VERSION 5.8 ;
BUSBITCHARS "[]" ;
DIVIDERCHAR "/" ;
UNITS
    DATABASE MICRONS 1000 ;
END UNITS

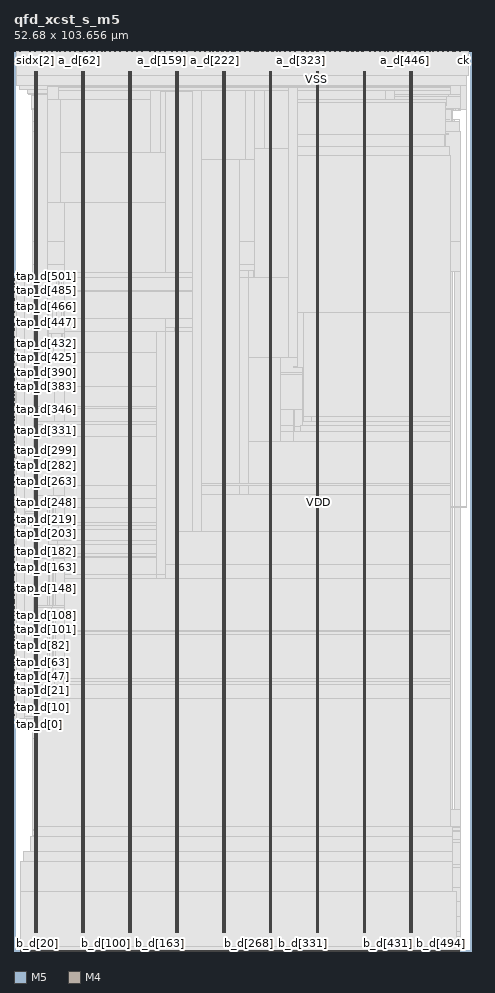
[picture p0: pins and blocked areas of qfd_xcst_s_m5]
MACRO qfd_xcst_s_m5
  FOREIGN qfd_xcst_s_m5 0 0 ;
  CLASS BLOCK ;
  SIZE 52.68 BY 103.656 ;
  PIN a_d[0]
    DIRECTION INPUT ;
    USE SIGNAL ;
    PORT
      LAYER M5 ;
        RECT  1.44 103.572 1.464 103.656 ;
    END
  END a_d[0]
  PIN a_d[100]
    DIRECTION INPUT ;
    USE SIGNAL ;
    PORT
      LAYER M5 ;
        RECT  11.232 103.572 11.256 103.656 ;
    END
  END a_d[100]
  PIN a_d[101]
    DIRECTION INPUT ;
    USE SIGNAL ;
    PORT
      LAYER M5 ;
        RECT  11.328 103.572 11.352 103.656 ;
    END
  END a_d[101]
  PIN a_d[102]
    DIRECTION INPUT ;
    USE SIGNAL ;
    PORT
      LAYER M5 ;
        RECT  11.424 103.572 11.448 103.656 ;
    END
  END a_d[102]
  PIN a_d[103]
    DIRECTION INPUT ;
    USE SIGNAL ;
    PORT
      LAYER M5 ;
        RECT  11.52 103.572 11.544 103.656 ;
    END
  END a_d[103]
  PIN a_d[104]
    DIRECTION INPUT ;
    USE SIGNAL ;
    PORT
      LAYER M5 ;
        RECT  11.616 103.572 11.64 103.656 ;
    END
  END a_d[104]
  PIN a_d[105]
    DIRECTION INPUT ;
    USE SIGNAL ;
    PORT
      LAYER M5 ;
        RECT  11.712 103.572 11.736 103.656 ;
    END
  END a_d[105]
  PIN a_d[106]
    DIRECTION INPUT ;
    USE SIGNAL ;
    PORT
      LAYER M5 ;
        RECT  11.808 103.572 11.832 103.656 ;
    END
  END a_d[106]
  PIN a_d[107]
    DIRECTION INPUT ;
    USE SIGNAL ;
    PORT
      LAYER M5 ;
        RECT  11.904 103.572 11.928 103.656 ;
    END
  END a_d[107]
  PIN a_d[108]
    DIRECTION INPUT ;
    USE SIGNAL ;
    PORT
      LAYER M5 ;
        RECT  12 103.572 12.024 103.656 ;
    END
  END a_d[108]
  PIN a_d[109]
    DIRECTION INPUT ;
    USE SIGNAL ;
    PORT
      LAYER M5 ;
        RECT  12.096 103.572 12.12 103.656 ;
    END
  END a_d[109]
  PIN a_d[10]
    DIRECTION INPUT ;
    USE SIGNAL ;
    PORT
      LAYER M5 ;
        RECT  2.4 103.572 2.424 103.656 ;
    END
  END a_d[10]
  PIN a_d[110]
    DIRECTION INPUT ;
    USE SIGNAL ;
    PORT
      LAYER M5 ;
        RECT  12.192 103.572 12.216 103.656 ;
    END
  END a_d[110]
  PIN a_d[111]
    DIRECTION INPUT ;
    USE SIGNAL ;
    PORT
      LAYER M5 ;
        RECT  12.288 103.572 12.312 103.656 ;
    END
  END a_d[111]
  PIN a_d[112]
    DIRECTION INPUT ;
    USE SIGNAL ;
    PORT
      LAYER M5 ;
        RECT  12.384 103.572 12.408 103.656 ;
    END
  END a_d[112]
  PIN a_d[113]
    DIRECTION INPUT ;
    USE SIGNAL ;
    PORT
      LAYER M5 ;
        RECT  12.48 103.572 12.504 103.656 ;
    END
  END a_d[113]
  PIN a_d[114]
    DIRECTION INPUT ;
    USE SIGNAL ;
    PORT
      LAYER M5 ;
        RECT  12.576 103.572 12.6 103.656 ;
    END
  END a_d[114]
  PIN a_d[115]
    DIRECTION INPUT ;
    USE SIGNAL ;
    PORT
      LAYER M5 ;
        RECT  12.672 103.572 12.696 103.656 ;
    END
  END a_d[115]
  PIN a_d[116]
    DIRECTION INPUT ;
    USE SIGNAL ;
    PORT
      LAYER M5 ;
        RECT  12.816 103.572 12.84 103.656 ;
    END
  END a_d[116]
  PIN a_d[117]
    DIRECTION INPUT ;
    USE SIGNAL ;
    PORT
      LAYER M5 ;
        RECT  12.912 103.572 12.936 103.656 ;
    END
  END a_d[117]
  PIN a_d[118]
    DIRECTION INPUT ;
    USE SIGNAL ;
    PORT
      LAYER M5 ;
        RECT  13.008 103.572 13.032 103.656 ;
    END
  END a_d[118]
  PIN a_d[119]
    DIRECTION INPUT ;
    USE SIGNAL ;
    PORT
      LAYER M5 ;
        RECT  13.104 103.572 13.128 103.656 ;
    END
  END a_d[119]
  PIN a_d[11]
    DIRECTION INPUT ;
    USE SIGNAL ;
    PORT
      LAYER M5 ;
        RECT  2.496 103.572 2.52 103.656 ;
    END
  END a_d[11]
  PIN a_d[120]
    DIRECTION INPUT ;
    USE SIGNAL ;
    PORT
      LAYER M5 ;
        RECT  13.2 103.572 13.224 103.656 ;
    END
  END a_d[120]
  PIN a_d[121]
    DIRECTION INPUT ;
    USE SIGNAL ;
    PORT
      LAYER M5 ;
        RECT  13.296 103.572 13.32 103.656 ;
    END
  END a_d[121]
  PIN a_d[122]
    DIRECTION INPUT ;
    USE SIGNAL ;
    PORT
      LAYER M5 ;
        RECT  13.392 103.572 13.416 103.656 ;
    END
  END a_d[122]
  PIN a_d[123]
    DIRECTION INPUT ;
    USE SIGNAL ;
    PORT
      LAYER M5 ;
        RECT  13.488 103.572 13.512 103.656 ;
    END
  END a_d[123]
  PIN a_d[124]
    DIRECTION INPUT ;
    USE SIGNAL ;
    PORT
      LAYER M5 ;
        RECT  13.584 103.572 13.608 103.656 ;
    END
  END a_d[124]
  PIN a_d[125]
    DIRECTION INPUT ;
    USE SIGNAL ;
    PORT
      LAYER M5 ;
        RECT  13.68 103.572 13.704 103.656 ;
    END
  END a_d[125]
  PIN a_d[126]
    DIRECTION INPUT ;
    USE SIGNAL ;
    PORT
      LAYER M5 ;
        RECT  13.776 103.572 13.8 103.656 ;
    END
  END a_d[126]
  PIN a_d[127]
    DIRECTION INPUT ;
    USE SIGNAL ;
    PORT
      LAYER M5 ;
        RECT  13.872 103.572 13.896 103.656 ;
    END
  END a_d[127]
  PIN a_d[128]
    DIRECTION INPUT ;
    USE SIGNAL ;
    PORT
      LAYER M5 ;
        RECT  13.968 103.572 13.992 103.656 ;
    END
  END a_d[128]
  PIN a_d[129]
    DIRECTION INPUT ;
    USE SIGNAL ;
    PORT
      LAYER M5 ;
        RECT  14.064 103.572 14.088 103.656 ;
    END
  END a_d[129]
  PIN a_d[12]
    DIRECTION INPUT ;
    USE SIGNAL ;
    PORT
      LAYER M5 ;
        RECT  2.592 103.572 2.616 103.656 ;
    END
  END a_d[12]
  PIN a_d[130]
    DIRECTION INPUT ;
    USE SIGNAL ;
    PORT
      LAYER M5 ;
        RECT  14.16 103.572 14.184 103.656 ;
    END
  END a_d[130]
  PIN a_d[131]
    DIRECTION INPUT ;
    USE SIGNAL ;
    PORT
      LAYER M5 ;
        RECT  14.256 103.572 14.28 103.656 ;
    END
  END a_d[131]
  PIN a_d[132]
    DIRECTION INPUT ;
    USE SIGNAL ;
    PORT
      LAYER M5 ;
        RECT  14.352 103.572 14.376 103.656 ;
    END
  END a_d[132]
  PIN a_d[133]
    DIRECTION INPUT ;
    USE SIGNAL ;
    PORT
      LAYER M5 ;
        RECT  14.448 103.572 14.472 103.656 ;
    END
  END a_d[133]
  PIN a_d[134]
    DIRECTION INPUT ;
    USE SIGNAL ;
    PORT
      LAYER M5 ;
        RECT  14.544 103.572 14.568 103.656 ;
    END
  END a_d[134]
  PIN a_d[135]
    DIRECTION INPUT ;
    USE SIGNAL ;
    PORT
      LAYER M5 ;
        RECT  14.64 103.572 14.664 103.656 ;
    END
  END a_d[135]
  PIN a_d[136]
    DIRECTION INPUT ;
    USE SIGNAL ;
    PORT
      LAYER M5 ;
        RECT  14.736 103.572 14.76 103.656 ;
    END
  END a_d[136]
  PIN a_d[137]
    DIRECTION INPUT ;
    USE SIGNAL ;
    PORT
      LAYER M5 ;
        RECT  14.832 103.572 14.856 103.656 ;
    END
  END a_d[137]
  PIN a_d[138]
    DIRECTION INPUT ;
    USE SIGNAL ;
    PORT
      LAYER M5 ;
        RECT  14.928 103.572 14.952 103.656 ;
    END
  END a_d[138]
  PIN a_d[139]
    DIRECTION INPUT ;
    USE SIGNAL ;
    PORT
      LAYER M5 ;
        RECT  15.024 103.572 15.048 103.656 ;
    END
  END a_d[139]
  PIN a_d[13]
    DIRECTION INPUT ;
    USE SIGNAL ;
    PORT
      LAYER M5 ;
        RECT  2.736 103.572 2.76 103.656 ;
    END
  END a_d[13]
  PIN a_d[140]
    DIRECTION INPUT ;
    USE SIGNAL ;
    PORT
      LAYER M5 ;
        RECT  15.12 103.572 15.144 103.656 ;
    END
  END a_d[140]
  PIN a_d[141]
    DIRECTION INPUT ;
    USE SIGNAL ;
    PORT
      LAYER M5 ;
        RECT  15.216 103.572 15.24 103.656 ;
    END
  END a_d[141]
  PIN a_d[142]
    DIRECTION INPUT ;
    USE SIGNAL ;
    PORT
      LAYER M5 ;
        RECT  15.36 103.572 15.384 103.656 ;
    END
  END a_d[142]
  PIN a_d[143]
    DIRECTION INPUT ;
    USE SIGNAL ;
    PORT
      LAYER M5 ;
        RECT  15.456 103.572 15.48 103.656 ;
    END
  END a_d[143]
  PIN a_d[144]
    DIRECTION INPUT ;
    USE SIGNAL ;
    PORT
      LAYER M5 ;
        RECT  15.552 103.572 15.576 103.656 ;
    END
  END a_d[144]
  PIN a_d[145]
    DIRECTION INPUT ;
    USE SIGNAL ;
    PORT
      LAYER M5 ;
        RECT  15.648 103.572 15.672 103.656 ;
    END
  END a_d[145]
  PIN a_d[146]
    DIRECTION INPUT ;
    USE SIGNAL ;
    PORT
      LAYER M5 ;
        RECT  15.744 103.572 15.768 103.656 ;
    END
  END a_d[146]
  PIN a_d[147]
    DIRECTION INPUT ;
    USE SIGNAL ;
    PORT
      LAYER M5 ;
        RECT  15.84 103.572 15.864 103.656 ;
    END
  END a_d[147]
  PIN a_d[148]
    DIRECTION INPUT ;
    USE SIGNAL ;
    PORT
      LAYER M5 ;
        RECT  15.936 103.572 15.96 103.656 ;
    END
  END a_d[148]
  PIN a_d[149]
    DIRECTION INPUT ;
    USE SIGNAL ;
    PORT
      LAYER M5 ;
        RECT  16.032 103.572 16.056 103.656 ;
    END
  END a_d[149]
  PIN a_d[14]
    DIRECTION INPUT ;
    USE SIGNAL ;
    PORT
      LAYER M5 ;
        RECT  2.832 103.572 2.856 103.656 ;
    END
  END a_d[14]
  PIN a_d[150]
    DIRECTION INPUT ;
    USE SIGNAL ;
    PORT
      LAYER M5 ;
        RECT  16.128 103.572 16.152 103.656 ;
    END
  END a_d[150]
  PIN a_d[151]
    DIRECTION INPUT ;
    USE SIGNAL ;
    PORT
      LAYER M5 ;
        RECT  16.224 103.572 16.248 103.656 ;
    END
  END a_d[151]
  PIN a_d[152]
    DIRECTION INPUT ;
    USE SIGNAL ;
    PORT
      LAYER M5 ;
        RECT  16.32 103.572 16.344 103.656 ;
    END
  END a_d[152]
  PIN a_d[153]
    DIRECTION INPUT ;
    USE SIGNAL ;
    PORT
      LAYER M5 ;
        RECT  16.416 103.572 16.44 103.656 ;
    END
  END a_d[153]
  PIN a_d[154]
    DIRECTION INPUT ;
    USE SIGNAL ;
    PORT
      LAYER M5 ;
        RECT  16.512 103.572 16.536 103.656 ;
    END
  END a_d[154]
  PIN a_d[155]
    DIRECTION INPUT ;
    USE SIGNAL ;
    PORT
      LAYER M5 ;
        RECT  16.608 103.572 16.632 103.656 ;
    END
  END a_d[155]
  PIN a_d[156]
    DIRECTION INPUT ;
    USE SIGNAL ;
    PORT
      LAYER M5 ;
        RECT  16.704 103.572 16.728 103.656 ;
    END
  END a_d[156]
  PIN a_d[157]
    DIRECTION INPUT ;
    USE SIGNAL ;
    PORT
      LAYER M5 ;
        RECT  16.8 103.572 16.824 103.656 ;
    END
  END a_d[157]
  PIN a_d[158]
    DIRECTION INPUT ;
    USE SIGNAL ;
    PORT
      LAYER M5 ;
        RECT  16.896 103.572 16.92 103.656 ;
    END
  END a_d[158]
  PIN a_d[159]
    DIRECTION INPUT ;
    USE SIGNAL ;
    PORT
      LAYER M5 ;
        RECT  16.992 103.572 17.016 103.656 ;
    END
  END a_d[159]
  PIN a_d[15]
    DIRECTION INPUT ;
    USE SIGNAL ;
    PORT
      LAYER M5 ;
        RECT  2.928 103.572 2.952 103.656 ;
    END
  END a_d[15]
  PIN a_d[160]
    DIRECTION INPUT ;
    USE SIGNAL ;
    PORT
      LAYER M5 ;
        RECT  17.088 103.572 17.112 103.656 ;
    END
  END a_d[160]
  PIN a_d[161]
    DIRECTION INPUT ;
    USE SIGNAL ;
    PORT
      LAYER M5 ;
        RECT  17.184 103.572 17.208 103.656 ;
    END
  END a_d[161]
  PIN a_d[162]
    DIRECTION INPUT ;
    USE SIGNAL ;
    PORT
      LAYER M5 ;
        RECT  17.28 103.572 17.304 103.656 ;
    END
  END a_d[162]
  PIN a_d[163]
    DIRECTION INPUT ;
    USE SIGNAL ;
    PORT
      LAYER M5 ;
        RECT  17.376 103.572 17.4 103.656 ;
    END
  END a_d[163]
  PIN a_d[164]
    DIRECTION INPUT ;
    USE SIGNAL ;
    PORT
      LAYER M5 ;
        RECT  17.472 103.572 17.496 103.656 ;
    END
  END a_d[164]
  PIN a_d[165]
    DIRECTION INPUT ;
    USE SIGNAL ;
    PORT
      LAYER M5 ;
        RECT  17.568 103.572 17.592 103.656 ;
    END
  END a_d[165]
  PIN a_d[166]
    DIRECTION INPUT ;
    USE SIGNAL ;
    PORT
      LAYER M5 ;
        RECT  17.664 103.572 17.688 103.656 ;
    END
  END a_d[166]
  PIN a_d[167]
    DIRECTION INPUT ;
    USE SIGNAL ;
    PORT
      LAYER M5 ;
        RECT  17.808 103.572 17.832 103.656 ;
    END
  END a_d[167]
  PIN a_d[168]
    DIRECTION INPUT ;
    USE SIGNAL ;
    PORT
      LAYER M5 ;
        RECT  17.904 103.572 17.928 103.656 ;
    END
  END a_d[168]
  PIN a_d[169]
    DIRECTION INPUT ;
    USE SIGNAL ;
    PORT
      LAYER M5 ;
        RECT  18 103.572 18.024 103.656 ;
    END
  END a_d[169]
  PIN a_d[16]
    DIRECTION INPUT ;
    USE SIGNAL ;
    PORT
      LAYER M5 ;
        RECT  3.024 103.572 3.048 103.656 ;
    END
  END a_d[16]
  PIN a_d[170]
    DIRECTION INPUT ;
    USE SIGNAL ;
    PORT
      LAYER M5 ;
        RECT  18.096 103.572 18.12 103.656 ;
    END
  END a_d[170]
  PIN a_d[171]
    DIRECTION INPUT ;
    USE SIGNAL ;
    PORT
      LAYER M5 ;
        RECT  18.192 103.572 18.216 103.656 ;
    END
  END a_d[171]
  PIN a_d[172]
    DIRECTION INPUT ;
    USE SIGNAL ;
    PORT
      LAYER M5 ;
        RECT  18.288 103.572 18.312 103.656 ;
    END
  END a_d[172]
  PIN a_d[173]
    DIRECTION INPUT ;
    USE SIGNAL ;
    PORT
      LAYER M5 ;
        RECT  18.384 103.572 18.408 103.656 ;
    END
  END a_d[173]
  PIN a_d[174]
    DIRECTION INPUT ;
    USE SIGNAL ;
    PORT
      LAYER M5 ;
        RECT  18.48 103.572 18.504 103.656 ;
    END
  END a_d[174]
  PIN a_d[175]
    DIRECTION INPUT ;
    USE SIGNAL ;
    PORT
      LAYER M5 ;
        RECT  18.576 103.572 18.6 103.656 ;
    END
  END a_d[175]
  PIN a_d[176]
    DIRECTION INPUT ;
    USE SIGNAL ;
    PORT
      LAYER M5 ;
        RECT  18.672 103.572 18.696 103.656 ;
    END
  END a_d[176]
  PIN a_d[177]
    DIRECTION INPUT ;
    USE SIGNAL ;
    PORT
      LAYER M5 ;
        RECT  18.768 103.572 18.792 103.656 ;
    END
  END a_d[177]
  PIN a_d[178]
    DIRECTION INPUT ;
    USE SIGNAL ;
    PORT
      LAYER M5 ;
        RECT  18.864 103.572 18.888 103.656 ;
    END
  END a_d[178]
  PIN a_d[179]
    DIRECTION INPUT ;
    USE SIGNAL ;
    PORT
      LAYER M5 ;
        RECT  18.96 103.572 18.984 103.656 ;
    END
  END a_d[179]
  PIN a_d[17]
    DIRECTION INPUT ;
    USE SIGNAL ;
    PORT
      LAYER M5 ;
        RECT  3.12 103.572 3.144 103.656 ;
    END
  END a_d[17]
  PIN a_d[180]
    DIRECTION INPUT ;
    USE SIGNAL ;
    PORT
      LAYER M5 ;
        RECT  19.056 103.572 19.08 103.656 ;
    END
  END a_d[180]
  PIN a_d[181]
    DIRECTION INPUT ;
    USE SIGNAL ;
    PORT
      LAYER M5 ;
        RECT  19.152 103.572 19.176 103.656 ;
    END
  END a_d[181]
  PIN a_d[182]
    DIRECTION INPUT ;
    USE SIGNAL ;
    PORT
      LAYER M5 ;
        RECT  19.248 103.572 19.272 103.656 ;
    END
  END a_d[182]
  PIN a_d[183]
    DIRECTION INPUT ;
    USE SIGNAL ;
    PORT
      LAYER M5 ;
        RECT  19.344 103.572 19.368 103.656 ;
    END
  END a_d[183]
  PIN a_d[184]
    DIRECTION INPUT ;
    USE SIGNAL ;
    PORT
      LAYER M5 ;
        RECT  19.44 103.572 19.464 103.656 ;
    END
  END a_d[184]
  PIN a_d[185]
    DIRECTION INPUT ;
    USE SIGNAL ;
    PORT
      LAYER M5 ;
        RECT  19.536 103.572 19.56 103.656 ;
    END
  END a_d[185]
  PIN a_d[186]
    DIRECTION INPUT ;
    USE SIGNAL ;
    PORT
      LAYER M5 ;
        RECT  19.632 103.572 19.656 103.656 ;
    END
  END a_d[186]
  PIN a_d[187]
    DIRECTION INPUT ;
    USE SIGNAL ;
    PORT
      LAYER M5 ;
        RECT  19.728 103.572 19.752 103.656 ;
    END
  END a_d[187]
  PIN a_d[188]
    DIRECTION INPUT ;
    USE SIGNAL ;
    PORT
      LAYER M5 ;
        RECT  19.824 103.572 19.848 103.656 ;
    END
  END a_d[188]
  PIN a_d[189]
    DIRECTION INPUT ;
    USE SIGNAL ;
    PORT
      LAYER M5 ;
        RECT  19.92 103.572 19.944 103.656 ;
    END
  END a_d[189]
  PIN a_d[18]
    DIRECTION INPUT ;
    USE SIGNAL ;
    PORT
      LAYER M5 ;
        RECT  3.216 103.572 3.24 103.656 ;
    END
  END a_d[18]
  PIN a_d[190]
    DIRECTION INPUT ;
    USE SIGNAL ;
    PORT
      LAYER M5 ;
        RECT  20.016 103.572 20.04 103.656 ;
    END
  END a_d[190]
  PIN a_d[191]
    DIRECTION INPUT ;
    USE SIGNAL ;
    PORT
      LAYER M5 ;
        RECT  20.112 103.572 20.136 103.656 ;
    END
  END a_d[191]
  PIN a_d[192]
    DIRECTION INPUT ;
    USE SIGNAL ;
    PORT
      LAYER M5 ;
        RECT  20.208 103.572 20.232 103.656 ;
    END
  END a_d[192]
  PIN a_d[193]
    DIRECTION INPUT ;
    USE SIGNAL ;
    PORT
      LAYER M5 ;
        RECT  20.352 103.572 20.376 103.656 ;
    END
  END a_d[193]
  PIN a_d[194]
    DIRECTION INPUT ;
    USE SIGNAL ;
    PORT
      LAYER M5 ;
        RECT  20.448 103.572 20.472 103.656 ;
    END
  END a_d[194]
  PIN a_d[195]
    DIRECTION INPUT ;
    USE SIGNAL ;
    PORT
      LAYER M5 ;
        RECT  20.544 103.572 20.568 103.656 ;
    END
  END a_d[195]
  PIN a_d[196]
    DIRECTION INPUT ;
    USE SIGNAL ;
    PORT
      LAYER M5 ;
        RECT  20.64 103.572 20.664 103.656 ;
    END
  END a_d[196]
  PIN a_d[197]
    DIRECTION INPUT ;
    USE SIGNAL ;
    PORT
      LAYER M5 ;
        RECT  20.736 103.572 20.76 103.656 ;
    END
  END a_d[197]
  PIN a_d[198]
    DIRECTION INPUT ;
    USE SIGNAL ;
    PORT
      LAYER M5 ;
        RECT  20.832 103.572 20.856 103.656 ;
    END
  END a_d[198]
  PIN a_d[199]
    DIRECTION INPUT ;
    USE SIGNAL ;
    PORT
      LAYER M5 ;
        RECT  20.928 103.572 20.952 103.656 ;
    END
  END a_d[199]
  PIN a_d[19]
    DIRECTION INPUT ;
    USE SIGNAL ;
    PORT
      LAYER M5 ;
        RECT  3.312 103.572 3.336 103.656 ;
    END
  END a_d[19]
  PIN a_d[1]
    DIRECTION INPUT ;
    USE SIGNAL ;
    PORT
      LAYER M5 ;
        RECT  1.536 103.572 1.56 103.656 ;
    END
  END a_d[1]
  PIN a_d[200]
    DIRECTION INPUT ;
    USE SIGNAL ;
    PORT
      LAYER M5 ;
        RECT  21.024 103.572 21.048 103.656 ;
    END
  END a_d[200]
  PIN a_d[201]
    DIRECTION INPUT ;
    USE SIGNAL ;
    PORT
      LAYER M5 ;
        RECT  21.12 103.572 21.144 103.656 ;
    END
  END a_d[201]
  PIN a_d[202]
    DIRECTION INPUT ;
    USE SIGNAL ;
    PORT
      LAYER M5 ;
        RECT  21.216 103.572 21.24 103.656 ;
    END
  END a_d[202]
  PIN a_d[203]
    DIRECTION INPUT ;
    USE SIGNAL ;
    PORT
      LAYER M5 ;
        RECT  21.312 103.572 21.336 103.656 ;
    END
  END a_d[203]
  PIN a_d[204]
    DIRECTION INPUT ;
    USE SIGNAL ;
    PORT
      LAYER M5 ;
        RECT  21.408 103.572 21.432 103.656 ;
    END
  END a_d[204]
  PIN a_d[205]
    DIRECTION INPUT ;
    USE SIGNAL ;
    PORT
      LAYER M5 ;
        RECT  21.504 103.572 21.528 103.656 ;
    END
  END a_d[205]
  PIN a_d[206]
    DIRECTION INPUT ;
    USE SIGNAL ;
    PORT
      LAYER M5 ;
        RECT  21.6 103.572 21.624 103.656 ;
    END
  END a_d[206]
  PIN a_d[207]
    DIRECTION INPUT ;
    USE SIGNAL ;
    PORT
      LAYER M5 ;
        RECT  21.696 103.572 21.72 103.656 ;
    END
  END a_d[207]
  PIN a_d[208]
    DIRECTION INPUT ;
    USE SIGNAL ;
    PORT
      LAYER M5 ;
        RECT  21.792 103.572 21.816 103.656 ;
    END
  END a_d[208]
  PIN a_d[209]
    DIRECTION INPUT ;
    USE SIGNAL ;
    PORT
      LAYER M5 ;
        RECT  21.888 103.572 21.912 103.656 ;
    END
  END a_d[209]
  PIN a_d[20]
    DIRECTION INPUT ;
    USE SIGNAL ;
    PORT
      LAYER M5 ;
        RECT  3.408 103.572 3.432 103.656 ;
    END
  END a_d[20]
  PIN a_d[210]
    DIRECTION INPUT ;
    USE SIGNAL ;
    PORT
      LAYER M5 ;
        RECT  21.984 103.572 22.008 103.656 ;
    END
  END a_d[210]
  PIN a_d[211]
    DIRECTION INPUT ;
    USE SIGNAL ;
    PORT
      LAYER M5 ;
        RECT  22.08 103.572 22.104 103.656 ;
    END
  END a_d[211]
  PIN a_d[212]
    DIRECTION INPUT ;
    USE SIGNAL ;
    PORT
      LAYER M5 ;
        RECT  22.176 103.572 22.2 103.656 ;
    END
  END a_d[212]
  PIN a_d[213]
    DIRECTION INPUT ;
    USE SIGNAL ;
    PORT
      LAYER M5 ;
        RECT  22.272 103.572 22.296 103.656 ;
    END
  END a_d[213]
  PIN a_d[214]
    DIRECTION INPUT ;
    USE SIGNAL ;
    PORT
      LAYER M5 ;
        RECT  22.368 103.572 22.392 103.656 ;
    END
  END a_d[214]
  PIN a_d[215]
    DIRECTION INPUT ;
    USE SIGNAL ;
    PORT
      LAYER M5 ;
        RECT  22.464 103.572 22.488 103.656 ;
    END
  END a_d[215]
  PIN a_d[216]
    DIRECTION INPUT ;
    USE SIGNAL ;
    PORT
      LAYER M5 ;
        RECT  22.56 103.572 22.584 103.656 ;
    END
  END a_d[216]
  PIN a_d[217]
    DIRECTION INPUT ;
    USE SIGNAL ;
    PORT
      LAYER M5 ;
        RECT  22.656 103.572 22.68 103.656 ;
    END
  END a_d[217]
  PIN a_d[218]
    DIRECTION INPUT ;
    USE SIGNAL ;
    PORT
      LAYER M5 ;
        RECT  22.752 103.572 22.776 103.656 ;
    END
  END a_d[218]
  PIN a_d[219]
    DIRECTION INPUT ;
    USE SIGNAL ;
    PORT
      LAYER M5 ;
        RECT  22.896 103.572 22.92 103.656 ;
    END
  END a_d[219]
  PIN a_d[21]
    DIRECTION INPUT ;
    USE SIGNAL ;
    PORT
      LAYER M5 ;
        RECT  3.504 103.572 3.528 103.656 ;
    END
  END a_d[21]
  PIN a_d[220]
    DIRECTION INPUT ;
    USE SIGNAL ;
    PORT
      LAYER M5 ;
        RECT  22.992 103.572 23.016 103.656 ;
    END
  END a_d[220]
  PIN a_d[221]
    DIRECTION INPUT ;
    USE SIGNAL ;
    PORT
      LAYER M5 ;
        RECT  23.088 103.572 23.112 103.656 ;
    END
  END a_d[221]
  PIN a_d[222]
    DIRECTION INPUT ;
    USE SIGNAL ;
    PORT
      LAYER M5 ;
        RECT  23.184 103.572 23.208 103.656 ;
    END
  END a_d[222]
  PIN a_d[223]
    DIRECTION INPUT ;
    USE SIGNAL ;
    PORT
      LAYER M5 ;
        RECT  23.28 103.572 23.304 103.656 ;
    END
  END a_d[223]
  PIN a_d[224]
    DIRECTION INPUT ;
    USE SIGNAL ;
    PORT
      LAYER M5 ;
        RECT  23.376 103.572 23.4 103.656 ;
    END
  END a_d[224]
  PIN a_d[225]
    DIRECTION INPUT ;
    USE SIGNAL ;
    PORT
      LAYER M5 ;
        RECT  23.472 103.572 23.496 103.656 ;
    END
  END a_d[225]
  PIN a_d[226]
    DIRECTION INPUT ;
    USE SIGNAL ;
    PORT
      LAYER M5 ;
        RECT  23.568 103.572 23.592 103.656 ;
    END
  END a_d[226]
  PIN a_d[227]
    DIRECTION INPUT ;
    USE SIGNAL ;
    PORT
      LAYER M5 ;
        RECT  23.664 103.572 23.688 103.656 ;
    END
  END a_d[227]
  PIN a_d[228]
    DIRECTION INPUT ;
    USE SIGNAL ;
    PORT
      LAYER M5 ;
        RECT  23.76 103.572 23.784 103.656 ;
    END
  END a_d[228]
  PIN a_d[229]
    DIRECTION INPUT ;
    USE SIGNAL ;
    PORT
      LAYER M5 ;
        RECT  23.856 103.572 23.88 103.656 ;
    END
  END a_d[229]
  PIN a_d[22]
    DIRECTION INPUT ;
    USE SIGNAL ;
    PORT
      LAYER M5 ;
        RECT  3.6 103.572 3.624 103.656 ;
    END
  END a_d[22]
  PIN a_d[230]
    DIRECTION INPUT ;
    USE SIGNAL ;
    PORT
      LAYER M5 ;
        RECT  23.952 103.572 23.976 103.656 ;
    END
  END a_d[230]
  PIN a_d[231]
    DIRECTION INPUT ;
    USE SIGNAL ;
    PORT
      LAYER M5 ;
        RECT  24.048 103.572 24.072 103.656 ;
    END
  END a_d[231]
  PIN a_d[232]
    DIRECTION INPUT ;
    USE SIGNAL ;
    PORT
      LAYER M5 ;
        RECT  24.144 103.572 24.168 103.656 ;
    END
  END a_d[232]
  PIN a_d[233]
    DIRECTION INPUT ;
    USE SIGNAL ;
    PORT
      LAYER M5 ;
        RECT  24.24 103.572 24.264 103.656 ;
    END
  END a_d[233]
  PIN a_d[234]
    DIRECTION INPUT ;
    USE SIGNAL ;
    PORT
      LAYER M5 ;
        RECT  24.336 103.572 24.36 103.656 ;
    END
  END a_d[234]
  PIN a_d[235]
    DIRECTION INPUT ;
    USE SIGNAL ;
    PORT
      LAYER M5 ;
        RECT  24.432 103.572 24.456 103.656 ;
    END
  END a_d[235]
  PIN a_d[236]
    DIRECTION INPUT ;
    USE SIGNAL ;
    PORT
      LAYER M5 ;
        RECT  24.528 103.572 24.552 103.656 ;
    END
  END a_d[236]
  PIN a_d[237]
    DIRECTION INPUT ;
    USE SIGNAL ;
    PORT
      LAYER M5 ;
        RECT  24.624 103.572 24.648 103.656 ;
    END
  END a_d[237]
  PIN a_d[238]
    DIRECTION INPUT ;
    USE SIGNAL ;
    PORT
      LAYER M5 ;
        RECT  24.72 103.572 24.744 103.656 ;
    END
  END a_d[238]
  PIN a_d[239]
    DIRECTION INPUT ;
    USE SIGNAL ;
    PORT
      LAYER M5 ;
        RECT  24.816 103.572 24.84 103.656 ;
    END
  END a_d[239]
  PIN a_d[23]
    DIRECTION INPUT ;
    USE SIGNAL ;
    PORT
      LAYER M5 ;
        RECT  3.696 103.572 3.72 103.656 ;
    END
  END a_d[23]
  PIN a_d[240]
    DIRECTION INPUT ;
    USE SIGNAL ;
    PORT
      LAYER M5 ;
        RECT  24.912 103.572 24.936 103.656 ;
    END
  END a_d[240]
  PIN a_d[241]
    DIRECTION INPUT ;
    USE SIGNAL ;
    PORT
      LAYER M5 ;
        RECT  25.008 103.572 25.032 103.656 ;
    END
  END a_d[241]
  PIN a_d[242]
    DIRECTION INPUT ;
    USE SIGNAL ;
    PORT
      LAYER M5 ;
        RECT  25.104 103.572 25.128 103.656 ;
    END
  END a_d[242]
  PIN a_d[243]
    DIRECTION INPUT ;
    USE SIGNAL ;
    PORT
      LAYER M5 ;
        RECT  25.2 103.572 25.224 103.656 ;
    END
  END a_d[243]
  PIN a_d[244]
    DIRECTION INPUT ;
    USE SIGNAL ;
    PORT
      LAYER M5 ;
        RECT  25.296 103.572 25.32 103.656 ;
    END
  END a_d[244]
  PIN a_d[245]
    DIRECTION INPUT ;
    USE SIGNAL ;
    PORT
      LAYER M5 ;
        RECT  25.44 103.572 25.464 103.656 ;
    END
  END a_d[245]
  PIN a_d[246]
    DIRECTION INPUT ;
    USE SIGNAL ;
    PORT
      LAYER M5 ;
        RECT  25.536 103.572 25.56 103.656 ;
    END
  END a_d[246]
  PIN a_d[247]
    DIRECTION INPUT ;
    USE SIGNAL ;
    PORT
      LAYER M5 ;
        RECT  25.632 103.572 25.656 103.656 ;
    END
  END a_d[247]
  PIN a_d[248]
    DIRECTION INPUT ;
    USE SIGNAL ;
    PORT
      LAYER M5 ;
        RECT  25.728 103.572 25.752 103.656 ;
    END
  END a_d[248]
  PIN a_d[249]
    DIRECTION INPUT ;
    USE SIGNAL ;
    PORT
      LAYER M5 ;
        RECT  25.824 103.572 25.848 103.656 ;
    END
  END a_d[249]
  PIN a_d[24]
    DIRECTION INPUT ;
    USE SIGNAL ;
    PORT
      LAYER M5 ;
        RECT  3.792 103.572 3.816 103.656 ;
    END
  END a_d[24]
  PIN a_d[250]
    DIRECTION INPUT ;
    USE SIGNAL ;
    PORT
      LAYER M5 ;
        RECT  25.92 103.572 25.944 103.656 ;
    END
  END a_d[250]
  PIN a_d[251]
    DIRECTION INPUT ;
    USE SIGNAL ;
    PORT
      LAYER M5 ;
        RECT  26.016 103.572 26.04 103.656 ;
    END
  END a_d[251]
  PIN a_d[252]
    DIRECTION INPUT ;
    USE SIGNAL ;
    PORT
      LAYER M5 ;
        RECT  26.112 103.572 26.136 103.656 ;
    END
  END a_d[252]
  PIN a_d[253]
    DIRECTION INPUT ;
    USE SIGNAL ;
    PORT
      LAYER M5 ;
        RECT  26.208 103.572 26.232 103.656 ;
    END
  END a_d[253]
  PIN a_d[254]
    DIRECTION INPUT ;
    USE SIGNAL ;
    PORT
      LAYER M5 ;
        RECT  26.304 103.572 26.328 103.656 ;
    END
  END a_d[254]
  PIN a_d[255]
    DIRECTION INPUT ;
    USE SIGNAL ;
    PORT
      LAYER M5 ;
        RECT  26.4 103.572 26.424 103.656 ;
    END
  END a_d[255]
  PIN a_d[256]
    DIRECTION INPUT ;
    USE SIGNAL ;
    PORT
      LAYER M5 ;
        RECT  26.496 103.572 26.52 103.656 ;
    END
  END a_d[256]
  PIN a_d[257]
    DIRECTION INPUT ;
    USE SIGNAL ;
    PORT
      LAYER M5 ;
        RECT  26.592 103.572 26.616 103.656 ;
    END
  END a_d[257]
  PIN a_d[258]
    DIRECTION INPUT ;
    USE SIGNAL ;
    PORT
      LAYER M5 ;
        RECT  26.688 103.572 26.712 103.656 ;
    END
  END a_d[258]
  PIN a_d[259]
    DIRECTION INPUT ;
    USE SIGNAL ;
    PORT
      LAYER M5 ;
        RECT  26.784 103.572 26.808 103.656 ;
    END
  END a_d[259]
  PIN a_d[25]
    DIRECTION INPUT ;
    USE SIGNAL ;
    PORT
      LAYER M5 ;
        RECT  3.888 103.572 3.912 103.656 ;
    END
  END a_d[25]
  PIN a_d[260]
    DIRECTION INPUT ;
    USE SIGNAL ;
    PORT
      LAYER M5 ;
        RECT  26.88 103.572 26.904 103.656 ;
    END
  END a_d[260]
  PIN a_d[261]
    DIRECTION INPUT ;
    USE SIGNAL ;
    PORT
      LAYER M5 ;
        RECT  26.976 103.572 27 103.656 ;
    END
  END a_d[261]
  PIN a_d[262]
    DIRECTION INPUT ;
    USE SIGNAL ;
    PORT
      LAYER M5 ;
        RECT  27.072 103.572 27.096 103.656 ;
    END
  END a_d[262]
  PIN a_d[263]
    DIRECTION INPUT ;
    USE SIGNAL ;
    PORT
      LAYER M5 ;
        RECT  27.168 103.572 27.192 103.656 ;
    END
  END a_d[263]
  PIN a_d[264]
    DIRECTION INPUT ;
    USE SIGNAL ;
    PORT
      LAYER M5 ;
        RECT  27.264 103.572 27.288 103.656 ;
    END
  END a_d[264]
  PIN a_d[265]
    DIRECTION INPUT ;
    USE SIGNAL ;
    PORT
      LAYER M5 ;
        RECT  27.36 103.572 27.384 103.656 ;
    END
  END a_d[265]
  PIN a_d[266]
    DIRECTION INPUT ;
    USE SIGNAL ;
    PORT
      LAYER M5 ;
        RECT  27.456 103.572 27.48 103.656 ;
    END
  END a_d[266]
  PIN a_d[267]
    DIRECTION INPUT ;
    USE SIGNAL ;
    PORT
      LAYER M5 ;
        RECT  27.552 103.572 27.576 103.656 ;
    END
  END a_d[267]
  PIN a_d[268]
    DIRECTION INPUT ;
    USE SIGNAL ;
    PORT
      LAYER M5 ;
        RECT  27.648 103.572 27.672 103.656 ;
    END
  END a_d[268]
  PIN a_d[269]
    DIRECTION INPUT ;
    USE SIGNAL ;
    PORT
      LAYER M5 ;
        RECT  27.744 103.572 27.768 103.656 ;
    END
  END a_d[269]
  PIN a_d[26]
    DIRECTION INPUT ;
    USE SIGNAL ;
    PORT
      LAYER M5 ;
        RECT  3.984 103.572 4.008 103.656 ;
    END
  END a_d[26]
  PIN a_d[270]
    DIRECTION INPUT ;
    USE SIGNAL ;
    PORT
      LAYER M5 ;
        RECT  27.84 103.572 27.864 103.656 ;
    END
  END a_d[270]
  PIN a_d[271]
    DIRECTION INPUT ;
    USE SIGNAL ;
    PORT
      LAYER M5 ;
        RECT  27.984 103.572 28.008 103.656 ;
    END
  END a_d[271]
  PIN a_d[272]
    DIRECTION INPUT ;
    USE SIGNAL ;
    PORT
      LAYER M5 ;
        RECT  28.08 103.572 28.104 103.656 ;
    END
  END a_d[272]
  PIN a_d[273]
    DIRECTION INPUT ;
    USE SIGNAL ;
    PORT
      LAYER M5 ;
        RECT  28.176 103.572 28.2 103.656 ;
    END
  END a_d[273]
  PIN a_d[274]
    DIRECTION INPUT ;
    USE SIGNAL ;
    PORT
      LAYER M5 ;
        RECT  28.272 103.572 28.296 103.656 ;
    END
  END a_d[274]
  PIN a_d[275]
    DIRECTION INPUT ;
    USE SIGNAL ;
    PORT
      LAYER M5 ;
        RECT  28.368 103.572 28.392 103.656 ;
    END
  END a_d[275]
  PIN a_d[276]
    DIRECTION INPUT ;
    USE SIGNAL ;
    PORT
      LAYER M5 ;
        RECT  28.464 103.572 28.488 103.656 ;
    END
  END a_d[276]
  PIN a_d[277]
    DIRECTION INPUT ;
    USE SIGNAL ;
    PORT
      LAYER M5 ;
        RECT  28.56 103.572 28.584 103.656 ;
    END
  END a_d[277]
  PIN a_d[278]
    DIRECTION INPUT ;
    USE SIGNAL ;
    PORT
      LAYER M5 ;
        RECT  28.656 103.572 28.68 103.656 ;
    END
  END a_d[278]
  PIN a_d[279]
    DIRECTION INPUT ;
    USE SIGNAL ;
    PORT
      LAYER M5 ;
        RECT  28.752 103.572 28.776 103.656 ;
    END
  END a_d[279]
  PIN a_d[27]
    DIRECTION INPUT ;
    USE SIGNAL ;
    PORT
      LAYER M5 ;
        RECT  4.08 103.572 4.104 103.656 ;
    END
  END a_d[27]
  PIN a_d[280]
    DIRECTION INPUT ;
    USE SIGNAL ;
    PORT
      LAYER M5 ;
        RECT  28.848 103.572 28.872 103.656 ;
    END
  END a_d[280]
  PIN a_d[281]
    DIRECTION INPUT ;
    USE SIGNAL ;
    PORT
      LAYER M5 ;
        RECT  28.944 103.572 28.968 103.656 ;
    END
  END a_d[281]
  PIN a_d[282]
    DIRECTION INPUT ;
    USE SIGNAL ;
    PORT
      LAYER M5 ;
        RECT  29.04 103.572 29.064 103.656 ;
    END
  END a_d[282]
  PIN a_d[283]
    DIRECTION INPUT ;
    USE SIGNAL ;
    PORT
      LAYER M5 ;
        RECT  29.136 103.572 29.16 103.656 ;
    END
  END a_d[283]
  PIN a_d[284]
    DIRECTION INPUT ;
    USE SIGNAL ;
    PORT
      LAYER M5 ;
        RECT  29.232 103.572 29.256 103.656 ;
    END
  END a_d[284]
  PIN a_d[285]
    DIRECTION INPUT ;
    USE SIGNAL ;
    PORT
      LAYER M5 ;
        RECT  29.328 103.572 29.352 103.656 ;
    END
  END a_d[285]
  PIN a_d[286]
    DIRECTION INPUT ;
    USE SIGNAL ;
    PORT
      LAYER M5 ;
        RECT  29.424 103.572 29.448 103.656 ;
    END
  END a_d[286]
  PIN a_d[287]
    DIRECTION INPUT ;
    USE SIGNAL ;
    PORT
      LAYER M5 ;
        RECT  29.52 103.572 29.544 103.656 ;
    END
  END a_d[287]
  PIN a_d[288]
    DIRECTION INPUT ;
    USE SIGNAL ;
    PORT
      LAYER M5 ;
        RECT  29.616 103.572 29.64 103.656 ;
    END
  END a_d[288]
  PIN a_d[289]
    DIRECTION INPUT ;
    USE SIGNAL ;
    PORT
      LAYER M5 ;
        RECT  29.712 103.572 29.736 103.656 ;
    END
  END a_d[289]
  PIN a_d[28]
    DIRECTION INPUT ;
    USE SIGNAL ;
    PORT
      LAYER M5 ;
        RECT  4.176 103.572 4.2 103.656 ;
    END
  END a_d[28]
  PIN a_d[290]
    DIRECTION INPUT ;
    USE SIGNAL ;
    PORT
      LAYER M5 ;
        RECT  29.808 103.572 29.832 103.656 ;
    END
  END a_d[290]
  PIN a_d[291]
    DIRECTION INPUT ;
    USE SIGNAL ;
    PORT
      LAYER M5 ;
        RECT  29.904 103.572 29.928 103.656 ;
    END
  END a_d[291]
  PIN a_d[292]
    DIRECTION INPUT ;
    USE SIGNAL ;
    PORT
      LAYER M5 ;
        RECT  30 103.572 30.024 103.656 ;
    END
  END a_d[292]
  PIN a_d[293]
    DIRECTION INPUT ;
    USE SIGNAL ;
    PORT
      LAYER M5 ;
        RECT  30.096 103.572 30.12 103.656 ;
    END
  END a_d[293]
  PIN a_d[294]
    DIRECTION INPUT ;
    USE SIGNAL ;
    PORT
      LAYER M5 ;
        RECT  30.192 103.572 30.216 103.656 ;
    END
  END a_d[294]
  PIN a_d[295]
    DIRECTION INPUT ;
    USE SIGNAL ;
    PORT
      LAYER M5 ;
        RECT  30.288 103.572 30.312 103.656 ;
    END
  END a_d[295]
  PIN a_d[296]
    DIRECTION INPUT ;
    USE SIGNAL ;
    PORT
      LAYER M5 ;
        RECT  30.432 103.572 30.456 103.656 ;
    END
  END a_d[296]
  PIN a_d[297]
    DIRECTION INPUT ;
    USE SIGNAL ;
    PORT
      LAYER M5 ;
        RECT  30.528 103.572 30.552 103.656 ;
    END
  END a_d[297]
  PIN a_d[298]
    DIRECTION INPUT ;
    USE SIGNAL ;
    PORT
      LAYER M5 ;
        RECT  30.624 103.572 30.648 103.656 ;
    END
  END a_d[298]
  PIN a_d[299]
    DIRECTION INPUT ;
    USE SIGNAL ;
    PORT
      LAYER M5 ;
        RECT  30.72 103.572 30.744 103.656 ;
    END
  END a_d[299]
  PIN a_d[29]
    DIRECTION INPUT ;
    USE SIGNAL ;
    PORT
      LAYER M5 ;
        RECT  4.272 103.572 4.296 103.656 ;
    END
  END a_d[29]
  PIN a_d[2]
    DIRECTION INPUT ;
    USE SIGNAL ;
    PORT
      LAYER M5 ;
        RECT  1.632 103.572 1.656 103.656 ;
    END
  END a_d[2]
  PIN a_d[300]
    DIRECTION INPUT ;
    USE SIGNAL ;
    PORT
      LAYER M5 ;
        RECT  30.816 103.572 30.84 103.656 ;
    END
  END a_d[300]
  PIN a_d[301]
    DIRECTION INPUT ;
    USE SIGNAL ;
    PORT
      LAYER M5 ;
        RECT  30.912 103.572 30.936 103.656 ;
    END
  END a_d[301]
  PIN a_d[302]
    DIRECTION INPUT ;
    USE SIGNAL ;
    PORT
      LAYER M5 ;
        RECT  31.008 103.572 31.032 103.656 ;
    END
  END a_d[302]
  PIN a_d[303]
    DIRECTION INPUT ;
    USE SIGNAL ;
    PORT
      LAYER M5 ;
        RECT  31.104 103.572 31.128 103.656 ;
    END
  END a_d[303]
  PIN a_d[304]
    DIRECTION INPUT ;
    USE SIGNAL ;
    PORT
      LAYER M5 ;
        RECT  31.2 103.572 31.224 103.656 ;
    END
  END a_d[304]
  PIN a_d[305]
    DIRECTION INPUT ;
    USE SIGNAL ;
    PORT
      LAYER M5 ;
        RECT  31.296 103.572 31.32 103.656 ;
    END
  END a_d[305]
  PIN a_d[306]
    DIRECTION INPUT ;
    USE SIGNAL ;
    PORT
      LAYER M5 ;
        RECT  31.392 103.572 31.416 103.656 ;
    END
  END a_d[306]
  PIN a_d[307]
    DIRECTION INPUT ;
    USE SIGNAL ;
    PORT
      LAYER M5 ;
        RECT  31.488 103.572 31.512 103.656 ;
    END
  END a_d[307]
  PIN a_d[308]
    DIRECTION INPUT ;
    USE SIGNAL ;
    PORT
      LAYER M5 ;
        RECT  31.584 103.572 31.608 103.656 ;
    END
  END a_d[308]
  PIN a_d[309]
    DIRECTION INPUT ;
    USE SIGNAL ;
    PORT
      LAYER M5 ;
        RECT  31.68 103.572 31.704 103.656 ;
    END
  END a_d[309]
  PIN a_d[30]
    DIRECTION INPUT ;
    USE SIGNAL ;
    PORT
      LAYER M5 ;
        RECT  4.368 103.572 4.392 103.656 ;
    END
  END a_d[30]
  PIN a_d[310]
    DIRECTION INPUT ;
    USE SIGNAL ;
    PORT
      LAYER M5 ;
        RECT  31.776 103.572 31.8 103.656 ;
    END
  END a_d[310]
  PIN a_d[311]
    DIRECTION INPUT ;
    USE SIGNAL ;
    PORT
      LAYER M5 ;
        RECT  31.872 103.572 31.896 103.656 ;
    END
  END a_d[311]
  PIN a_d[312]
    DIRECTION INPUT ;
    USE SIGNAL ;
    PORT
      LAYER M5 ;
        RECT  31.968 103.572 31.992 103.656 ;
    END
  END a_d[312]
  PIN a_d[313]
    DIRECTION INPUT ;
    USE SIGNAL ;
    PORT
      LAYER M5 ;
        RECT  32.064 103.572 32.088 103.656 ;
    END
  END a_d[313]
  PIN a_d[314]
    DIRECTION INPUT ;
    USE SIGNAL ;
    PORT
      LAYER M5 ;
        RECT  32.16 103.572 32.184 103.656 ;
    END
  END a_d[314]
  PIN a_d[315]
    DIRECTION INPUT ;
    USE SIGNAL ;
    PORT
      LAYER M5 ;
        RECT  32.256 103.572 32.28 103.656 ;
    END
  END a_d[315]
  PIN a_d[316]
    DIRECTION INPUT ;
    USE SIGNAL ;
    PORT
      LAYER M5 ;
        RECT  32.352 103.572 32.376 103.656 ;
    END
  END a_d[316]
  PIN a_d[317]
    DIRECTION INPUT ;
    USE SIGNAL ;
    PORT
      LAYER M5 ;
        RECT  32.448 103.572 32.472 103.656 ;
    END
  END a_d[317]
  PIN a_d[318]
    DIRECTION INPUT ;
    USE SIGNAL ;
    PORT
      LAYER M5 ;
        RECT  32.544 103.572 32.568 103.656 ;
    END
  END a_d[318]
  PIN a_d[319]
    DIRECTION INPUT ;
    USE SIGNAL ;
    PORT
      LAYER M5 ;
        RECT  32.64 103.572 32.664 103.656 ;
    END
  END a_d[319]
  PIN a_d[31]
    DIRECTION INPUT ;
    USE SIGNAL ;
    PORT
      LAYER M5 ;
        RECT  4.464 103.572 4.488 103.656 ;
    END
  END a_d[31]
  PIN a_d[320]
    DIRECTION INPUT ;
    USE SIGNAL ;
    PORT
      LAYER M5 ;
        RECT  32.736 103.572 32.76 103.656 ;
    END
  END a_d[320]
  PIN a_d[321]
    DIRECTION INPUT ;
    USE SIGNAL ;
    PORT
      LAYER M5 ;
        RECT  32.832 103.572 32.856 103.656 ;
    END
  END a_d[321]
  PIN a_d[322]
    DIRECTION INPUT ;
    USE SIGNAL ;
    PORT
      LAYER M5 ;
        RECT  32.976 103.572 33 103.656 ;
    END
  END a_d[322]
  PIN a_d[323]
    DIRECTION INPUT ;
    USE SIGNAL ;
    PORT
      LAYER M5 ;
        RECT  33.072 103.572 33.096 103.656 ;
    END
  END a_d[323]
  PIN a_d[324]
    DIRECTION INPUT ;
    USE SIGNAL ;
    PORT
      LAYER M5 ;
        RECT  33.168 103.572 33.192 103.656 ;
    END
  END a_d[324]
  PIN a_d[325]
    DIRECTION INPUT ;
    USE SIGNAL ;
    PORT
      LAYER M5 ;
        RECT  33.264 103.572 33.288 103.656 ;
    END
  END a_d[325]
  PIN a_d[326]
    DIRECTION INPUT ;
    USE SIGNAL ;
    PORT
      LAYER M5 ;
        RECT  33.36 103.572 33.384 103.656 ;
    END
  END a_d[326]
  PIN a_d[327]
    DIRECTION INPUT ;
    USE SIGNAL ;
    PORT
      LAYER M5 ;
        RECT  33.456 103.572 33.48 103.656 ;
    END
  END a_d[327]
  PIN a_d[328]
    DIRECTION INPUT ;
    USE SIGNAL ;
    PORT
      LAYER M5 ;
        RECT  33.552 103.572 33.576 103.656 ;
    END
  END a_d[328]
  PIN a_d[329]
    DIRECTION INPUT ;
    USE SIGNAL ;
    PORT
      LAYER M5 ;
        RECT  33.648 103.572 33.672 103.656 ;
    END
  END a_d[329]
  PIN a_d[32]
    DIRECTION INPUT ;
    USE SIGNAL ;
    PORT
      LAYER M5 ;
        RECT  4.56 103.572 4.584 103.656 ;
    END
  END a_d[32]
  PIN a_d[330]
    DIRECTION INPUT ;
    USE SIGNAL ;
    PORT
      LAYER M5 ;
        RECT  33.744 103.572 33.768 103.656 ;
    END
  END a_d[330]
  PIN a_d[331]
    DIRECTION INPUT ;
    USE SIGNAL ;
    PORT
      LAYER M5 ;
        RECT  33.84 103.572 33.864 103.656 ;
    END
  END a_d[331]
  PIN a_d[332]
    DIRECTION INPUT ;
    USE SIGNAL ;
    PORT
      LAYER M5 ;
        RECT  33.936 103.572 33.96 103.656 ;
    END
  END a_d[332]
  PIN a_d[333]
    DIRECTION INPUT ;
    USE SIGNAL ;
    PORT
      LAYER M5 ;
        RECT  34.032 103.572 34.056 103.656 ;
    END
  END a_d[333]
  PIN a_d[334]
    DIRECTION INPUT ;
    USE SIGNAL ;
    PORT
      LAYER M5 ;
        RECT  34.128 103.572 34.152 103.656 ;
    END
  END a_d[334]
  PIN a_d[335]
    DIRECTION INPUT ;
    USE SIGNAL ;
    PORT
      LAYER M5 ;
        RECT  34.224 103.572 34.248 103.656 ;
    END
  END a_d[335]
  PIN a_d[336]
    DIRECTION INPUT ;
    USE SIGNAL ;
    PORT
      LAYER M5 ;
        RECT  34.32 103.572 34.344 103.656 ;
    END
  END a_d[336]
  PIN a_d[337]
    DIRECTION INPUT ;
    USE SIGNAL ;
    PORT
      LAYER M5 ;
        RECT  34.416 103.572 34.44 103.656 ;
    END
  END a_d[337]
  PIN a_d[338]
    DIRECTION INPUT ;
    USE SIGNAL ;
    PORT
      LAYER M5 ;
        RECT  34.512 103.572 34.536 103.656 ;
    END
  END a_d[338]
  PIN a_d[339]
    DIRECTION INPUT ;
    USE SIGNAL ;
    PORT
      LAYER M5 ;
        RECT  34.608 103.572 34.632 103.656 ;
    END
  END a_d[339]
  PIN a_d[33]
    DIRECTION INPUT ;
    USE SIGNAL ;
    PORT
      LAYER M5 ;
        RECT  4.656 103.572 4.68 103.656 ;
    END
  END a_d[33]
  PIN a_d[340]
    DIRECTION INPUT ;
    USE SIGNAL ;
    PORT
      LAYER M5 ;
        RECT  34.704 103.572 34.728 103.656 ;
    END
  END a_d[340]
  PIN a_d[341]
    DIRECTION INPUT ;
    USE SIGNAL ;
    PORT
      LAYER M5 ;
        RECT  34.8 103.572 34.824 103.656 ;
    END
  END a_d[341]
  PIN a_d[342]
    DIRECTION INPUT ;
    USE SIGNAL ;
    PORT
      LAYER M5 ;
        RECT  34.896 103.572 34.92 103.656 ;
    END
  END a_d[342]
  PIN a_d[343]
    DIRECTION INPUT ;
    USE SIGNAL ;
    PORT
      LAYER M5 ;
        RECT  34.992 103.572 35.016 103.656 ;
    END
  END a_d[343]
  PIN a_d[344]
    DIRECTION INPUT ;
    USE SIGNAL ;
    PORT
      LAYER M5 ;
        RECT  35.088 103.572 35.112 103.656 ;
    END
  END a_d[344]
  PIN a_d[345]
    DIRECTION INPUT ;
    USE SIGNAL ;
    PORT
      LAYER M5 ;
        RECT  35.184 103.572 35.208 103.656 ;
    END
  END a_d[345]
  PIN a_d[346]
    DIRECTION INPUT ;
    USE SIGNAL ;
    PORT
      LAYER M5 ;
        RECT  35.28 103.572 35.304 103.656 ;
    END
  END a_d[346]
  PIN a_d[347]
    DIRECTION INPUT ;
    USE SIGNAL ;
    PORT
      LAYER M5 ;
        RECT  35.376 103.572 35.4 103.656 ;
    END
  END a_d[347]
  PIN a_d[348]
    DIRECTION INPUT ;
    USE SIGNAL ;
    PORT
      LAYER M5 ;
        RECT  35.52 103.572 35.544 103.656 ;
    END
  END a_d[348]
  PIN a_d[349]
    DIRECTION INPUT ;
    USE SIGNAL ;
    PORT
      LAYER M5 ;
        RECT  35.616 103.572 35.64 103.656 ;
    END
  END a_d[349]
  PIN a_d[34]
    DIRECTION INPUT ;
    USE SIGNAL ;
    PORT
      LAYER M5 ;
        RECT  4.752 103.572 4.776 103.656 ;
    END
  END a_d[34]
  PIN a_d[350]
    DIRECTION INPUT ;
    USE SIGNAL ;
    PORT
      LAYER M5 ;
        RECT  35.712 103.572 35.736 103.656 ;
    END
  END a_d[350]
  PIN a_d[351]
    DIRECTION INPUT ;
    USE SIGNAL ;
    PORT
      LAYER M5 ;
        RECT  35.808 103.572 35.832 103.656 ;
    END
  END a_d[351]
  PIN a_d[352]
    DIRECTION INPUT ;
    USE SIGNAL ;
    PORT
      LAYER M5 ;
        RECT  35.904 103.572 35.928 103.656 ;
    END
  END a_d[352]
  PIN a_d[353]
    DIRECTION INPUT ;
    USE SIGNAL ;
    PORT
      LAYER M5 ;
        RECT  36 103.572 36.024 103.656 ;
    END
  END a_d[353]
  PIN a_d[354]
    DIRECTION INPUT ;
    USE SIGNAL ;
    PORT
      LAYER M5 ;
        RECT  36.096 103.572 36.12 103.656 ;
    END
  END a_d[354]
  PIN a_d[355]
    DIRECTION INPUT ;
    USE SIGNAL ;
    PORT
      LAYER M5 ;
        RECT  36.192 103.572 36.216 103.656 ;
    END
  END a_d[355]
  PIN a_d[356]
    DIRECTION INPUT ;
    USE SIGNAL ;
    PORT
      LAYER M5 ;
        RECT  36.288 103.572 36.312 103.656 ;
    END
  END a_d[356]
  PIN a_d[357]
    DIRECTION INPUT ;
    USE SIGNAL ;
    PORT
      LAYER M5 ;
        RECT  36.384 103.572 36.408 103.656 ;
    END
  END a_d[357]
  PIN a_d[358]
    DIRECTION INPUT ;
    USE SIGNAL ;
    PORT
      LAYER M5 ;
        RECT  36.48 103.572 36.504 103.656 ;
    END
  END a_d[358]
  PIN a_d[359]
    DIRECTION INPUT ;
    USE SIGNAL ;
    PORT
      LAYER M5 ;
        RECT  36.576 103.572 36.6 103.656 ;
    END
  END a_d[359]
  PIN a_d[35]
    DIRECTION INPUT ;
    USE SIGNAL ;
    PORT
      LAYER M5 ;
        RECT  4.848 103.572 4.872 103.656 ;
    END
  END a_d[35]
  PIN a_d[360]
    DIRECTION INPUT ;
    USE SIGNAL ;
    PORT
      LAYER M5 ;
        RECT  36.672 103.572 36.696 103.656 ;
    END
  END a_d[360]
  PIN a_d[361]
    DIRECTION INPUT ;
    USE SIGNAL ;
    PORT
      LAYER M5 ;
        RECT  36.768 103.572 36.792 103.656 ;
    END
  END a_d[361]
  PIN a_d[362]
    DIRECTION INPUT ;
    USE SIGNAL ;
    PORT
      LAYER M5 ;
        RECT  36.864 103.572 36.888 103.656 ;
    END
  END a_d[362]
  PIN a_d[363]
    DIRECTION INPUT ;
    USE SIGNAL ;
    PORT
      LAYER M5 ;
        RECT  36.96 103.572 36.984 103.656 ;
    END
  END a_d[363]
  PIN a_d[364]
    DIRECTION INPUT ;
    USE SIGNAL ;
    PORT
      LAYER M5 ;
        RECT  37.056 103.572 37.08 103.656 ;
    END
  END a_d[364]
  PIN a_d[365]
    DIRECTION INPUT ;
    USE SIGNAL ;
    PORT
      LAYER M5 ;
        RECT  37.152 103.572 37.176 103.656 ;
    END
  END a_d[365]
  PIN a_d[366]
    DIRECTION INPUT ;
    USE SIGNAL ;
    PORT
      LAYER M5 ;
        RECT  37.248 103.572 37.272 103.656 ;
    END
  END a_d[366]
  PIN a_d[367]
    DIRECTION INPUT ;
    USE SIGNAL ;
    PORT
      LAYER M5 ;
        RECT  37.344 103.572 37.368 103.656 ;
    END
  END a_d[367]
  PIN a_d[368]
    DIRECTION INPUT ;
    USE SIGNAL ;
    PORT
      LAYER M5 ;
        RECT  37.44 103.572 37.464 103.656 ;
    END
  END a_d[368]
  PIN a_d[369]
    DIRECTION INPUT ;
    USE SIGNAL ;
    PORT
      LAYER M5 ;
        RECT  37.536 103.572 37.56 103.656 ;
    END
  END a_d[369]
  PIN a_d[36]
    DIRECTION INPUT ;
    USE SIGNAL ;
    PORT
      LAYER M5 ;
        RECT  4.944 103.572 4.968 103.656 ;
    END
  END a_d[36]
  PIN a_d[370]
    DIRECTION INPUT ;
    USE SIGNAL ;
    PORT
      LAYER M5 ;
        RECT  37.632 103.572 37.656 103.656 ;
    END
  END a_d[370]
  PIN a_d[371]
    DIRECTION INPUT ;
    USE SIGNAL ;
    PORT
      LAYER M5 ;
        RECT  37.728 103.572 37.752 103.656 ;
    END
  END a_d[371]
  PIN a_d[372]
    DIRECTION INPUT ;
    USE SIGNAL ;
    PORT
      LAYER M5 ;
        RECT  37.824 103.572 37.848 103.656 ;
    END
  END a_d[372]
  PIN a_d[373]
    DIRECTION INPUT ;
    USE SIGNAL ;
    PORT
      LAYER M5 ;
        RECT  37.92 103.572 37.944 103.656 ;
    END
  END a_d[373]
  PIN a_d[374]
    DIRECTION INPUT ;
    USE SIGNAL ;
    PORT
      LAYER M5 ;
        RECT  38.064 103.572 38.088 103.656 ;
    END
  END a_d[374]
  PIN a_d[375]
    DIRECTION INPUT ;
    USE SIGNAL ;
    PORT
      LAYER M5 ;
        RECT  38.16 103.572 38.184 103.656 ;
    END
  END a_d[375]
  PIN a_d[376]
    DIRECTION INPUT ;
    USE SIGNAL ;
    PORT
      LAYER M5 ;
        RECT  38.256 103.572 38.28 103.656 ;
    END
  END a_d[376]
  PIN a_d[377]
    DIRECTION INPUT ;
    USE SIGNAL ;
    PORT
      LAYER M5 ;
        RECT  38.352 103.572 38.376 103.656 ;
    END
  END a_d[377]
  PIN a_d[378]
    DIRECTION INPUT ;
    USE SIGNAL ;
    PORT
      LAYER M5 ;
        RECT  38.448 103.572 38.472 103.656 ;
    END
  END a_d[378]
  PIN a_d[379]
    DIRECTION INPUT ;
    USE SIGNAL ;
    PORT
      LAYER M5 ;
        RECT  38.544 103.572 38.568 103.656 ;
    END
  END a_d[379]
  PIN a_d[37]
    DIRECTION INPUT ;
    USE SIGNAL ;
    PORT
      LAYER M5 ;
        RECT  5.04 103.572 5.064 103.656 ;
    END
  END a_d[37]
  PIN a_d[380]
    DIRECTION INPUT ;
    USE SIGNAL ;
    PORT
      LAYER M5 ;
        RECT  38.64 103.572 38.664 103.656 ;
    END
  END a_d[380]
  PIN a_d[381]
    DIRECTION INPUT ;
    USE SIGNAL ;
    PORT
      LAYER M5 ;
        RECT  38.736 103.572 38.76 103.656 ;
    END
  END a_d[381]
  PIN a_d[382]
    DIRECTION INPUT ;
    USE SIGNAL ;
    PORT
      LAYER M5 ;
        RECT  38.832 103.572 38.856 103.656 ;
    END
  END a_d[382]
  PIN a_d[383]
    DIRECTION INPUT ;
    USE SIGNAL ;
    PORT
      LAYER M5 ;
        RECT  38.928 103.572 38.952 103.656 ;
    END
  END a_d[383]
  PIN a_d[384]
    DIRECTION INPUT ;
    USE SIGNAL ;
    PORT
      LAYER M5 ;
        RECT  39.024 103.572 39.048 103.656 ;
    END
  END a_d[384]
  PIN a_d[385]
    DIRECTION INPUT ;
    USE SIGNAL ;
    PORT
      LAYER M5 ;
        RECT  39.12 103.572 39.144 103.656 ;
    END
  END a_d[385]
  PIN a_d[386]
    DIRECTION INPUT ;
    USE SIGNAL ;
    PORT
      LAYER M5 ;
        RECT  39.216 103.572 39.24 103.656 ;
    END
  END a_d[386]
  PIN a_d[387]
    DIRECTION INPUT ;
    USE SIGNAL ;
    PORT
      LAYER M5 ;
        RECT  39.312 103.572 39.336 103.656 ;
    END
  END a_d[387]
  PIN a_d[388]
    DIRECTION INPUT ;
    USE SIGNAL ;
    PORT
      LAYER M5 ;
        RECT  39.408 103.572 39.432 103.656 ;
    END
  END a_d[388]
  PIN a_d[389]
    DIRECTION INPUT ;
    USE SIGNAL ;
    PORT
      LAYER M5 ;
        RECT  39.504 103.572 39.528 103.656 ;
    END
  END a_d[389]
  PIN a_d[38]
    DIRECTION INPUT ;
    USE SIGNAL ;
    PORT
      LAYER M5 ;
        RECT  5.184 103.572 5.208 103.656 ;
    END
  END a_d[38]
  PIN a_d[390]
    DIRECTION INPUT ;
    USE SIGNAL ;
    PORT
      LAYER M5 ;
        RECT  39.6 103.572 39.624 103.656 ;
    END
  END a_d[390]
  PIN a_d[391]
    DIRECTION INPUT ;
    USE SIGNAL ;
    PORT
      LAYER M5 ;
        RECT  39.696 103.572 39.72 103.656 ;
    END
  END a_d[391]
  PIN a_d[392]
    DIRECTION INPUT ;
    USE SIGNAL ;
    PORT
      LAYER M5 ;
        RECT  39.792 103.572 39.816 103.656 ;
    END
  END a_d[392]
  PIN a_d[393]
    DIRECTION INPUT ;
    USE SIGNAL ;
    PORT
      LAYER M5 ;
        RECT  39.888 103.572 39.912 103.656 ;
    END
  END a_d[393]
  PIN a_d[394]
    DIRECTION INPUT ;
    USE SIGNAL ;
    PORT
      LAYER M5 ;
        RECT  39.984 103.572 40.008 103.656 ;
    END
  END a_d[394]
  PIN a_d[395]
    DIRECTION INPUT ;
    USE SIGNAL ;
    PORT
      LAYER M5 ;
        RECT  40.08 103.572 40.104 103.656 ;
    END
  END a_d[395]
  PIN a_d[396]
    DIRECTION INPUT ;
    USE SIGNAL ;
    PORT
      LAYER M5 ;
        RECT  40.176 103.572 40.2 103.656 ;
    END
  END a_d[396]
  PIN a_d[397]
    DIRECTION INPUT ;
    USE SIGNAL ;
    PORT
      LAYER M5 ;
        RECT  40.272 103.572 40.296 103.656 ;
    END
  END a_d[397]
  PIN a_d[398]
    DIRECTION INPUT ;
    USE SIGNAL ;
    PORT
      LAYER M5 ;
        RECT  40.368 103.572 40.392 103.656 ;
    END
  END a_d[398]
  PIN a_d[399]
    DIRECTION INPUT ;
    USE SIGNAL ;
    PORT
      LAYER M5 ;
        RECT  40.464 103.572 40.488 103.656 ;
    END
  END a_d[399]
  PIN a_d[39]
    DIRECTION INPUT ;
    USE SIGNAL ;
    PORT
      LAYER M5 ;
        RECT  5.28 103.572 5.304 103.656 ;
    END
  END a_d[39]
  PIN a_d[3]
    DIRECTION INPUT ;
    USE SIGNAL ;
    PORT
      LAYER M5 ;
        RECT  1.728 103.572 1.752 103.656 ;
    END
  END a_d[3]
  PIN a_d[400]
    DIRECTION INPUT ;
    USE SIGNAL ;
    PORT
      LAYER M5 ;
        RECT  40.608 103.572 40.632 103.656 ;
    END
  END a_d[400]
  PIN a_d[401]
    DIRECTION INPUT ;
    USE SIGNAL ;
    PORT
      LAYER M5 ;
        RECT  40.704 103.572 40.728 103.656 ;
    END
  END a_d[401]
  PIN a_d[402]
    DIRECTION INPUT ;
    USE SIGNAL ;
    PORT
      LAYER M5 ;
        RECT  40.8 103.572 40.824 103.656 ;
    END
  END a_d[402]
  PIN a_d[403]
    DIRECTION INPUT ;
    USE SIGNAL ;
    PORT
      LAYER M5 ;
        RECT  40.896 103.572 40.92 103.656 ;
    END
  END a_d[403]
  PIN a_d[404]
    DIRECTION INPUT ;
    USE SIGNAL ;
    PORT
      LAYER M5 ;
        RECT  40.992 103.572 41.016 103.656 ;
    END
  END a_d[404]
  PIN a_d[405]
    DIRECTION INPUT ;
    USE SIGNAL ;
    PORT
      LAYER M5 ;
        RECT  41.088 103.572 41.112 103.656 ;
    END
  END a_d[405]
  PIN a_d[406]
    DIRECTION INPUT ;
    USE SIGNAL ;
    PORT
      LAYER M5 ;
        RECT  41.184 103.572 41.208 103.656 ;
    END
  END a_d[406]
  PIN a_d[407]
    DIRECTION INPUT ;
    USE SIGNAL ;
    PORT
      LAYER M5 ;
        RECT  41.28 103.572 41.304 103.656 ;
    END
  END a_d[407]
  PIN a_d[408]
    DIRECTION INPUT ;
    USE SIGNAL ;
    PORT
      LAYER M5 ;
        RECT  41.376 103.572 41.4 103.656 ;
    END
  END a_d[408]
  PIN a_d[409]
    DIRECTION INPUT ;
    USE SIGNAL ;
    PORT
      LAYER M5 ;
        RECT  41.472 103.572 41.496 103.656 ;
    END
  END a_d[409]
  PIN a_d[40]
    DIRECTION INPUT ;
    USE SIGNAL ;
    PORT
      LAYER M5 ;
        RECT  5.376 103.572 5.4 103.656 ;
    END
  END a_d[40]
  PIN a_d[410]
    DIRECTION INPUT ;
    USE SIGNAL ;
    PORT
      LAYER M5 ;
        RECT  41.568 103.572 41.592 103.656 ;
    END
  END a_d[410]
  PIN a_d[411]
    DIRECTION INPUT ;
    USE SIGNAL ;
    PORT
      LAYER M5 ;
        RECT  41.664 103.572 41.688 103.656 ;
    END
  END a_d[411]
  PIN a_d[412]
    DIRECTION INPUT ;
    USE SIGNAL ;
    PORT
      LAYER M5 ;
        RECT  41.76 103.572 41.784 103.656 ;
    END
  END a_d[412]
  PIN a_d[413]
    DIRECTION INPUT ;
    USE SIGNAL ;
    PORT
      LAYER M5 ;
        RECT  41.856 103.572 41.88 103.656 ;
    END
  END a_d[413]
  PIN a_d[414]
    DIRECTION INPUT ;
    USE SIGNAL ;
    PORT
      LAYER M5 ;
        RECT  41.952 103.572 41.976 103.656 ;
    END
  END a_d[414]
  PIN a_d[415]
    DIRECTION INPUT ;
    USE SIGNAL ;
    PORT
      LAYER M5 ;
        RECT  42.048 103.572 42.072 103.656 ;
    END
  END a_d[415]
  PIN a_d[416]
    DIRECTION INPUT ;
    USE SIGNAL ;
    PORT
      LAYER M5 ;
        RECT  42.144 103.572 42.168 103.656 ;
    END
  END a_d[416]
  PIN a_d[417]
    DIRECTION INPUT ;
    USE SIGNAL ;
    PORT
      LAYER M5 ;
        RECT  42.24 103.572 42.264 103.656 ;
    END
  END a_d[417]
  PIN a_d[418]
    DIRECTION INPUT ;
    USE SIGNAL ;
    PORT
      LAYER M5 ;
        RECT  42.336 103.572 42.36 103.656 ;
    END
  END a_d[418]
  PIN a_d[419]
    DIRECTION INPUT ;
    USE SIGNAL ;
    PORT
      LAYER M5 ;
        RECT  42.432 103.572 42.456 103.656 ;
    END
  END a_d[419]
  PIN a_d[41]
    DIRECTION INPUT ;
    USE SIGNAL ;
    PORT
      LAYER M5 ;
        RECT  5.472 103.572 5.496 103.656 ;
    END
  END a_d[41]
  PIN a_d[420]
    DIRECTION INPUT ;
    USE SIGNAL ;
    PORT
      LAYER M5 ;
        RECT  42.528 103.572 42.552 103.656 ;
    END
  END a_d[420]
  PIN a_d[421]
    DIRECTION INPUT ;
    USE SIGNAL ;
    PORT
      LAYER M5 ;
        RECT  42.624 103.572 42.648 103.656 ;
    END
  END a_d[421]
  PIN a_d[422]
    DIRECTION INPUT ;
    USE SIGNAL ;
    PORT
      LAYER M5 ;
        RECT  42.72 103.572 42.744 103.656 ;
    END
  END a_d[422]
  PIN a_d[423]
    DIRECTION INPUT ;
    USE SIGNAL ;
    PORT
      LAYER M5 ;
        RECT  42.816 103.572 42.84 103.656 ;
    END
  END a_d[423]
  PIN a_d[424]
    DIRECTION INPUT ;
    USE SIGNAL ;
    PORT
      LAYER M5 ;
        RECT  42.912 103.572 42.936 103.656 ;
    END
  END a_d[424]
  PIN a_d[425]
    DIRECTION INPUT ;
    USE SIGNAL ;
    PORT
      LAYER M5 ;
        RECT  43.056 103.572 43.08 103.656 ;
    END
  END a_d[425]
  PIN a_d[426]
    DIRECTION INPUT ;
    USE SIGNAL ;
    PORT
      LAYER M5 ;
        RECT  43.152 103.572 43.176 103.656 ;
    END
  END a_d[426]
  PIN a_d[427]
    DIRECTION INPUT ;
    USE SIGNAL ;
    PORT
      LAYER M5 ;
        RECT  43.248 103.572 43.272 103.656 ;
    END
  END a_d[427]
  PIN a_d[428]
    DIRECTION INPUT ;
    USE SIGNAL ;
    PORT
      LAYER M5 ;
        RECT  43.344 103.572 43.368 103.656 ;
    END
  END a_d[428]
  PIN a_d[429]
    DIRECTION INPUT ;
    USE SIGNAL ;
    PORT
      LAYER M5 ;
        RECT  43.44 103.572 43.464 103.656 ;
    END
  END a_d[429]
  PIN a_d[42]
    DIRECTION INPUT ;
    USE SIGNAL ;
    PORT
      LAYER M5 ;
        RECT  5.568 103.572 5.592 103.656 ;
    END
  END a_d[42]
  PIN a_d[430]
    DIRECTION INPUT ;
    USE SIGNAL ;
    PORT
      LAYER M5 ;
        RECT  43.536 103.572 43.56 103.656 ;
    END
  END a_d[430]
  PIN a_d[431]
    DIRECTION INPUT ;
    USE SIGNAL ;
    PORT
      LAYER M5 ;
        RECT  43.632 103.572 43.656 103.656 ;
    END
  END a_d[431]
  PIN a_d[432]
    DIRECTION INPUT ;
    USE SIGNAL ;
    PORT
      LAYER M5 ;
        RECT  43.728 103.572 43.752 103.656 ;
    END
  END a_d[432]
  PIN a_d[433]
    DIRECTION INPUT ;
    USE SIGNAL ;
    PORT
      LAYER M5 ;
        RECT  43.824 103.572 43.848 103.656 ;
    END
  END a_d[433]
  PIN a_d[434]
    DIRECTION INPUT ;
    USE SIGNAL ;
    PORT
      LAYER M5 ;
        RECT  43.92 103.572 43.944 103.656 ;
    END
  END a_d[434]
  PIN a_d[435]
    DIRECTION INPUT ;
    USE SIGNAL ;
    PORT
      LAYER M5 ;
        RECT  44.016 103.572 44.04 103.656 ;
    END
  END a_d[435]
  PIN a_d[436]
    DIRECTION INPUT ;
    USE SIGNAL ;
    PORT
      LAYER M5 ;
        RECT  44.112 103.572 44.136 103.656 ;
    END
  END a_d[436]
  PIN a_d[437]
    DIRECTION INPUT ;
    USE SIGNAL ;
    PORT
      LAYER M5 ;
        RECT  44.208 103.572 44.232 103.656 ;
    END
  END a_d[437]
  PIN a_d[438]
    DIRECTION INPUT ;
    USE SIGNAL ;
    PORT
      LAYER M5 ;
        RECT  44.304 103.572 44.328 103.656 ;
    END
  END a_d[438]
  PIN a_d[439]
    DIRECTION INPUT ;
    USE SIGNAL ;
    PORT
      LAYER M5 ;
        RECT  44.4 103.572 44.424 103.656 ;
    END
  END a_d[439]
  PIN a_d[43]
    DIRECTION INPUT ;
    USE SIGNAL ;
    PORT
      LAYER M5 ;
        RECT  5.664 103.572 5.688 103.656 ;
    END
  END a_d[43]
  PIN a_d[440]
    DIRECTION INPUT ;
    USE SIGNAL ;
    PORT
      LAYER M5 ;
        RECT  44.496 103.572 44.52 103.656 ;
    END
  END a_d[440]
  PIN a_d[441]
    DIRECTION INPUT ;
    USE SIGNAL ;
    PORT
      LAYER M5 ;
        RECT  44.592 103.572 44.616 103.656 ;
    END
  END a_d[441]
  PIN a_d[442]
    DIRECTION INPUT ;
    USE SIGNAL ;
    PORT
      LAYER M5 ;
        RECT  44.688 103.572 44.712 103.656 ;
    END
  END a_d[442]
  PIN a_d[443]
    DIRECTION INPUT ;
    USE SIGNAL ;
    PORT
      LAYER M5 ;
        RECT  44.784 103.572 44.808 103.656 ;
    END
  END a_d[443]
  PIN a_d[444]
    DIRECTION INPUT ;
    USE SIGNAL ;
    PORT
      LAYER M5 ;
        RECT  44.88 103.572 44.904 103.656 ;
    END
  END a_d[444]
  PIN a_d[445]
    DIRECTION INPUT ;
    USE SIGNAL ;
    PORT
      LAYER M5 ;
        RECT  44.976 103.572 45 103.656 ;
    END
  END a_d[445]
  PIN a_d[446]
    DIRECTION INPUT ;
    USE SIGNAL ;
    PORT
      LAYER M5 ;
        RECT  45.072 103.572 45.096 103.656 ;
    END
  END a_d[446]
  PIN a_d[447]
    DIRECTION INPUT ;
    USE SIGNAL ;
    PORT
      LAYER M5 ;
        RECT  45.168 103.572 45.192 103.656 ;
    END
  END a_d[447]
  PIN a_d[448]
    DIRECTION INPUT ;
    USE SIGNAL ;
    PORT
      LAYER M5 ;
        RECT  45.264 103.572 45.288 103.656 ;
    END
  END a_d[448]
  PIN a_d[449]
    DIRECTION INPUT ;
    USE SIGNAL ;
    PORT
      LAYER M5 ;
        RECT  45.36 103.572 45.384 103.656 ;
    END
  END a_d[449]
  PIN a_d[44]
    DIRECTION INPUT ;
    USE SIGNAL ;
    PORT
      LAYER M5 ;
        RECT  5.76 103.572 5.784 103.656 ;
    END
  END a_d[44]
  PIN a_d[450]
    DIRECTION INPUT ;
    USE SIGNAL ;
    PORT
      LAYER M5 ;
        RECT  45.456 103.572 45.48 103.656 ;
    END
  END a_d[450]
  PIN a_d[451]
    DIRECTION INPUT ;
    USE SIGNAL ;
    PORT
      LAYER M5 ;
        RECT  45.6 103.572 45.624 103.656 ;
    END
  END a_d[451]
  PIN a_d[452]
    DIRECTION INPUT ;
    USE SIGNAL ;
    PORT
      LAYER M5 ;
        RECT  45.696 103.572 45.72 103.656 ;
    END
  END a_d[452]
  PIN a_d[453]
    DIRECTION INPUT ;
    USE SIGNAL ;
    PORT
      LAYER M5 ;
        RECT  45.792 103.572 45.816 103.656 ;
    END
  END a_d[453]
  PIN a_d[454]
    DIRECTION INPUT ;
    USE SIGNAL ;
    PORT
      LAYER M5 ;
        RECT  45.888 103.572 45.912 103.656 ;
    END
  END a_d[454]
  PIN a_d[455]
    DIRECTION INPUT ;
    USE SIGNAL ;
    PORT
      LAYER M5 ;
        RECT  45.984 103.572 46.008 103.656 ;
    END
  END a_d[455]
  PIN a_d[456]
    DIRECTION INPUT ;
    USE SIGNAL ;
    PORT
      LAYER M5 ;
        RECT  46.08 103.572 46.104 103.656 ;
    END
  END a_d[456]
  PIN a_d[457]
    DIRECTION INPUT ;
    USE SIGNAL ;
    PORT
      LAYER M5 ;
        RECT  46.176 103.572 46.2 103.656 ;
    END
  END a_d[457]
  PIN a_d[458]
    DIRECTION INPUT ;
    USE SIGNAL ;
    PORT
      LAYER M5 ;
        RECT  46.272 103.572 46.296 103.656 ;
    END
  END a_d[458]
  PIN a_d[459]
    DIRECTION INPUT ;
    USE SIGNAL ;
    PORT
      LAYER M5 ;
        RECT  46.368 103.572 46.392 103.656 ;
    END
  END a_d[459]
  PIN a_d[45]
    DIRECTION INPUT ;
    USE SIGNAL ;
    PORT
      LAYER M5 ;
        RECT  5.856 103.572 5.88 103.656 ;
    END
  END a_d[45]
  PIN a_d[460]
    DIRECTION INPUT ;
    USE SIGNAL ;
    PORT
      LAYER M5 ;
        RECT  46.464 103.572 46.488 103.656 ;
    END
  END a_d[460]
  PIN a_d[461]
    DIRECTION INPUT ;
    USE SIGNAL ;
    PORT
      LAYER M5 ;
        RECT  46.56 103.572 46.584 103.656 ;
    END
  END a_d[461]
  PIN a_d[462]
    DIRECTION INPUT ;
    USE SIGNAL ;
    PORT
      LAYER M5 ;
        RECT  46.656 103.572 46.68 103.656 ;
    END
  END a_d[462]
  PIN a_d[463]
    DIRECTION INPUT ;
    USE SIGNAL ;
    PORT
      LAYER M5 ;
        RECT  46.752 103.572 46.776 103.656 ;
    END
  END a_d[463]
  PIN a_d[464]
    DIRECTION INPUT ;
    USE SIGNAL ;
    PORT
      LAYER M5 ;
        RECT  46.848 103.572 46.872 103.656 ;
    END
  END a_d[464]
  PIN a_d[465]
    DIRECTION INPUT ;
    USE SIGNAL ;
    PORT
      LAYER M5 ;
        RECT  46.944 103.572 46.968 103.656 ;
    END
  END a_d[465]
  PIN a_d[466]
    DIRECTION INPUT ;
    USE SIGNAL ;
    PORT
      LAYER M5 ;
        RECT  47.04 103.572 47.064 103.656 ;
    END
  END a_d[466]
  PIN a_d[467]
    DIRECTION INPUT ;
    USE SIGNAL ;
    PORT
      LAYER M5 ;
        RECT  47.136 103.572 47.16 103.656 ;
    END
  END a_d[467]
  PIN a_d[468]
    DIRECTION INPUT ;
    USE SIGNAL ;
    PORT
      LAYER M5 ;
        RECT  47.232 103.572 47.256 103.656 ;
    END
  END a_d[468]
  PIN a_d[469]
    DIRECTION INPUT ;
    USE SIGNAL ;
    PORT
      LAYER M5 ;
        RECT  47.328 103.572 47.352 103.656 ;
    END
  END a_d[469]
  PIN a_d[46]
    DIRECTION INPUT ;
    USE SIGNAL ;
    PORT
      LAYER M5 ;
        RECT  5.952 103.572 5.976 103.656 ;
    END
  END a_d[46]
  PIN a_d[470]
    DIRECTION INPUT ;
    USE SIGNAL ;
    PORT
      LAYER M5 ;
        RECT  47.424 103.572 47.448 103.656 ;
    END
  END a_d[470]
  PIN a_d[471]
    DIRECTION INPUT ;
    USE SIGNAL ;
    PORT
      LAYER M5 ;
        RECT  47.52 103.572 47.544 103.656 ;
    END
  END a_d[471]
  PIN a_d[472]
    DIRECTION INPUT ;
    USE SIGNAL ;
    PORT
      LAYER M5 ;
        RECT  47.616 103.572 47.64 103.656 ;
    END
  END a_d[472]
  PIN a_d[473]
    DIRECTION INPUT ;
    USE SIGNAL ;
    PORT
      LAYER M5 ;
        RECT  47.712 103.572 47.736 103.656 ;
    END
  END a_d[473]
  PIN a_d[474]
    DIRECTION INPUT ;
    USE SIGNAL ;
    PORT
      LAYER M5 ;
        RECT  47.808 103.572 47.832 103.656 ;
    END
  END a_d[474]
  PIN a_d[475]
    DIRECTION INPUT ;
    USE SIGNAL ;
    PORT
      LAYER M5 ;
        RECT  47.904 103.572 47.928 103.656 ;
    END
  END a_d[475]
  PIN a_d[476]
    DIRECTION INPUT ;
    USE SIGNAL ;
    PORT
      LAYER M5 ;
        RECT  48 103.572 48.024 103.656 ;
    END
  END a_d[476]
  PIN a_d[477]
    DIRECTION INPUT ;
    USE SIGNAL ;
    PORT
      LAYER M5 ;
        RECT  48.144 103.572 48.168 103.656 ;
    END
  END a_d[477]
  PIN a_d[478]
    DIRECTION INPUT ;
    USE SIGNAL ;
    PORT
      LAYER M5 ;
        RECT  48.24 103.572 48.264 103.656 ;
    END
  END a_d[478]
  PIN a_d[479]
    DIRECTION INPUT ;
    USE SIGNAL ;
    PORT
      LAYER M5 ;
        RECT  48.336 103.572 48.36 103.656 ;
    END
  END a_d[479]
  PIN a_d[47]
    DIRECTION INPUT ;
    USE SIGNAL ;
    PORT
      LAYER M5 ;
        RECT  6.048 103.572 6.072 103.656 ;
    END
  END a_d[47]
  PIN a_d[480]
    DIRECTION INPUT ;
    USE SIGNAL ;
    PORT
      LAYER M5 ;
        RECT  48.432 103.572 48.456 103.656 ;
    END
  END a_d[480]
  PIN a_d[481]
    DIRECTION INPUT ;
    USE SIGNAL ;
    PORT
      LAYER M5 ;
        RECT  48.528 103.572 48.552 103.656 ;
    END
  END a_d[481]
  PIN a_d[482]
    DIRECTION INPUT ;
    USE SIGNAL ;
    PORT
      LAYER M5 ;
        RECT  48.624 103.572 48.648 103.656 ;
    END
  END a_d[482]
  PIN a_d[483]
    DIRECTION INPUT ;
    USE SIGNAL ;
    PORT
      LAYER M5 ;
        RECT  48.72 103.572 48.744 103.656 ;
    END
  END a_d[483]
  PIN a_d[484]
    DIRECTION INPUT ;
    USE SIGNAL ;
    PORT
      LAYER M5 ;
        RECT  48.816 103.572 48.84 103.656 ;
    END
  END a_d[484]
  PIN a_d[485]
    DIRECTION INPUT ;
    USE SIGNAL ;
    PORT
      LAYER M5 ;
        RECT  48.912 103.572 48.936 103.656 ;
    END
  END a_d[485]
  PIN a_d[486]
    DIRECTION INPUT ;
    USE SIGNAL ;
    PORT
      LAYER M5 ;
        RECT  49.008 103.572 49.032 103.656 ;
    END
  END a_d[486]
  PIN a_d[487]
    DIRECTION INPUT ;
    USE SIGNAL ;
    PORT
      LAYER M5 ;
        RECT  49.104 103.572 49.128 103.656 ;
    END
  END a_d[487]
  PIN a_d[488]
    DIRECTION INPUT ;
    USE SIGNAL ;
    PORT
      LAYER M5 ;
        RECT  49.2 103.572 49.224 103.656 ;
    END
  END a_d[488]
  PIN a_d[489]
    DIRECTION INPUT ;
    USE SIGNAL ;
    PORT
      LAYER M5 ;
        RECT  49.296 103.572 49.32 103.656 ;
    END
  END a_d[489]
  PIN a_d[48]
    DIRECTION INPUT ;
    USE SIGNAL ;
    PORT
      LAYER M5 ;
        RECT  6.144 103.572 6.168 103.656 ;
    END
  END a_d[48]
  PIN a_d[490]
    DIRECTION INPUT ;
    USE SIGNAL ;
    PORT
      LAYER M5 ;
        RECT  49.392 103.572 49.416 103.656 ;
    END
  END a_d[490]
  PIN a_d[491]
    DIRECTION INPUT ;
    USE SIGNAL ;
    PORT
      LAYER M5 ;
        RECT  49.488 103.572 49.512 103.656 ;
    END
  END a_d[491]
  PIN a_d[492]
    DIRECTION INPUT ;
    USE SIGNAL ;
    PORT
      LAYER M5 ;
        RECT  49.584 103.572 49.608 103.656 ;
    END
  END a_d[492]
  PIN a_d[493]
    DIRECTION INPUT ;
    USE SIGNAL ;
    PORT
      LAYER M5 ;
        RECT  49.68 103.572 49.704 103.656 ;
    END
  END a_d[493]
  PIN a_d[494]
    DIRECTION INPUT ;
    USE SIGNAL ;
    PORT
      LAYER M5 ;
        RECT  49.776 103.572 49.8 103.656 ;
    END
  END a_d[494]
  PIN a_d[495]
    DIRECTION INPUT ;
    USE SIGNAL ;
    PORT
      LAYER M5 ;
        RECT  49.872 103.572 49.896 103.656 ;
    END
  END a_d[495]
  PIN a_d[496]
    DIRECTION INPUT ;
    USE SIGNAL ;
    PORT
      LAYER M5 ;
        RECT  49.968 103.572 49.992 103.656 ;
    END
  END a_d[496]
  PIN a_d[497]
    DIRECTION INPUT ;
    USE SIGNAL ;
    PORT
      LAYER M5 ;
        RECT  50.064 103.572 50.088 103.656 ;
    END
  END a_d[497]
  PIN a_d[498]
    DIRECTION INPUT ;
    USE SIGNAL ;
    PORT
      LAYER M5 ;
        RECT  50.16 103.572 50.184 103.656 ;
    END
  END a_d[498]
  PIN a_d[499]
    DIRECTION INPUT ;
    USE SIGNAL ;
    PORT
      LAYER M5 ;
        RECT  50.256 103.572 50.28 103.656 ;
    END
  END a_d[499]
  PIN a_d[49]
    DIRECTION INPUT ;
    USE SIGNAL ;
    PORT
      LAYER M5 ;
        RECT  6.24 103.572 6.264 103.656 ;
    END
  END a_d[49]
  PIN a_d[4]
    DIRECTION INPUT ;
    USE SIGNAL ;
    PORT
      LAYER M5 ;
        RECT  1.824 103.572 1.848 103.656 ;
    END
  END a_d[4]
  PIN a_d[500]
    DIRECTION INPUT ;
    USE SIGNAL ;
    PORT
      LAYER M5 ;
        RECT  50.352 103.572 50.376 103.656 ;
    END
  END a_d[500]
  PIN a_d[501]
    DIRECTION INPUT ;
    USE SIGNAL ;
    PORT
      LAYER M5 ;
        RECT  50.448 103.572 50.472 103.656 ;
    END
  END a_d[501]
  PIN a_d[502]
    DIRECTION INPUT ;
    USE SIGNAL ;
    PORT
      LAYER M5 ;
        RECT  50.544 103.572 50.568 103.656 ;
    END
  END a_d[502]
  PIN a_d[503]
    DIRECTION INPUT ;
    USE SIGNAL ;
    PORT
      LAYER M5 ;
        RECT  50.688 103.572 50.712 103.656 ;
    END
  END a_d[503]
  PIN a_d[504]
    DIRECTION INPUT ;
    USE SIGNAL ;
    PORT
      LAYER M5 ;
        RECT  50.784 103.572 50.808 103.656 ;
    END
  END a_d[504]
  PIN a_d[505]
    DIRECTION INPUT ;
    USE SIGNAL ;
    PORT
      LAYER M5 ;
        RECT  50.88 103.572 50.904 103.656 ;
    END
  END a_d[505]
  PIN a_d[506]
    DIRECTION INPUT ;
    USE SIGNAL ;
    PORT
      LAYER M5 ;
        RECT  50.976 103.572 51 103.656 ;
    END
  END a_d[506]
  PIN a_d[507]
    DIRECTION INPUT ;
    USE SIGNAL ;
    PORT
      LAYER M5 ;
        RECT  51.072 103.572 51.096 103.656 ;
    END
  END a_d[507]
  PIN a_d[508]
    DIRECTION INPUT ;
    USE SIGNAL ;
    PORT
      LAYER M5 ;
        RECT  51.168 103.572 51.192 103.656 ;
    END
  END a_d[508]
  PIN a_d[509]
    DIRECTION INPUT ;
    USE SIGNAL ;
    PORT
      LAYER M5 ;
        RECT  51.264 103.572 51.288 103.656 ;
    END
  END a_d[509]
  PIN a_d[50]
    DIRECTION INPUT ;
    USE SIGNAL ;
    PORT
      LAYER M5 ;
        RECT  6.336 103.572 6.36 103.656 ;
    END
  END a_d[50]
  PIN a_d[510]
    DIRECTION INPUT ;
    USE SIGNAL ;
    PORT
      LAYER M5 ;
        RECT  51.36 103.572 51.384 103.656 ;
    END
  END a_d[510]
  PIN a_d[511]
    DIRECTION INPUT ;
    USE SIGNAL ;
    PORT
      LAYER M5 ;
        RECT  51.456 103.572 51.48 103.656 ;
    END
  END a_d[511]
  PIN a_d[512]
    DIRECTION INPUT ;
    USE SIGNAL ;
    PORT
      LAYER M5 ;
        RECT  51.552 103.572 51.576 103.656 ;
    END
  END a_d[512]
  PIN a_d[513]
    DIRECTION INPUT ;
    USE SIGNAL ;
    PORT
      LAYER M5 ;
        RECT  51.648 103.572 51.672 103.656 ;
    END
  END a_d[513]
  PIN a_d[514]
    DIRECTION INPUT ;
    USE SIGNAL ;
    PORT
      LAYER M5 ;
        RECT  51.744 103.572 51.768 103.656 ;
    END
  END a_d[514]
  PIN a_d[515]
    DIRECTION INPUT ;
    USE SIGNAL ;
    PORT
      LAYER M5 ;
        RECT  51.84 103.572 51.864 103.656 ;
    END
  END a_d[515]
  PIN a_d[51]
    DIRECTION INPUT ;
    USE SIGNAL ;
    PORT
      LAYER M5 ;
        RECT  6.432 103.572 6.456 103.656 ;
    END
  END a_d[51]
  PIN a_d[52]
    DIRECTION INPUT ;
    USE SIGNAL ;
    PORT
      LAYER M5 ;
        RECT  6.528 103.572 6.552 103.656 ;
    END
  END a_d[52]
  PIN a_d[53]
    DIRECTION INPUT ;
    USE SIGNAL ;
    PORT
      LAYER M5 ;
        RECT  6.624 103.572 6.648 103.656 ;
    END
  END a_d[53]
  PIN a_d[54]
    DIRECTION INPUT ;
    USE SIGNAL ;
    PORT
      LAYER M5 ;
        RECT  6.72 103.572 6.744 103.656 ;
    END
  END a_d[54]
  PIN a_d[55]
    DIRECTION INPUT ;
    USE SIGNAL ;
    PORT
      LAYER M5 ;
        RECT  6.816 103.572 6.84 103.656 ;
    END
  END a_d[55]
  PIN a_d[56]
    DIRECTION INPUT ;
    USE SIGNAL ;
    PORT
      LAYER M5 ;
        RECT  6.912 103.572 6.936 103.656 ;
    END
  END a_d[56]
  PIN a_d[57]
    DIRECTION INPUT ;
    USE SIGNAL ;
    PORT
      LAYER M5 ;
        RECT  7.008 103.572 7.032 103.656 ;
    END
  END a_d[57]
  PIN a_d[58]
    DIRECTION INPUT ;
    USE SIGNAL ;
    PORT
      LAYER M5 ;
        RECT  7.104 103.572 7.128 103.656 ;
    END
  END a_d[58]
  PIN a_d[59]
    DIRECTION INPUT ;
    USE SIGNAL ;
    PORT
      LAYER M5 ;
        RECT  7.2 103.572 7.224 103.656 ;
    END
  END a_d[59]
  PIN a_d[5]
    DIRECTION INPUT ;
    USE SIGNAL ;
    PORT
      LAYER M5 ;
        RECT  1.92 103.572 1.944 103.656 ;
    END
  END a_d[5]
  PIN a_d[60]
    DIRECTION INPUT ;
    USE SIGNAL ;
    PORT
      LAYER M5 ;
        RECT  7.296 103.572 7.32 103.656 ;
    END
  END a_d[60]
  PIN a_d[61]
    DIRECTION INPUT ;
    USE SIGNAL ;
    PORT
      LAYER M5 ;
        RECT  7.392 103.572 7.416 103.656 ;
    END
  END a_d[61]
  PIN a_d[62]
    DIRECTION INPUT ;
    USE SIGNAL ;
    PORT
      LAYER M5 ;
        RECT  7.488 103.572 7.512 103.656 ;
    END
  END a_d[62]
  PIN a_d[63]
    DIRECTION INPUT ;
    USE SIGNAL ;
    PORT
      LAYER M5 ;
        RECT  7.584 103.572 7.608 103.656 ;
    END
  END a_d[63]
  PIN a_d[64]
    DIRECTION INPUT ;
    USE SIGNAL ;
    PORT
      LAYER M5 ;
        RECT  7.728 103.572 7.752 103.656 ;
    END
  END a_d[64]
  PIN a_d[65]
    DIRECTION INPUT ;
    USE SIGNAL ;
    PORT
      LAYER M5 ;
        RECT  7.824 103.572 7.848 103.656 ;
    END
  END a_d[65]
  PIN a_d[66]
    DIRECTION INPUT ;
    USE SIGNAL ;
    PORT
      LAYER M5 ;
        RECT  7.92 103.572 7.944 103.656 ;
    END
  END a_d[66]
  PIN a_d[67]
    DIRECTION INPUT ;
    USE SIGNAL ;
    PORT
      LAYER M5 ;
        RECT  8.016 103.572 8.04 103.656 ;
    END
  END a_d[67]
  PIN a_d[68]
    DIRECTION INPUT ;
    USE SIGNAL ;
    PORT
      LAYER M5 ;
        RECT  8.112 103.572 8.136 103.656 ;
    END
  END a_d[68]
  PIN a_d[69]
    DIRECTION INPUT ;
    USE SIGNAL ;
    PORT
      LAYER M5 ;
        RECT  8.208 103.572 8.232 103.656 ;
    END
  END a_d[69]
  PIN a_d[6]
    DIRECTION INPUT ;
    USE SIGNAL ;
    PORT
      LAYER M5 ;
        RECT  2.016 103.572 2.04 103.656 ;
    END
  END a_d[6]
  PIN a_d[70]
    DIRECTION INPUT ;
    USE SIGNAL ;
    PORT
      LAYER M5 ;
        RECT  8.304 103.572 8.328 103.656 ;
    END
  END a_d[70]
  PIN a_d[71]
    DIRECTION INPUT ;
    USE SIGNAL ;
    PORT
      LAYER M5 ;
        RECT  8.4 103.572 8.424 103.656 ;
    END
  END a_d[71]
  PIN a_d[72]
    DIRECTION INPUT ;
    USE SIGNAL ;
    PORT
      LAYER M5 ;
        RECT  8.496 103.572 8.52 103.656 ;
    END
  END a_d[72]
  PIN a_d[73]
    DIRECTION INPUT ;
    USE SIGNAL ;
    PORT
      LAYER M5 ;
        RECT  8.592 103.572 8.616 103.656 ;
    END
  END a_d[73]
  PIN a_d[74]
    DIRECTION INPUT ;
    USE SIGNAL ;
    PORT
      LAYER M5 ;
        RECT  8.688 103.572 8.712 103.656 ;
    END
  END a_d[74]
  PIN a_d[75]
    DIRECTION INPUT ;
    USE SIGNAL ;
    PORT
      LAYER M5 ;
        RECT  8.784 103.572 8.808 103.656 ;
    END
  END a_d[75]
  PIN a_d[76]
    DIRECTION INPUT ;
    USE SIGNAL ;
    PORT
      LAYER M5 ;
        RECT  8.88 103.572 8.904 103.656 ;
    END
  END a_d[76]
  PIN a_d[77]
    DIRECTION INPUT ;
    USE SIGNAL ;
    PORT
      LAYER M5 ;
        RECT  8.976 103.572 9 103.656 ;
    END
  END a_d[77]
  PIN a_d[78]
    DIRECTION INPUT ;
    USE SIGNAL ;
    PORT
      LAYER M5 ;
        RECT  9.072 103.572 9.096 103.656 ;
    END
  END a_d[78]
  PIN a_d[79]
    DIRECTION INPUT ;
    USE SIGNAL ;
    PORT
      LAYER M5 ;
        RECT  9.168 103.572 9.192 103.656 ;
    END
  END a_d[79]
  PIN a_d[7]
    DIRECTION INPUT ;
    USE SIGNAL ;
    PORT
      LAYER M5 ;
        RECT  2.112 103.572 2.136 103.656 ;
    END
  END a_d[7]
  PIN a_d[80]
    DIRECTION INPUT ;
    USE SIGNAL ;
    PORT
      LAYER M5 ;
        RECT  9.264 103.572 9.288 103.656 ;
    END
  END a_d[80]
  PIN a_d[81]
    DIRECTION INPUT ;
    USE SIGNAL ;
    PORT
      LAYER M5 ;
        RECT  9.36 103.572 9.384 103.656 ;
    END
  END a_d[81]
  PIN a_d[82]
    DIRECTION INPUT ;
    USE SIGNAL ;
    PORT
      LAYER M5 ;
        RECT  9.456 103.572 9.48 103.656 ;
    END
  END a_d[82]
  PIN a_d[83]
    DIRECTION INPUT ;
    USE SIGNAL ;
    PORT
      LAYER M5 ;
        RECT  9.552 103.572 9.576 103.656 ;
    END
  END a_d[83]
  PIN a_d[84]
    DIRECTION INPUT ;
    USE SIGNAL ;
    PORT
      LAYER M5 ;
        RECT  9.648 103.572 9.672 103.656 ;
    END
  END a_d[84]
  PIN a_d[85]
    DIRECTION INPUT ;
    USE SIGNAL ;
    PORT
      LAYER M5 ;
        RECT  9.744 103.572 9.768 103.656 ;
    END
  END a_d[85]
  PIN a_d[86]
    DIRECTION INPUT ;
    USE SIGNAL ;
    PORT
      LAYER M5 ;
        RECT  9.84 103.572 9.864 103.656 ;
    END
  END a_d[86]
  PIN a_d[87]
    DIRECTION INPUT ;
    USE SIGNAL ;
    PORT
      LAYER M5 ;
        RECT  9.936 103.572 9.96 103.656 ;
    END
  END a_d[87]
  PIN a_d[88]
    DIRECTION INPUT ;
    USE SIGNAL ;
    PORT
      LAYER M5 ;
        RECT  10.032 103.572 10.056 103.656 ;
    END
  END a_d[88]
  PIN a_d[89]
    DIRECTION INPUT ;
    USE SIGNAL ;
    PORT
      LAYER M5 ;
        RECT  10.128 103.572 10.152 103.656 ;
    END
  END a_d[89]
  PIN a_d[8]
    DIRECTION INPUT ;
    USE SIGNAL ;
    PORT
      LAYER M5 ;
        RECT  2.208 103.572 2.232 103.656 ;
    END
  END a_d[8]
  PIN a_d[90]
    DIRECTION INPUT ;
    USE SIGNAL ;
    PORT
      LAYER M5 ;
        RECT  10.272 103.572 10.296 103.656 ;
    END
  END a_d[90]
  PIN a_d[91]
    DIRECTION INPUT ;
    USE SIGNAL ;
    PORT
      LAYER M5 ;
        RECT  10.368 103.572 10.392 103.656 ;
    END
  END a_d[91]
  PIN a_d[92]
    DIRECTION INPUT ;
    USE SIGNAL ;
    PORT
      LAYER M5 ;
        RECT  10.464 103.572 10.488 103.656 ;
    END
  END a_d[92]
  PIN a_d[93]
    DIRECTION INPUT ;
    USE SIGNAL ;
    PORT
      LAYER M5 ;
        RECT  10.56 103.572 10.584 103.656 ;
    END
  END a_d[93]
  PIN a_d[94]
    DIRECTION INPUT ;
    USE SIGNAL ;
    PORT
      LAYER M5 ;
        RECT  10.656 103.572 10.68 103.656 ;
    END
  END a_d[94]
  PIN a_d[95]
    DIRECTION INPUT ;
    USE SIGNAL ;
    PORT
      LAYER M5 ;
        RECT  10.752 103.572 10.776 103.656 ;
    END
  END a_d[95]
  PIN a_d[96]
    DIRECTION INPUT ;
    USE SIGNAL ;
    PORT
      LAYER M5 ;
        RECT  10.848 103.572 10.872 103.656 ;
    END
  END a_d[96]
  PIN a_d[97]
    DIRECTION INPUT ;
    USE SIGNAL ;
    PORT
      LAYER M5 ;
        RECT  10.944 103.572 10.968 103.656 ;
    END
  END a_d[97]
  PIN a_d[98]
    DIRECTION INPUT ;
    USE SIGNAL ;
    PORT
      LAYER M5 ;
        RECT  11.04 103.572 11.064 103.656 ;
    END
  END a_d[98]
  PIN a_d[99]
    DIRECTION INPUT ;
    USE SIGNAL ;
    PORT
      LAYER M5 ;
        RECT  11.136 103.572 11.16 103.656 ;
    END
  END a_d[99]
  PIN a_d[9]
    DIRECTION INPUT ;
    USE SIGNAL ;
    PORT
      LAYER M5 ;
        RECT  2.304 103.572 2.328 103.656 ;
    END
  END a_d[9]
  PIN b_d[0]
    DIRECTION OUTPUT ;
    USE SIGNAL ;
    PORT
      LAYER M5 ;
        RECT  0.768 0 0.792 0.084 ;
    END
  END b_d[0]
  PIN b_d[100]
    DIRECTION OUTPUT ;
    USE SIGNAL ;
    PORT
      LAYER M5 ;
        RECT  10.56 0 10.584 0.084 ;
    END
  END b_d[100]
  PIN b_d[101]
    DIRECTION OUTPUT ;
    USE SIGNAL ;
    PORT
      LAYER M5 ;
        RECT  10.656 0 10.68 0.084 ;
    END
  END b_d[101]
  PIN b_d[102]
    DIRECTION OUTPUT ;
    USE SIGNAL ;
    PORT
      LAYER M5 ;
        RECT  10.752 0 10.776 0.084 ;
    END
  END b_d[102]
  PIN b_d[103]
    DIRECTION OUTPUT ;
    USE SIGNAL ;
    PORT
      LAYER M5 ;
        RECT  10.848 0 10.872 0.084 ;
    END
  END b_d[103]
  PIN b_d[104]
    DIRECTION OUTPUT ;
    USE SIGNAL ;
    PORT
      LAYER M5 ;
        RECT  10.944 0 10.968 0.084 ;
    END
  END b_d[104]
  PIN b_d[105]
    DIRECTION OUTPUT ;
    USE SIGNAL ;
    PORT
      LAYER M5 ;
        RECT  11.088 0 11.112 0.084 ;
    END
  END b_d[105]
  PIN b_d[106]
    DIRECTION OUTPUT ;
    USE SIGNAL ;
    PORT
      LAYER M5 ;
        RECT  11.184 0 11.208 0.084 ;
    END
  END b_d[106]
  PIN b_d[107]
    DIRECTION OUTPUT ;
    USE SIGNAL ;
    PORT
      LAYER M5 ;
        RECT  11.28 0 11.304 0.084 ;
    END
  END b_d[107]
  PIN b_d[108]
    DIRECTION OUTPUT ;
    USE SIGNAL ;
    PORT
      LAYER M5 ;
        RECT  11.376 0 11.4 0.084 ;
    END
  END b_d[108]
  PIN b_d[109]
    DIRECTION OUTPUT ;
    USE SIGNAL ;
    PORT
      LAYER M5 ;
        RECT  11.472 0 11.496 0.084 ;
    END
  END b_d[109]
  PIN b_d[10]
    DIRECTION OUTPUT ;
    USE SIGNAL ;
    PORT
      LAYER M5 ;
        RECT  1.728 0 1.752 0.084 ;
    END
  END b_d[10]
  PIN b_d[110]
    DIRECTION OUTPUT ;
    USE SIGNAL ;
    PORT
      LAYER M5 ;
        RECT  11.568 0 11.592 0.084 ;
    END
  END b_d[110]
  PIN b_d[111]
    DIRECTION OUTPUT ;
    USE SIGNAL ;
    PORT
      LAYER M5 ;
        RECT  11.664 0 11.688 0.084 ;
    END
  END b_d[111]
  PIN b_d[112]
    DIRECTION OUTPUT ;
    USE SIGNAL ;
    PORT
      LAYER M5 ;
        RECT  11.76 0 11.784 0.084 ;
    END
  END b_d[112]
  PIN b_d[113]
    DIRECTION OUTPUT ;
    USE SIGNAL ;
    PORT
      LAYER M5 ;
        RECT  11.856 0 11.88 0.084 ;
    END
  END b_d[113]
  PIN b_d[114]
    DIRECTION OUTPUT ;
    USE SIGNAL ;
    PORT
      LAYER M5 ;
        RECT  11.952 0 11.976 0.084 ;
    END
  END b_d[114]
  PIN b_d[115]
    DIRECTION OUTPUT ;
    USE SIGNAL ;
    PORT
      LAYER M5 ;
        RECT  12.048 0 12.072 0.084 ;
    END
  END b_d[115]
  PIN b_d[116]
    DIRECTION OUTPUT ;
    USE SIGNAL ;
    PORT
      LAYER M5 ;
        RECT  12.144 0 12.168 0.084 ;
    END
  END b_d[116]
  PIN b_d[117]
    DIRECTION OUTPUT ;
    USE SIGNAL ;
    PORT
      LAYER M5 ;
        RECT  12.24 0 12.264 0.084 ;
    END
  END b_d[117]
  PIN b_d[118]
    DIRECTION OUTPUT ;
    USE SIGNAL ;
    PORT
      LAYER M5 ;
        RECT  12.336 0 12.36 0.084 ;
    END
  END b_d[118]
  PIN b_d[119]
    DIRECTION OUTPUT ;
    USE SIGNAL ;
    PORT
      LAYER M5 ;
        RECT  12.432 0 12.456 0.084 ;
    END
  END b_d[119]
  PIN b_d[11]
    DIRECTION OUTPUT ;
    USE SIGNAL ;
    PORT
      LAYER M5 ;
        RECT  1.872 0 1.896 0.084 ;
    END
  END b_d[11]
  PIN b_d[120]
    DIRECTION OUTPUT ;
    USE SIGNAL ;
    PORT
      LAYER M5 ;
        RECT  12.528 0 12.552 0.084 ;
    END
  END b_d[120]
  PIN b_d[121]
    DIRECTION OUTPUT ;
    USE SIGNAL ;
    PORT
      LAYER M5 ;
        RECT  12.624 0 12.648 0.084 ;
    END
  END b_d[121]
  PIN b_d[122]
    DIRECTION OUTPUT ;
    USE SIGNAL ;
    PORT
      LAYER M5 ;
        RECT  12.72 0 12.744 0.084 ;
    END
  END b_d[122]
  PIN b_d[123]
    DIRECTION OUTPUT ;
    USE SIGNAL ;
    PORT
      LAYER M5 ;
        RECT  12.816 0 12.84 0.084 ;
    END
  END b_d[123]
  PIN b_d[124]
    DIRECTION OUTPUT ;
    USE SIGNAL ;
    PORT
      LAYER M5 ;
        RECT  12.912 0 12.936 0.084 ;
    END
  END b_d[124]
  PIN b_d[125]
    DIRECTION OUTPUT ;
    USE SIGNAL ;
    PORT
      LAYER M5 ;
        RECT  13.008 0 13.032 0.084 ;
    END
  END b_d[125]
  PIN b_d[126]
    DIRECTION OUTPUT ;
    USE SIGNAL ;
    PORT
      LAYER M5 ;
        RECT  13.104 0 13.128 0.084 ;
    END
  END b_d[126]
  PIN b_d[127]
    DIRECTION OUTPUT ;
    USE SIGNAL ;
    PORT
      LAYER M5 ;
        RECT  13.2 0 13.224 0.084 ;
    END
  END b_d[127]
  PIN b_d[128]
    DIRECTION OUTPUT ;
    USE SIGNAL ;
    PORT
      LAYER M5 ;
        RECT  13.296 0 13.32 0.084 ;
    END
  END b_d[128]
  PIN b_d[129]
    DIRECTION OUTPUT ;
    USE SIGNAL ;
    PORT
      LAYER M5 ;
        RECT  13.44 0 13.464 0.084 ;
    END
  END b_d[129]
  PIN b_d[12]
    DIRECTION OUTPUT ;
    USE SIGNAL ;
    PORT
      LAYER M5 ;
        RECT  1.968 0 1.992 0.084 ;
    END
  END b_d[12]
  PIN b_d[130]
    DIRECTION OUTPUT ;
    USE SIGNAL ;
    PORT
      LAYER M5 ;
        RECT  13.536 0 13.56 0.084 ;
    END
  END b_d[130]
  PIN b_d[131]
    DIRECTION OUTPUT ;
    USE SIGNAL ;
    PORT
      LAYER M5 ;
        RECT  13.632 0 13.656 0.084 ;
    END
  END b_d[131]
  PIN b_d[132]
    DIRECTION OUTPUT ;
    USE SIGNAL ;
    PORT
      LAYER M5 ;
        RECT  13.728 0 13.752 0.084 ;
    END
  END b_d[132]
  PIN b_d[133]
    DIRECTION OUTPUT ;
    USE SIGNAL ;
    PORT
      LAYER M5 ;
        RECT  13.824 0 13.848 0.084 ;
    END
  END b_d[133]
  PIN b_d[134]
    DIRECTION OUTPUT ;
    USE SIGNAL ;
    PORT
      LAYER M5 ;
        RECT  13.92 0 13.944 0.084 ;
    END
  END b_d[134]
  PIN b_d[135]
    DIRECTION OUTPUT ;
    USE SIGNAL ;
    PORT
      LAYER M5 ;
        RECT  14.016 0 14.04 0.084 ;
    END
  END b_d[135]
  PIN b_d[136]
    DIRECTION OUTPUT ;
    USE SIGNAL ;
    PORT
      LAYER M5 ;
        RECT  14.112 0 14.136 0.084 ;
    END
  END b_d[136]
  PIN b_d[137]
    DIRECTION OUTPUT ;
    USE SIGNAL ;
    PORT
      LAYER M5 ;
        RECT  14.208 0 14.232 0.084 ;
    END
  END b_d[137]
  PIN b_d[138]
    DIRECTION OUTPUT ;
    USE SIGNAL ;
    PORT
      LAYER M5 ;
        RECT  14.304 0 14.328 0.084 ;
    END
  END b_d[138]
  PIN b_d[139]
    DIRECTION OUTPUT ;
    USE SIGNAL ;
    PORT
      LAYER M5 ;
        RECT  14.4 0 14.424 0.084 ;
    END
  END b_d[139]
  PIN b_d[13]
    DIRECTION OUTPUT ;
    USE SIGNAL ;
    PORT
      LAYER M5 ;
        RECT  2.064 0 2.088 0.084 ;
    END
  END b_d[13]
  PIN b_d[140]
    DIRECTION OUTPUT ;
    USE SIGNAL ;
    PORT
      LAYER M5 ;
        RECT  14.496 0 14.52 0.084 ;
    END
  END b_d[140]
  PIN b_d[141]
    DIRECTION OUTPUT ;
    USE SIGNAL ;
    PORT
      LAYER M5 ;
        RECT  14.592 0 14.616 0.084 ;
    END
  END b_d[141]
  PIN b_d[142]
    DIRECTION OUTPUT ;
    USE SIGNAL ;
    PORT
      LAYER M5 ;
        RECT  14.688 0 14.712 0.084 ;
    END
  END b_d[142]
  PIN b_d[143]
    DIRECTION OUTPUT ;
    USE SIGNAL ;
    PORT
      LAYER M5 ;
        RECT  14.784 0 14.808 0.084 ;
    END
  END b_d[143]
  PIN b_d[144]
    DIRECTION OUTPUT ;
    USE SIGNAL ;
    PORT
      LAYER M5 ;
        RECT  14.88 0 14.904 0.084 ;
    END
  END b_d[144]
  PIN b_d[145]
    DIRECTION OUTPUT ;
    USE SIGNAL ;
    PORT
      LAYER M5 ;
        RECT  14.976 0 15 0.084 ;
    END
  END b_d[145]
  PIN b_d[146]
    DIRECTION OUTPUT ;
    USE SIGNAL ;
    PORT
      LAYER M5 ;
        RECT  15.072 0 15.096 0.084 ;
    END
  END b_d[146]
  PIN b_d[147]
    DIRECTION OUTPUT ;
    USE SIGNAL ;
    PORT
      LAYER M5 ;
        RECT  15.168 0 15.192 0.084 ;
    END
  END b_d[147]
  PIN b_d[148]
    DIRECTION OUTPUT ;
    USE SIGNAL ;
    PORT
      LAYER M5 ;
        RECT  15.264 0 15.288 0.084 ;
    END
  END b_d[148]
  PIN b_d[149]
    DIRECTION OUTPUT ;
    USE SIGNAL ;
    PORT
      LAYER M5 ;
        RECT  15.36 0 15.384 0.084 ;
    END
  END b_d[149]
  PIN b_d[14]
    DIRECTION OUTPUT ;
    USE SIGNAL ;
    PORT
      LAYER M5 ;
        RECT  2.16 0 2.184 0.084 ;
    END
  END b_d[14]
  PIN b_d[150]
    DIRECTION OUTPUT ;
    USE SIGNAL ;
    PORT
      LAYER M5 ;
        RECT  15.456 0 15.48 0.084 ;
    END
  END b_d[150]
  PIN b_d[151]
    DIRECTION OUTPUT ;
    USE SIGNAL ;
    PORT
      LAYER M5 ;
        RECT  15.552 0 15.576 0.084 ;
    END
  END b_d[151]
  PIN b_d[152]
    DIRECTION OUTPUT ;
    USE SIGNAL ;
    PORT
      LAYER M5 ;
        RECT  15.696 0 15.72 0.084 ;
    END
  END b_d[152]
  PIN b_d[153]
    DIRECTION OUTPUT ;
    USE SIGNAL ;
    PORT
      LAYER M5 ;
        RECT  15.792 0 15.816 0.084 ;
    END
  END b_d[153]
  PIN b_d[154]
    DIRECTION OUTPUT ;
    USE SIGNAL ;
    PORT
      LAYER M5 ;
        RECT  15.888 0 15.912 0.084 ;
    END
  END b_d[154]
  PIN b_d[155]
    DIRECTION OUTPUT ;
    USE SIGNAL ;
    PORT
      LAYER M5 ;
        RECT  15.984 0 16.008 0.084 ;
    END
  END b_d[155]
  PIN b_d[156]
    DIRECTION OUTPUT ;
    USE SIGNAL ;
    PORT
      LAYER M5 ;
        RECT  16.08 0 16.104 0.084 ;
    END
  END b_d[156]
  PIN b_d[157]
    DIRECTION OUTPUT ;
    USE SIGNAL ;
    PORT
      LAYER M5 ;
        RECT  16.176 0 16.2 0.084 ;
    END
  END b_d[157]
  PIN b_d[158]
    DIRECTION OUTPUT ;
    USE SIGNAL ;
    PORT
      LAYER M5 ;
        RECT  16.272 0 16.296 0.084 ;
    END
  END b_d[158]
  PIN b_d[159]
    DIRECTION OUTPUT ;
    USE SIGNAL ;
    PORT
      LAYER M5 ;
        RECT  16.368 0 16.392 0.084 ;
    END
  END b_d[159]
  PIN b_d[15]
    DIRECTION OUTPUT ;
    USE SIGNAL ;
    PORT
      LAYER M5 ;
        RECT  2.256 0 2.28 0.084 ;
    END
  END b_d[15]
  PIN b_d[160]
    DIRECTION OUTPUT ;
    USE SIGNAL ;
    PORT
      LAYER M5 ;
        RECT  16.464 0 16.488 0.084 ;
    END
  END b_d[160]
  PIN b_d[161]
    DIRECTION OUTPUT ;
    USE SIGNAL ;
    PORT
      LAYER M5 ;
        RECT  16.56 0 16.584 0.084 ;
    END
  END b_d[161]
  PIN b_d[162]
    DIRECTION OUTPUT ;
    USE SIGNAL ;
    PORT
      LAYER M5 ;
        RECT  16.656 0 16.68 0.084 ;
    END
  END b_d[162]
  PIN b_d[163]
    DIRECTION OUTPUT ;
    USE SIGNAL ;
    PORT
      LAYER M5 ;
        RECT  16.752 0 16.776 0.084 ;
    END
  END b_d[163]
  PIN b_d[164]
    DIRECTION OUTPUT ;
    USE SIGNAL ;
    PORT
      LAYER M5 ;
        RECT  16.848 0 16.872 0.084 ;
    END
  END b_d[164]
  PIN b_d[165]
    DIRECTION OUTPUT ;
    USE SIGNAL ;
    PORT
      LAYER M5 ;
        RECT  16.944 0 16.968 0.084 ;
    END
  END b_d[165]
  PIN b_d[166]
    DIRECTION OUTPUT ;
    USE SIGNAL ;
    PORT
      LAYER M5 ;
        RECT  17.04 0 17.064 0.084 ;
    END
  END b_d[166]
  PIN b_d[167]
    DIRECTION OUTPUT ;
    USE SIGNAL ;
    PORT
      LAYER M5 ;
        RECT  17.136 0 17.16 0.084 ;
    END
  END b_d[167]
  PIN b_d[168]
    DIRECTION OUTPUT ;
    USE SIGNAL ;
    PORT
      LAYER M5 ;
        RECT  17.232 0 17.256 0.084 ;
    END
  END b_d[168]
  PIN b_d[169]
    DIRECTION OUTPUT ;
    USE SIGNAL ;
    PORT
      LAYER M5 ;
        RECT  17.328 0 17.352 0.084 ;
    END
  END b_d[169]
  PIN b_d[16]
    DIRECTION OUTPUT ;
    USE SIGNAL ;
    PORT
      LAYER M5 ;
        RECT  2.352 0 2.376 0.084 ;
    END
  END b_d[16]
  PIN b_d[170]
    DIRECTION OUTPUT ;
    USE SIGNAL ;
    PORT
      LAYER M5 ;
        RECT  17.424 0 17.448 0.084 ;
    END
  END b_d[170]
  PIN b_d[171]
    DIRECTION OUTPUT ;
    USE SIGNAL ;
    PORT
      LAYER M5 ;
        RECT  17.52 0 17.544 0.084 ;
    END
  END b_d[171]
  PIN b_d[172]
    DIRECTION OUTPUT ;
    USE SIGNAL ;
    PORT
      LAYER M5 ;
        RECT  17.616 0 17.64 0.084 ;
    END
  END b_d[172]
  PIN b_d[173]
    DIRECTION OUTPUT ;
    USE SIGNAL ;
    PORT
      LAYER M5 ;
        RECT  17.712 0 17.736 0.084 ;
    END
  END b_d[173]
  PIN b_d[174]
    DIRECTION OUTPUT ;
    USE SIGNAL ;
    PORT
      LAYER M5 ;
        RECT  17.808 0 17.832 0.084 ;
    END
  END b_d[174]
  PIN b_d[175]
    DIRECTION OUTPUT ;
    USE SIGNAL ;
    PORT
      LAYER M5 ;
        RECT  17.904 0 17.928 0.084 ;
    END
  END b_d[175]
  PIN b_d[176]
    DIRECTION OUTPUT ;
    USE SIGNAL ;
    PORT
      LAYER M5 ;
        RECT  18.048 0 18.072 0.084 ;
    END
  END b_d[176]
  PIN b_d[177]
    DIRECTION OUTPUT ;
    USE SIGNAL ;
    PORT
      LAYER M5 ;
        RECT  18.144 0 18.168 0.084 ;
    END
  END b_d[177]
  PIN b_d[178]
    DIRECTION OUTPUT ;
    USE SIGNAL ;
    PORT
      LAYER M5 ;
        RECT  18.24 0 18.264 0.084 ;
    END
  END b_d[178]
  PIN b_d[179]
    DIRECTION OUTPUT ;
    USE SIGNAL ;
    PORT
      LAYER M5 ;
        RECT  18.336 0 18.36 0.084 ;
    END
  END b_d[179]
  PIN b_d[17]
    DIRECTION OUTPUT ;
    USE SIGNAL ;
    PORT
      LAYER M5 ;
        RECT  2.448 0 2.472 0.084 ;
    END
  END b_d[17]
  PIN b_d[180]
    DIRECTION OUTPUT ;
    USE SIGNAL ;
    PORT
      LAYER M5 ;
        RECT  18.432 0 18.456 0.084 ;
    END
  END b_d[180]
  PIN b_d[181]
    DIRECTION OUTPUT ;
    USE SIGNAL ;
    PORT
      LAYER M5 ;
        RECT  18.528 0 18.552 0.084 ;
    END
  END b_d[181]
  PIN b_d[182]
    DIRECTION OUTPUT ;
    USE SIGNAL ;
    PORT
      LAYER M5 ;
        RECT  18.624 0 18.648 0.084 ;
    END
  END b_d[182]
  PIN b_d[183]
    DIRECTION OUTPUT ;
    USE SIGNAL ;
    PORT
      LAYER M5 ;
        RECT  18.72 0 18.744 0.084 ;
    END
  END b_d[183]
  PIN b_d[184]
    DIRECTION OUTPUT ;
    USE SIGNAL ;
    PORT
      LAYER M5 ;
        RECT  18.816 0 18.84 0.084 ;
    END
  END b_d[184]
  PIN b_d[185]
    DIRECTION OUTPUT ;
    USE SIGNAL ;
    PORT
      LAYER M5 ;
        RECT  18.912 0 18.936 0.084 ;
    END
  END b_d[185]
  PIN b_d[186]
    DIRECTION OUTPUT ;
    USE SIGNAL ;
    PORT
      LAYER M5 ;
        RECT  19.008 0 19.032 0.084 ;
    END
  END b_d[186]
  PIN b_d[187]
    DIRECTION OUTPUT ;
    USE SIGNAL ;
    PORT
      LAYER M5 ;
        RECT  19.104 0 19.128 0.084 ;
    END
  END b_d[187]
  PIN b_d[188]
    DIRECTION OUTPUT ;
    USE SIGNAL ;
    PORT
      LAYER M5 ;
        RECT  19.2 0 19.224 0.084 ;
    END
  END b_d[188]
  PIN b_d[189]
    DIRECTION OUTPUT ;
    USE SIGNAL ;
    PORT
      LAYER M5 ;
        RECT  19.296 0 19.32 0.084 ;
    END
  END b_d[189]
  PIN b_d[18]
    DIRECTION OUTPUT ;
    USE SIGNAL ;
    PORT
      LAYER M5 ;
        RECT  2.544 0 2.568 0.084 ;
    END
  END b_d[18]
  PIN b_d[190]
    DIRECTION OUTPUT ;
    USE SIGNAL ;
    PORT
      LAYER M5 ;
        RECT  19.392 0 19.416 0.084 ;
    END
  END b_d[190]
  PIN b_d[191]
    DIRECTION OUTPUT ;
    USE SIGNAL ;
    PORT
      LAYER M5 ;
        RECT  19.488 0 19.512 0.084 ;
    END
  END b_d[191]
  PIN b_d[192]
    DIRECTION OUTPUT ;
    USE SIGNAL ;
    PORT
      LAYER M5 ;
        RECT  19.584 0 19.608 0.084 ;
    END
  END b_d[192]
  PIN b_d[193]
    DIRECTION OUTPUT ;
    USE SIGNAL ;
    PORT
      LAYER M5 ;
        RECT  19.68 0 19.704 0.084 ;
    END
  END b_d[193]
  PIN b_d[194]
    DIRECTION OUTPUT ;
    USE SIGNAL ;
    PORT
      LAYER M5 ;
        RECT  19.776 0 19.8 0.084 ;
    END
  END b_d[194]
  PIN b_d[195]
    DIRECTION OUTPUT ;
    USE SIGNAL ;
    PORT
      LAYER M5 ;
        RECT  19.872 0 19.896 0.084 ;
    END
  END b_d[195]
  PIN b_d[196]
    DIRECTION OUTPUT ;
    USE SIGNAL ;
    PORT
      LAYER M5 ;
        RECT  19.968 0 19.992 0.084 ;
    END
  END b_d[196]
  PIN b_d[197]
    DIRECTION OUTPUT ;
    USE SIGNAL ;
    PORT
      LAYER M5 ;
        RECT  20.064 0 20.088 0.084 ;
    END
  END b_d[197]
  PIN b_d[198]
    DIRECTION OUTPUT ;
    USE SIGNAL ;
    PORT
      LAYER M5 ;
        RECT  20.16 0 20.184 0.084 ;
    END
  END b_d[198]
  PIN b_d[199]
    DIRECTION OUTPUT ;
    USE SIGNAL ;
    PORT
      LAYER M5 ;
        RECT  20.304 0 20.328 0.084 ;
    END
  END b_d[199]
  PIN b_d[19]
    DIRECTION OUTPUT ;
    USE SIGNAL ;
    PORT
      LAYER M5 ;
        RECT  2.64 0 2.664 0.084 ;
    END
  END b_d[19]
  PIN b_d[1]
    DIRECTION OUTPUT ;
    USE SIGNAL ;
    PORT
      LAYER M5 ;
        RECT  0.864 0 0.888 0.084 ;
    END
  END b_d[1]
  PIN b_d[200]
    DIRECTION OUTPUT ;
    USE SIGNAL ;
    PORT
      LAYER M5 ;
        RECT  20.4 0 20.424 0.084 ;
    END
  END b_d[200]
  PIN b_d[201]
    DIRECTION OUTPUT ;
    USE SIGNAL ;
    PORT
      LAYER M5 ;
        RECT  20.496 0 20.52 0.084 ;
    END
  END b_d[201]
  PIN b_d[202]
    DIRECTION OUTPUT ;
    USE SIGNAL ;
    PORT
      LAYER M5 ;
        RECT  20.592 0 20.616 0.084 ;
    END
  END b_d[202]
  PIN b_d[203]
    DIRECTION OUTPUT ;
    USE SIGNAL ;
    PORT
      LAYER M5 ;
        RECT  20.688 0 20.712 0.084 ;
    END
  END b_d[203]
  PIN b_d[204]
    DIRECTION OUTPUT ;
    USE SIGNAL ;
    PORT
      LAYER M5 ;
        RECT  20.784 0 20.808 0.084 ;
    END
  END b_d[204]
  PIN b_d[205]
    DIRECTION OUTPUT ;
    USE SIGNAL ;
    PORT
      LAYER M5 ;
        RECT  20.88 0 20.904 0.084 ;
    END
  END b_d[205]
  PIN b_d[206]
    DIRECTION OUTPUT ;
    USE SIGNAL ;
    PORT
      LAYER M5 ;
        RECT  20.976 0 21 0.084 ;
    END
  END b_d[206]
  PIN b_d[207]
    DIRECTION OUTPUT ;
    USE SIGNAL ;
    PORT
      LAYER M5 ;
        RECT  21.072 0 21.096 0.084 ;
    END
  END b_d[207]
  PIN b_d[208]
    DIRECTION OUTPUT ;
    USE SIGNAL ;
    PORT
      LAYER M5 ;
        RECT  21.168 0 21.192 0.084 ;
    END
  END b_d[208]
  PIN b_d[209]
    DIRECTION OUTPUT ;
    USE SIGNAL ;
    PORT
      LAYER M5 ;
        RECT  21.264 0 21.288 0.084 ;
    END
  END b_d[209]
  PIN b_d[20]
    DIRECTION OUTPUT ;
    USE SIGNAL ;
    PORT
      LAYER M5 ;
        RECT  2.736 0 2.76 0.084 ;
    END
  END b_d[20]
  PIN b_d[210]
    DIRECTION OUTPUT ;
    USE SIGNAL ;
    PORT
      LAYER M5 ;
        RECT  21.36 0 21.384 0.084 ;
    END
  END b_d[210]
  PIN b_d[211]
    DIRECTION OUTPUT ;
    USE SIGNAL ;
    PORT
      LAYER M5 ;
        RECT  21.456 0 21.48 0.084 ;
    END
  END b_d[211]
  PIN b_d[212]
    DIRECTION OUTPUT ;
    USE SIGNAL ;
    PORT
      LAYER M5 ;
        RECT  21.552 0 21.576 0.084 ;
    END
  END b_d[212]
  PIN b_d[213]
    DIRECTION OUTPUT ;
    USE SIGNAL ;
    PORT
      LAYER M5 ;
        RECT  21.648 0 21.672 0.084 ;
    END
  END b_d[213]
  PIN b_d[214]
    DIRECTION OUTPUT ;
    USE SIGNAL ;
    PORT
      LAYER M5 ;
        RECT  21.744 0 21.768 0.084 ;
    END
  END b_d[214]
  PIN b_d[215]
    DIRECTION OUTPUT ;
    USE SIGNAL ;
    PORT
      LAYER M5 ;
        RECT  21.84 0 21.864 0.084 ;
    END
  END b_d[215]
  PIN b_d[216]
    DIRECTION OUTPUT ;
    USE SIGNAL ;
    PORT
      LAYER M5 ;
        RECT  21.936 0 21.96 0.084 ;
    END
  END b_d[216]
  PIN b_d[217]
    DIRECTION OUTPUT ;
    USE SIGNAL ;
    PORT
      LAYER M5 ;
        RECT  22.032 0 22.056 0.084 ;
    END
  END b_d[217]
  PIN b_d[218]
    DIRECTION OUTPUT ;
    USE SIGNAL ;
    PORT
      LAYER M5 ;
        RECT  22.128 0 22.152 0.084 ;
    END
  END b_d[218]
  PIN b_d[219]
    DIRECTION OUTPUT ;
    USE SIGNAL ;
    PORT
      LAYER M5 ;
        RECT  22.224 0 22.248 0.084 ;
    END
  END b_d[219]
  PIN b_d[21]
    DIRECTION OUTPUT ;
    USE SIGNAL ;
    PORT
      LAYER M5 ;
        RECT  2.832 0 2.856 0.084 ;
    END
  END b_d[21]
  PIN b_d[220]
    DIRECTION OUTPUT ;
    USE SIGNAL ;
    PORT
      LAYER M5 ;
        RECT  22.32 0 22.344 0.084 ;
    END
  END b_d[220]
  PIN b_d[221]
    DIRECTION OUTPUT ;
    USE SIGNAL ;
    PORT
      LAYER M5 ;
        RECT  22.416 0 22.44 0.084 ;
    END
  END b_d[221]
  PIN b_d[222]
    DIRECTION OUTPUT ;
    USE SIGNAL ;
    PORT
      LAYER M5 ;
        RECT  22.512 0 22.536 0.084 ;
    END
  END b_d[222]
  PIN b_d[223]
    DIRECTION OUTPUT ;
    USE SIGNAL ;
    PORT
      LAYER M5 ;
        RECT  22.656 0 22.68 0.084 ;
    END
  END b_d[223]
  PIN b_d[224]
    DIRECTION OUTPUT ;
    USE SIGNAL ;
    PORT
      LAYER M5 ;
        RECT  22.752 0 22.776 0.084 ;
    END
  END b_d[224]
  PIN b_d[225]
    DIRECTION OUTPUT ;
    USE SIGNAL ;
    PORT
      LAYER M5 ;
        RECT  22.848 0 22.872 0.084 ;
    END
  END b_d[225]
  PIN b_d[226]
    DIRECTION OUTPUT ;
    USE SIGNAL ;
    PORT
      LAYER M5 ;
        RECT  22.944 0 22.968 0.084 ;
    END
  END b_d[226]
  PIN b_d[227]
    DIRECTION OUTPUT ;
    USE SIGNAL ;
    PORT
      LAYER M5 ;
        RECT  23.04 0 23.064 0.084 ;
    END
  END b_d[227]
  PIN b_d[228]
    DIRECTION OUTPUT ;
    USE SIGNAL ;
    PORT
      LAYER M5 ;
        RECT  23.136 0 23.16 0.084 ;
    END
  END b_d[228]
  PIN b_d[229]
    DIRECTION OUTPUT ;
    USE SIGNAL ;
    PORT
      LAYER M5 ;
        RECT  23.232 0 23.256 0.084 ;
    END
  END b_d[229]
  PIN b_d[22]
    DIRECTION OUTPUT ;
    USE SIGNAL ;
    PORT
      LAYER M5 ;
        RECT  2.928 0 2.952 0.084 ;
    END
  END b_d[22]
  PIN b_d[230]
    DIRECTION OUTPUT ;
    USE SIGNAL ;
    PORT
      LAYER M5 ;
        RECT  23.328 0 23.352 0.084 ;
    END
  END b_d[230]
  PIN b_d[231]
    DIRECTION OUTPUT ;
    USE SIGNAL ;
    PORT
      LAYER M5 ;
        RECT  23.424 0 23.448 0.084 ;
    END
  END b_d[231]
  PIN b_d[232]
    DIRECTION OUTPUT ;
    USE SIGNAL ;
    PORT
      LAYER M5 ;
        RECT  23.52 0 23.544 0.084 ;
    END
  END b_d[232]
  PIN b_d[233]
    DIRECTION OUTPUT ;
    USE SIGNAL ;
    PORT
      LAYER M5 ;
        RECT  23.616 0 23.64 0.084 ;
    END
  END b_d[233]
  PIN b_d[234]
    DIRECTION OUTPUT ;
    USE SIGNAL ;
    PORT
      LAYER M5 ;
        RECT  23.712 0 23.736 0.084 ;
    END
  END b_d[234]
  PIN b_d[235]
    DIRECTION OUTPUT ;
    USE SIGNAL ;
    PORT
      LAYER M5 ;
        RECT  23.808 0 23.832 0.084 ;
    END
  END b_d[235]
  PIN b_d[236]
    DIRECTION OUTPUT ;
    USE SIGNAL ;
    PORT
      LAYER M5 ;
        RECT  23.904 0 23.928 0.084 ;
    END
  END b_d[236]
  PIN b_d[237]
    DIRECTION OUTPUT ;
    USE SIGNAL ;
    PORT
      LAYER M5 ;
        RECT  24 0 24.024 0.084 ;
    END
  END b_d[237]
  PIN b_d[238]
    DIRECTION OUTPUT ;
    USE SIGNAL ;
    PORT
      LAYER M5 ;
        RECT  24.096 0 24.12 0.084 ;
    END
  END b_d[238]
  PIN b_d[239]
    DIRECTION OUTPUT ;
    USE SIGNAL ;
    PORT
      LAYER M5 ;
        RECT  24.192 0 24.216 0.084 ;
    END
  END b_d[239]
  PIN b_d[23]
    DIRECTION OUTPUT ;
    USE SIGNAL ;
    PORT
      LAYER M5 ;
        RECT  3.024 0 3.048 0.084 ;
    END
  END b_d[23]
  PIN b_d[240]
    DIRECTION OUTPUT ;
    USE SIGNAL ;
    PORT
      LAYER M5 ;
        RECT  24.288 0 24.312 0.084 ;
    END
  END b_d[240]
  PIN b_d[241]
    DIRECTION OUTPUT ;
    USE SIGNAL ;
    PORT
      LAYER M5 ;
        RECT  24.384 0 24.408 0.084 ;
    END
  END b_d[241]
  PIN b_d[242]
    DIRECTION OUTPUT ;
    USE SIGNAL ;
    PORT
      LAYER M5 ;
        RECT  24.48 0 24.504 0.084 ;
    END
  END b_d[242]
  PIN b_d[243]
    DIRECTION OUTPUT ;
    USE SIGNAL ;
    PORT
      LAYER M5 ;
        RECT  24.576 0 24.6 0.084 ;
    END
  END b_d[243]
  PIN b_d[244]
    DIRECTION OUTPUT ;
    USE SIGNAL ;
    PORT
      LAYER M5 ;
        RECT  24.672 0 24.696 0.084 ;
    END
  END b_d[244]
  PIN b_d[245]
    DIRECTION OUTPUT ;
    USE SIGNAL ;
    PORT
      LAYER M5 ;
        RECT  24.768 0 24.792 0.084 ;
    END
  END b_d[245]
  PIN b_d[246]
    DIRECTION OUTPUT ;
    USE SIGNAL ;
    PORT
      LAYER M5 ;
        RECT  24.912 0 24.936 0.084 ;
    END
  END b_d[246]
  PIN b_d[247]
    DIRECTION OUTPUT ;
    USE SIGNAL ;
    PORT
      LAYER M5 ;
        RECT  25.008 0 25.032 0.084 ;
    END
  END b_d[247]
  PIN b_d[248]
    DIRECTION OUTPUT ;
    USE SIGNAL ;
    PORT
      LAYER M5 ;
        RECT  25.104 0 25.128 0.084 ;
    END
  END b_d[248]
  PIN b_d[249]
    DIRECTION OUTPUT ;
    USE SIGNAL ;
    PORT
      LAYER M5 ;
        RECT  25.2 0 25.224 0.084 ;
    END
  END b_d[249]
  PIN b_d[24]
    DIRECTION OUTPUT ;
    USE SIGNAL ;
    PORT
      LAYER M5 ;
        RECT  3.12 0 3.144 0.084 ;
    END
  END b_d[24]
  PIN b_d[250]
    DIRECTION OUTPUT ;
    USE SIGNAL ;
    PORT
      LAYER M5 ;
        RECT  25.296 0 25.32 0.084 ;
    END
  END b_d[250]
  PIN b_d[251]
    DIRECTION OUTPUT ;
    USE SIGNAL ;
    PORT
      LAYER M5 ;
        RECT  25.392 0 25.416 0.084 ;
    END
  END b_d[251]
  PIN b_d[252]
    DIRECTION OUTPUT ;
    USE SIGNAL ;
    PORT
      LAYER M5 ;
        RECT  25.488 0 25.512 0.084 ;
    END
  END b_d[252]
  PIN b_d[253]
    DIRECTION OUTPUT ;
    USE SIGNAL ;
    PORT
      LAYER M5 ;
        RECT  25.584 0 25.608 0.084 ;
    END
  END b_d[253]
  PIN b_d[254]
    DIRECTION OUTPUT ;
    USE SIGNAL ;
    PORT
      LAYER M5 ;
        RECT  25.68 0 25.704 0.084 ;
    END
  END b_d[254]
  PIN b_d[255]
    DIRECTION OUTPUT ;
    USE SIGNAL ;
    PORT
      LAYER M5 ;
        RECT  25.776 0 25.8 0.084 ;
    END
  END b_d[255]
  PIN b_d[256]
    DIRECTION OUTPUT ;
    USE SIGNAL ;
    PORT
      LAYER M5 ;
        RECT  25.872 0 25.896 0.084 ;
    END
  END b_d[256]
  PIN b_d[257]
    DIRECTION OUTPUT ;
    USE SIGNAL ;
    PORT
      LAYER M5 ;
        RECT  25.968 0 25.992 0.084 ;
    END
  END b_d[257]
  PIN b_d[258]
    DIRECTION OUTPUT ;
    USE SIGNAL ;
    PORT
      LAYER M5 ;
        RECT  26.064 0 26.088 0.084 ;
    END
  END b_d[258]
  PIN b_d[259]
    DIRECTION OUTPUT ;
    USE SIGNAL ;
    PORT
      LAYER M5 ;
        RECT  26.16 0 26.184 0.084 ;
    END
  END b_d[259]
  PIN b_d[25]
    DIRECTION OUTPUT ;
    USE SIGNAL ;
    PORT
      LAYER M5 ;
        RECT  3.216 0 3.24 0.084 ;
    END
  END b_d[25]
  PIN b_d[260]
    DIRECTION OUTPUT ;
    USE SIGNAL ;
    PORT
      LAYER M5 ;
        RECT  26.256 0 26.28 0.084 ;
    END
  END b_d[260]
  PIN b_d[261]
    DIRECTION OUTPUT ;
    USE SIGNAL ;
    PORT
      LAYER M5 ;
        RECT  26.352 0 26.376 0.084 ;
    END
  END b_d[261]
  PIN b_d[262]
    DIRECTION OUTPUT ;
    USE SIGNAL ;
    PORT
      LAYER M5 ;
        RECT  26.448 0 26.472 0.084 ;
    END
  END b_d[262]
  PIN b_d[263]
    DIRECTION OUTPUT ;
    USE SIGNAL ;
    PORT
      LAYER M5 ;
        RECT  26.544 0 26.568 0.084 ;
    END
  END b_d[263]
  PIN b_d[264]
    DIRECTION OUTPUT ;
    USE SIGNAL ;
    PORT
      LAYER M5 ;
        RECT  26.64 0 26.664 0.084 ;
    END
  END b_d[264]
  PIN b_d[265]
    DIRECTION OUTPUT ;
    USE SIGNAL ;
    PORT
      LAYER M5 ;
        RECT  26.736 0 26.76 0.084 ;
    END
  END b_d[265]
  PIN b_d[266]
    DIRECTION OUTPUT ;
    USE SIGNAL ;
    PORT
      LAYER M5 ;
        RECT  26.832 0 26.856 0.084 ;
    END
  END b_d[266]
  PIN b_d[267]
    DIRECTION OUTPUT ;
    USE SIGNAL ;
    PORT
      LAYER M5 ;
        RECT  26.928 0 26.952 0.084 ;
    END
  END b_d[267]
  PIN b_d[268]
    DIRECTION OUTPUT ;
    USE SIGNAL ;
    PORT
      LAYER M5 ;
        RECT  27.024 0 27.048 0.084 ;
    END
  END b_d[268]
  PIN b_d[269]
    DIRECTION OUTPUT ;
    USE SIGNAL ;
    PORT
      LAYER M5 ;
        RECT  27.168 0 27.192 0.084 ;
    END
  END b_d[269]
  PIN b_d[26]
    DIRECTION OUTPUT ;
    USE SIGNAL ;
    PORT
      LAYER M5 ;
        RECT  3.312 0 3.336 0.084 ;
    END
  END b_d[26]
  PIN b_d[270]
    DIRECTION OUTPUT ;
    USE SIGNAL ;
    PORT
      LAYER M5 ;
        RECT  27.264 0 27.288 0.084 ;
    END
  END b_d[270]
  PIN b_d[271]
    DIRECTION OUTPUT ;
    USE SIGNAL ;
    PORT
      LAYER M5 ;
        RECT  27.36 0 27.384 0.084 ;
    END
  END b_d[271]
  PIN b_d[272]
    DIRECTION OUTPUT ;
    USE SIGNAL ;
    PORT
      LAYER M5 ;
        RECT  27.456 0 27.48 0.084 ;
    END
  END b_d[272]
  PIN b_d[273]
    DIRECTION OUTPUT ;
    USE SIGNAL ;
    PORT
      LAYER M5 ;
        RECT  27.552 0 27.576 0.084 ;
    END
  END b_d[273]
  PIN b_d[274]
    DIRECTION OUTPUT ;
    USE SIGNAL ;
    PORT
      LAYER M5 ;
        RECT  27.648 0 27.672 0.084 ;
    END
  END b_d[274]
  PIN b_d[275]
    DIRECTION OUTPUT ;
    USE SIGNAL ;
    PORT
      LAYER M5 ;
        RECT  27.744 0 27.768 0.084 ;
    END
  END b_d[275]
  PIN b_d[276]
    DIRECTION OUTPUT ;
    USE SIGNAL ;
    PORT
      LAYER M5 ;
        RECT  27.84 0 27.864 0.084 ;
    END
  END b_d[276]
  PIN b_d[277]
    DIRECTION OUTPUT ;
    USE SIGNAL ;
    PORT
      LAYER M5 ;
        RECT  27.936 0 27.96 0.084 ;
    END
  END b_d[277]
  PIN b_d[278]
    DIRECTION OUTPUT ;
    USE SIGNAL ;
    PORT
      LAYER M5 ;
        RECT  28.032 0 28.056 0.084 ;
    END
  END b_d[278]
  PIN b_d[279]
    DIRECTION OUTPUT ;
    USE SIGNAL ;
    PORT
      LAYER M5 ;
        RECT  28.128 0 28.152 0.084 ;
    END
  END b_d[279]
  PIN b_d[27]
    DIRECTION OUTPUT ;
    USE SIGNAL ;
    PORT
      LAYER M5 ;
        RECT  3.408 0 3.432 0.084 ;
    END
  END b_d[27]
  PIN b_d[280]
    DIRECTION OUTPUT ;
    USE SIGNAL ;
    PORT
      LAYER M5 ;
        RECT  28.224 0 28.248 0.084 ;
    END
  END b_d[280]
  PIN b_d[281]
    DIRECTION OUTPUT ;
    USE SIGNAL ;
    PORT
      LAYER M5 ;
        RECT  28.32 0 28.344 0.084 ;
    END
  END b_d[281]
  PIN b_d[282]
    DIRECTION OUTPUT ;
    USE SIGNAL ;
    PORT
      LAYER M5 ;
        RECT  28.416 0 28.44 0.084 ;
    END
  END b_d[282]
  PIN b_d[283]
    DIRECTION OUTPUT ;
    USE SIGNAL ;
    PORT
      LAYER M5 ;
        RECT  28.512 0 28.536 0.084 ;
    END
  END b_d[283]
  PIN b_d[284]
    DIRECTION OUTPUT ;
    USE SIGNAL ;
    PORT
      LAYER M5 ;
        RECT  28.608 0 28.632 0.084 ;
    END
  END b_d[284]
  PIN b_d[285]
    DIRECTION OUTPUT ;
    USE SIGNAL ;
    PORT
      LAYER M5 ;
        RECT  28.704 0 28.728 0.084 ;
    END
  END b_d[285]
  PIN b_d[286]
    DIRECTION OUTPUT ;
    USE SIGNAL ;
    PORT
      LAYER M5 ;
        RECT  28.8 0 28.824 0.084 ;
    END
  END b_d[286]
  PIN b_d[287]
    DIRECTION OUTPUT ;
    USE SIGNAL ;
    PORT
      LAYER M5 ;
        RECT  28.896 0 28.92 0.084 ;
    END
  END b_d[287]
  PIN b_d[288]
    DIRECTION OUTPUT ;
    USE SIGNAL ;
    PORT
      LAYER M5 ;
        RECT  28.992 0 29.016 0.084 ;
    END
  END b_d[288]
  PIN b_d[289]
    DIRECTION OUTPUT ;
    USE SIGNAL ;
    PORT
      LAYER M5 ;
        RECT  29.088 0 29.112 0.084 ;
    END
  END b_d[289]
  PIN b_d[28]
    DIRECTION OUTPUT ;
    USE SIGNAL ;
    PORT
      LAYER M5 ;
        RECT  3.504 0 3.528 0.084 ;
    END
  END b_d[28]
  PIN b_d[290]
    DIRECTION OUTPUT ;
    USE SIGNAL ;
    PORT
      LAYER M5 ;
        RECT  29.184 0 29.208 0.084 ;
    END
  END b_d[290]
  PIN b_d[291]
    DIRECTION OUTPUT ;
    USE SIGNAL ;
    PORT
      LAYER M5 ;
        RECT  29.28 0 29.304 0.084 ;
    END
  END b_d[291]
  PIN b_d[292]
    DIRECTION OUTPUT ;
    USE SIGNAL ;
    PORT
      LAYER M5 ;
        RECT  29.376 0 29.4 0.084 ;
    END
  END b_d[292]
  PIN b_d[293]
    DIRECTION OUTPUT ;
    USE SIGNAL ;
    PORT
      LAYER M5 ;
        RECT  29.52 0 29.544 0.084 ;
    END
  END b_d[293]
  PIN b_d[294]
    DIRECTION OUTPUT ;
    USE SIGNAL ;
    PORT
      LAYER M5 ;
        RECT  29.616 0 29.64 0.084 ;
    END
  END b_d[294]
  PIN b_d[295]
    DIRECTION OUTPUT ;
    USE SIGNAL ;
    PORT
      LAYER M5 ;
        RECT  29.712 0 29.736 0.084 ;
    END
  END b_d[295]
  PIN b_d[296]
    DIRECTION OUTPUT ;
    USE SIGNAL ;
    PORT
      LAYER M5 ;
        RECT  29.808 0 29.832 0.084 ;
    END
  END b_d[296]
  PIN b_d[297]
    DIRECTION OUTPUT ;
    USE SIGNAL ;
    PORT
      LAYER M5 ;
        RECT  29.904 0 29.928 0.084 ;
    END
  END b_d[297]
  PIN b_d[298]
    DIRECTION OUTPUT ;
    USE SIGNAL ;
    PORT
      LAYER M5 ;
        RECT  30 0 30.024 0.084 ;
    END
  END b_d[298]
  PIN b_d[299]
    DIRECTION OUTPUT ;
    USE SIGNAL ;
    PORT
      LAYER M5 ;
        RECT  30.096 0 30.12 0.084 ;
    END
  END b_d[299]
  PIN b_d[29]
    DIRECTION OUTPUT ;
    USE SIGNAL ;
    PORT
      LAYER M5 ;
        RECT  3.6 0 3.624 0.084 ;
    END
  END b_d[29]
  PIN b_d[2]
    DIRECTION OUTPUT ;
    USE SIGNAL ;
    PORT
      LAYER M5 ;
        RECT  0.96 0 0.984 0.084 ;
    END
  END b_d[2]
  PIN b_d[300]
    DIRECTION OUTPUT ;
    USE SIGNAL ;
    PORT
      LAYER M5 ;
        RECT  30.192 0 30.216 0.084 ;
    END
  END b_d[300]
  PIN b_d[301]
    DIRECTION OUTPUT ;
    USE SIGNAL ;
    PORT
      LAYER M5 ;
        RECT  30.288 0 30.312 0.084 ;
    END
  END b_d[301]
  PIN b_d[302]
    DIRECTION OUTPUT ;
    USE SIGNAL ;
    PORT
      LAYER M5 ;
        RECT  30.384 0 30.408 0.084 ;
    END
  END b_d[302]
  PIN b_d[303]
    DIRECTION OUTPUT ;
    USE SIGNAL ;
    PORT
      LAYER M5 ;
        RECT  30.48 0 30.504 0.084 ;
    END
  END b_d[303]
  PIN b_d[304]
    DIRECTION OUTPUT ;
    USE SIGNAL ;
    PORT
      LAYER M5 ;
        RECT  30.576 0 30.6 0.084 ;
    END
  END b_d[304]
  PIN b_d[305]
    DIRECTION OUTPUT ;
    USE SIGNAL ;
    PORT
      LAYER M5 ;
        RECT  30.672 0 30.696 0.084 ;
    END
  END b_d[305]
  PIN b_d[306]
    DIRECTION OUTPUT ;
    USE SIGNAL ;
    PORT
      LAYER M5 ;
        RECT  30.768 0 30.792 0.084 ;
    END
  END b_d[306]
  PIN b_d[307]
    DIRECTION OUTPUT ;
    USE SIGNAL ;
    PORT
      LAYER M5 ;
        RECT  30.864 0 30.888 0.084 ;
    END
  END b_d[307]
  PIN b_d[308]
    DIRECTION OUTPUT ;
    USE SIGNAL ;
    PORT
      LAYER M5 ;
        RECT  30.96 0 30.984 0.084 ;
    END
  END b_d[308]
  PIN b_d[309]
    DIRECTION OUTPUT ;
    USE SIGNAL ;
    PORT
      LAYER M5 ;
        RECT  31.056 0 31.08 0.084 ;
    END
  END b_d[309]
  PIN b_d[30]
    DIRECTION OUTPUT ;
    USE SIGNAL ;
    PORT
      LAYER M5 ;
        RECT  3.696 0 3.72 0.084 ;
    END
  END b_d[30]
  PIN b_d[310]
    DIRECTION OUTPUT ;
    USE SIGNAL ;
    PORT
      LAYER M5 ;
        RECT  31.152 0 31.176 0.084 ;
    END
  END b_d[310]
  PIN b_d[311]
    DIRECTION OUTPUT ;
    USE SIGNAL ;
    PORT
      LAYER M5 ;
        RECT  31.248 0 31.272 0.084 ;
    END
  END b_d[311]
  PIN b_d[312]
    DIRECTION OUTPUT ;
    USE SIGNAL ;
    PORT
      LAYER M5 ;
        RECT  31.344 0 31.368 0.084 ;
    END
  END b_d[312]
  PIN b_d[313]
    DIRECTION OUTPUT ;
    USE SIGNAL ;
    PORT
      LAYER M5 ;
        RECT  31.44 0 31.464 0.084 ;
    END
  END b_d[313]
  PIN b_d[314]
    DIRECTION OUTPUT ;
    USE SIGNAL ;
    PORT
      LAYER M5 ;
        RECT  31.536 0 31.56 0.084 ;
    END
  END b_d[314]
  PIN b_d[315]
    DIRECTION OUTPUT ;
    USE SIGNAL ;
    PORT
      LAYER M5 ;
        RECT  31.632 0 31.656 0.084 ;
    END
  END b_d[315]
  PIN b_d[316]
    DIRECTION OUTPUT ;
    USE SIGNAL ;
    PORT
      LAYER M5 ;
        RECT  31.776 0 31.8 0.084 ;
    END
  END b_d[316]
  PIN b_d[317]
    DIRECTION OUTPUT ;
    USE SIGNAL ;
    PORT
      LAYER M5 ;
        RECT  31.872 0 31.896 0.084 ;
    END
  END b_d[317]
  PIN b_d[318]
    DIRECTION OUTPUT ;
    USE SIGNAL ;
    PORT
      LAYER M5 ;
        RECT  31.968 0 31.992 0.084 ;
    END
  END b_d[318]
  PIN b_d[319]
    DIRECTION OUTPUT ;
    USE SIGNAL ;
    PORT
      LAYER M5 ;
        RECT  32.064 0 32.088 0.084 ;
    END
  END b_d[319]
  PIN b_d[31]
    DIRECTION OUTPUT ;
    USE SIGNAL ;
    PORT
      LAYER M5 ;
        RECT  3.792 0 3.816 0.084 ;
    END
  END b_d[31]
  PIN b_d[320]
    DIRECTION OUTPUT ;
    USE SIGNAL ;
    PORT
      LAYER M5 ;
        RECT  32.16 0 32.184 0.084 ;
    END
  END b_d[320]
  PIN b_d[321]
    DIRECTION OUTPUT ;
    USE SIGNAL ;
    PORT
      LAYER M5 ;
        RECT  32.256 0 32.28 0.084 ;
    END
  END b_d[321]
  PIN b_d[322]
    DIRECTION OUTPUT ;
    USE SIGNAL ;
    PORT
      LAYER M5 ;
        RECT  32.352 0 32.376 0.084 ;
    END
  END b_d[322]
  PIN b_d[323]
    DIRECTION OUTPUT ;
    USE SIGNAL ;
    PORT
      LAYER M5 ;
        RECT  32.448 0 32.472 0.084 ;
    END
  END b_d[323]
  PIN b_d[324]
    DIRECTION OUTPUT ;
    USE SIGNAL ;
    PORT
      LAYER M5 ;
        RECT  32.544 0 32.568 0.084 ;
    END
  END b_d[324]
  PIN b_d[325]
    DIRECTION OUTPUT ;
    USE SIGNAL ;
    PORT
      LAYER M5 ;
        RECT  32.64 0 32.664 0.084 ;
    END
  END b_d[325]
  PIN b_d[326]
    DIRECTION OUTPUT ;
    USE SIGNAL ;
    PORT
      LAYER M5 ;
        RECT  32.736 0 32.76 0.084 ;
    END
  END b_d[326]
  PIN b_d[327]
    DIRECTION OUTPUT ;
    USE SIGNAL ;
    PORT
      LAYER M5 ;
        RECT  32.832 0 32.856 0.084 ;
    END
  END b_d[327]
  PIN b_d[328]
    DIRECTION OUTPUT ;
    USE SIGNAL ;
    PORT
      LAYER M5 ;
        RECT  32.928 0 32.952 0.084 ;
    END
  END b_d[328]
  PIN b_d[329]
    DIRECTION OUTPUT ;
    USE SIGNAL ;
    PORT
      LAYER M5 ;
        RECT  33.024 0 33.048 0.084 ;
    END
  END b_d[329]
  PIN b_d[32]
    DIRECTION OUTPUT ;
    USE SIGNAL ;
    PORT
      LAYER M5 ;
        RECT  3.888 0 3.912 0.084 ;
    END
  END b_d[32]
  PIN b_d[330]
    DIRECTION OUTPUT ;
    USE SIGNAL ;
    PORT
      LAYER M5 ;
        RECT  33.12 0 33.144 0.084 ;
    END
  END b_d[330]
  PIN b_d[331]
    DIRECTION OUTPUT ;
    USE SIGNAL ;
    PORT
      LAYER M5 ;
        RECT  33.216 0 33.24 0.084 ;
    END
  END b_d[331]
  PIN b_d[332]
    DIRECTION OUTPUT ;
    USE SIGNAL ;
    PORT
      LAYER M5 ;
        RECT  33.312 0 33.336 0.084 ;
    END
  END b_d[332]
  PIN b_d[333]
    DIRECTION OUTPUT ;
    USE SIGNAL ;
    PORT
      LAYER M5 ;
        RECT  33.408 0 33.432 0.084 ;
    END
  END b_d[333]
  PIN b_d[334]
    DIRECTION OUTPUT ;
    USE SIGNAL ;
    PORT
      LAYER M5 ;
        RECT  33.504 0 33.528 0.084 ;
    END
  END b_d[334]
  PIN b_d[335]
    DIRECTION OUTPUT ;
    USE SIGNAL ;
    PORT
      LAYER M5 ;
        RECT  33.6 0 33.624 0.084 ;
    END
  END b_d[335]
  PIN b_d[336]
    DIRECTION OUTPUT ;
    USE SIGNAL ;
    PORT
      LAYER M5 ;
        RECT  33.696 0 33.72 0.084 ;
    END
  END b_d[336]
  PIN b_d[337]
    DIRECTION OUTPUT ;
    USE SIGNAL ;
    PORT
      LAYER M5 ;
        RECT  33.792 0 33.816 0.084 ;
    END
  END b_d[337]
  PIN b_d[338]
    DIRECTION OUTPUT ;
    USE SIGNAL ;
    PORT
      LAYER M5 ;
        RECT  33.888 0 33.912 0.084 ;
    END
  END b_d[338]
  PIN b_d[339]
    DIRECTION OUTPUT ;
    USE SIGNAL ;
    PORT
      LAYER M5 ;
        RECT  33.984 0 34.008 0.084 ;
    END
  END b_d[339]
  PIN b_d[33]
    DIRECTION OUTPUT ;
    USE SIGNAL ;
    PORT
      LAYER M5 ;
        RECT  3.984 0 4.008 0.084 ;
    END
  END b_d[33]
  PIN b_d[340]
    DIRECTION OUTPUT ;
    USE SIGNAL ;
    PORT
      LAYER M5 ;
        RECT  34.128 0 34.152 0.084 ;
    END
  END b_d[340]
  PIN b_d[341]
    DIRECTION OUTPUT ;
    USE SIGNAL ;
    PORT
      LAYER M5 ;
        RECT  34.224 0 34.248 0.084 ;
    END
  END b_d[341]
  PIN b_d[342]
    DIRECTION OUTPUT ;
    USE SIGNAL ;
    PORT
      LAYER M5 ;
        RECT  34.32 0 34.344 0.084 ;
    END
  END b_d[342]
  PIN b_d[343]
    DIRECTION OUTPUT ;
    USE SIGNAL ;
    PORT
      LAYER M5 ;
        RECT  34.416 0 34.44 0.084 ;
    END
  END b_d[343]
  PIN b_d[344]
    DIRECTION OUTPUT ;
    USE SIGNAL ;
    PORT
      LAYER M5 ;
        RECT  34.512 0 34.536 0.084 ;
    END
  END b_d[344]
  PIN b_d[345]
    DIRECTION OUTPUT ;
    USE SIGNAL ;
    PORT
      LAYER M5 ;
        RECT  34.608 0 34.632 0.084 ;
    END
  END b_d[345]
  PIN b_d[346]
    DIRECTION OUTPUT ;
    USE SIGNAL ;
    PORT
      LAYER M5 ;
        RECT  34.704 0 34.728 0.084 ;
    END
  END b_d[346]
  PIN b_d[347]
    DIRECTION OUTPUT ;
    USE SIGNAL ;
    PORT
      LAYER M5 ;
        RECT  34.8 0 34.824 0.084 ;
    END
  END b_d[347]
  PIN b_d[348]
    DIRECTION OUTPUT ;
    USE SIGNAL ;
    PORT
      LAYER M5 ;
        RECT  34.896 0 34.92 0.084 ;
    END
  END b_d[348]
  PIN b_d[349]
    DIRECTION OUTPUT ;
    USE SIGNAL ;
    PORT
      LAYER M5 ;
        RECT  34.992 0 35.016 0.084 ;
    END
  END b_d[349]
  PIN b_d[34]
    DIRECTION OUTPUT ;
    USE SIGNAL ;
    PORT
      LAYER M5 ;
        RECT  4.08 0 4.104 0.084 ;
    END
  END b_d[34]
  PIN b_d[350]
    DIRECTION OUTPUT ;
    USE SIGNAL ;
    PORT
      LAYER M5 ;
        RECT  35.088 0 35.112 0.084 ;
    END
  END b_d[350]
  PIN b_d[351]
    DIRECTION OUTPUT ;
    USE SIGNAL ;
    PORT
      LAYER M5 ;
        RECT  35.184 0 35.208 0.084 ;
    END
  END b_d[351]
  PIN b_d[352]
    DIRECTION OUTPUT ;
    USE SIGNAL ;
    PORT
      LAYER M5 ;
        RECT  35.28 0 35.304 0.084 ;
    END
  END b_d[352]
  PIN b_d[353]
    DIRECTION OUTPUT ;
    USE SIGNAL ;
    PORT
      LAYER M5 ;
        RECT  35.376 0 35.4 0.084 ;
    END
  END b_d[353]
  PIN b_d[354]
    DIRECTION OUTPUT ;
    USE SIGNAL ;
    PORT
      LAYER M5 ;
        RECT  35.472 0 35.496 0.084 ;
    END
  END b_d[354]
  PIN b_d[355]
    DIRECTION OUTPUT ;
    USE SIGNAL ;
    PORT
      LAYER M5 ;
        RECT  35.568 0 35.592 0.084 ;
    END
  END b_d[355]
  PIN b_d[356]
    DIRECTION OUTPUT ;
    USE SIGNAL ;
    PORT
      LAYER M5 ;
        RECT  35.664 0 35.688 0.084 ;
    END
  END b_d[356]
  PIN b_d[357]
    DIRECTION OUTPUT ;
    USE SIGNAL ;
    PORT
      LAYER M5 ;
        RECT  35.76 0 35.784 0.084 ;
    END
  END b_d[357]
  PIN b_d[358]
    DIRECTION OUTPUT ;
    USE SIGNAL ;
    PORT
      LAYER M5 ;
        RECT  35.856 0 35.88 0.084 ;
    END
  END b_d[358]
  PIN b_d[359]
    DIRECTION OUTPUT ;
    USE SIGNAL ;
    PORT
      LAYER M5 ;
        RECT  35.952 0 35.976 0.084 ;
    END
  END b_d[359]
  PIN b_d[35]
    DIRECTION OUTPUT ;
    USE SIGNAL ;
    PORT
      LAYER M5 ;
        RECT  4.224 0 4.248 0.084 ;
    END
  END b_d[35]
  PIN b_d[360]
    DIRECTION OUTPUT ;
    USE SIGNAL ;
    PORT
      LAYER M5 ;
        RECT  36.048 0 36.072 0.084 ;
    END
  END b_d[360]
  PIN b_d[361]
    DIRECTION OUTPUT ;
    USE SIGNAL ;
    PORT
      LAYER M5 ;
        RECT  36.144 0 36.168 0.084 ;
    END
  END b_d[361]
  PIN b_d[362]
    DIRECTION OUTPUT ;
    USE SIGNAL ;
    PORT
      LAYER M5 ;
        RECT  36.24 0 36.264 0.084 ;
    END
  END b_d[362]
  PIN b_d[363]
    DIRECTION OUTPUT ;
    USE SIGNAL ;
    PORT
      LAYER M5 ;
        RECT  36.384 0 36.408 0.084 ;
    END
  END b_d[363]
  PIN b_d[364]
    DIRECTION OUTPUT ;
    USE SIGNAL ;
    PORT
      LAYER M5 ;
        RECT  36.48 0 36.504 0.084 ;
    END
  END b_d[364]
  PIN b_d[365]
    DIRECTION OUTPUT ;
    USE SIGNAL ;
    PORT
      LAYER M5 ;
        RECT  36.576 0 36.6 0.084 ;
    END
  END b_d[365]
  PIN b_d[366]
    DIRECTION OUTPUT ;
    USE SIGNAL ;
    PORT
      LAYER M5 ;
        RECT  36.672 0 36.696 0.084 ;
    END
  END b_d[366]
  PIN b_d[367]
    DIRECTION OUTPUT ;
    USE SIGNAL ;
    PORT
      LAYER M5 ;
        RECT  36.768 0 36.792 0.084 ;
    END
  END b_d[367]
  PIN b_d[368]
    DIRECTION OUTPUT ;
    USE SIGNAL ;
    PORT
      LAYER M5 ;
        RECT  36.864 0 36.888 0.084 ;
    END
  END b_d[368]
  PIN b_d[369]
    DIRECTION OUTPUT ;
    USE SIGNAL ;
    PORT
      LAYER M5 ;
        RECT  36.96 0 36.984 0.084 ;
    END
  END b_d[369]
  PIN b_d[36]
    DIRECTION OUTPUT ;
    USE SIGNAL ;
    PORT
      LAYER M5 ;
        RECT  4.32 0 4.344 0.084 ;
    END
  END b_d[36]
  PIN b_d[370]
    DIRECTION OUTPUT ;
    USE SIGNAL ;
    PORT
      LAYER M5 ;
        RECT  37.056 0 37.08 0.084 ;
    END
  END b_d[370]
  PIN b_d[371]
    DIRECTION OUTPUT ;
    USE SIGNAL ;
    PORT
      LAYER M5 ;
        RECT  37.152 0 37.176 0.084 ;
    END
  END b_d[371]
  PIN b_d[372]
    DIRECTION OUTPUT ;
    USE SIGNAL ;
    PORT
      LAYER M5 ;
        RECT  37.248 0 37.272 0.084 ;
    END
  END b_d[372]
  PIN b_d[373]
    DIRECTION OUTPUT ;
    USE SIGNAL ;
    PORT
      LAYER M5 ;
        RECT  37.344 0 37.368 0.084 ;
    END
  END b_d[373]
  PIN b_d[374]
    DIRECTION OUTPUT ;
    USE SIGNAL ;
    PORT
      LAYER M5 ;
        RECT  37.44 0 37.464 0.084 ;
    END
  END b_d[374]
  PIN b_d[375]
    DIRECTION OUTPUT ;
    USE SIGNAL ;
    PORT
      LAYER M5 ;
        RECT  37.536 0 37.56 0.084 ;
    END
  END b_d[375]
  PIN b_d[376]
    DIRECTION OUTPUT ;
    USE SIGNAL ;
    PORT
      LAYER M5 ;
        RECT  37.632 0 37.656 0.084 ;
    END
  END b_d[376]
  PIN b_d[377]
    DIRECTION OUTPUT ;
    USE SIGNAL ;
    PORT
      LAYER M5 ;
        RECT  37.728 0 37.752 0.084 ;
    END
  END b_d[377]
  PIN b_d[378]
    DIRECTION OUTPUT ;
    USE SIGNAL ;
    PORT
      LAYER M5 ;
        RECT  37.824 0 37.848 0.084 ;
    END
  END b_d[378]
  PIN b_d[379]
    DIRECTION OUTPUT ;
    USE SIGNAL ;
    PORT
      LAYER M5 ;
        RECT  37.92 0 37.944 0.084 ;
    END
  END b_d[379]
  PIN b_d[37]
    DIRECTION OUTPUT ;
    USE SIGNAL ;
    PORT
      LAYER M5 ;
        RECT  4.416 0 4.44 0.084 ;
    END
  END b_d[37]
  PIN b_d[380]
    DIRECTION OUTPUT ;
    USE SIGNAL ;
    PORT
      LAYER M5 ;
        RECT  38.016 0 38.04 0.084 ;
    END
  END b_d[380]
  PIN b_d[381]
    DIRECTION OUTPUT ;
    USE SIGNAL ;
    PORT
      LAYER M5 ;
        RECT  38.112 0 38.136 0.084 ;
    END
  END b_d[381]
  PIN b_d[382]
    DIRECTION OUTPUT ;
    USE SIGNAL ;
    PORT
      LAYER M5 ;
        RECT  38.208 0 38.232 0.084 ;
    END
  END b_d[382]
  PIN b_d[383]
    DIRECTION OUTPUT ;
    USE SIGNAL ;
    PORT
      LAYER M5 ;
        RECT  38.304 0 38.328 0.084 ;
    END
  END b_d[383]
  PIN b_d[384]
    DIRECTION OUTPUT ;
    USE SIGNAL ;
    PORT
      LAYER M5 ;
        RECT  38.4 0 38.424 0.084 ;
    END
  END b_d[384]
  PIN b_d[385]
    DIRECTION OUTPUT ;
    USE SIGNAL ;
    PORT
      LAYER M5 ;
        RECT  38.496 0 38.52 0.084 ;
    END
  END b_d[385]
  PIN b_d[386]
    DIRECTION OUTPUT ;
    USE SIGNAL ;
    PORT
      LAYER M5 ;
        RECT  38.592 0 38.616 0.084 ;
    END
  END b_d[386]
  PIN b_d[387]
    DIRECTION OUTPUT ;
    USE SIGNAL ;
    PORT
      LAYER M5 ;
        RECT  38.736 0 38.76 0.084 ;
    END
  END b_d[387]
  PIN b_d[388]
    DIRECTION OUTPUT ;
    USE SIGNAL ;
    PORT
      LAYER M5 ;
        RECT  38.832 0 38.856 0.084 ;
    END
  END b_d[388]
  PIN b_d[389]
    DIRECTION OUTPUT ;
    USE SIGNAL ;
    PORT
      LAYER M5 ;
        RECT  38.928 0 38.952 0.084 ;
    END
  END b_d[389]
  PIN b_d[38]
    DIRECTION OUTPUT ;
    USE SIGNAL ;
    PORT
      LAYER M5 ;
        RECT  4.512 0 4.536 0.084 ;
    END
  END b_d[38]
  PIN b_d[390]
    DIRECTION OUTPUT ;
    USE SIGNAL ;
    PORT
      LAYER M5 ;
        RECT  39.024 0 39.048 0.084 ;
    END
  END b_d[390]
  PIN b_d[391]
    DIRECTION OUTPUT ;
    USE SIGNAL ;
    PORT
      LAYER M5 ;
        RECT  39.12 0 39.144 0.084 ;
    END
  END b_d[391]
  PIN b_d[392]
    DIRECTION OUTPUT ;
    USE SIGNAL ;
    PORT
      LAYER M5 ;
        RECT  39.216 0 39.24 0.084 ;
    END
  END b_d[392]
  PIN b_d[393]
    DIRECTION OUTPUT ;
    USE SIGNAL ;
    PORT
      LAYER M5 ;
        RECT  39.312 0 39.336 0.084 ;
    END
  END b_d[393]
  PIN b_d[394]
    DIRECTION OUTPUT ;
    USE SIGNAL ;
    PORT
      LAYER M5 ;
        RECT  39.408 0 39.432 0.084 ;
    END
  END b_d[394]
  PIN b_d[395]
    DIRECTION OUTPUT ;
    USE SIGNAL ;
    PORT
      LAYER M5 ;
        RECT  39.504 0 39.528 0.084 ;
    END
  END b_d[395]
  PIN b_d[396]
    DIRECTION OUTPUT ;
    USE SIGNAL ;
    PORT
      LAYER M5 ;
        RECT  39.6 0 39.624 0.084 ;
    END
  END b_d[396]
  PIN b_d[397]
    DIRECTION OUTPUT ;
    USE SIGNAL ;
    PORT
      LAYER M5 ;
        RECT  39.696 0 39.72 0.084 ;
    END
  END b_d[397]
  PIN b_d[398]
    DIRECTION OUTPUT ;
    USE SIGNAL ;
    PORT
      LAYER M5 ;
        RECT  39.792 0 39.816 0.084 ;
    END
  END b_d[398]
  PIN b_d[399]
    DIRECTION OUTPUT ;
    USE SIGNAL ;
    PORT
      LAYER M5 ;
        RECT  39.888 0 39.912 0.084 ;
    END
  END b_d[399]
  PIN b_d[39]
    DIRECTION OUTPUT ;
    USE SIGNAL ;
    PORT
      LAYER M5 ;
        RECT  4.608 0 4.632 0.084 ;
    END
  END b_d[39]
  PIN b_d[3]
    DIRECTION OUTPUT ;
    USE SIGNAL ;
    PORT
      LAYER M5 ;
        RECT  1.056 0 1.08 0.084 ;
    END
  END b_d[3]
  PIN b_d[400]
    DIRECTION OUTPUT ;
    USE SIGNAL ;
    PORT
      LAYER M5 ;
        RECT  39.984 0 40.008 0.084 ;
    END
  END b_d[400]
  PIN b_d[401]
    DIRECTION OUTPUT ;
    USE SIGNAL ;
    PORT
      LAYER M5 ;
        RECT  40.08 0 40.104 0.084 ;
    END
  END b_d[401]
  PIN b_d[402]
    DIRECTION OUTPUT ;
    USE SIGNAL ;
    PORT
      LAYER M5 ;
        RECT  40.176 0 40.2 0.084 ;
    END
  END b_d[402]
  PIN b_d[403]
    DIRECTION OUTPUT ;
    USE SIGNAL ;
    PORT
      LAYER M5 ;
        RECT  40.272 0 40.296 0.084 ;
    END
  END b_d[403]
  PIN b_d[404]
    DIRECTION OUTPUT ;
    USE SIGNAL ;
    PORT
      LAYER M5 ;
        RECT  40.368 0 40.392 0.084 ;
    END
  END b_d[404]
  PIN b_d[405]
    DIRECTION OUTPUT ;
    USE SIGNAL ;
    PORT
      LAYER M5 ;
        RECT  40.464 0 40.488 0.084 ;
    END
  END b_d[405]
  PIN b_d[406]
    DIRECTION OUTPUT ;
    USE SIGNAL ;
    PORT
      LAYER M5 ;
        RECT  40.56 0 40.584 0.084 ;
    END
  END b_d[406]
  PIN b_d[407]
    DIRECTION OUTPUT ;
    USE SIGNAL ;
    PORT
      LAYER M5 ;
        RECT  40.656 0 40.68 0.084 ;
    END
  END b_d[407]
  PIN b_d[408]
    DIRECTION OUTPUT ;
    USE SIGNAL ;
    PORT
      LAYER M5 ;
        RECT  40.752 0 40.776 0.084 ;
    END
  END b_d[408]
  PIN b_d[409]
    DIRECTION OUTPUT ;
    USE SIGNAL ;
    PORT
      LAYER M5 ;
        RECT  40.848 0 40.872 0.084 ;
    END
  END b_d[409]
  PIN b_d[40]
    DIRECTION OUTPUT ;
    USE SIGNAL ;
    PORT
      LAYER M5 ;
        RECT  4.704 0 4.728 0.084 ;
    END
  END b_d[40]
  PIN b_d[410]
    DIRECTION OUTPUT ;
    USE SIGNAL ;
    PORT
      LAYER M5 ;
        RECT  40.992 0 41.016 0.084 ;
    END
  END b_d[410]
  PIN b_d[411]
    DIRECTION OUTPUT ;
    USE SIGNAL ;
    PORT
      LAYER M5 ;
        RECT  41.088 0 41.112 0.084 ;
    END
  END b_d[411]
  PIN b_d[412]
    DIRECTION OUTPUT ;
    USE SIGNAL ;
    PORT
      LAYER M5 ;
        RECT  41.184 0 41.208 0.084 ;
    END
  END b_d[412]
  PIN b_d[413]
    DIRECTION OUTPUT ;
    USE SIGNAL ;
    PORT
      LAYER M5 ;
        RECT  41.28 0 41.304 0.084 ;
    END
  END b_d[413]
  PIN b_d[414]
    DIRECTION OUTPUT ;
    USE SIGNAL ;
    PORT
      LAYER M5 ;
        RECT  41.376 0 41.4 0.084 ;
    END
  END b_d[414]
  PIN b_d[415]
    DIRECTION OUTPUT ;
    USE SIGNAL ;
    PORT
      LAYER M5 ;
        RECT  41.472 0 41.496 0.084 ;
    END
  END b_d[415]
  PIN b_d[416]
    DIRECTION OUTPUT ;
    USE SIGNAL ;
    PORT
      LAYER M5 ;
        RECT  41.568 0 41.592 0.084 ;
    END
  END b_d[416]
  PIN b_d[417]
    DIRECTION OUTPUT ;
    USE SIGNAL ;
    PORT
      LAYER M5 ;
        RECT  41.664 0 41.688 0.084 ;
    END
  END b_d[417]
  PIN b_d[418]
    DIRECTION OUTPUT ;
    USE SIGNAL ;
    PORT
      LAYER M5 ;
        RECT  41.76 0 41.784 0.084 ;
    END
  END b_d[418]
  PIN b_d[419]
    DIRECTION OUTPUT ;
    USE SIGNAL ;
    PORT
      LAYER M5 ;
        RECT  41.856 0 41.88 0.084 ;
    END
  END b_d[419]
  PIN b_d[41]
    DIRECTION OUTPUT ;
    USE SIGNAL ;
    PORT
      LAYER M5 ;
        RECT  4.8 0 4.824 0.084 ;
    END
  END b_d[41]
  PIN b_d[420]
    DIRECTION OUTPUT ;
    USE SIGNAL ;
    PORT
      LAYER M5 ;
        RECT  41.952 0 41.976 0.084 ;
    END
  END b_d[420]
  PIN b_d[421]
    DIRECTION OUTPUT ;
    USE SIGNAL ;
    PORT
      LAYER M5 ;
        RECT  42.048 0 42.072 0.084 ;
    END
  END b_d[421]
  PIN b_d[422]
    DIRECTION OUTPUT ;
    USE SIGNAL ;
    PORT
      LAYER M5 ;
        RECT  42.144 0 42.168 0.084 ;
    END
  END b_d[422]
  PIN b_d[423]
    DIRECTION OUTPUT ;
    USE SIGNAL ;
    PORT
      LAYER M5 ;
        RECT  42.24 0 42.264 0.084 ;
    END
  END b_d[423]
  PIN b_d[424]
    DIRECTION OUTPUT ;
    USE SIGNAL ;
    PORT
      LAYER M5 ;
        RECT  42.336 0 42.36 0.084 ;
    END
  END b_d[424]
  PIN b_d[425]
    DIRECTION OUTPUT ;
    USE SIGNAL ;
    PORT
      LAYER M5 ;
        RECT  42.432 0 42.456 0.084 ;
    END
  END b_d[425]
  PIN b_d[426]
    DIRECTION OUTPUT ;
    USE SIGNAL ;
    PORT
      LAYER M5 ;
        RECT  42.528 0 42.552 0.084 ;
    END
  END b_d[426]
  PIN b_d[427]
    DIRECTION OUTPUT ;
    USE SIGNAL ;
    PORT
      LAYER M5 ;
        RECT  42.624 0 42.648 0.084 ;
    END
  END b_d[427]
  PIN b_d[428]
    DIRECTION OUTPUT ;
    USE SIGNAL ;
    PORT
      LAYER M5 ;
        RECT  42.72 0 42.744 0.084 ;
    END
  END b_d[428]
  PIN b_d[429]
    DIRECTION OUTPUT ;
    USE SIGNAL ;
    PORT
      LAYER M5 ;
        RECT  42.816 0 42.84 0.084 ;
    END
  END b_d[429]
  PIN b_d[42]
    DIRECTION OUTPUT ;
    USE SIGNAL ;
    PORT
      LAYER M5 ;
        RECT  4.896 0 4.92 0.084 ;
    END
  END b_d[42]
  PIN b_d[430]
    DIRECTION OUTPUT ;
    USE SIGNAL ;
    PORT
      LAYER M5 ;
        RECT  42.912 0 42.936 0.084 ;
    END
  END b_d[430]
  PIN b_d[431]
    DIRECTION OUTPUT ;
    USE SIGNAL ;
    PORT
      LAYER M5 ;
        RECT  43.008 0 43.032 0.084 ;
    END
  END b_d[431]
  PIN b_d[432]
    DIRECTION OUTPUT ;
    USE SIGNAL ;
    PORT
      LAYER M5 ;
        RECT  43.104 0 43.128 0.084 ;
    END
  END b_d[432]
  PIN b_d[433]
    DIRECTION OUTPUT ;
    USE SIGNAL ;
    PORT
      LAYER M5 ;
        RECT  43.2 0 43.224 0.084 ;
    END
  END b_d[433]
  PIN b_d[434]
    DIRECTION OUTPUT ;
    USE SIGNAL ;
    PORT
      LAYER M5 ;
        RECT  43.344 0 43.368 0.084 ;
    END
  END b_d[434]
  PIN b_d[435]
    DIRECTION OUTPUT ;
    USE SIGNAL ;
    PORT
      LAYER M5 ;
        RECT  43.44 0 43.464 0.084 ;
    END
  END b_d[435]
  PIN b_d[436]
    DIRECTION OUTPUT ;
    USE SIGNAL ;
    PORT
      LAYER M5 ;
        RECT  43.536 0 43.56 0.084 ;
    END
  END b_d[436]
  PIN b_d[437]
    DIRECTION OUTPUT ;
    USE SIGNAL ;
    PORT
      LAYER M5 ;
        RECT  43.632 0 43.656 0.084 ;
    END
  END b_d[437]
  PIN b_d[438]
    DIRECTION OUTPUT ;
    USE SIGNAL ;
    PORT
      LAYER M5 ;
        RECT  43.728 0 43.752 0.084 ;
    END
  END b_d[438]
  PIN b_d[439]
    DIRECTION OUTPUT ;
    USE SIGNAL ;
    PORT
      LAYER M5 ;
        RECT  43.824 0 43.848 0.084 ;
    END
  END b_d[439]
  PIN b_d[43]
    DIRECTION OUTPUT ;
    USE SIGNAL ;
    PORT
      LAYER M5 ;
        RECT  4.992 0 5.016 0.084 ;
    END
  END b_d[43]
  PIN b_d[440]
    DIRECTION OUTPUT ;
    USE SIGNAL ;
    PORT
      LAYER M5 ;
        RECT  43.92 0 43.944 0.084 ;
    END
  END b_d[440]
  PIN b_d[441]
    DIRECTION OUTPUT ;
    USE SIGNAL ;
    PORT
      LAYER M5 ;
        RECT  44.016 0 44.04 0.084 ;
    END
  END b_d[441]
  PIN b_d[442]
    DIRECTION OUTPUT ;
    USE SIGNAL ;
    PORT
      LAYER M5 ;
        RECT  44.112 0 44.136 0.084 ;
    END
  END b_d[442]
  PIN b_d[443]
    DIRECTION OUTPUT ;
    USE SIGNAL ;
    PORT
      LAYER M5 ;
        RECT  44.208 0 44.232 0.084 ;
    END
  END b_d[443]
  PIN b_d[444]
    DIRECTION OUTPUT ;
    USE SIGNAL ;
    PORT
      LAYER M5 ;
        RECT  44.304 0 44.328 0.084 ;
    END
  END b_d[444]
  PIN b_d[445]
    DIRECTION OUTPUT ;
    USE SIGNAL ;
    PORT
      LAYER M5 ;
        RECT  44.4 0 44.424 0.084 ;
    END
  END b_d[445]
  PIN b_d[446]
    DIRECTION OUTPUT ;
    USE SIGNAL ;
    PORT
      LAYER M5 ;
        RECT  44.496 0 44.52 0.084 ;
    END
  END b_d[446]
  PIN b_d[447]
    DIRECTION OUTPUT ;
    USE SIGNAL ;
    PORT
      LAYER M5 ;
        RECT  44.592 0 44.616 0.084 ;
    END
  END b_d[447]
  PIN b_d[448]
    DIRECTION OUTPUT ;
    USE SIGNAL ;
    PORT
      LAYER M5 ;
        RECT  44.688 0 44.712 0.084 ;
    END
  END b_d[448]
  PIN b_d[449]
    DIRECTION OUTPUT ;
    USE SIGNAL ;
    PORT
      LAYER M5 ;
        RECT  44.784 0 44.808 0.084 ;
    END
  END b_d[449]
  PIN b_d[44]
    DIRECTION OUTPUT ;
    USE SIGNAL ;
    PORT
      LAYER M5 ;
        RECT  5.088 0 5.112 0.084 ;
    END
  END b_d[44]
  PIN b_d[450]
    DIRECTION OUTPUT ;
    USE SIGNAL ;
    PORT
      LAYER M5 ;
        RECT  44.88 0 44.904 0.084 ;
    END
  END b_d[450]
  PIN b_d[451]
    DIRECTION OUTPUT ;
    USE SIGNAL ;
    PORT
      LAYER M5 ;
        RECT  44.976 0 45 0.084 ;
    END
  END b_d[451]
  PIN b_d[452]
    DIRECTION OUTPUT ;
    USE SIGNAL ;
    PORT
      LAYER M5 ;
        RECT  45.072 0 45.096 0.084 ;
    END
  END b_d[452]
  PIN b_d[453]
    DIRECTION OUTPUT ;
    USE SIGNAL ;
    PORT
      LAYER M5 ;
        RECT  45.168 0 45.192 0.084 ;
    END
  END b_d[453]
  PIN b_d[454]
    DIRECTION OUTPUT ;
    USE SIGNAL ;
    PORT
      LAYER M5 ;
        RECT  45.264 0 45.288 0.084 ;
    END
  END b_d[454]
  PIN b_d[455]
    DIRECTION OUTPUT ;
    USE SIGNAL ;
    PORT
      LAYER M5 ;
        RECT  45.36 0 45.384 0.084 ;
    END
  END b_d[455]
  PIN b_d[456]
    DIRECTION OUTPUT ;
    USE SIGNAL ;
    PORT
      LAYER M5 ;
        RECT  45.456 0 45.48 0.084 ;
    END
  END b_d[456]
  PIN b_d[457]
    DIRECTION OUTPUT ;
    USE SIGNAL ;
    PORT
      LAYER M5 ;
        RECT  45.6 0 45.624 0.084 ;
    END
  END b_d[457]
  PIN b_d[458]
    DIRECTION OUTPUT ;
    USE SIGNAL ;
    PORT
      LAYER M5 ;
        RECT  45.696 0 45.72 0.084 ;
    END
  END b_d[458]
  PIN b_d[459]
    DIRECTION OUTPUT ;
    USE SIGNAL ;
    PORT
      LAYER M5 ;
        RECT  45.792 0 45.816 0.084 ;
    END
  END b_d[459]
  PIN b_d[45]
    DIRECTION OUTPUT ;
    USE SIGNAL ;
    PORT
      LAYER M5 ;
        RECT  5.184 0 5.208 0.084 ;
    END
  END b_d[45]
  PIN b_d[460]
    DIRECTION OUTPUT ;
    USE SIGNAL ;
    PORT
      LAYER M5 ;
        RECT  45.888 0 45.912 0.084 ;
    END
  END b_d[460]
  PIN b_d[461]
    DIRECTION OUTPUT ;
    USE SIGNAL ;
    PORT
      LAYER M5 ;
        RECT  45.984 0 46.008 0.084 ;
    END
  END b_d[461]
  PIN b_d[462]
    DIRECTION OUTPUT ;
    USE SIGNAL ;
    PORT
      LAYER M5 ;
        RECT  46.08 0 46.104 0.084 ;
    END
  END b_d[462]
  PIN b_d[463]
    DIRECTION OUTPUT ;
    USE SIGNAL ;
    PORT
      LAYER M5 ;
        RECT  46.176 0 46.2 0.084 ;
    END
  END b_d[463]
  PIN b_d[464]
    DIRECTION OUTPUT ;
    USE SIGNAL ;
    PORT
      LAYER M5 ;
        RECT  46.272 0 46.296 0.084 ;
    END
  END b_d[464]
  PIN b_d[465]
    DIRECTION OUTPUT ;
    USE SIGNAL ;
    PORT
      LAYER M5 ;
        RECT  46.368 0 46.392 0.084 ;
    END
  END b_d[465]
  PIN b_d[466]
    DIRECTION OUTPUT ;
    USE SIGNAL ;
    PORT
      LAYER M5 ;
        RECT  46.464 0 46.488 0.084 ;
    END
  END b_d[466]
  PIN b_d[467]
    DIRECTION OUTPUT ;
    USE SIGNAL ;
    PORT
      LAYER M5 ;
        RECT  46.56 0 46.584 0.084 ;
    END
  END b_d[467]
  PIN b_d[468]
    DIRECTION OUTPUT ;
    USE SIGNAL ;
    PORT
      LAYER M5 ;
        RECT  46.656 0 46.68 0.084 ;
    END
  END b_d[468]
  PIN b_d[469]
    DIRECTION OUTPUT ;
    USE SIGNAL ;
    PORT
      LAYER M5 ;
        RECT  46.752 0 46.776 0.084 ;
    END
  END b_d[469]
  PIN b_d[46]
    DIRECTION OUTPUT ;
    USE SIGNAL ;
    PORT
      LAYER M5 ;
        RECT  5.28 0 5.304 0.084 ;
    END
  END b_d[46]
  PIN b_d[470]
    DIRECTION OUTPUT ;
    USE SIGNAL ;
    PORT
      LAYER M5 ;
        RECT  46.848 0 46.872 0.084 ;
    END
  END b_d[470]
  PIN b_d[471]
    DIRECTION OUTPUT ;
    USE SIGNAL ;
    PORT
      LAYER M5 ;
        RECT  46.944 0 46.968 0.084 ;
    END
  END b_d[471]
  PIN b_d[472]
    DIRECTION OUTPUT ;
    USE SIGNAL ;
    PORT
      LAYER M5 ;
        RECT  47.04 0 47.064 0.084 ;
    END
  END b_d[472]
  PIN b_d[473]
    DIRECTION OUTPUT ;
    USE SIGNAL ;
    PORT
      LAYER M5 ;
        RECT  47.136 0 47.16 0.084 ;
    END
  END b_d[473]
  PIN b_d[474]
    DIRECTION OUTPUT ;
    USE SIGNAL ;
    PORT
      LAYER M5 ;
        RECT  47.232 0 47.256 0.084 ;
    END
  END b_d[474]
  PIN b_d[475]
    DIRECTION OUTPUT ;
    USE SIGNAL ;
    PORT
      LAYER M5 ;
        RECT  47.328 0 47.352 0.084 ;
    END
  END b_d[475]
  PIN b_d[476]
    DIRECTION OUTPUT ;
    USE SIGNAL ;
    PORT
      LAYER M5 ;
        RECT  47.424 0 47.448 0.084 ;
    END
  END b_d[476]
  PIN b_d[477]
    DIRECTION OUTPUT ;
    USE SIGNAL ;
    PORT
      LAYER M5 ;
        RECT  47.52 0 47.544 0.084 ;
    END
  END b_d[477]
  PIN b_d[478]
    DIRECTION OUTPUT ;
    USE SIGNAL ;
    PORT
      LAYER M5 ;
        RECT  47.616 0 47.64 0.084 ;
    END
  END b_d[478]
  PIN b_d[479]
    DIRECTION OUTPUT ;
    USE SIGNAL ;
    PORT
      LAYER M5 ;
        RECT  47.712 0 47.736 0.084 ;
    END
  END b_d[479]
  PIN b_d[47]
    DIRECTION OUTPUT ;
    USE SIGNAL ;
    PORT
      LAYER M5 ;
        RECT  5.376 0 5.4 0.084 ;
    END
  END b_d[47]
  PIN b_d[480]
    DIRECTION OUTPUT ;
    USE SIGNAL ;
    PORT
      LAYER M5 ;
        RECT  47.808 0 47.832 0.084 ;
    END
  END b_d[480]
  PIN b_d[481]
    DIRECTION OUTPUT ;
    USE SIGNAL ;
    PORT
      LAYER M5 ;
        RECT  47.952 0 47.976 0.084 ;
    END
  END b_d[481]
  PIN b_d[482]
    DIRECTION OUTPUT ;
    USE SIGNAL ;
    PORT
      LAYER M5 ;
        RECT  48.048 0 48.072 0.084 ;
    END
  END b_d[482]
  PIN b_d[483]
    DIRECTION OUTPUT ;
    USE SIGNAL ;
    PORT
      LAYER M5 ;
        RECT  48.144 0 48.168 0.084 ;
    END
  END b_d[483]
  PIN b_d[484]
    DIRECTION OUTPUT ;
    USE SIGNAL ;
    PORT
      LAYER M5 ;
        RECT  48.24 0 48.264 0.084 ;
    END
  END b_d[484]
  PIN b_d[485]
    DIRECTION OUTPUT ;
    USE SIGNAL ;
    PORT
      LAYER M5 ;
        RECT  48.336 0 48.36 0.084 ;
    END
  END b_d[485]
  PIN b_d[486]
    DIRECTION OUTPUT ;
    USE SIGNAL ;
    PORT
      LAYER M5 ;
        RECT  48.432 0 48.456 0.084 ;
    END
  END b_d[486]
  PIN b_d[487]
    DIRECTION OUTPUT ;
    USE SIGNAL ;
    PORT
      LAYER M5 ;
        RECT  48.528 0 48.552 0.084 ;
    END
  END b_d[487]
  PIN b_d[488]
    DIRECTION OUTPUT ;
    USE SIGNAL ;
    PORT
      LAYER M5 ;
        RECT  48.624 0 48.648 0.084 ;
    END
  END b_d[488]
  PIN b_d[489]
    DIRECTION OUTPUT ;
    USE SIGNAL ;
    PORT
      LAYER M5 ;
        RECT  48.72 0 48.744 0.084 ;
    END
  END b_d[489]
  PIN b_d[48]
    DIRECTION OUTPUT ;
    USE SIGNAL ;
    PORT
      LAYER M5 ;
        RECT  5.472 0 5.496 0.084 ;
    END
  END b_d[48]
  PIN b_d[490]
    DIRECTION OUTPUT ;
    USE SIGNAL ;
    PORT
      LAYER M5 ;
        RECT  48.816 0 48.84 0.084 ;
    END
  END b_d[490]
  PIN b_d[491]
    DIRECTION OUTPUT ;
    USE SIGNAL ;
    PORT
      LAYER M5 ;
        RECT  48.912 0 48.936 0.084 ;
    END
  END b_d[491]
  PIN b_d[492]
    DIRECTION OUTPUT ;
    USE SIGNAL ;
    PORT
      LAYER M5 ;
        RECT  49.008 0 49.032 0.084 ;
    END
  END b_d[492]
  PIN b_d[493]
    DIRECTION OUTPUT ;
    USE SIGNAL ;
    PORT
      LAYER M5 ;
        RECT  49.104 0 49.128 0.084 ;
    END
  END b_d[493]
  PIN b_d[494]
    DIRECTION OUTPUT ;
    USE SIGNAL ;
    PORT
      LAYER M5 ;
        RECT  49.2 0 49.224 0.084 ;
    END
  END b_d[494]
  PIN b_d[495]
    DIRECTION OUTPUT ;
    USE SIGNAL ;
    PORT
      LAYER M5 ;
        RECT  49.296 0 49.32 0.084 ;
    END
  END b_d[495]
  PIN b_d[496]
    DIRECTION OUTPUT ;
    USE SIGNAL ;
    PORT
      LAYER M5 ;
        RECT  49.392 0 49.416 0.084 ;
    END
  END b_d[496]
  PIN b_d[497]
    DIRECTION OUTPUT ;
    USE SIGNAL ;
    PORT
      LAYER M5 ;
        RECT  49.488 0 49.512 0.084 ;
    END
  END b_d[497]
  PIN b_d[498]
    DIRECTION OUTPUT ;
    USE SIGNAL ;
    PORT
      LAYER M5 ;
        RECT  49.584 0 49.608 0.084 ;
    END
  END b_d[498]
  PIN b_d[499]
    DIRECTION OUTPUT ;
    USE SIGNAL ;
    PORT
      LAYER M5 ;
        RECT  49.68 0 49.704 0.084 ;
    END
  END b_d[499]
  PIN b_d[49]
    DIRECTION OUTPUT ;
    USE SIGNAL ;
    PORT
      LAYER M5 ;
        RECT  5.568 0 5.592 0.084 ;
    END
  END b_d[49]
  PIN b_d[4]
    DIRECTION OUTPUT ;
    USE SIGNAL ;
    PORT
      LAYER M5 ;
        RECT  1.152 0 1.176 0.084 ;
    END
  END b_d[4]
  PIN b_d[500]
    DIRECTION OUTPUT ;
    USE SIGNAL ;
    PORT
      LAYER M5 ;
        RECT  49.776 0 49.8 0.084 ;
    END
  END b_d[500]
  PIN b_d[501]
    DIRECTION OUTPUT ;
    USE SIGNAL ;
    PORT
      LAYER M5 ;
        RECT  49.872 0 49.896 0.084 ;
    END
  END b_d[501]
  PIN b_d[502]
    DIRECTION OUTPUT ;
    USE SIGNAL ;
    PORT
      LAYER M5 ;
        RECT  49.968 0 49.992 0.084 ;
    END
  END b_d[502]
  PIN b_d[503]
    DIRECTION OUTPUT ;
    USE SIGNAL ;
    PORT
      LAYER M5 ;
        RECT  50.064 0 50.088 0.084 ;
    END
  END b_d[503]
  PIN b_d[504]
    DIRECTION OUTPUT ;
    USE SIGNAL ;
    PORT
      LAYER M5 ;
        RECT  50.208 0 50.232 0.084 ;
    END
  END b_d[504]
  PIN b_d[505]
    DIRECTION OUTPUT ;
    USE SIGNAL ;
    PORT
      LAYER M5 ;
        RECT  50.304 0 50.328 0.084 ;
    END
  END b_d[505]
  PIN b_d[506]
    DIRECTION OUTPUT ;
    USE SIGNAL ;
    PORT
      LAYER M5 ;
        RECT  50.4 0 50.424 0.084 ;
    END
  END b_d[506]
  PIN b_d[507]
    DIRECTION OUTPUT ;
    USE SIGNAL ;
    PORT
      LAYER M5 ;
        RECT  50.496 0 50.52 0.084 ;
    END
  END b_d[507]
  PIN b_d[508]
    DIRECTION OUTPUT ;
    USE SIGNAL ;
    PORT
      LAYER M5 ;
        RECT  50.592 0 50.616 0.084 ;
    END
  END b_d[508]
  PIN b_d[509]
    DIRECTION OUTPUT ;
    USE SIGNAL ;
    PORT
      LAYER M5 ;
        RECT  50.688 0 50.712 0.084 ;
    END
  END b_d[509]
  PIN b_d[50]
    DIRECTION OUTPUT ;
    USE SIGNAL ;
    PORT
      LAYER M5 ;
        RECT  5.664 0 5.688 0.084 ;
    END
  END b_d[50]
  PIN b_d[510]
    DIRECTION OUTPUT ;
    USE SIGNAL ;
    PORT
      LAYER M5 ;
        RECT  50.784 0 50.808 0.084 ;
    END
  END b_d[510]
  PIN b_d[511]
    DIRECTION OUTPUT ;
    USE SIGNAL ;
    PORT
      LAYER M5 ;
        RECT  50.88 0 50.904 0.084 ;
    END
  END b_d[511]
  PIN b_d[512]
    DIRECTION OUTPUT ;
    USE SIGNAL ;
    PORT
      LAYER M5 ;
        RECT  50.976 0 51 0.084 ;
    END
  END b_d[512]
  PIN b_d[513]
    DIRECTION OUTPUT ;
    USE SIGNAL ;
    PORT
      LAYER M5 ;
        RECT  51.072 0 51.096 0.084 ;
    END
  END b_d[513]
  PIN b_d[514]
    DIRECTION OUTPUT ;
    USE SIGNAL ;
    PORT
      LAYER M5 ;
        RECT  51.168 0 51.192 0.084 ;
    END
  END b_d[514]
  PIN b_d[515]
    DIRECTION OUTPUT ;
    USE SIGNAL ;
    PORT
      LAYER M5 ;
        RECT  51.264 0 51.288 0.084 ;
    END
  END b_d[515]
  PIN b_d[51]
    DIRECTION OUTPUT ;
    USE SIGNAL ;
    PORT
      LAYER M5 ;
        RECT  5.76 0 5.784 0.084 ;
    END
  END b_d[51]
  PIN b_d[52]
    DIRECTION OUTPUT ;
    USE SIGNAL ;
    PORT
      LAYER M5 ;
        RECT  5.856 0 5.88 0.084 ;
    END
  END b_d[52]
  PIN b_d[53]
    DIRECTION OUTPUT ;
    USE SIGNAL ;
    PORT
      LAYER M5 ;
        RECT  5.952 0 5.976 0.084 ;
    END
  END b_d[53]
  PIN b_d[54]
    DIRECTION OUTPUT ;
    USE SIGNAL ;
    PORT
      LAYER M5 ;
        RECT  6.048 0 6.072 0.084 ;
    END
  END b_d[54]
  PIN b_d[55]
    DIRECTION OUTPUT ;
    USE SIGNAL ;
    PORT
      LAYER M5 ;
        RECT  6.144 0 6.168 0.084 ;
    END
  END b_d[55]
  PIN b_d[56]
    DIRECTION OUTPUT ;
    USE SIGNAL ;
    PORT
      LAYER M5 ;
        RECT  6.24 0 6.264 0.084 ;
    END
  END b_d[56]
  PIN b_d[57]
    DIRECTION OUTPUT ;
    USE SIGNAL ;
    PORT
      LAYER M5 ;
        RECT  6.336 0 6.36 0.084 ;
    END
  END b_d[57]
  PIN b_d[58]
    DIRECTION OUTPUT ;
    USE SIGNAL ;
    PORT
      LAYER M5 ;
        RECT  6.48 0 6.504 0.084 ;
    END
  END b_d[58]
  PIN b_d[59]
    DIRECTION OUTPUT ;
    USE SIGNAL ;
    PORT
      LAYER M5 ;
        RECT  6.576 0 6.6 0.084 ;
    END
  END b_d[59]
  PIN b_d[5]
    DIRECTION OUTPUT ;
    USE SIGNAL ;
    PORT
      LAYER M5 ;
        RECT  1.248 0 1.272 0.084 ;
    END
  END b_d[5]
  PIN b_d[60]
    DIRECTION OUTPUT ;
    USE SIGNAL ;
    PORT
      LAYER M5 ;
        RECT  6.672 0 6.696 0.084 ;
    END
  END b_d[60]
  PIN b_d[61]
    DIRECTION OUTPUT ;
    USE SIGNAL ;
    PORT
      LAYER M5 ;
        RECT  6.768 0 6.792 0.084 ;
    END
  END b_d[61]
  PIN b_d[62]
    DIRECTION OUTPUT ;
    USE SIGNAL ;
    PORT
      LAYER M5 ;
        RECT  6.864 0 6.888 0.084 ;
    END
  END b_d[62]
  PIN b_d[63]
    DIRECTION OUTPUT ;
    USE SIGNAL ;
    PORT
      LAYER M5 ;
        RECT  6.96 0 6.984 0.084 ;
    END
  END b_d[63]
  PIN b_d[64]
    DIRECTION OUTPUT ;
    USE SIGNAL ;
    PORT
      LAYER M5 ;
        RECT  7.056 0 7.08 0.084 ;
    END
  END b_d[64]
  PIN b_d[65]
    DIRECTION OUTPUT ;
    USE SIGNAL ;
    PORT
      LAYER M5 ;
        RECT  7.152 0 7.176 0.084 ;
    END
  END b_d[65]
  PIN b_d[66]
    DIRECTION OUTPUT ;
    USE SIGNAL ;
    PORT
      LAYER M5 ;
        RECT  7.248 0 7.272 0.084 ;
    END
  END b_d[66]
  PIN b_d[67]
    DIRECTION OUTPUT ;
    USE SIGNAL ;
    PORT
      LAYER M5 ;
        RECT  7.344 0 7.368 0.084 ;
    END
  END b_d[67]
  PIN b_d[68]
    DIRECTION OUTPUT ;
    USE SIGNAL ;
    PORT
      LAYER M5 ;
        RECT  7.44 0 7.464 0.084 ;
    END
  END b_d[68]
  PIN b_d[69]
    DIRECTION OUTPUT ;
    USE SIGNAL ;
    PORT
      LAYER M5 ;
        RECT  7.536 0 7.56 0.084 ;
    END
  END b_d[69]
  PIN b_d[6]
    DIRECTION OUTPUT ;
    USE SIGNAL ;
    PORT
      LAYER M5 ;
        RECT  1.344 0 1.368 0.084 ;
    END
  END b_d[6]
  PIN b_d[70]
    DIRECTION OUTPUT ;
    USE SIGNAL ;
    PORT
      LAYER M5 ;
        RECT  7.632 0 7.656 0.084 ;
    END
  END b_d[70]
  PIN b_d[71]
    DIRECTION OUTPUT ;
    USE SIGNAL ;
    PORT
      LAYER M5 ;
        RECT  7.728 0 7.752 0.084 ;
    END
  END b_d[71]
  PIN b_d[72]
    DIRECTION OUTPUT ;
    USE SIGNAL ;
    PORT
      LAYER M5 ;
        RECT  7.824 0 7.848 0.084 ;
    END
  END b_d[72]
  PIN b_d[73]
    DIRECTION OUTPUT ;
    USE SIGNAL ;
    PORT
      LAYER M5 ;
        RECT  7.92 0 7.944 0.084 ;
    END
  END b_d[73]
  PIN b_d[74]
    DIRECTION OUTPUT ;
    USE SIGNAL ;
    PORT
      LAYER M5 ;
        RECT  8.016 0 8.04 0.084 ;
    END
  END b_d[74]
  PIN b_d[75]
    DIRECTION OUTPUT ;
    USE SIGNAL ;
    PORT
      LAYER M5 ;
        RECT  8.112 0 8.136 0.084 ;
    END
  END b_d[75]
  PIN b_d[76]
    DIRECTION OUTPUT ;
    USE SIGNAL ;
    PORT
      LAYER M5 ;
        RECT  8.208 0 8.232 0.084 ;
    END
  END b_d[76]
  PIN b_d[77]
    DIRECTION OUTPUT ;
    USE SIGNAL ;
    PORT
      LAYER M5 ;
        RECT  8.304 0 8.328 0.084 ;
    END
  END b_d[77]
  PIN b_d[78]
    DIRECTION OUTPUT ;
    USE SIGNAL ;
    PORT
      LAYER M5 ;
        RECT  8.4 0 8.424 0.084 ;
    END
  END b_d[78]
  PIN b_d[79]
    DIRECTION OUTPUT ;
    USE SIGNAL ;
    PORT
      LAYER M5 ;
        RECT  8.496 0 8.52 0.084 ;
    END
  END b_d[79]
  PIN b_d[7]
    DIRECTION OUTPUT ;
    USE SIGNAL ;
    PORT
      LAYER M5 ;
        RECT  1.44 0 1.464 0.084 ;
    END
  END b_d[7]
  PIN b_d[80]
    DIRECTION OUTPUT ;
    USE SIGNAL ;
    PORT
      LAYER M5 ;
        RECT  8.592 0 8.616 0.084 ;
    END
  END b_d[80]
  PIN b_d[81]
    DIRECTION OUTPUT ;
    USE SIGNAL ;
    PORT
      LAYER M5 ;
        RECT  8.688 0 8.712 0.084 ;
    END
  END b_d[81]
  PIN b_d[82]
    DIRECTION OUTPUT ;
    USE SIGNAL ;
    PORT
      LAYER M5 ;
        RECT  8.832 0 8.856 0.084 ;
    END
  END b_d[82]
  PIN b_d[83]
    DIRECTION OUTPUT ;
    USE SIGNAL ;
    PORT
      LAYER M5 ;
        RECT  8.928 0 8.952 0.084 ;
    END
  END b_d[83]
  PIN b_d[84]
    DIRECTION OUTPUT ;
    USE SIGNAL ;
    PORT
      LAYER M5 ;
        RECT  9.024 0 9.048 0.084 ;
    END
  END b_d[84]
  PIN b_d[85]
    DIRECTION OUTPUT ;
    USE SIGNAL ;
    PORT
      LAYER M5 ;
        RECT  9.12 0 9.144 0.084 ;
    END
  END b_d[85]
  PIN b_d[86]
    DIRECTION OUTPUT ;
    USE SIGNAL ;
    PORT
      LAYER M5 ;
        RECT  9.216 0 9.24 0.084 ;
    END
  END b_d[86]
  PIN b_d[87]
    DIRECTION OUTPUT ;
    USE SIGNAL ;
    PORT
      LAYER M5 ;
        RECT  9.312 0 9.336 0.084 ;
    END
  END b_d[87]
  PIN b_d[88]
    DIRECTION OUTPUT ;
    USE SIGNAL ;
    PORT
      LAYER M5 ;
        RECT  9.408 0 9.432 0.084 ;
    END
  END b_d[88]
  PIN b_d[89]
    DIRECTION OUTPUT ;
    USE SIGNAL ;
    PORT
      LAYER M5 ;
        RECT  9.504 0 9.528 0.084 ;
    END
  END b_d[89]
  PIN b_d[8]
    DIRECTION OUTPUT ;
    USE SIGNAL ;
    PORT
      LAYER M5 ;
        RECT  1.536 0 1.56 0.084 ;
    END
  END b_d[8]
  PIN b_d[90]
    DIRECTION OUTPUT ;
    USE SIGNAL ;
    PORT
      LAYER M5 ;
        RECT  9.6 0 9.624 0.084 ;
    END
  END b_d[90]
  PIN b_d[91]
    DIRECTION OUTPUT ;
    USE SIGNAL ;
    PORT
      LAYER M5 ;
        RECT  9.696 0 9.72 0.084 ;
    END
  END b_d[91]
  PIN b_d[92]
    DIRECTION OUTPUT ;
    USE SIGNAL ;
    PORT
      LAYER M5 ;
        RECT  9.792 0 9.816 0.084 ;
    END
  END b_d[92]
  PIN b_d[93]
    DIRECTION OUTPUT ;
    USE SIGNAL ;
    PORT
      LAYER M5 ;
        RECT  9.888 0 9.912 0.084 ;
    END
  END b_d[93]
  PIN b_d[94]
    DIRECTION OUTPUT ;
    USE SIGNAL ;
    PORT
      LAYER M5 ;
        RECT  9.984 0 10.008 0.084 ;
    END
  END b_d[94]
  PIN b_d[95]
    DIRECTION OUTPUT ;
    USE SIGNAL ;
    PORT
      LAYER M5 ;
        RECT  10.08 0 10.104 0.084 ;
    END
  END b_d[95]
  PIN b_d[96]
    DIRECTION OUTPUT ;
    USE SIGNAL ;
    PORT
      LAYER M5 ;
        RECT  10.176 0 10.2 0.084 ;
    END
  END b_d[96]
  PIN b_d[97]
    DIRECTION OUTPUT ;
    USE SIGNAL ;
    PORT
      LAYER M5 ;
        RECT  10.272 0 10.296 0.084 ;
    END
  END b_d[97]
  PIN b_d[98]
    DIRECTION OUTPUT ;
    USE SIGNAL ;
    PORT
      LAYER M5 ;
        RECT  10.368 0 10.392 0.084 ;
    END
  END b_d[98]
  PIN b_d[99]
    DIRECTION OUTPUT ;
    USE SIGNAL ;
    PORT
      LAYER M5 ;
        RECT  10.464 0 10.488 0.084 ;
    END
  END b_d[99]
  PIN b_d[9]
    DIRECTION OUTPUT ;
    USE SIGNAL ;
    PORT
      LAYER M5 ;
        RECT  1.632 0 1.656 0.084 ;
    END
  END b_d[9]
  PIN ck
    DIRECTION INPUT ;
    USE SIGNAL ;
    PORT
      LAYER M5 ;
        RECT  52.08 103.572 52.104 103.656 ;
    END
  END ck
  PIN rst_n
    DIRECTION INPUT ;
    USE SIGNAL ;
    PORT
      LAYER M5 ;
        RECT  52.368 103.572 52.392 103.656 ;
    END
  END rst_n
  PIN sidx[0]
    DIRECTION INPUT ;
    USE SIGNAL ;
    PORT
      LAYER M5 ;
        RECT  0.288 103.572 0.312 103.656 ;
    END
  END sidx[0]
  PIN sidx[1]
    DIRECTION INPUT ;
    USE SIGNAL ;
    PORT
      LAYER M5 ;
        RECT  0.48 103.572 0.504 103.656 ;
    END
  END sidx[1]
  PIN sidx[2]
    DIRECTION INPUT ;
    USE SIGNAL ;
    PORT
      LAYER M5 ;
        RECT  0.672 103.572 0.696 103.656 ;
    END
  END sidx[2]
  PIN tap_d[0]
    DIRECTION OUTPUT ;
    USE SIGNAL ;
    PORT
      LAYER M4 ;
        RECT  0 26.976 0.084 27 ;
    END
  END tap_d[0]
  PIN tap_d[100]
    DIRECTION OUTPUT ;
    USE SIGNAL ;
    PORT
      LAYER M4 ;
        RECT  0 36.912 0.084 36.936 ;
    END
  END tap_d[100]
  PIN tap_d[101]
    DIRECTION OUTPUT ;
    USE SIGNAL ;
    PORT
      LAYER M4 ;
        RECT  0 37.008 0.084 37.032 ;
    END
  END tap_d[101]
  PIN tap_d[102]
    DIRECTION OUTPUT ;
    USE SIGNAL ;
    PORT
      LAYER M4 ;
        RECT  0 37.104 0.084 37.128 ;
    END
  END tap_d[102]
  PIN tap_d[103]
    DIRECTION OUTPUT ;
    USE SIGNAL ;
    PORT
      LAYER M4 ;
        RECT  0 37.2 0.084 37.224 ;
    END
  END tap_d[103]
  PIN tap_d[104]
    DIRECTION OUTPUT ;
    USE SIGNAL ;
    PORT
      LAYER M4 ;
        RECT  0 37.296 0.084 37.32 ;
    END
  END tap_d[104]
  PIN tap_d[105]
    DIRECTION OUTPUT ;
    USE SIGNAL ;
    PORT
      LAYER M4 ;
        RECT  0 37.392 0.084 37.416 ;
    END
  END tap_d[105]
  PIN tap_d[106]
    DIRECTION OUTPUT ;
    USE SIGNAL ;
    PORT
      LAYER M4 ;
        RECT  0 37.536 0.084 37.56 ;
    END
  END tap_d[106]
  PIN tap_d[107]
    DIRECTION OUTPUT ;
    USE SIGNAL ;
    PORT
      LAYER M4 ;
        RECT  0 37.632 0.084 37.656 ;
    END
  END tap_d[107]
  PIN tap_d[108]
    DIRECTION OUTPUT ;
    USE SIGNAL ;
    PORT
      LAYER M4 ;
        RECT  0 37.728 0.084 37.752 ;
    END
  END tap_d[108]
  PIN tap_d[109]
    DIRECTION OUTPUT ;
    USE SIGNAL ;
    PORT
      LAYER M4 ;
        RECT  0 37.824 0.084 37.848 ;
    END
  END tap_d[109]
  PIN tap_d[10]
    DIRECTION OUTPUT ;
    USE SIGNAL ;
    PORT
      LAYER M4 ;
        RECT  0 27.984 0.084 28.008 ;
    END
  END tap_d[10]
  PIN tap_d[110]
    DIRECTION OUTPUT ;
    USE SIGNAL ;
    PORT
      LAYER M4 ;
        RECT  0 37.92 0.084 37.944 ;
    END
  END tap_d[110]
  PIN tap_d[111]
    DIRECTION OUTPUT ;
    USE SIGNAL ;
    PORT
      LAYER M4 ;
        RECT  0 38.016 0.084 38.04 ;
    END
  END tap_d[111]
  PIN tap_d[112]
    DIRECTION OUTPUT ;
    USE SIGNAL ;
    PORT
      LAYER M4 ;
        RECT  0 38.112 0.084 38.136 ;
    END
  END tap_d[112]
  PIN tap_d[113]
    DIRECTION OUTPUT ;
    USE SIGNAL ;
    PORT
      LAYER M4 ;
        RECT  0 38.208 0.084 38.232 ;
    END
  END tap_d[113]
  PIN tap_d[114]
    DIRECTION OUTPUT ;
    USE SIGNAL ;
    PORT
      LAYER M4 ;
        RECT  0 38.304 0.084 38.328 ;
    END
  END tap_d[114]
  PIN tap_d[115]
    DIRECTION OUTPUT ;
    USE SIGNAL ;
    PORT
      LAYER M4 ;
        RECT  0 38.4 0.084 38.424 ;
    END
  END tap_d[115]
  PIN tap_d[116]
    DIRECTION OUTPUT ;
    USE SIGNAL ;
    PORT
      LAYER M4 ;
        RECT  0 38.496 0.084 38.52 ;
    END
  END tap_d[116]
  PIN tap_d[117]
    DIRECTION OUTPUT ;
    USE SIGNAL ;
    PORT
      LAYER M4 ;
        RECT  0 38.592 0.084 38.616 ;
    END
  END tap_d[117]
  PIN tap_d[118]
    DIRECTION OUTPUT ;
    USE SIGNAL ;
    PORT
      LAYER M4 ;
        RECT  0 38.688 0.084 38.712 ;
    END
  END tap_d[118]
  PIN tap_d[119]
    DIRECTION OUTPUT ;
    USE SIGNAL ;
    PORT
      LAYER M4 ;
        RECT  0 38.784 0.084 38.808 ;
    END
  END tap_d[119]
  PIN tap_d[11]
    DIRECTION OUTPUT ;
    USE SIGNAL ;
    PORT
      LAYER M4 ;
        RECT  0 28.08 0.084 28.104 ;
    END
  END tap_d[11]
  PIN tap_d[120]
    DIRECTION OUTPUT ;
    USE SIGNAL ;
    PORT
      LAYER M4 ;
        RECT  0 38.928 0.084 38.952 ;
    END
  END tap_d[120]
  PIN tap_d[121]
    DIRECTION OUTPUT ;
    USE SIGNAL ;
    PORT
      LAYER M4 ;
        RECT  0 39.024 0.084 39.048 ;
    END
  END tap_d[121]
  PIN tap_d[122]
    DIRECTION OUTPUT ;
    USE SIGNAL ;
    PORT
      LAYER M4 ;
        RECT  0 39.12 0.084 39.144 ;
    END
  END tap_d[122]
  PIN tap_d[123]
    DIRECTION OUTPUT ;
    USE SIGNAL ;
    PORT
      LAYER M4 ;
        RECT  0 39.216 0.084 39.24 ;
    END
  END tap_d[123]
  PIN tap_d[124]
    DIRECTION OUTPUT ;
    USE SIGNAL ;
    PORT
      LAYER M4 ;
        RECT  0 39.312 0.084 39.336 ;
    END
  END tap_d[124]
  PIN tap_d[125]
    DIRECTION OUTPUT ;
    USE SIGNAL ;
    PORT
      LAYER M4 ;
        RECT  0 39.408 0.084 39.432 ;
    END
  END tap_d[125]
  PIN tap_d[126]
    DIRECTION OUTPUT ;
    USE SIGNAL ;
    PORT
      LAYER M4 ;
        RECT  0 39.504 0.084 39.528 ;
    END
  END tap_d[126]
  PIN tap_d[127]
    DIRECTION OUTPUT ;
    USE SIGNAL ;
    PORT
      LAYER M4 ;
        RECT  0 39.6 0.084 39.624 ;
    END
  END tap_d[127]
  PIN tap_d[128]
    DIRECTION OUTPUT ;
    USE SIGNAL ;
    PORT
      LAYER M4 ;
        RECT  0 39.696 0.084 39.72 ;
    END
  END tap_d[128]
  PIN tap_d[129]
    DIRECTION OUTPUT ;
    USE SIGNAL ;
    PORT
      LAYER M4 ;
        RECT  0 39.792 0.084 39.816 ;
    END
  END tap_d[129]
  PIN tap_d[12]
    DIRECTION OUTPUT ;
    USE SIGNAL ;
    PORT
      LAYER M4 ;
        RECT  0 28.176 0.084 28.2 ;
    END
  END tap_d[12]
  PIN tap_d[130]
    DIRECTION OUTPUT ;
    USE SIGNAL ;
    PORT
      LAYER M4 ;
        RECT  0 39.888 0.084 39.912 ;
    END
  END tap_d[130]
  PIN tap_d[131]
    DIRECTION OUTPUT ;
    USE SIGNAL ;
    PORT
      LAYER M4 ;
        RECT  0 39.984 0.084 40.008 ;
    END
  END tap_d[131]
  PIN tap_d[132]
    DIRECTION OUTPUT ;
    USE SIGNAL ;
    PORT
      LAYER M4 ;
        RECT  0 40.08 0.084 40.104 ;
    END
  END tap_d[132]
  PIN tap_d[133]
    DIRECTION OUTPUT ;
    USE SIGNAL ;
    PORT
      LAYER M4 ;
        RECT  0 40.176 0.084 40.2 ;
    END
  END tap_d[133]
  PIN tap_d[134]
    DIRECTION OUTPUT ;
    USE SIGNAL ;
    PORT
      LAYER M4 ;
        RECT  0 40.32 0.084 40.344 ;
    END
  END tap_d[134]
  PIN tap_d[135]
    DIRECTION OUTPUT ;
    USE SIGNAL ;
    PORT
      LAYER M4 ;
        RECT  0 40.416 0.084 40.44 ;
    END
  END tap_d[135]
  PIN tap_d[136]
    DIRECTION OUTPUT ;
    USE SIGNAL ;
    PORT
      LAYER M4 ;
        RECT  0 40.512 0.084 40.536 ;
    END
  END tap_d[136]
  PIN tap_d[137]
    DIRECTION OUTPUT ;
    USE SIGNAL ;
    PORT
      LAYER M4 ;
        RECT  0 40.608 0.084 40.632 ;
    END
  END tap_d[137]
  PIN tap_d[138]
    DIRECTION OUTPUT ;
    USE SIGNAL ;
    PORT
      LAYER M4 ;
        RECT  0 40.704 0.084 40.728 ;
    END
  END tap_d[138]
  PIN tap_d[139]
    DIRECTION OUTPUT ;
    USE SIGNAL ;
    PORT
      LAYER M4 ;
        RECT  0 40.8 0.084 40.824 ;
    END
  END tap_d[139]
  PIN tap_d[13]
    DIRECTION OUTPUT ;
    USE SIGNAL ;
    PORT
      LAYER M4 ;
        RECT  0 28.272 0.084 28.296 ;
    END
  END tap_d[13]
  PIN tap_d[140]
    DIRECTION OUTPUT ;
    USE SIGNAL ;
    PORT
      LAYER M4 ;
        RECT  0 40.896 0.084 40.92 ;
    END
  END tap_d[140]
  PIN tap_d[141]
    DIRECTION OUTPUT ;
    USE SIGNAL ;
    PORT
      LAYER M4 ;
        RECT  0 40.992 0.084 41.016 ;
    END
  END tap_d[141]
  PIN tap_d[142]
    DIRECTION OUTPUT ;
    USE SIGNAL ;
    PORT
      LAYER M4 ;
        RECT  0 41.088 0.084 41.112 ;
    END
  END tap_d[142]
  PIN tap_d[143]
    DIRECTION OUTPUT ;
    USE SIGNAL ;
    PORT
      LAYER M4 ;
        RECT  0 41.184 0.084 41.208 ;
    END
  END tap_d[143]
  PIN tap_d[144]
    DIRECTION OUTPUT ;
    USE SIGNAL ;
    PORT
      LAYER M4 ;
        RECT  0 41.28 0.084 41.304 ;
    END
  END tap_d[144]
  PIN tap_d[145]
    DIRECTION OUTPUT ;
    USE SIGNAL ;
    PORT
      LAYER M4 ;
        RECT  0 41.376 0.084 41.4 ;
    END
  END tap_d[145]
  PIN tap_d[146]
    DIRECTION OUTPUT ;
    USE SIGNAL ;
    PORT
      LAYER M4 ;
        RECT  0 41.472 0.084 41.496 ;
    END
  END tap_d[146]
  PIN tap_d[147]
    DIRECTION OUTPUT ;
    USE SIGNAL ;
    PORT
      LAYER M4 ;
        RECT  0 41.568 0.084 41.592 ;
    END
  END tap_d[147]
  PIN tap_d[148]
    DIRECTION OUTPUT ;
    USE SIGNAL ;
    PORT
      LAYER M4 ;
        RECT  0 41.712 0.084 41.736 ;
    END
  END tap_d[148]
  PIN tap_d[149]
    DIRECTION OUTPUT ;
    USE SIGNAL ;
    PORT
      LAYER M4 ;
        RECT  0 41.808 0.084 41.832 ;
    END
  END tap_d[149]
  PIN tap_d[14]
    DIRECTION OUTPUT ;
    USE SIGNAL ;
    PORT
      LAYER M4 ;
        RECT  0 28.368 0.084 28.392 ;
    END
  END tap_d[14]
  PIN tap_d[150]
    DIRECTION OUTPUT ;
    USE SIGNAL ;
    PORT
      LAYER M4 ;
        RECT  0 41.904 0.084 41.928 ;
    END
  END tap_d[150]
  PIN tap_d[151]
    DIRECTION OUTPUT ;
    USE SIGNAL ;
    PORT
      LAYER M4 ;
        RECT  0 42 0.084 42.024 ;
    END
  END tap_d[151]
  PIN tap_d[152]
    DIRECTION OUTPUT ;
    USE SIGNAL ;
    PORT
      LAYER M4 ;
        RECT  0 42.096 0.084 42.12 ;
    END
  END tap_d[152]
  PIN tap_d[153]
    DIRECTION OUTPUT ;
    USE SIGNAL ;
    PORT
      LAYER M4 ;
        RECT  0 42.192 0.084 42.216 ;
    END
  END tap_d[153]
  PIN tap_d[154]
    DIRECTION OUTPUT ;
    USE SIGNAL ;
    PORT
      LAYER M4 ;
        RECT  0 42.288 0.084 42.312 ;
    END
  END tap_d[154]
  PIN tap_d[155]
    DIRECTION OUTPUT ;
    USE SIGNAL ;
    PORT
      LAYER M4 ;
        RECT  0 42.384 0.084 42.408 ;
    END
  END tap_d[155]
  PIN tap_d[156]
    DIRECTION OUTPUT ;
    USE SIGNAL ;
    PORT
      LAYER M4 ;
        RECT  0 42.48 0.084 42.504 ;
    END
  END tap_d[156]
  PIN tap_d[157]
    DIRECTION OUTPUT ;
    USE SIGNAL ;
    PORT
      LAYER M4 ;
        RECT  0 42.576 0.084 42.6 ;
    END
  END tap_d[157]
  PIN tap_d[158]
    DIRECTION OUTPUT ;
    USE SIGNAL ;
    PORT
      LAYER M4 ;
        RECT  0 42.672 0.084 42.696 ;
    END
  END tap_d[158]
  PIN tap_d[159]
    DIRECTION OUTPUT ;
    USE SIGNAL ;
    PORT
      LAYER M4 ;
        RECT  0 42.768 0.084 42.792 ;
    END
  END tap_d[159]
  PIN tap_d[15]
    DIRECTION OUTPUT ;
    USE SIGNAL ;
    PORT
      LAYER M4 ;
        RECT  0 28.464 0.084 28.488 ;
    END
  END tap_d[15]
  PIN tap_d[160]
    DIRECTION OUTPUT ;
    USE SIGNAL ;
    PORT
      LAYER M4 ;
        RECT  0 42.864 0.084 42.888 ;
    END
  END tap_d[160]
  PIN tap_d[161]
    DIRECTION OUTPUT ;
    USE SIGNAL ;
    PORT
      LAYER M4 ;
        RECT  0 42.96 0.084 42.984 ;
    END
  END tap_d[161]
  PIN tap_d[162]
    DIRECTION OUTPUT ;
    USE SIGNAL ;
    PORT
      LAYER M4 ;
        RECT  0 43.104 0.084 43.128 ;
    END
  END tap_d[162]
  PIN tap_d[163]
    DIRECTION OUTPUT ;
    USE SIGNAL ;
    PORT
      LAYER M4 ;
        RECT  0 43.2 0.084 43.224 ;
    END
  END tap_d[163]
  PIN tap_d[164]
    DIRECTION OUTPUT ;
    USE SIGNAL ;
    PORT
      LAYER M4 ;
        RECT  0 43.296 0.084 43.32 ;
    END
  END tap_d[164]
  PIN tap_d[165]
    DIRECTION OUTPUT ;
    USE SIGNAL ;
    PORT
      LAYER M4 ;
        RECT  0 43.392 0.084 43.416 ;
    END
  END tap_d[165]
  PIN tap_d[166]
    DIRECTION OUTPUT ;
    USE SIGNAL ;
    PORT
      LAYER M4 ;
        RECT  0 43.488 0.084 43.512 ;
    END
  END tap_d[166]
  PIN tap_d[167]
    DIRECTION OUTPUT ;
    USE SIGNAL ;
    PORT
      LAYER M4 ;
        RECT  0 43.584 0.084 43.608 ;
    END
  END tap_d[167]
  PIN tap_d[168]
    DIRECTION OUTPUT ;
    USE SIGNAL ;
    PORT
      LAYER M4 ;
        RECT  0 43.68 0.084 43.704 ;
    END
  END tap_d[168]
  PIN tap_d[169]
    DIRECTION OUTPUT ;
    USE SIGNAL ;
    PORT
      LAYER M4 ;
        RECT  0 43.776 0.084 43.8 ;
    END
  END tap_d[169]
  PIN tap_d[16]
    DIRECTION OUTPUT ;
    USE SIGNAL ;
    PORT
      LAYER M4 ;
        RECT  0 28.56 0.084 28.584 ;
    END
  END tap_d[16]
  PIN tap_d[170]
    DIRECTION OUTPUT ;
    USE SIGNAL ;
    PORT
      LAYER M4 ;
        RECT  0 43.872 0.084 43.896 ;
    END
  END tap_d[170]
  PIN tap_d[171]
    DIRECTION OUTPUT ;
    USE SIGNAL ;
    PORT
      LAYER M4 ;
        RECT  0 43.968 0.084 43.992 ;
    END
  END tap_d[171]
  PIN tap_d[172]
    DIRECTION OUTPUT ;
    USE SIGNAL ;
    PORT
      LAYER M4 ;
        RECT  0 44.064 0.084 44.088 ;
    END
  END tap_d[172]
  PIN tap_d[173]
    DIRECTION OUTPUT ;
    USE SIGNAL ;
    PORT
      LAYER M4 ;
        RECT  0 44.16 0.084 44.184 ;
    END
  END tap_d[173]
  PIN tap_d[174]
    DIRECTION OUTPUT ;
    USE SIGNAL ;
    PORT
      LAYER M4 ;
        RECT  0 44.256 0.084 44.28 ;
    END
  END tap_d[174]
  PIN tap_d[175]
    DIRECTION OUTPUT ;
    USE SIGNAL ;
    PORT
      LAYER M4 ;
        RECT  0 44.352 0.084 44.376 ;
    END
  END tap_d[175]
  PIN tap_d[176]
    DIRECTION OUTPUT ;
    USE SIGNAL ;
    PORT
      LAYER M4 ;
        RECT  0 44.496 0.084 44.52 ;
    END
  END tap_d[176]
  PIN tap_d[177]
    DIRECTION OUTPUT ;
    USE SIGNAL ;
    PORT
      LAYER M4 ;
        RECT  0 44.592 0.084 44.616 ;
    END
  END tap_d[177]
  PIN tap_d[178]
    DIRECTION OUTPUT ;
    USE SIGNAL ;
    PORT
      LAYER M4 ;
        RECT  0 44.688 0.084 44.712 ;
    END
  END tap_d[178]
  PIN tap_d[179]
    DIRECTION OUTPUT ;
    USE SIGNAL ;
    PORT
      LAYER M4 ;
        RECT  0 44.784 0.084 44.808 ;
    END
  END tap_d[179]
  PIN tap_d[17]
    DIRECTION OUTPUT ;
    USE SIGNAL ;
    PORT
      LAYER M4 ;
        RECT  0 28.656 0.084 28.68 ;
    END
  END tap_d[17]
  PIN tap_d[180]
    DIRECTION OUTPUT ;
    USE SIGNAL ;
    PORT
      LAYER M4 ;
        RECT  0 44.88 0.084 44.904 ;
    END
  END tap_d[180]
  PIN tap_d[181]
    DIRECTION OUTPUT ;
    USE SIGNAL ;
    PORT
      LAYER M4 ;
        RECT  0 44.976 0.084 45 ;
    END
  END tap_d[181]
  PIN tap_d[182]
    DIRECTION OUTPUT ;
    USE SIGNAL ;
    PORT
      LAYER M4 ;
        RECT  0 45.072 0.084 45.096 ;
    END
  END tap_d[182]
  PIN tap_d[183]
    DIRECTION OUTPUT ;
    USE SIGNAL ;
    PORT
      LAYER M4 ;
        RECT  0 45.168 0.084 45.192 ;
    END
  END tap_d[183]
  PIN tap_d[184]
    DIRECTION OUTPUT ;
    USE SIGNAL ;
    PORT
      LAYER M4 ;
        RECT  0 45.264 0.084 45.288 ;
    END
  END tap_d[184]
  PIN tap_d[185]
    DIRECTION OUTPUT ;
    USE SIGNAL ;
    PORT
      LAYER M4 ;
        RECT  0 45.36 0.084 45.384 ;
    END
  END tap_d[185]
  PIN tap_d[186]
    DIRECTION OUTPUT ;
    USE SIGNAL ;
    PORT
      LAYER M4 ;
        RECT  0 45.456 0.084 45.48 ;
    END
  END tap_d[186]
  PIN tap_d[187]
    DIRECTION OUTPUT ;
    USE SIGNAL ;
    PORT
      LAYER M4 ;
        RECT  0 45.552 0.084 45.576 ;
    END
  END tap_d[187]
  PIN tap_d[188]
    DIRECTION OUTPUT ;
    USE SIGNAL ;
    PORT
      LAYER M4 ;
        RECT  0 45.648 0.084 45.672 ;
    END
  END tap_d[188]
  PIN tap_d[189]
    DIRECTION OUTPUT ;
    USE SIGNAL ;
    PORT
      LAYER M4 ;
        RECT  0 45.744 0.084 45.768 ;
    END
  END tap_d[189]
  PIN tap_d[18]
    DIRECTION OUTPUT ;
    USE SIGNAL ;
    PORT
      LAYER M4 ;
        RECT  0 28.752 0.084 28.776 ;
    END
  END tap_d[18]
  PIN tap_d[190]
    DIRECTION OUTPUT ;
    USE SIGNAL ;
    PORT
      LAYER M4 ;
        RECT  0 45.888 0.084 45.912 ;
    END
  END tap_d[190]
  PIN tap_d[191]
    DIRECTION OUTPUT ;
    USE SIGNAL ;
    PORT
      LAYER M4 ;
        RECT  0 45.984 0.084 46.008 ;
    END
  END tap_d[191]
  PIN tap_d[192]
    DIRECTION OUTPUT ;
    USE SIGNAL ;
    PORT
      LAYER M4 ;
        RECT  0 46.08 0.084 46.104 ;
    END
  END tap_d[192]
  PIN tap_d[193]
    DIRECTION OUTPUT ;
    USE SIGNAL ;
    PORT
      LAYER M4 ;
        RECT  0 46.176 0.084 46.2 ;
    END
  END tap_d[193]
  PIN tap_d[194]
    DIRECTION OUTPUT ;
    USE SIGNAL ;
    PORT
      LAYER M4 ;
        RECT  0 46.272 0.084 46.296 ;
    END
  END tap_d[194]
  PIN tap_d[195]
    DIRECTION OUTPUT ;
    USE SIGNAL ;
    PORT
      LAYER M4 ;
        RECT  0 46.368 0.084 46.392 ;
    END
  END tap_d[195]
  PIN tap_d[196]
    DIRECTION OUTPUT ;
    USE SIGNAL ;
    PORT
      LAYER M4 ;
        RECT  0 46.464 0.084 46.488 ;
    END
  END tap_d[196]
  PIN tap_d[197]
    DIRECTION OUTPUT ;
    USE SIGNAL ;
    PORT
      LAYER M4 ;
        RECT  0 46.56 0.084 46.584 ;
    END
  END tap_d[197]
  PIN tap_d[198]
    DIRECTION OUTPUT ;
    USE SIGNAL ;
    PORT
      LAYER M4 ;
        RECT  0 46.656 0.084 46.68 ;
    END
  END tap_d[198]
  PIN tap_d[199]
    DIRECTION OUTPUT ;
    USE SIGNAL ;
    PORT
      LAYER M4 ;
        RECT  0 46.752 0.084 46.776 ;
    END
  END tap_d[199]
  PIN tap_d[19]
    DIRECTION OUTPUT ;
    USE SIGNAL ;
    PORT
      LAYER M4 ;
        RECT  0 28.848 0.084 28.872 ;
    END
  END tap_d[19]
  PIN tap_d[1]
    DIRECTION OUTPUT ;
    USE SIGNAL ;
    PORT
      LAYER M4 ;
        RECT  0 27.072 0.084 27.096 ;
    END
  END tap_d[1]
  PIN tap_d[200]
    DIRECTION OUTPUT ;
    USE SIGNAL ;
    PORT
      LAYER M4 ;
        RECT  0 46.848 0.084 46.872 ;
    END
  END tap_d[200]
  PIN tap_d[201]
    DIRECTION OUTPUT ;
    USE SIGNAL ;
    PORT
      LAYER M4 ;
        RECT  0 46.944 0.084 46.968 ;
    END
  END tap_d[201]
  PIN tap_d[202]
    DIRECTION OUTPUT ;
    USE SIGNAL ;
    PORT
      LAYER M4 ;
        RECT  0 47.04 0.084 47.064 ;
    END
  END tap_d[202]
  PIN tap_d[203]
    DIRECTION OUTPUT ;
    USE SIGNAL ;
    PORT
      LAYER M4 ;
        RECT  0 47.136 0.084 47.16 ;
    END
  END tap_d[203]
  PIN tap_d[204]
    DIRECTION OUTPUT ;
    USE SIGNAL ;
    PORT
      LAYER M4 ;
        RECT  0 47.28 0.084 47.304 ;
    END
  END tap_d[204]
  PIN tap_d[205]
    DIRECTION OUTPUT ;
    USE SIGNAL ;
    PORT
      LAYER M4 ;
        RECT  0 47.376 0.084 47.4 ;
    END
  END tap_d[205]
  PIN tap_d[206]
    DIRECTION OUTPUT ;
    USE SIGNAL ;
    PORT
      LAYER M4 ;
        RECT  0 47.472 0.084 47.496 ;
    END
  END tap_d[206]
  PIN tap_d[207]
    DIRECTION OUTPUT ;
    USE SIGNAL ;
    PORT
      LAYER M4 ;
        RECT  0 47.568 0.084 47.592 ;
    END
  END tap_d[207]
  PIN tap_d[208]
    DIRECTION OUTPUT ;
    USE SIGNAL ;
    PORT
      LAYER M4 ;
        RECT  0 47.664 0.084 47.688 ;
    END
  END tap_d[208]
  PIN tap_d[209]
    DIRECTION OUTPUT ;
    USE SIGNAL ;
    PORT
      LAYER M4 ;
        RECT  0 47.76 0.084 47.784 ;
    END
  END tap_d[209]
  PIN tap_d[20]
    DIRECTION OUTPUT ;
    USE SIGNAL ;
    PORT
      LAYER M4 ;
        RECT  0 28.944 0.084 28.968 ;
    END
  END tap_d[20]
  PIN tap_d[210]
    DIRECTION OUTPUT ;
    USE SIGNAL ;
    PORT
      LAYER M4 ;
        RECT  0 47.856 0.084 47.88 ;
    END
  END tap_d[210]
  PIN tap_d[211]
    DIRECTION OUTPUT ;
    USE SIGNAL ;
    PORT
      LAYER M4 ;
        RECT  0 47.952 0.084 47.976 ;
    END
  END tap_d[211]
  PIN tap_d[212]
    DIRECTION OUTPUT ;
    USE SIGNAL ;
    PORT
      LAYER M4 ;
        RECT  0 48.048 0.084 48.072 ;
    END
  END tap_d[212]
  PIN tap_d[213]
    DIRECTION OUTPUT ;
    USE SIGNAL ;
    PORT
      LAYER M4 ;
        RECT  0 48.144 0.084 48.168 ;
    END
  END tap_d[213]
  PIN tap_d[214]
    DIRECTION OUTPUT ;
    USE SIGNAL ;
    PORT
      LAYER M4 ;
        RECT  0 48.24 0.084 48.264 ;
    END
  END tap_d[214]
  PIN tap_d[215]
    DIRECTION OUTPUT ;
    USE SIGNAL ;
    PORT
      LAYER M4 ;
        RECT  0 48.336 0.084 48.36 ;
    END
  END tap_d[215]
  PIN tap_d[216]
    DIRECTION OUTPUT ;
    USE SIGNAL ;
    PORT
      LAYER M4 ;
        RECT  0 48.432 0.084 48.456 ;
    END
  END tap_d[216]
  PIN tap_d[217]
    DIRECTION OUTPUT ;
    USE SIGNAL ;
    PORT
      LAYER M4 ;
        RECT  0 48.528 0.084 48.552 ;
    END
  END tap_d[217]
  PIN tap_d[218]
    DIRECTION OUTPUT ;
    USE SIGNAL ;
    PORT
      LAYER M4 ;
        RECT  0 48.624 0.084 48.648 ;
    END
  END tap_d[218]
  PIN tap_d[219]
    DIRECTION OUTPUT ;
    USE SIGNAL ;
    PORT
      LAYER M4 ;
        RECT  0 48.768 0.084 48.792 ;
    END
  END tap_d[219]
  PIN tap_d[21]
    DIRECTION OUTPUT ;
    USE SIGNAL ;
    PORT
      LAYER M4 ;
        RECT  0 29.088 0.084 29.112 ;
    END
  END tap_d[21]
  PIN tap_d[220]
    DIRECTION OUTPUT ;
    USE SIGNAL ;
    PORT
      LAYER M4 ;
        RECT  0 48.864 0.084 48.888 ;
    END
  END tap_d[220]
  PIN tap_d[221]
    DIRECTION OUTPUT ;
    USE SIGNAL ;
    PORT
      LAYER M4 ;
        RECT  0 48.96 0.084 48.984 ;
    END
  END tap_d[221]
  PIN tap_d[222]
    DIRECTION OUTPUT ;
    USE SIGNAL ;
    PORT
      LAYER M4 ;
        RECT  0 49.056 0.084 49.08 ;
    END
  END tap_d[222]
  PIN tap_d[223]
    DIRECTION OUTPUT ;
    USE SIGNAL ;
    PORT
      LAYER M4 ;
        RECT  0 49.152 0.084 49.176 ;
    END
  END tap_d[223]
  PIN tap_d[224]
    DIRECTION OUTPUT ;
    USE SIGNAL ;
    PORT
      LAYER M4 ;
        RECT  0 49.248 0.084 49.272 ;
    END
  END tap_d[224]
  PIN tap_d[225]
    DIRECTION OUTPUT ;
    USE SIGNAL ;
    PORT
      LAYER M4 ;
        RECT  0 49.344 0.084 49.368 ;
    END
  END tap_d[225]
  PIN tap_d[226]
    DIRECTION OUTPUT ;
    USE SIGNAL ;
    PORT
      LAYER M4 ;
        RECT  0 49.44 0.084 49.464 ;
    END
  END tap_d[226]
  PIN tap_d[227]
    DIRECTION OUTPUT ;
    USE SIGNAL ;
    PORT
      LAYER M4 ;
        RECT  0 49.536 0.084 49.56 ;
    END
  END tap_d[227]
  PIN tap_d[228]
    DIRECTION OUTPUT ;
    USE SIGNAL ;
    PORT
      LAYER M4 ;
        RECT  0 49.632 0.084 49.656 ;
    END
  END tap_d[228]
  PIN tap_d[229]
    DIRECTION OUTPUT ;
    USE SIGNAL ;
    PORT
      LAYER M4 ;
        RECT  0 49.728 0.084 49.752 ;
    END
  END tap_d[229]
  PIN tap_d[22]
    DIRECTION OUTPUT ;
    USE SIGNAL ;
    PORT
      LAYER M4 ;
        RECT  0 29.184 0.084 29.208 ;
    END
  END tap_d[22]
  PIN tap_d[230]
    DIRECTION OUTPUT ;
    USE SIGNAL ;
    PORT
      LAYER M4 ;
        RECT  0 49.824 0.084 49.848 ;
    END
  END tap_d[230]
  PIN tap_d[231]
    DIRECTION OUTPUT ;
    USE SIGNAL ;
    PORT
      LAYER M4 ;
        RECT  0 49.92 0.084 49.944 ;
    END
  END tap_d[231]
  PIN tap_d[232]
    DIRECTION OUTPUT ;
    USE SIGNAL ;
    PORT
      LAYER M4 ;
        RECT  0 50.016 0.084 50.04 ;
    END
  END tap_d[232]
  PIN tap_d[233]
    DIRECTION OUTPUT ;
    USE SIGNAL ;
    PORT
      LAYER M4 ;
        RECT  0 50.16 0.084 50.184 ;
    END
  END tap_d[233]
  PIN tap_d[234]
    DIRECTION OUTPUT ;
    USE SIGNAL ;
    PORT
      LAYER M4 ;
        RECT  0 50.256 0.084 50.28 ;
    END
  END tap_d[234]
  PIN tap_d[235]
    DIRECTION OUTPUT ;
    USE SIGNAL ;
    PORT
      LAYER M4 ;
        RECT  0 50.352 0.084 50.376 ;
    END
  END tap_d[235]
  PIN tap_d[236]
    DIRECTION OUTPUT ;
    USE SIGNAL ;
    PORT
      LAYER M4 ;
        RECT  0 50.448 0.084 50.472 ;
    END
  END tap_d[236]
  PIN tap_d[237]
    DIRECTION OUTPUT ;
    USE SIGNAL ;
    PORT
      LAYER M4 ;
        RECT  0 50.544 0.084 50.568 ;
    END
  END tap_d[237]
  PIN tap_d[238]
    DIRECTION OUTPUT ;
    USE SIGNAL ;
    PORT
      LAYER M4 ;
        RECT  0 50.64 0.084 50.664 ;
    END
  END tap_d[238]
  PIN tap_d[239]
    DIRECTION OUTPUT ;
    USE SIGNAL ;
    PORT
      LAYER M4 ;
        RECT  0 50.736 0.084 50.76 ;
    END
  END tap_d[239]
  PIN tap_d[23]
    DIRECTION OUTPUT ;
    USE SIGNAL ;
    PORT
      LAYER M4 ;
        RECT  0 29.28 0.084 29.304 ;
    END
  END tap_d[23]
  PIN tap_d[240]
    DIRECTION OUTPUT ;
    USE SIGNAL ;
    PORT
      LAYER M4 ;
        RECT  0 50.832 0.084 50.856 ;
    END
  END tap_d[240]
  PIN tap_d[241]
    DIRECTION OUTPUT ;
    USE SIGNAL ;
    PORT
      LAYER M4 ;
        RECT  0 50.928 0.084 50.952 ;
    END
  END tap_d[241]
  PIN tap_d[242]
    DIRECTION OUTPUT ;
    USE SIGNAL ;
    PORT
      LAYER M4 ;
        RECT  0 51.024 0.084 51.048 ;
    END
  END tap_d[242]
  PIN tap_d[243]
    DIRECTION OUTPUT ;
    USE SIGNAL ;
    PORT
      LAYER M4 ;
        RECT  0 51.12 0.084 51.144 ;
    END
  END tap_d[243]
  PIN tap_d[244]
    DIRECTION OUTPUT ;
    USE SIGNAL ;
    PORT
      LAYER M4 ;
        RECT  0 51.216 0.084 51.24 ;
    END
  END tap_d[244]
  PIN tap_d[245]
    DIRECTION OUTPUT ;
    USE SIGNAL ;
    PORT
      LAYER M4 ;
        RECT  0 51.312 0.084 51.336 ;
    END
  END tap_d[245]
  PIN tap_d[246]
    DIRECTION OUTPUT ;
    USE SIGNAL ;
    PORT
      LAYER M4 ;
        RECT  0 51.408 0.084 51.432 ;
    END
  END tap_d[246]
  PIN tap_d[247]
    DIRECTION OUTPUT ;
    USE SIGNAL ;
    PORT
      LAYER M4 ;
        RECT  0 51.552 0.084 51.576 ;
    END
  END tap_d[247]
  PIN tap_d[248]
    DIRECTION OUTPUT ;
    USE SIGNAL ;
    PORT
      LAYER M4 ;
        RECT  0 51.648 0.084 51.672 ;
    END
  END tap_d[248]
  PIN tap_d[249]
    DIRECTION OUTPUT ;
    USE SIGNAL ;
    PORT
      LAYER M4 ;
        RECT  0 51.744 0.084 51.768 ;
    END
  END tap_d[249]
  PIN tap_d[24]
    DIRECTION OUTPUT ;
    USE SIGNAL ;
    PORT
      LAYER M4 ;
        RECT  0 29.376 0.084 29.4 ;
    END
  END tap_d[24]
  PIN tap_d[250]
    DIRECTION OUTPUT ;
    USE SIGNAL ;
    PORT
      LAYER M4 ;
        RECT  0 51.84 0.084 51.864 ;
    END
  END tap_d[250]
  PIN tap_d[251]
    DIRECTION OUTPUT ;
    USE SIGNAL ;
    PORT
      LAYER M4 ;
        RECT  0 51.936 0.084 51.96 ;
    END
  END tap_d[251]
  PIN tap_d[252]
    DIRECTION OUTPUT ;
    USE SIGNAL ;
    PORT
      LAYER M4 ;
        RECT  0 52.032 0.084 52.056 ;
    END
  END tap_d[252]
  PIN tap_d[253]
    DIRECTION OUTPUT ;
    USE SIGNAL ;
    PORT
      LAYER M4 ;
        RECT  0 52.128 0.084 52.152 ;
    END
  END tap_d[253]
  PIN tap_d[254]
    DIRECTION OUTPUT ;
    USE SIGNAL ;
    PORT
      LAYER M4 ;
        RECT  0 52.224 0.084 52.248 ;
    END
  END tap_d[254]
  PIN tap_d[255]
    DIRECTION OUTPUT ;
    USE SIGNAL ;
    PORT
      LAYER M4 ;
        RECT  0 52.32 0.084 52.344 ;
    END
  END tap_d[255]
  PIN tap_d[256]
    DIRECTION OUTPUT ;
    USE SIGNAL ;
    PORT
      LAYER M4 ;
        RECT  0 52.416 0.084 52.44 ;
    END
  END tap_d[256]
  PIN tap_d[257]
    DIRECTION OUTPUT ;
    USE SIGNAL ;
    PORT
      LAYER M4 ;
        RECT  0 52.512 0.084 52.536 ;
    END
  END tap_d[257]
  PIN tap_d[258]
    DIRECTION OUTPUT ;
    USE SIGNAL ;
    PORT
      LAYER M4 ;
        RECT  0 52.608 0.084 52.632 ;
    END
  END tap_d[258]
  PIN tap_d[259]
    DIRECTION OUTPUT ;
    USE SIGNAL ;
    PORT
      LAYER M4 ;
        RECT  0 52.704 0.084 52.728 ;
    END
  END tap_d[259]
  PIN tap_d[25]
    DIRECTION OUTPUT ;
    USE SIGNAL ;
    PORT
      LAYER M4 ;
        RECT  0 29.472 0.084 29.496 ;
    END
  END tap_d[25]
  PIN tap_d[260]
    DIRECTION OUTPUT ;
    USE SIGNAL ;
    PORT
      LAYER M4 ;
        RECT  0 52.8 0.084 52.824 ;
    END
  END tap_d[260]
  PIN tap_d[261]
    DIRECTION OUTPUT ;
    USE SIGNAL ;
    PORT
      LAYER M4 ;
        RECT  0 52.944 0.084 52.968 ;
    END
  END tap_d[261]
  PIN tap_d[262]
    DIRECTION OUTPUT ;
    USE SIGNAL ;
    PORT
      LAYER M4 ;
        RECT  0 53.04 0.084 53.064 ;
    END
  END tap_d[262]
  PIN tap_d[263]
    DIRECTION OUTPUT ;
    USE SIGNAL ;
    PORT
      LAYER M4 ;
        RECT  0 53.136 0.084 53.16 ;
    END
  END tap_d[263]
  PIN tap_d[264]
    DIRECTION OUTPUT ;
    USE SIGNAL ;
    PORT
      LAYER M4 ;
        RECT  0 53.232 0.084 53.256 ;
    END
  END tap_d[264]
  PIN tap_d[265]
    DIRECTION OUTPUT ;
    USE SIGNAL ;
    PORT
      LAYER M4 ;
        RECT  0 53.328 0.084 53.352 ;
    END
  END tap_d[265]
  PIN tap_d[266]
    DIRECTION OUTPUT ;
    USE SIGNAL ;
    PORT
      LAYER M4 ;
        RECT  0 53.424 0.084 53.448 ;
    END
  END tap_d[266]
  PIN tap_d[267]
    DIRECTION OUTPUT ;
    USE SIGNAL ;
    PORT
      LAYER M4 ;
        RECT  0 53.52 0.084 53.544 ;
    END
  END tap_d[267]
  PIN tap_d[268]
    DIRECTION OUTPUT ;
    USE SIGNAL ;
    PORT
      LAYER M4 ;
        RECT  0 53.616 0.084 53.64 ;
    END
  END tap_d[268]
  PIN tap_d[269]
    DIRECTION OUTPUT ;
    USE SIGNAL ;
    PORT
      LAYER M4 ;
        RECT  0 53.712 0.084 53.736 ;
    END
  END tap_d[269]
  PIN tap_d[26]
    DIRECTION OUTPUT ;
    USE SIGNAL ;
    PORT
      LAYER M4 ;
        RECT  0 29.568 0.084 29.592 ;
    END
  END tap_d[26]
  PIN tap_d[270]
    DIRECTION OUTPUT ;
    USE SIGNAL ;
    PORT
      LAYER M4 ;
        RECT  0 53.808 0.084 53.832 ;
    END
  END tap_d[270]
  PIN tap_d[271]
    DIRECTION OUTPUT ;
    USE SIGNAL ;
    PORT
      LAYER M4 ;
        RECT  0 53.904 0.084 53.928 ;
    END
  END tap_d[271]
  PIN tap_d[272]
    DIRECTION OUTPUT ;
    USE SIGNAL ;
    PORT
      LAYER M4 ;
        RECT  0 54 0.084 54.024 ;
    END
  END tap_d[272]
  PIN tap_d[273]
    DIRECTION OUTPUT ;
    USE SIGNAL ;
    PORT
      LAYER M4 ;
        RECT  0 54.096 0.084 54.12 ;
    END
  END tap_d[273]
  PIN tap_d[274]
    DIRECTION OUTPUT ;
    USE SIGNAL ;
    PORT
      LAYER M4 ;
        RECT  0 54.192 0.084 54.216 ;
    END
  END tap_d[274]
  PIN tap_d[275]
    DIRECTION OUTPUT ;
    USE SIGNAL ;
    PORT
      LAYER M4 ;
        RECT  0 54.336 0.084 54.36 ;
    END
  END tap_d[275]
  PIN tap_d[276]
    DIRECTION OUTPUT ;
    USE SIGNAL ;
    PORT
      LAYER M4 ;
        RECT  0 54.432 0.084 54.456 ;
    END
  END tap_d[276]
  PIN tap_d[277]
    DIRECTION OUTPUT ;
    USE SIGNAL ;
    PORT
      LAYER M4 ;
        RECT  0 54.528 0.084 54.552 ;
    END
  END tap_d[277]
  PIN tap_d[278]
    DIRECTION OUTPUT ;
    USE SIGNAL ;
    PORT
      LAYER M4 ;
        RECT  0 54.624 0.084 54.648 ;
    END
  END tap_d[278]
  PIN tap_d[279]
    DIRECTION OUTPUT ;
    USE SIGNAL ;
    PORT
      LAYER M4 ;
        RECT  0 54.72 0.084 54.744 ;
    END
  END tap_d[279]
  PIN tap_d[27]
    DIRECTION OUTPUT ;
    USE SIGNAL ;
    PORT
      LAYER M4 ;
        RECT  0 29.664 0.084 29.688 ;
    END
  END tap_d[27]
  PIN tap_d[280]
    DIRECTION OUTPUT ;
    USE SIGNAL ;
    PORT
      LAYER M4 ;
        RECT  0 54.816 0.084 54.84 ;
    END
  END tap_d[280]
  PIN tap_d[281]
    DIRECTION OUTPUT ;
    USE SIGNAL ;
    PORT
      LAYER M4 ;
        RECT  0 54.912 0.084 54.936 ;
    END
  END tap_d[281]
  PIN tap_d[282]
    DIRECTION OUTPUT ;
    USE SIGNAL ;
    PORT
      LAYER M4 ;
        RECT  0 55.008 0.084 55.032 ;
    END
  END tap_d[282]
  PIN tap_d[283]
    DIRECTION OUTPUT ;
    USE SIGNAL ;
    PORT
      LAYER M4 ;
        RECT  0 55.104 0.084 55.128 ;
    END
  END tap_d[283]
  PIN tap_d[284]
    DIRECTION OUTPUT ;
    USE SIGNAL ;
    PORT
      LAYER M4 ;
        RECT  0 55.2 0.084 55.224 ;
    END
  END tap_d[284]
  PIN tap_d[285]
    DIRECTION OUTPUT ;
    USE SIGNAL ;
    PORT
      LAYER M4 ;
        RECT  0 55.296 0.084 55.32 ;
    END
  END tap_d[285]
  PIN tap_d[286]
    DIRECTION OUTPUT ;
    USE SIGNAL ;
    PORT
      LAYER M4 ;
        RECT  0 55.392 0.084 55.416 ;
    END
  END tap_d[286]
  PIN tap_d[287]
    DIRECTION OUTPUT ;
    USE SIGNAL ;
    PORT
      LAYER M4 ;
        RECT  0 55.488 0.084 55.512 ;
    END
  END tap_d[287]
  PIN tap_d[288]
    DIRECTION OUTPUT ;
    USE SIGNAL ;
    PORT
      LAYER M4 ;
        RECT  0 55.584 0.084 55.608 ;
    END
  END tap_d[288]
  PIN tap_d[289]
    DIRECTION OUTPUT ;
    USE SIGNAL ;
    PORT
      LAYER M4 ;
        RECT  0 55.728 0.084 55.752 ;
    END
  END tap_d[289]
  PIN tap_d[28]
    DIRECTION OUTPUT ;
    USE SIGNAL ;
    PORT
      LAYER M4 ;
        RECT  0 29.76 0.084 29.784 ;
    END
  END tap_d[28]
  PIN tap_d[290]
    DIRECTION OUTPUT ;
    USE SIGNAL ;
    PORT
      LAYER M4 ;
        RECT  0 55.824 0.084 55.848 ;
    END
  END tap_d[290]
  PIN tap_d[291]
    DIRECTION OUTPUT ;
    USE SIGNAL ;
    PORT
      LAYER M4 ;
        RECT  0 55.92 0.084 55.944 ;
    END
  END tap_d[291]
  PIN tap_d[292]
    DIRECTION OUTPUT ;
    USE SIGNAL ;
    PORT
      LAYER M4 ;
        RECT  0 56.016 0.084 56.04 ;
    END
  END tap_d[292]
  PIN tap_d[293]
    DIRECTION OUTPUT ;
    USE SIGNAL ;
    PORT
      LAYER M4 ;
        RECT  0 56.112 0.084 56.136 ;
    END
  END tap_d[293]
  PIN tap_d[294]
    DIRECTION OUTPUT ;
    USE SIGNAL ;
    PORT
      LAYER M4 ;
        RECT  0 56.208 0.084 56.232 ;
    END
  END tap_d[294]
  PIN tap_d[295]
    DIRECTION OUTPUT ;
    USE SIGNAL ;
    PORT
      LAYER M4 ;
        RECT  0 56.304 0.084 56.328 ;
    END
  END tap_d[295]
  PIN tap_d[296]
    DIRECTION OUTPUT ;
    USE SIGNAL ;
    PORT
      LAYER M4 ;
        RECT  0 56.4 0.084 56.424 ;
    END
  END tap_d[296]
  PIN tap_d[297]
    DIRECTION OUTPUT ;
    USE SIGNAL ;
    PORT
      LAYER M4 ;
        RECT  0 56.496 0.084 56.52 ;
    END
  END tap_d[297]
  PIN tap_d[298]
    DIRECTION OUTPUT ;
    USE SIGNAL ;
    PORT
      LAYER M4 ;
        RECT  0 56.592 0.084 56.616 ;
    END
  END tap_d[298]
  PIN tap_d[299]
    DIRECTION OUTPUT ;
    USE SIGNAL ;
    PORT
      LAYER M4 ;
        RECT  0 56.688 0.084 56.712 ;
    END
  END tap_d[299]
  PIN tap_d[29]
    DIRECTION OUTPUT ;
    USE SIGNAL ;
    PORT
      LAYER M4 ;
        RECT  0 29.856 0.084 29.88 ;
    END
  END tap_d[29]
  PIN tap_d[2]
    DIRECTION OUTPUT ;
    USE SIGNAL ;
    PORT
      LAYER M4 ;
        RECT  0 27.168 0.084 27.192 ;
    END
  END tap_d[2]
  PIN tap_d[300]
    DIRECTION OUTPUT ;
    USE SIGNAL ;
    PORT
      LAYER M4 ;
        RECT  0 56.784 0.084 56.808 ;
    END
  END tap_d[300]
  PIN tap_d[301]
    DIRECTION OUTPUT ;
    USE SIGNAL ;
    PORT
      LAYER M4 ;
        RECT  0 56.88 0.084 56.904 ;
    END
  END tap_d[301]
  PIN tap_d[302]
    DIRECTION OUTPUT ;
    USE SIGNAL ;
    PORT
      LAYER M4 ;
        RECT  0 56.976 0.084 57 ;
    END
  END tap_d[302]
  PIN tap_d[303]
    DIRECTION OUTPUT ;
    USE SIGNAL ;
    PORT
      LAYER M4 ;
        RECT  0 57.12 0.084 57.144 ;
    END
  END tap_d[303]
  PIN tap_d[304]
    DIRECTION OUTPUT ;
    USE SIGNAL ;
    PORT
      LAYER M4 ;
        RECT  0 57.216 0.084 57.24 ;
    END
  END tap_d[304]
  PIN tap_d[305]
    DIRECTION OUTPUT ;
    USE SIGNAL ;
    PORT
      LAYER M4 ;
        RECT  0 57.312 0.084 57.336 ;
    END
  END tap_d[305]
  PIN tap_d[306]
    DIRECTION OUTPUT ;
    USE SIGNAL ;
    PORT
      LAYER M4 ;
        RECT  0 57.408 0.084 57.432 ;
    END
  END tap_d[306]
  PIN tap_d[307]
    DIRECTION OUTPUT ;
    USE SIGNAL ;
    PORT
      LAYER M4 ;
        RECT  0 57.504 0.084 57.528 ;
    END
  END tap_d[307]
  PIN tap_d[308]
    DIRECTION OUTPUT ;
    USE SIGNAL ;
    PORT
      LAYER M4 ;
        RECT  0 57.6 0.084 57.624 ;
    END
  END tap_d[308]
  PIN tap_d[309]
    DIRECTION OUTPUT ;
    USE SIGNAL ;
    PORT
      LAYER M4 ;
        RECT  0 57.696 0.084 57.72 ;
    END
  END tap_d[309]
  PIN tap_d[30]
    DIRECTION OUTPUT ;
    USE SIGNAL ;
    PORT
      LAYER M4 ;
        RECT  0 29.952 0.084 29.976 ;
    END
  END tap_d[30]
  PIN tap_d[310]
    DIRECTION OUTPUT ;
    USE SIGNAL ;
    PORT
      LAYER M4 ;
        RECT  0 57.792 0.084 57.816 ;
    END
  END tap_d[310]
  PIN tap_d[311]
    DIRECTION OUTPUT ;
    USE SIGNAL ;
    PORT
      LAYER M4 ;
        RECT  0 57.888 0.084 57.912 ;
    END
  END tap_d[311]
  PIN tap_d[312]
    DIRECTION OUTPUT ;
    USE SIGNAL ;
    PORT
      LAYER M4 ;
        RECT  0 57.984 0.084 58.008 ;
    END
  END tap_d[312]
  PIN tap_d[313]
    DIRECTION OUTPUT ;
    USE SIGNAL ;
    PORT
      LAYER M4 ;
        RECT  0 58.08 0.084 58.104 ;
    END
  END tap_d[313]
  PIN tap_d[314]
    DIRECTION OUTPUT ;
    USE SIGNAL ;
    PORT
      LAYER M4 ;
        RECT  0 58.176 0.084 58.2 ;
    END
  END tap_d[314]
  PIN tap_d[315]
    DIRECTION OUTPUT ;
    USE SIGNAL ;
    PORT
      LAYER M4 ;
        RECT  0 58.272 0.084 58.296 ;
    END
  END tap_d[315]
  PIN tap_d[316]
    DIRECTION OUTPUT ;
    USE SIGNAL ;
    PORT
      LAYER M4 ;
        RECT  0 58.368 0.084 58.392 ;
    END
  END tap_d[316]
  PIN tap_d[317]
    DIRECTION OUTPUT ;
    USE SIGNAL ;
    PORT
      LAYER M4 ;
        RECT  0 58.512 0.084 58.536 ;
    END
  END tap_d[317]
  PIN tap_d[318]
    DIRECTION OUTPUT ;
    USE SIGNAL ;
    PORT
      LAYER M4 ;
        RECT  0 58.608 0.084 58.632 ;
    END
  END tap_d[318]
  PIN tap_d[319]
    DIRECTION OUTPUT ;
    USE SIGNAL ;
    PORT
      LAYER M4 ;
        RECT  0 58.704 0.084 58.728 ;
    END
  END tap_d[319]
  PIN tap_d[31]
    DIRECTION OUTPUT ;
    USE SIGNAL ;
    PORT
      LAYER M4 ;
        RECT  0 30.048 0.084 30.072 ;
    END
  END tap_d[31]
  PIN tap_d[320]
    DIRECTION OUTPUT ;
    USE SIGNAL ;
    PORT
      LAYER M4 ;
        RECT  0 58.8 0.084 58.824 ;
    END
  END tap_d[320]
  PIN tap_d[321]
    DIRECTION OUTPUT ;
    USE SIGNAL ;
    PORT
      LAYER M4 ;
        RECT  0 58.896 0.084 58.92 ;
    END
  END tap_d[321]
  PIN tap_d[322]
    DIRECTION OUTPUT ;
    USE SIGNAL ;
    PORT
      LAYER M4 ;
        RECT  0 58.992 0.084 59.016 ;
    END
  END tap_d[322]
  PIN tap_d[323]
    DIRECTION OUTPUT ;
    USE SIGNAL ;
    PORT
      LAYER M4 ;
        RECT  0 59.088 0.084 59.112 ;
    END
  END tap_d[323]
  PIN tap_d[324]
    DIRECTION OUTPUT ;
    USE SIGNAL ;
    PORT
      LAYER M4 ;
        RECT  0 59.184 0.084 59.208 ;
    END
  END tap_d[324]
  PIN tap_d[325]
    DIRECTION OUTPUT ;
    USE SIGNAL ;
    PORT
      LAYER M4 ;
        RECT  0 59.28 0.084 59.304 ;
    END
  END tap_d[325]
  PIN tap_d[326]
    DIRECTION OUTPUT ;
    USE SIGNAL ;
    PORT
      LAYER M4 ;
        RECT  0 59.376 0.084 59.4 ;
    END
  END tap_d[326]
  PIN tap_d[327]
    DIRECTION OUTPUT ;
    USE SIGNAL ;
    PORT
      LAYER M4 ;
        RECT  0 59.472 0.084 59.496 ;
    END
  END tap_d[327]
  PIN tap_d[328]
    DIRECTION OUTPUT ;
    USE SIGNAL ;
    PORT
      LAYER M4 ;
        RECT  0 59.568 0.084 59.592 ;
    END
  END tap_d[328]
  PIN tap_d[329]
    DIRECTION OUTPUT ;
    USE SIGNAL ;
    PORT
      LAYER M4 ;
        RECT  0 59.664 0.084 59.688 ;
    END
  END tap_d[329]
  PIN tap_d[32]
    DIRECTION OUTPUT ;
    USE SIGNAL ;
    PORT
      LAYER M4 ;
        RECT  0 30.144 0.084 30.168 ;
    END
  END tap_d[32]
  PIN tap_d[330]
    DIRECTION OUTPUT ;
    USE SIGNAL ;
    PORT
      LAYER M4 ;
        RECT  0 59.76 0.084 59.784 ;
    END
  END tap_d[330]
  PIN tap_d[331]
    DIRECTION OUTPUT ;
    USE SIGNAL ;
    PORT
      LAYER M4 ;
        RECT  0 59.904 0.084 59.928 ;
    END
  END tap_d[331]
  PIN tap_d[332]
    DIRECTION OUTPUT ;
    USE SIGNAL ;
    PORT
      LAYER M4 ;
        RECT  0 60 0.084 60.024 ;
    END
  END tap_d[332]
  PIN tap_d[333]
    DIRECTION OUTPUT ;
    USE SIGNAL ;
    PORT
      LAYER M4 ;
        RECT  0 60.096 0.084 60.12 ;
    END
  END tap_d[333]
  PIN tap_d[334]
    DIRECTION OUTPUT ;
    USE SIGNAL ;
    PORT
      LAYER M4 ;
        RECT  0 60.192 0.084 60.216 ;
    END
  END tap_d[334]
  PIN tap_d[335]
    DIRECTION OUTPUT ;
    USE SIGNAL ;
    PORT
      LAYER M4 ;
        RECT  0 60.288 0.084 60.312 ;
    END
  END tap_d[335]
  PIN tap_d[336]
    DIRECTION OUTPUT ;
    USE SIGNAL ;
    PORT
      LAYER M4 ;
        RECT  0 60.384 0.084 60.408 ;
    END
  END tap_d[336]
  PIN tap_d[337]
    DIRECTION OUTPUT ;
    USE SIGNAL ;
    PORT
      LAYER M4 ;
        RECT  0 60.48 0.084 60.504 ;
    END
  END tap_d[337]
  PIN tap_d[338]
    DIRECTION OUTPUT ;
    USE SIGNAL ;
    PORT
      LAYER M4 ;
        RECT  0 60.576 0.084 60.6 ;
    END
  END tap_d[338]
  PIN tap_d[339]
    DIRECTION OUTPUT ;
    USE SIGNAL ;
    PORT
      LAYER M4 ;
        RECT  0 60.672 0.084 60.696 ;
    END
  END tap_d[339]
  PIN tap_d[33]
    DIRECTION OUTPUT ;
    USE SIGNAL ;
    PORT
      LAYER M4 ;
        RECT  0 30.24 0.084 30.264 ;
    END
  END tap_d[33]
  PIN tap_d[340]
    DIRECTION OUTPUT ;
    USE SIGNAL ;
    PORT
      LAYER M4 ;
        RECT  0 60.768 0.084 60.792 ;
    END
  END tap_d[340]
  PIN tap_d[341]
    DIRECTION OUTPUT ;
    USE SIGNAL ;
    PORT
      LAYER M4 ;
        RECT  0 60.864 0.084 60.888 ;
    END
  END tap_d[341]
  PIN tap_d[342]
    DIRECTION OUTPUT ;
    USE SIGNAL ;
    PORT
      LAYER M4 ;
        RECT  0 60.96 0.084 60.984 ;
    END
  END tap_d[342]
  PIN tap_d[343]
    DIRECTION OUTPUT ;
    USE SIGNAL ;
    PORT
      LAYER M4 ;
        RECT  0 61.056 0.084 61.08 ;
    END
  END tap_d[343]
  PIN tap_d[344]
    DIRECTION OUTPUT ;
    USE SIGNAL ;
    PORT
      LAYER M4 ;
        RECT  0 61.152 0.084 61.176 ;
    END
  END tap_d[344]
  PIN tap_d[345]
    DIRECTION OUTPUT ;
    USE SIGNAL ;
    PORT
      LAYER M4 ;
        RECT  0 61.248 0.084 61.272 ;
    END
  END tap_d[345]
  PIN tap_d[346]
    DIRECTION OUTPUT ;
    USE SIGNAL ;
    PORT
      LAYER M4 ;
        RECT  0 61.392 0.084 61.416 ;
    END
  END tap_d[346]
  PIN tap_d[347]
    DIRECTION OUTPUT ;
    USE SIGNAL ;
    PORT
      LAYER M4 ;
        RECT  0 61.488 0.084 61.512 ;
    END
  END tap_d[347]
  PIN tap_d[348]
    DIRECTION OUTPUT ;
    USE SIGNAL ;
    PORT
      LAYER M4 ;
        RECT  0 61.584 0.084 61.608 ;
    END
  END tap_d[348]
  PIN tap_d[349]
    DIRECTION OUTPUT ;
    USE SIGNAL ;
    PORT
      LAYER M4 ;
        RECT  0 61.68 0.084 61.704 ;
    END
  END tap_d[349]
  PIN tap_d[34]
    DIRECTION OUTPUT ;
    USE SIGNAL ;
    PORT
      LAYER M4 ;
        RECT  0 30.336 0.084 30.36 ;
    END
  END tap_d[34]
  PIN tap_d[350]
    DIRECTION OUTPUT ;
    USE SIGNAL ;
    PORT
      LAYER M4 ;
        RECT  0 61.776 0.084 61.8 ;
    END
  END tap_d[350]
  PIN tap_d[351]
    DIRECTION OUTPUT ;
    USE SIGNAL ;
    PORT
      LAYER M4 ;
        RECT  0 61.872 0.084 61.896 ;
    END
  END tap_d[351]
  PIN tap_d[352]
    DIRECTION OUTPUT ;
    USE SIGNAL ;
    PORT
      LAYER M4 ;
        RECT  0 61.968 0.084 61.992 ;
    END
  END tap_d[352]
  PIN tap_d[353]
    DIRECTION OUTPUT ;
    USE SIGNAL ;
    PORT
      LAYER M4 ;
        RECT  0 62.064 0.084 62.088 ;
    END
  END tap_d[353]
  PIN tap_d[354]
    DIRECTION OUTPUT ;
    USE SIGNAL ;
    PORT
      LAYER M4 ;
        RECT  0 62.16 0.084 62.184 ;
    END
  END tap_d[354]
  PIN tap_d[355]
    DIRECTION OUTPUT ;
    USE SIGNAL ;
    PORT
      LAYER M4 ;
        RECT  0 62.256 0.084 62.28 ;
    END
  END tap_d[355]
  PIN tap_d[356]
    DIRECTION OUTPUT ;
    USE SIGNAL ;
    PORT
      LAYER M4 ;
        RECT  0 62.352 0.084 62.376 ;
    END
  END tap_d[356]
  PIN tap_d[357]
    DIRECTION OUTPUT ;
    USE SIGNAL ;
    PORT
      LAYER M4 ;
        RECT  0 62.448 0.084 62.472 ;
    END
  END tap_d[357]
  PIN tap_d[358]
    DIRECTION OUTPUT ;
    USE SIGNAL ;
    PORT
      LAYER M4 ;
        RECT  0 62.544 0.084 62.568 ;
    END
  END tap_d[358]
  PIN tap_d[359]
    DIRECTION OUTPUT ;
    USE SIGNAL ;
    PORT
      LAYER M4 ;
        RECT  0 62.64 0.084 62.664 ;
    END
  END tap_d[359]
  PIN tap_d[35]
    DIRECTION OUTPUT ;
    USE SIGNAL ;
    PORT
      LAYER M4 ;
        RECT  0 30.48 0.084 30.504 ;
    END
  END tap_d[35]
  PIN tap_d[360]
    DIRECTION OUTPUT ;
    USE SIGNAL ;
    PORT
      LAYER M4 ;
        RECT  0 62.784 0.084 62.808 ;
    END
  END tap_d[360]
  PIN tap_d[361]
    DIRECTION OUTPUT ;
    USE SIGNAL ;
    PORT
      LAYER M4 ;
        RECT  0 62.88 0.084 62.904 ;
    END
  END tap_d[361]
  PIN tap_d[362]
    DIRECTION OUTPUT ;
    USE SIGNAL ;
    PORT
      LAYER M4 ;
        RECT  0 62.976 0.084 63 ;
    END
  END tap_d[362]
  PIN tap_d[363]
    DIRECTION OUTPUT ;
    USE SIGNAL ;
    PORT
      LAYER M4 ;
        RECT  0 63.072 0.084 63.096 ;
    END
  END tap_d[363]
  PIN tap_d[364]
    DIRECTION OUTPUT ;
    USE SIGNAL ;
    PORT
      LAYER M4 ;
        RECT  0 63.168 0.084 63.192 ;
    END
  END tap_d[364]
  PIN tap_d[365]
    DIRECTION OUTPUT ;
    USE SIGNAL ;
    PORT
      LAYER M4 ;
        RECT  0 63.264 0.084 63.288 ;
    END
  END tap_d[365]
  PIN tap_d[366]
    DIRECTION OUTPUT ;
    USE SIGNAL ;
    PORT
      LAYER M4 ;
        RECT  0 63.36 0.084 63.384 ;
    END
  END tap_d[366]
  PIN tap_d[367]
    DIRECTION OUTPUT ;
    USE SIGNAL ;
    PORT
      LAYER M4 ;
        RECT  0 63.456 0.084 63.48 ;
    END
  END tap_d[367]
  PIN tap_d[368]
    DIRECTION OUTPUT ;
    USE SIGNAL ;
    PORT
      LAYER M4 ;
        RECT  0 63.552 0.084 63.576 ;
    END
  END tap_d[368]
  PIN tap_d[369]
    DIRECTION OUTPUT ;
    USE SIGNAL ;
    PORT
      LAYER M4 ;
        RECT  0 63.648 0.084 63.672 ;
    END
  END tap_d[369]
  PIN tap_d[36]
    DIRECTION OUTPUT ;
    USE SIGNAL ;
    PORT
      LAYER M4 ;
        RECT  0 30.576 0.084 30.6 ;
    END
  END tap_d[36]
  PIN tap_d[370]
    DIRECTION OUTPUT ;
    USE SIGNAL ;
    PORT
      LAYER M4 ;
        RECT  0 63.744 0.084 63.768 ;
    END
  END tap_d[370]
  PIN tap_d[371]
    DIRECTION OUTPUT ;
    USE SIGNAL ;
    PORT
      LAYER M4 ;
        RECT  0 63.84 0.084 63.864 ;
    END
  END tap_d[371]
  PIN tap_d[372]
    DIRECTION OUTPUT ;
    USE SIGNAL ;
    PORT
      LAYER M4 ;
        RECT  0 63.936 0.084 63.96 ;
    END
  END tap_d[372]
  PIN tap_d[373]
    DIRECTION OUTPUT ;
    USE SIGNAL ;
    PORT
      LAYER M4 ;
        RECT  0 64.032 0.084 64.056 ;
    END
  END tap_d[373]
  PIN tap_d[374]
    DIRECTION OUTPUT ;
    USE SIGNAL ;
    PORT
      LAYER M4 ;
        RECT  0 64.176 0.084 64.2 ;
    END
  END tap_d[374]
  PIN tap_d[375]
    DIRECTION OUTPUT ;
    USE SIGNAL ;
    PORT
      LAYER M4 ;
        RECT  0 64.272 0.084 64.296 ;
    END
  END tap_d[375]
  PIN tap_d[376]
    DIRECTION OUTPUT ;
    USE SIGNAL ;
    PORT
      LAYER M4 ;
        RECT  0 64.368 0.084 64.392 ;
    END
  END tap_d[376]
  PIN tap_d[377]
    DIRECTION OUTPUT ;
    USE SIGNAL ;
    PORT
      LAYER M4 ;
        RECT  0 64.464 0.084 64.488 ;
    END
  END tap_d[377]
  PIN tap_d[378]
    DIRECTION OUTPUT ;
    USE SIGNAL ;
    PORT
      LAYER M4 ;
        RECT  0 64.56 0.084 64.584 ;
    END
  END tap_d[378]
  PIN tap_d[379]
    DIRECTION OUTPUT ;
    USE SIGNAL ;
    PORT
      LAYER M4 ;
        RECT  0 64.656 0.084 64.68 ;
    END
  END tap_d[379]
  PIN tap_d[37]
    DIRECTION OUTPUT ;
    USE SIGNAL ;
    PORT
      LAYER M4 ;
        RECT  0 30.672 0.084 30.696 ;
    END
  END tap_d[37]
  PIN tap_d[380]
    DIRECTION OUTPUT ;
    USE SIGNAL ;
    PORT
      LAYER M4 ;
        RECT  0 64.752 0.084 64.776 ;
    END
  END tap_d[380]
  PIN tap_d[381]
    DIRECTION OUTPUT ;
    USE SIGNAL ;
    PORT
      LAYER M4 ;
        RECT  0 64.848 0.084 64.872 ;
    END
  END tap_d[381]
  PIN tap_d[382]
    DIRECTION OUTPUT ;
    USE SIGNAL ;
    PORT
      LAYER M4 ;
        RECT  0 64.944 0.084 64.968 ;
    END
  END tap_d[382]
  PIN tap_d[383]
    DIRECTION OUTPUT ;
    USE SIGNAL ;
    PORT
      LAYER M4 ;
        RECT  0 65.04 0.084 65.064 ;
    END
  END tap_d[383]
  PIN tap_d[384]
    DIRECTION OUTPUT ;
    USE SIGNAL ;
    PORT
      LAYER M4 ;
        RECT  0 65.136 0.084 65.16 ;
    END
  END tap_d[384]
  PIN tap_d[385]
    DIRECTION OUTPUT ;
    USE SIGNAL ;
    PORT
      LAYER M4 ;
        RECT  0 65.232 0.084 65.256 ;
    END
  END tap_d[385]
  PIN tap_d[386]
    DIRECTION OUTPUT ;
    USE SIGNAL ;
    PORT
      LAYER M4 ;
        RECT  0 65.328 0.084 65.352 ;
    END
  END tap_d[386]
  PIN tap_d[387]
    DIRECTION OUTPUT ;
    USE SIGNAL ;
    PORT
      LAYER M4 ;
        RECT  0 65.424 0.084 65.448 ;
    END
  END tap_d[387]
  PIN tap_d[388]
    DIRECTION OUTPUT ;
    USE SIGNAL ;
    PORT
      LAYER M4 ;
        RECT  0 65.568 0.084 65.592 ;
    END
  END tap_d[388]
  PIN tap_d[389]
    DIRECTION OUTPUT ;
    USE SIGNAL ;
    PORT
      LAYER M4 ;
        RECT  0 65.664 0.084 65.688 ;
    END
  END tap_d[389]
  PIN tap_d[38]
    DIRECTION OUTPUT ;
    USE SIGNAL ;
    PORT
      LAYER M4 ;
        RECT  0 30.768 0.084 30.792 ;
    END
  END tap_d[38]
  PIN tap_d[390]
    DIRECTION OUTPUT ;
    USE SIGNAL ;
    PORT
      LAYER M4 ;
        RECT  0 65.76 0.084 65.784 ;
    END
  END tap_d[390]
  PIN tap_d[391]
    DIRECTION OUTPUT ;
    USE SIGNAL ;
    PORT
      LAYER M4 ;
        RECT  0 65.856 0.084 65.88 ;
    END
  END tap_d[391]
  PIN tap_d[392]
    DIRECTION OUTPUT ;
    USE SIGNAL ;
    PORT
      LAYER M4 ;
        RECT  0 65.952 0.084 65.976 ;
    END
  END tap_d[392]
  PIN tap_d[393]
    DIRECTION OUTPUT ;
    USE SIGNAL ;
    PORT
      LAYER M4 ;
        RECT  0 66.048 0.084 66.072 ;
    END
  END tap_d[393]
  PIN tap_d[394]
    DIRECTION OUTPUT ;
    USE SIGNAL ;
    PORT
      LAYER M4 ;
        RECT  0 66.144 0.084 66.168 ;
    END
  END tap_d[394]
  PIN tap_d[395]
    DIRECTION OUTPUT ;
    USE SIGNAL ;
    PORT
      LAYER M4 ;
        RECT  0 66.24 0.084 66.264 ;
    END
  END tap_d[395]
  PIN tap_d[396]
    DIRECTION OUTPUT ;
    USE SIGNAL ;
    PORT
      LAYER M4 ;
        RECT  0 66.336 0.084 66.36 ;
    END
  END tap_d[396]
  PIN tap_d[397]
    DIRECTION OUTPUT ;
    USE SIGNAL ;
    PORT
      LAYER M4 ;
        RECT  0 66.432 0.084 66.456 ;
    END
  END tap_d[397]
  PIN tap_d[398]
    DIRECTION OUTPUT ;
    USE SIGNAL ;
    PORT
      LAYER M4 ;
        RECT  0 66.528 0.084 66.552 ;
    END
  END tap_d[398]
  PIN tap_d[399]
    DIRECTION OUTPUT ;
    USE SIGNAL ;
    PORT
      LAYER M4 ;
        RECT  0 66.624 0.084 66.648 ;
    END
  END tap_d[399]
  PIN tap_d[39]
    DIRECTION OUTPUT ;
    USE SIGNAL ;
    PORT
      LAYER M4 ;
        RECT  0 30.864 0.084 30.888 ;
    END
  END tap_d[39]
  PIN tap_d[3]
    DIRECTION OUTPUT ;
    USE SIGNAL ;
    PORT
      LAYER M4 ;
        RECT  0 27.264 0.084 27.288 ;
    END
  END tap_d[3]
  PIN tap_d[400]
    DIRECTION OUTPUT ;
    USE SIGNAL ;
    PORT
      LAYER M4 ;
        RECT  0 66.72 0.084 66.744 ;
    END
  END tap_d[400]
  PIN tap_d[401]
    DIRECTION OUTPUT ;
    USE SIGNAL ;
    PORT
      LAYER M4 ;
        RECT  0 66.816 0.084 66.84 ;
    END
  END tap_d[401]
  PIN tap_d[402]
    DIRECTION OUTPUT ;
    USE SIGNAL ;
    PORT
      LAYER M4 ;
        RECT  0 66.96 0.084 66.984 ;
    END
  END tap_d[402]
  PIN tap_d[403]
    DIRECTION OUTPUT ;
    USE SIGNAL ;
    PORT
      LAYER M4 ;
        RECT  0 67.056 0.084 67.08 ;
    END
  END tap_d[403]
  PIN tap_d[404]
    DIRECTION OUTPUT ;
    USE SIGNAL ;
    PORT
      LAYER M4 ;
        RECT  0 67.152 0.084 67.176 ;
    END
  END tap_d[404]
  PIN tap_d[405]
    DIRECTION OUTPUT ;
    USE SIGNAL ;
    PORT
      LAYER M4 ;
        RECT  0 67.248 0.084 67.272 ;
    END
  END tap_d[405]
  PIN tap_d[406]
    DIRECTION OUTPUT ;
    USE SIGNAL ;
    PORT
      LAYER M4 ;
        RECT  0 67.344 0.084 67.368 ;
    END
  END tap_d[406]
  PIN tap_d[407]
    DIRECTION OUTPUT ;
    USE SIGNAL ;
    PORT
      LAYER M4 ;
        RECT  0 67.44 0.084 67.464 ;
    END
  END tap_d[407]
  PIN tap_d[408]
    DIRECTION OUTPUT ;
    USE SIGNAL ;
    PORT
      LAYER M4 ;
        RECT  0 67.536 0.084 67.56 ;
    END
  END tap_d[408]
  PIN tap_d[409]
    DIRECTION OUTPUT ;
    USE SIGNAL ;
    PORT
      LAYER M4 ;
        RECT  0 67.632 0.084 67.656 ;
    END
  END tap_d[409]
  PIN tap_d[40]
    DIRECTION OUTPUT ;
    USE SIGNAL ;
    PORT
      LAYER M4 ;
        RECT  0 30.96 0.084 30.984 ;
    END
  END tap_d[40]
  PIN tap_d[410]
    DIRECTION OUTPUT ;
    USE SIGNAL ;
    PORT
      LAYER M4 ;
        RECT  0 67.728 0.084 67.752 ;
    END
  END tap_d[410]
  PIN tap_d[411]
    DIRECTION OUTPUT ;
    USE SIGNAL ;
    PORT
      LAYER M4 ;
        RECT  0 67.824 0.084 67.848 ;
    END
  END tap_d[411]
  PIN tap_d[412]
    DIRECTION OUTPUT ;
    USE SIGNAL ;
    PORT
      LAYER M4 ;
        RECT  0 67.92 0.084 67.944 ;
    END
  END tap_d[412]
  PIN tap_d[413]
    DIRECTION OUTPUT ;
    USE SIGNAL ;
    PORT
      LAYER M4 ;
        RECT  0 68.016 0.084 68.04 ;
    END
  END tap_d[413]
  PIN tap_d[414]
    DIRECTION OUTPUT ;
    USE SIGNAL ;
    PORT
      LAYER M4 ;
        RECT  0 68.112 0.084 68.136 ;
    END
  END tap_d[414]
  PIN tap_d[415]
    DIRECTION OUTPUT ;
    USE SIGNAL ;
    PORT
      LAYER M4 ;
        RECT  0 68.208 0.084 68.232 ;
    END
  END tap_d[415]
  PIN tap_d[416]
    DIRECTION OUTPUT ;
    USE SIGNAL ;
    PORT
      LAYER M4 ;
        RECT  0 68.352 0.084 68.376 ;
    END
  END tap_d[416]
  PIN tap_d[417]
    DIRECTION OUTPUT ;
    USE SIGNAL ;
    PORT
      LAYER M4 ;
        RECT  0 68.448 0.084 68.472 ;
    END
  END tap_d[417]
  PIN tap_d[418]
    DIRECTION OUTPUT ;
    USE SIGNAL ;
    PORT
      LAYER M4 ;
        RECT  0 68.544 0.084 68.568 ;
    END
  END tap_d[418]
  PIN tap_d[419]
    DIRECTION OUTPUT ;
    USE SIGNAL ;
    PORT
      LAYER M4 ;
        RECT  0 68.64 0.084 68.664 ;
    END
  END tap_d[419]
  PIN tap_d[41]
    DIRECTION OUTPUT ;
    USE SIGNAL ;
    PORT
      LAYER M4 ;
        RECT  0 31.056 0.084 31.08 ;
    END
  END tap_d[41]
  PIN tap_d[420]
    DIRECTION OUTPUT ;
    USE SIGNAL ;
    PORT
      LAYER M4 ;
        RECT  0 68.736 0.084 68.76 ;
    END
  END tap_d[420]
  PIN tap_d[421]
    DIRECTION OUTPUT ;
    USE SIGNAL ;
    PORT
      LAYER M4 ;
        RECT  0 68.832 0.084 68.856 ;
    END
  END tap_d[421]
  PIN tap_d[422]
    DIRECTION OUTPUT ;
    USE SIGNAL ;
    PORT
      LAYER M4 ;
        RECT  0 68.928 0.084 68.952 ;
    END
  END tap_d[422]
  PIN tap_d[423]
    DIRECTION OUTPUT ;
    USE SIGNAL ;
    PORT
      LAYER M4 ;
        RECT  0 69.024 0.084 69.048 ;
    END
  END tap_d[423]
  PIN tap_d[424]
    DIRECTION OUTPUT ;
    USE SIGNAL ;
    PORT
      LAYER M4 ;
        RECT  0 69.12 0.084 69.144 ;
    END
  END tap_d[424]
  PIN tap_d[425]
    DIRECTION OUTPUT ;
    USE SIGNAL ;
    PORT
      LAYER M4 ;
        RECT  0 69.216 0.084 69.24 ;
    END
  END tap_d[425]
  PIN tap_d[426]
    DIRECTION OUTPUT ;
    USE SIGNAL ;
    PORT
      LAYER M4 ;
        RECT  0 69.312 0.084 69.336 ;
    END
  END tap_d[426]
  PIN tap_d[427]
    DIRECTION OUTPUT ;
    USE SIGNAL ;
    PORT
      LAYER M4 ;
        RECT  0 69.408 0.084 69.432 ;
    END
  END tap_d[427]
  PIN tap_d[428]
    DIRECTION OUTPUT ;
    USE SIGNAL ;
    PORT
      LAYER M4 ;
        RECT  0 69.504 0.084 69.528 ;
    END
  END tap_d[428]
  PIN tap_d[429]
    DIRECTION OUTPUT ;
    USE SIGNAL ;
    PORT
      LAYER M4 ;
        RECT  0 69.6 0.084 69.624 ;
    END
  END tap_d[429]
  PIN tap_d[42]
    DIRECTION OUTPUT ;
    USE SIGNAL ;
    PORT
      LAYER M4 ;
        RECT  0 31.152 0.084 31.176 ;
    END
  END tap_d[42]
  PIN tap_d[430]
    DIRECTION OUTPUT ;
    USE SIGNAL ;
    PORT
      LAYER M4 ;
        RECT  0 69.744 0.084 69.768 ;
    END
  END tap_d[430]
  PIN tap_d[431]
    DIRECTION OUTPUT ;
    USE SIGNAL ;
    PORT
      LAYER M4 ;
        RECT  0 69.84 0.084 69.864 ;
    END
  END tap_d[431]
  PIN tap_d[432]
    DIRECTION OUTPUT ;
    USE SIGNAL ;
    PORT
      LAYER M4 ;
        RECT  0 69.936 0.084 69.96 ;
    END
  END tap_d[432]
  PIN tap_d[433]
    DIRECTION OUTPUT ;
    USE SIGNAL ;
    PORT
      LAYER M4 ;
        RECT  0 70.032 0.084 70.056 ;
    END
  END tap_d[433]
  PIN tap_d[434]
    DIRECTION OUTPUT ;
    USE SIGNAL ;
    PORT
      LAYER M4 ;
        RECT  0 70.128 0.084 70.152 ;
    END
  END tap_d[434]
  PIN tap_d[435]
    DIRECTION OUTPUT ;
    USE SIGNAL ;
    PORT
      LAYER M4 ;
        RECT  0 70.224 0.084 70.248 ;
    END
  END tap_d[435]
  PIN tap_d[436]
    DIRECTION OUTPUT ;
    USE SIGNAL ;
    PORT
      LAYER M4 ;
        RECT  0 70.32 0.084 70.344 ;
    END
  END tap_d[436]
  PIN tap_d[437]
    DIRECTION OUTPUT ;
    USE SIGNAL ;
    PORT
      LAYER M4 ;
        RECT  0 70.416 0.084 70.44 ;
    END
  END tap_d[437]
  PIN tap_d[438]
    DIRECTION OUTPUT ;
    USE SIGNAL ;
    PORT
      LAYER M4 ;
        RECT  0 70.512 0.084 70.536 ;
    END
  END tap_d[438]
  PIN tap_d[439]
    DIRECTION OUTPUT ;
    USE SIGNAL ;
    PORT
      LAYER M4 ;
        RECT  0 70.608 0.084 70.632 ;
    END
  END tap_d[439]
  PIN tap_d[43]
    DIRECTION OUTPUT ;
    USE SIGNAL ;
    PORT
      LAYER M4 ;
        RECT  0 31.248 0.084 31.272 ;
    END
  END tap_d[43]
  PIN tap_d[440]
    DIRECTION OUTPUT ;
    USE SIGNAL ;
    PORT
      LAYER M4 ;
        RECT  0 70.704 0.084 70.728 ;
    END
  END tap_d[440]
  PIN tap_d[441]
    DIRECTION OUTPUT ;
    USE SIGNAL ;
    PORT
      LAYER M4 ;
        RECT  0 70.8 0.084 70.824 ;
    END
  END tap_d[441]
  PIN tap_d[442]
    DIRECTION OUTPUT ;
    USE SIGNAL ;
    PORT
      LAYER M4 ;
        RECT  0 70.896 0.084 70.92 ;
    END
  END tap_d[442]
  PIN tap_d[443]
    DIRECTION OUTPUT ;
    USE SIGNAL ;
    PORT
      LAYER M4 ;
        RECT  0 70.992 0.084 71.016 ;
    END
  END tap_d[443]
  PIN tap_d[444]
    DIRECTION OUTPUT ;
    USE SIGNAL ;
    PORT
      LAYER M4 ;
        RECT  0 71.136 0.084 71.16 ;
    END
  END tap_d[444]
  PIN tap_d[445]
    DIRECTION OUTPUT ;
    USE SIGNAL ;
    PORT
      LAYER M4 ;
        RECT  0 71.232 0.084 71.256 ;
    END
  END tap_d[445]
  PIN tap_d[446]
    DIRECTION OUTPUT ;
    USE SIGNAL ;
    PORT
      LAYER M4 ;
        RECT  0 71.328 0.084 71.352 ;
    END
  END tap_d[446]
  PIN tap_d[447]
    DIRECTION OUTPUT ;
    USE SIGNAL ;
    PORT
      LAYER M4 ;
        RECT  0 71.424 0.084 71.448 ;
    END
  END tap_d[447]
  PIN tap_d[448]
    DIRECTION OUTPUT ;
    USE SIGNAL ;
    PORT
      LAYER M4 ;
        RECT  0 71.52 0.084 71.544 ;
    END
  END tap_d[448]
  PIN tap_d[449]
    DIRECTION OUTPUT ;
    USE SIGNAL ;
    PORT
      LAYER M4 ;
        RECT  0 71.616 0.084 71.64 ;
    END
  END tap_d[449]
  PIN tap_d[44]
    DIRECTION OUTPUT ;
    USE SIGNAL ;
    PORT
      LAYER M4 ;
        RECT  0 31.344 0.084 31.368 ;
    END
  END tap_d[44]
  PIN tap_d[450]
    DIRECTION OUTPUT ;
    USE SIGNAL ;
    PORT
      LAYER M4 ;
        RECT  0 71.712 0.084 71.736 ;
    END
  END tap_d[450]
  PIN tap_d[451]
    DIRECTION OUTPUT ;
    USE SIGNAL ;
    PORT
      LAYER M4 ;
        RECT  0 71.808 0.084 71.832 ;
    END
  END tap_d[451]
  PIN tap_d[452]
    DIRECTION OUTPUT ;
    USE SIGNAL ;
    PORT
      LAYER M4 ;
        RECT  0 71.904 0.084 71.928 ;
    END
  END tap_d[452]
  PIN tap_d[453]
    DIRECTION OUTPUT ;
    USE SIGNAL ;
    PORT
      LAYER M4 ;
        RECT  0 72 0.084 72.024 ;
    END
  END tap_d[453]
  PIN tap_d[454]
    DIRECTION OUTPUT ;
    USE SIGNAL ;
    PORT
      LAYER M4 ;
        RECT  0 72.096 0.084 72.12 ;
    END
  END tap_d[454]
  PIN tap_d[455]
    DIRECTION OUTPUT ;
    USE SIGNAL ;
    PORT
      LAYER M4 ;
        RECT  0 72.192 0.084 72.216 ;
    END
  END tap_d[455]
  PIN tap_d[456]
    DIRECTION OUTPUT ;
    USE SIGNAL ;
    PORT
      LAYER M4 ;
        RECT  0 72.288 0.084 72.312 ;
    END
  END tap_d[456]
  PIN tap_d[457]
    DIRECTION OUTPUT ;
    USE SIGNAL ;
    PORT
      LAYER M4 ;
        RECT  0 72.384 0.084 72.408 ;
    END
  END tap_d[457]
  PIN tap_d[458]
    DIRECTION OUTPUT ;
    USE SIGNAL ;
    PORT
      LAYER M4 ;
        RECT  0 72.528 0.084 72.552 ;
    END
  END tap_d[458]
  PIN tap_d[459]
    DIRECTION OUTPUT ;
    USE SIGNAL ;
    PORT
      LAYER M4 ;
        RECT  0 72.624 0.084 72.648 ;
    END
  END tap_d[459]
  PIN tap_d[45]
    DIRECTION OUTPUT ;
    USE SIGNAL ;
    PORT
      LAYER M4 ;
        RECT  0 31.44 0.084 31.464 ;
    END
  END tap_d[45]
  PIN tap_d[460]
    DIRECTION OUTPUT ;
    USE SIGNAL ;
    PORT
      LAYER M4 ;
        RECT  0 72.72 0.084 72.744 ;
    END
  END tap_d[460]
  PIN tap_d[461]
    DIRECTION OUTPUT ;
    USE SIGNAL ;
    PORT
      LAYER M4 ;
        RECT  0 72.816 0.084 72.84 ;
    END
  END tap_d[461]
  PIN tap_d[462]
    DIRECTION OUTPUT ;
    USE SIGNAL ;
    PORT
      LAYER M4 ;
        RECT  0 72.912 0.084 72.936 ;
    END
  END tap_d[462]
  PIN tap_d[463]
    DIRECTION OUTPUT ;
    USE SIGNAL ;
    PORT
      LAYER M4 ;
        RECT  0 73.008 0.084 73.032 ;
    END
  END tap_d[463]
  PIN tap_d[464]
    DIRECTION OUTPUT ;
    USE SIGNAL ;
    PORT
      LAYER M4 ;
        RECT  0 73.104 0.084 73.128 ;
    END
  END tap_d[464]
  PIN tap_d[465]
    DIRECTION OUTPUT ;
    USE SIGNAL ;
    PORT
      LAYER M4 ;
        RECT  0 73.2 0.084 73.224 ;
    END
  END tap_d[465]
  PIN tap_d[466]
    DIRECTION OUTPUT ;
    USE SIGNAL ;
    PORT
      LAYER M4 ;
        RECT  0 73.296 0.084 73.32 ;
    END
  END tap_d[466]
  PIN tap_d[467]
    DIRECTION OUTPUT ;
    USE SIGNAL ;
    PORT
      LAYER M4 ;
        RECT  0 73.392 0.084 73.416 ;
    END
  END tap_d[467]
  PIN tap_d[468]
    DIRECTION OUTPUT ;
    USE SIGNAL ;
    PORT
      LAYER M4 ;
        RECT  0 73.488 0.084 73.512 ;
    END
  END tap_d[468]
  PIN tap_d[469]
    DIRECTION OUTPUT ;
    USE SIGNAL ;
    PORT
      LAYER M4 ;
        RECT  0 73.584 0.084 73.608 ;
    END
  END tap_d[469]
  PIN tap_d[46]
    DIRECTION OUTPUT ;
    USE SIGNAL ;
    PORT
      LAYER M4 ;
        RECT  0 31.536 0.084 31.56 ;
    END
  END tap_d[46]
  PIN tap_d[470]
    DIRECTION OUTPUT ;
    USE SIGNAL ;
    PORT
      LAYER M4 ;
        RECT  0 73.68 0.084 73.704 ;
    END
  END tap_d[470]
  PIN tap_d[471]
    DIRECTION OUTPUT ;
    USE SIGNAL ;
    PORT
      LAYER M4 ;
        RECT  0 73.776 0.084 73.8 ;
    END
  END tap_d[471]
  PIN tap_d[472]
    DIRECTION OUTPUT ;
    USE SIGNAL ;
    PORT
      LAYER M4 ;
        RECT  0 73.872 0.084 73.896 ;
    END
  END tap_d[472]
  PIN tap_d[473]
    DIRECTION OUTPUT ;
    USE SIGNAL ;
    PORT
      LAYER M4 ;
        RECT  0 74.016 0.084 74.04 ;
    END
  END tap_d[473]
  PIN tap_d[474]
    DIRECTION OUTPUT ;
    USE SIGNAL ;
    PORT
      LAYER M4 ;
        RECT  0 74.112 0.084 74.136 ;
    END
  END tap_d[474]
  PIN tap_d[475]
    DIRECTION OUTPUT ;
    USE SIGNAL ;
    PORT
      LAYER M4 ;
        RECT  0 74.208 0.084 74.232 ;
    END
  END tap_d[475]
  PIN tap_d[476]
    DIRECTION OUTPUT ;
    USE SIGNAL ;
    PORT
      LAYER M4 ;
        RECT  0 74.304 0.084 74.328 ;
    END
  END tap_d[476]
  PIN tap_d[477]
    DIRECTION OUTPUT ;
    USE SIGNAL ;
    PORT
      LAYER M4 ;
        RECT  0 74.4 0.084 74.424 ;
    END
  END tap_d[477]
  PIN tap_d[478]
    DIRECTION OUTPUT ;
    USE SIGNAL ;
    PORT
      LAYER M4 ;
        RECT  0 74.496 0.084 74.52 ;
    END
  END tap_d[478]
  PIN tap_d[479]
    DIRECTION OUTPUT ;
    USE SIGNAL ;
    PORT
      LAYER M4 ;
        RECT  0 74.592 0.084 74.616 ;
    END
  END tap_d[479]
  PIN tap_d[47]
    DIRECTION OUTPUT ;
    USE SIGNAL ;
    PORT
      LAYER M4 ;
        RECT  0 31.632 0.084 31.656 ;
    END
  END tap_d[47]
  PIN tap_d[480]
    DIRECTION OUTPUT ;
    USE SIGNAL ;
    PORT
      LAYER M4 ;
        RECT  0 74.688 0.084 74.712 ;
    END
  END tap_d[480]
  PIN tap_d[481]
    DIRECTION OUTPUT ;
    USE SIGNAL ;
    PORT
      LAYER M4 ;
        RECT  0 74.784 0.084 74.808 ;
    END
  END tap_d[481]
  PIN tap_d[482]
    DIRECTION OUTPUT ;
    USE SIGNAL ;
    PORT
      LAYER M4 ;
        RECT  0 74.88 0.084 74.904 ;
    END
  END tap_d[482]
  PIN tap_d[483]
    DIRECTION OUTPUT ;
    USE SIGNAL ;
    PORT
      LAYER M4 ;
        RECT  0 74.976 0.084 75 ;
    END
  END tap_d[483]
  PIN tap_d[484]
    DIRECTION OUTPUT ;
    USE SIGNAL ;
    PORT
      LAYER M4 ;
        RECT  0 75.072 0.084 75.096 ;
    END
  END tap_d[484]
  PIN tap_d[485]
    DIRECTION OUTPUT ;
    USE SIGNAL ;
    PORT
      LAYER M4 ;
        RECT  0 75.168 0.084 75.192 ;
    END
  END tap_d[485]
  PIN tap_d[486]
    DIRECTION OUTPUT ;
    USE SIGNAL ;
    PORT
      LAYER M4 ;
        RECT  0 75.264 0.084 75.288 ;
    END
  END tap_d[486]
  PIN tap_d[487]
    DIRECTION OUTPUT ;
    USE SIGNAL ;
    PORT
      LAYER M4 ;
        RECT  0 75.408 0.084 75.432 ;
    END
  END tap_d[487]
  PIN tap_d[488]
    DIRECTION OUTPUT ;
    USE SIGNAL ;
    PORT
      LAYER M4 ;
        RECT  0 75.504 0.084 75.528 ;
    END
  END tap_d[488]
  PIN tap_d[489]
    DIRECTION OUTPUT ;
    USE SIGNAL ;
    PORT
      LAYER M4 ;
        RECT  0 75.6 0.084 75.624 ;
    END
  END tap_d[489]
  PIN tap_d[48]
    DIRECTION OUTPUT ;
    USE SIGNAL ;
    PORT
      LAYER M4 ;
        RECT  0 31.728 0.084 31.752 ;
    END
  END tap_d[48]
  PIN tap_d[490]
    DIRECTION OUTPUT ;
    USE SIGNAL ;
    PORT
      LAYER M4 ;
        RECT  0 75.696 0.084 75.72 ;
    END
  END tap_d[490]
  PIN tap_d[491]
    DIRECTION OUTPUT ;
    USE SIGNAL ;
    PORT
      LAYER M4 ;
        RECT  0 75.792 0.084 75.816 ;
    END
  END tap_d[491]
  PIN tap_d[492]
    DIRECTION OUTPUT ;
    USE SIGNAL ;
    PORT
      LAYER M4 ;
        RECT  0 75.888 0.084 75.912 ;
    END
  END tap_d[492]
  PIN tap_d[493]
    DIRECTION OUTPUT ;
    USE SIGNAL ;
    PORT
      LAYER M4 ;
        RECT  0 75.984 0.084 76.008 ;
    END
  END tap_d[493]
  PIN tap_d[494]
    DIRECTION OUTPUT ;
    USE SIGNAL ;
    PORT
      LAYER M4 ;
        RECT  0 76.08 0.084 76.104 ;
    END
  END tap_d[494]
  PIN tap_d[495]
    DIRECTION OUTPUT ;
    USE SIGNAL ;
    PORT
      LAYER M4 ;
        RECT  0 76.176 0.084 76.2 ;
    END
  END tap_d[495]
  PIN tap_d[496]
    DIRECTION OUTPUT ;
    USE SIGNAL ;
    PORT
      LAYER M4 ;
        RECT  0 76.272 0.084 76.296 ;
    END
  END tap_d[496]
  PIN tap_d[497]
    DIRECTION OUTPUT ;
    USE SIGNAL ;
    PORT
      LAYER M4 ;
        RECT  0 76.368 0.084 76.392 ;
    END
  END tap_d[497]
  PIN tap_d[498]
    DIRECTION OUTPUT ;
    USE SIGNAL ;
    PORT
      LAYER M4 ;
        RECT  0 76.464 0.084 76.488 ;
    END
  END tap_d[498]
  PIN tap_d[499]
    DIRECTION OUTPUT ;
    USE SIGNAL ;
    PORT
      LAYER M4 ;
        RECT  0 76.56 0.084 76.584 ;
    END
  END tap_d[499]
  PIN tap_d[49]
    DIRECTION OUTPUT ;
    USE SIGNAL ;
    PORT
      LAYER M4 ;
        RECT  0 31.872 0.084 31.896 ;
    END
  END tap_d[49]
  PIN tap_d[4]
    DIRECTION OUTPUT ;
    USE SIGNAL ;
    PORT
      LAYER M4 ;
        RECT  0 27.36 0.084 27.384 ;
    END
  END tap_d[4]
  PIN tap_d[500]
    DIRECTION OUTPUT ;
    USE SIGNAL ;
    PORT
      LAYER M4 ;
        RECT  0 76.656 0.084 76.68 ;
    END
  END tap_d[500]
  PIN tap_d[501]
    DIRECTION OUTPUT ;
    USE SIGNAL ;
    PORT
      LAYER M4 ;
        RECT  0 76.8 0.084 76.824 ;
    END
  END tap_d[501]
  PIN tap_d[502]
    DIRECTION OUTPUT ;
    USE SIGNAL ;
    PORT
      LAYER M4 ;
        RECT  0 76.896 0.084 76.92 ;
    END
  END tap_d[502]
  PIN tap_d[503]
    DIRECTION OUTPUT ;
    USE SIGNAL ;
    PORT
      LAYER M4 ;
        RECT  0 76.992 0.084 77.016 ;
    END
  END tap_d[503]
  PIN tap_d[504]
    DIRECTION OUTPUT ;
    USE SIGNAL ;
    PORT
      LAYER M4 ;
        RECT  0 77.088 0.084 77.112 ;
    END
  END tap_d[504]
  PIN tap_d[505]
    DIRECTION OUTPUT ;
    USE SIGNAL ;
    PORT
      LAYER M4 ;
        RECT  0 77.184 0.084 77.208 ;
    END
  END tap_d[505]
  PIN tap_d[506]
    DIRECTION OUTPUT ;
    USE SIGNAL ;
    PORT
      LAYER M4 ;
        RECT  0 77.28 0.084 77.304 ;
    END
  END tap_d[506]
  PIN tap_d[507]
    DIRECTION OUTPUT ;
    USE SIGNAL ;
    PORT
      LAYER M4 ;
        RECT  0 77.376 0.084 77.4 ;
    END
  END tap_d[507]
  PIN tap_d[50]
    DIRECTION OUTPUT ;
    USE SIGNAL ;
    PORT
      LAYER M4 ;
        RECT  0 31.968 0.084 31.992 ;
    END
  END tap_d[50]
  PIN tap_d[51]
    DIRECTION OUTPUT ;
    USE SIGNAL ;
    PORT
      LAYER M4 ;
        RECT  0 32.064 0.084 32.088 ;
    END
  END tap_d[51]
  PIN tap_d[52]
    DIRECTION OUTPUT ;
    USE SIGNAL ;
    PORT
      LAYER M4 ;
        RECT  0 32.16 0.084 32.184 ;
    END
  END tap_d[52]
  PIN tap_d[53]
    DIRECTION OUTPUT ;
    USE SIGNAL ;
    PORT
      LAYER M4 ;
        RECT  0 32.256 0.084 32.28 ;
    END
  END tap_d[53]
  PIN tap_d[54]
    DIRECTION OUTPUT ;
    USE SIGNAL ;
    PORT
      LAYER M4 ;
        RECT  0 32.352 0.084 32.376 ;
    END
  END tap_d[54]
  PIN tap_d[55]
    DIRECTION OUTPUT ;
    USE SIGNAL ;
    PORT
      LAYER M4 ;
        RECT  0 32.448 0.084 32.472 ;
    END
  END tap_d[55]
  PIN tap_d[56]
    DIRECTION OUTPUT ;
    USE SIGNAL ;
    PORT
      LAYER M4 ;
        RECT  0 32.544 0.084 32.568 ;
    END
  END tap_d[56]
  PIN tap_d[57]
    DIRECTION OUTPUT ;
    USE SIGNAL ;
    PORT
      LAYER M4 ;
        RECT  0 32.64 0.084 32.664 ;
    END
  END tap_d[57]
  PIN tap_d[58]
    DIRECTION OUTPUT ;
    USE SIGNAL ;
    PORT
      LAYER M4 ;
        RECT  0 32.736 0.084 32.76 ;
    END
  END tap_d[58]
  PIN tap_d[59]
    DIRECTION OUTPUT ;
    USE SIGNAL ;
    PORT
      LAYER M4 ;
        RECT  0 32.832 0.084 32.856 ;
    END
  END tap_d[59]
  PIN tap_d[5]
    DIRECTION OUTPUT ;
    USE SIGNAL ;
    PORT
      LAYER M4 ;
        RECT  0 27.456 0.084 27.48 ;
    END
  END tap_d[5]
  PIN tap_d[60]
    DIRECTION OUTPUT ;
    USE SIGNAL ;
    PORT
      LAYER M4 ;
        RECT  0 32.928 0.084 32.952 ;
    END
  END tap_d[60]
  PIN tap_d[61]
    DIRECTION OUTPUT ;
    USE SIGNAL ;
    PORT
      LAYER M4 ;
        RECT  0 33.024 0.084 33.048 ;
    END
  END tap_d[61]
  PIN tap_d[62]
    DIRECTION OUTPUT ;
    USE SIGNAL ;
    PORT
      LAYER M4 ;
        RECT  0 33.12 0.084 33.144 ;
    END
  END tap_d[62]
  PIN tap_d[63]
    DIRECTION OUTPUT ;
    USE SIGNAL ;
    PORT
      LAYER M4 ;
        RECT  0 33.264 0.084 33.288 ;
    END
  END tap_d[63]
  PIN tap_d[64]
    DIRECTION OUTPUT ;
    USE SIGNAL ;
    PORT
      LAYER M4 ;
        RECT  0 33.36 0.084 33.384 ;
    END
  END tap_d[64]
  PIN tap_d[65]
    DIRECTION OUTPUT ;
    USE SIGNAL ;
    PORT
      LAYER M4 ;
        RECT  0 33.456 0.084 33.48 ;
    END
  END tap_d[65]
  PIN tap_d[66]
    DIRECTION OUTPUT ;
    USE SIGNAL ;
    PORT
      LAYER M4 ;
        RECT  0 33.552 0.084 33.576 ;
    END
  END tap_d[66]
  PIN tap_d[67]
    DIRECTION OUTPUT ;
    USE SIGNAL ;
    PORT
      LAYER M4 ;
        RECT  0 33.648 0.084 33.672 ;
    END
  END tap_d[67]
  PIN tap_d[68]
    DIRECTION OUTPUT ;
    USE SIGNAL ;
    PORT
      LAYER M4 ;
        RECT  0 33.744 0.084 33.768 ;
    END
  END tap_d[68]
  PIN tap_d[69]
    DIRECTION OUTPUT ;
    USE SIGNAL ;
    PORT
      LAYER M4 ;
        RECT  0 33.84 0.084 33.864 ;
    END
  END tap_d[69]
  PIN tap_d[6]
    DIRECTION OUTPUT ;
    USE SIGNAL ;
    PORT
      LAYER M4 ;
        RECT  0 27.552 0.084 27.576 ;
    END
  END tap_d[6]
  PIN tap_d[70]
    DIRECTION OUTPUT ;
    USE SIGNAL ;
    PORT
      LAYER M4 ;
        RECT  0 33.936 0.084 33.96 ;
    END
  END tap_d[70]
  PIN tap_d[71]
    DIRECTION OUTPUT ;
    USE SIGNAL ;
    PORT
      LAYER M4 ;
        RECT  0 34.032 0.084 34.056 ;
    END
  END tap_d[71]
  PIN tap_d[72]
    DIRECTION OUTPUT ;
    USE SIGNAL ;
    PORT
      LAYER M4 ;
        RECT  0 34.128 0.084 34.152 ;
    END
  END tap_d[72]
  PIN tap_d[73]
    DIRECTION OUTPUT ;
    USE SIGNAL ;
    PORT
      LAYER M4 ;
        RECT  0 34.224 0.084 34.248 ;
    END
  END tap_d[73]
  PIN tap_d[74]
    DIRECTION OUTPUT ;
    USE SIGNAL ;
    PORT
      LAYER M4 ;
        RECT  0 34.32 0.084 34.344 ;
    END
  END tap_d[74]
  PIN tap_d[75]
    DIRECTION OUTPUT ;
    USE SIGNAL ;
    PORT
      LAYER M4 ;
        RECT  0 34.416 0.084 34.44 ;
    END
  END tap_d[75]
  PIN tap_d[76]
    DIRECTION OUTPUT ;
    USE SIGNAL ;
    PORT
      LAYER M4 ;
        RECT  0 34.512 0.084 34.536 ;
    END
  END tap_d[76]
  PIN tap_d[77]
    DIRECTION OUTPUT ;
    USE SIGNAL ;
    PORT
      LAYER M4 ;
        RECT  0 34.656 0.084 34.68 ;
    END
  END tap_d[77]
  PIN tap_d[78]
    DIRECTION OUTPUT ;
    USE SIGNAL ;
    PORT
      LAYER M4 ;
        RECT  0 34.752 0.084 34.776 ;
    END
  END tap_d[78]
  PIN tap_d[79]
    DIRECTION OUTPUT ;
    USE SIGNAL ;
    PORT
      LAYER M4 ;
        RECT  0 34.848 0.084 34.872 ;
    END
  END tap_d[79]
  PIN tap_d[7]
    DIRECTION OUTPUT ;
    USE SIGNAL ;
    PORT
      LAYER M4 ;
        RECT  0 27.696 0.084 27.72 ;
    END
  END tap_d[7]
  PIN tap_d[80]
    DIRECTION OUTPUT ;
    USE SIGNAL ;
    PORT
      LAYER M4 ;
        RECT  0 34.944 0.084 34.968 ;
    END
  END tap_d[80]
  PIN tap_d[81]
    DIRECTION OUTPUT ;
    USE SIGNAL ;
    PORT
      LAYER M4 ;
        RECT  0 35.04 0.084 35.064 ;
    END
  END tap_d[81]
  PIN tap_d[82]
    DIRECTION OUTPUT ;
    USE SIGNAL ;
    PORT
      LAYER M4 ;
        RECT  0 35.136 0.084 35.16 ;
    END
  END tap_d[82]
  PIN tap_d[83]
    DIRECTION OUTPUT ;
    USE SIGNAL ;
    PORT
      LAYER M4 ;
        RECT  0 35.232 0.084 35.256 ;
    END
  END tap_d[83]
  PIN tap_d[84]
    DIRECTION OUTPUT ;
    USE SIGNAL ;
    PORT
      LAYER M4 ;
        RECT  0 35.328 0.084 35.352 ;
    END
  END tap_d[84]
  PIN tap_d[85]
    DIRECTION OUTPUT ;
    USE SIGNAL ;
    PORT
      LAYER M4 ;
        RECT  0 35.424 0.084 35.448 ;
    END
  END tap_d[85]
  PIN tap_d[86]
    DIRECTION OUTPUT ;
    USE SIGNAL ;
    PORT
      LAYER M4 ;
        RECT  0 35.52 0.084 35.544 ;
    END
  END tap_d[86]
  PIN tap_d[87]
    DIRECTION OUTPUT ;
    USE SIGNAL ;
    PORT
      LAYER M4 ;
        RECT  0 35.616 0.084 35.64 ;
    END
  END tap_d[87]
  PIN tap_d[88]
    DIRECTION OUTPUT ;
    USE SIGNAL ;
    PORT
      LAYER M4 ;
        RECT  0 35.712 0.084 35.736 ;
    END
  END tap_d[88]
  PIN tap_d[89]
    DIRECTION OUTPUT ;
    USE SIGNAL ;
    PORT
      LAYER M4 ;
        RECT  0 35.808 0.084 35.832 ;
    END
  END tap_d[89]
  PIN tap_d[8]
    DIRECTION OUTPUT ;
    USE SIGNAL ;
    PORT
      LAYER M4 ;
        RECT  0 27.792 0.084 27.816 ;
    END
  END tap_d[8]
  PIN tap_d[90]
    DIRECTION OUTPUT ;
    USE SIGNAL ;
    PORT
      LAYER M4 ;
        RECT  0 35.904 0.084 35.928 ;
    END
  END tap_d[90]
  PIN tap_d[91]
    DIRECTION OUTPUT ;
    USE SIGNAL ;
    PORT
      LAYER M4 ;
        RECT  0 36 0.084 36.024 ;
    END
  END tap_d[91]
  PIN tap_d[92]
    DIRECTION OUTPUT ;
    USE SIGNAL ;
    PORT
      LAYER M4 ;
        RECT  0 36.144 0.084 36.168 ;
    END
  END tap_d[92]
  PIN tap_d[93]
    DIRECTION OUTPUT ;
    USE SIGNAL ;
    PORT
      LAYER M4 ;
        RECT  0 36.24 0.084 36.264 ;
    END
  END tap_d[93]
  PIN tap_d[94]
    DIRECTION OUTPUT ;
    USE SIGNAL ;
    PORT
      LAYER M4 ;
        RECT  0 36.336 0.084 36.36 ;
    END
  END tap_d[94]
  PIN tap_d[95]
    DIRECTION OUTPUT ;
    USE SIGNAL ;
    PORT
      LAYER M4 ;
        RECT  0 36.432 0.084 36.456 ;
    END
  END tap_d[95]
  PIN tap_d[96]
    DIRECTION OUTPUT ;
    USE SIGNAL ;
    PORT
      LAYER M4 ;
        RECT  0 36.528 0.084 36.552 ;
    END
  END tap_d[96]
  PIN tap_d[97]
    DIRECTION OUTPUT ;
    USE SIGNAL ;
    PORT
      LAYER M4 ;
        RECT  0 36.624 0.084 36.648 ;
    END
  END tap_d[97]
  PIN tap_d[98]
    DIRECTION OUTPUT ;
    USE SIGNAL ;
    PORT
      LAYER M4 ;
        RECT  0 36.72 0.084 36.744 ;
    END
  END tap_d[98]
  PIN tap_d[99]
    DIRECTION OUTPUT ;
    USE SIGNAL ;
    PORT
      LAYER M4 ;
        RECT  0 36.816 0.084 36.84 ;
    END
  END tap_d[99]
  PIN tap_d[9]
    DIRECTION OUTPUT ;
    USE SIGNAL ;
    PORT
      LAYER M4 ;
        RECT  0 27.888 0.084 27.912 ;
    END
  END tap_d[9]
  PIN tie_hi
    DIRECTION OUTPUT ;
    USE SIGNAL ;
    PORT
      LAYER M5 ;
        RECT  0.96 103.572 0.984 103.656 ;
    END
  END tie_hi
  PIN tie_lo
    DIRECTION OUTPUT ;
    USE SIGNAL ;
    PORT
      LAYER M5 ;
        RECT  1.2 103.572 1.224 103.656 ;
    END
  END tie_lo
  PIN VDD
    DIRECTION INOUT ;
    USE POWER ;
    PORT
      LAYER M5 ;
        RECT  45.792 2.151 45.912 101.273 ;
        RECT  40.392 2.151 40.512 101.273 ;
        RECT  34.992 2.151 35.112 101.273 ;
        RECT  29.592 2.151 29.712 101.273 ;
        RECT  24.192 2.151 24.312 101.273 ;
        RECT  18.792 2.151 18.912 101.273 ;
        RECT  13.392 2.151 13.512 101.273 ;
        RECT  7.992 2.151 8.112 101.273 ;
        RECT  2.592 2.151 2.712 101.273 ;
    END
  END VDD
  PIN VSS
    DIRECTION INOUT ;
    USE GROUND ;
    PORT
      LAYER M5 ;
        RECT  45.6 2.137 45.72 101.259 ;
        RECT  40.2 2.137 40.32 101.259 ;
        RECT  34.8 2.137 34.92 101.259 ;
        RECT  29.4 2.137 29.52 101.259 ;
        RECT  24 2.137 24.12 101.259 ;
        RECT  18.6 2.137 18.72 101.259 ;
        RECT  13.2 2.137 13.32 101.259 ;
        RECT  7.8 2.137 7.92 101.259 ;
        RECT  2.4 2.137 2.52 101.259 ;
    END
  END VSS
  # OT_OBS_CLOSED layer=M5 d_um=1.536 added=59
  OBS
    LAYER RVTN ;
     RECT  2.16 2.16 50.49 2.295 ;
     RECT  2.16 2.565 50.49 2.835 ;
     RECT  2.16 3.105 50.49 3.375 ;
     RECT  2.16 3.645 50.49 3.915 ;
     RECT  2.16 4.185 50.49 4.455 ;
     RECT  2.16 4.725 50.49 4.995 ;
     RECT  2.16 5.265 50.49 5.535 ;
     RECT  2.16 5.805 50.49 6.075 ;
     RECT  2.16 6.345 50.49 6.615 ;
     RECT  2.16 6.885 50.49 7.155 ;
     RECT  2.16 7.425 50.49 7.695 ;
     RECT  2.16 7.965 50.49 8.235 ;
     RECT  2.16 8.505 50.49 8.775 ;
     RECT  2.16 9.045 50.49 9.315 ;
     RECT  2.16 9.585 50.49 9.855 ;
     RECT  2.16 10.125 50.49 10.395 ;
     RECT  2.16 10.665 50.49 10.935 ;
     RECT  2.16 11.205 50.49 11.475 ;
     RECT  2.16 11.745 50.49 12.015 ;
     RECT  2.16 12.285 50.49 12.555 ;
     RECT  2.16 12.825 50.49 13.095 ;
     RECT  2.16 13.365 50.49 13.635 ;
     RECT  2.16 13.905 50.49 14.175 ;
     RECT  2.16 14.445 50.49 14.715 ;
     RECT  2.16 14.985 50.49 15.255 ;
     RECT  2.16 15.525 50.49 15.795 ;
     RECT  2.16 16.065 50.49 16.335 ;
     RECT  2.16 16.605 50.49 16.875 ;
     RECT  2.16 17.145 50.49 17.415 ;
     RECT  2.16 17.685 50.49 17.955 ;
     RECT  2.16 18.225 50.49 18.495 ;
     RECT  2.16 18.765 50.49 19.035 ;
     RECT  2.16 19.305 50.49 19.575 ;
     RECT  2.16 19.845 50.49 20.115 ;
     RECT  2.16 20.385 50.49 20.655 ;
     RECT  2.16 20.925 50.49 21.195 ;
     RECT  2.16 21.465 50.49 21.735 ;
     RECT  2.16 22.005 50.49 22.275 ;
     RECT  2.16 22.545 50.49 22.815 ;
     RECT  2.16 23.085 50.49 23.355 ;
     RECT  2.16 23.625 50.49 23.895 ;
     RECT  2.16 24.165 50.49 24.435 ;
     RECT  2.16 24.705 50.49 24.975 ;
     RECT  2.16 25.245 50.49 25.515 ;
     RECT  2.16 25.785 50.49 26.055 ;
     RECT  2.16 26.325 50.49 26.595 ;
     RECT  2.16 26.865 50.49 27.135 ;
     RECT  2.16 27.405 50.49 27.675 ;
     RECT  2.16 27.945 50.49 28.215 ;
     RECT  2.16 28.485 50.49 28.755 ;
     RECT  2.16 29.025 50.49 29.295 ;
     RECT  2.16 29.565 50.49 29.835 ;
     RECT  2.16 30.105 50.49 30.375 ;
     RECT  2.16 30.645 50.49 30.915 ;
     RECT  2.16 31.185 50.49 31.455 ;
     RECT  2.16 31.725 50.49 31.995 ;
     RECT  2.16 32.265 50.49 32.535 ;
     RECT  2.16 32.805 50.49 33.075 ;
     RECT  2.16 33.345 50.49 33.615 ;
     RECT  2.16 33.885 50.49 34.155 ;
     RECT  2.16 34.425 50.49 34.695 ;
     RECT  2.16 34.965 50.49 35.235 ;
     RECT  2.16 35.505 50.49 35.775 ;
     RECT  2.16 36.045 50.49 36.315 ;
     RECT  2.16 36.585 50.49 36.855 ;
     RECT  2.16 37.125 50.49 37.395 ;
     RECT  2.16 37.665 50.49 37.935 ;
     RECT  2.16 38.205 50.49 38.475 ;
     RECT  2.16 38.745 50.49 39.015 ;
     RECT  2.16 39.285 50.49 39.555 ;
     RECT  2.16 39.825 50.49 40.095 ;
     RECT  2.16 40.365 50.49 40.635 ;
     RECT  2.16 40.905 50.49 41.175 ;
     RECT  2.16 41.445 50.49 41.715 ;
     RECT  2.16 41.985 50.49 42.255 ;
     RECT  2.16 42.525 50.49 42.795 ;
     RECT  2.16 43.065 50.49 43.335 ;
     RECT  2.16 43.605 50.49 43.875 ;
     RECT  2.16 44.145 50.49 44.415 ;
     RECT  2.16 44.685 50.49 44.955 ;
     RECT  2.16 45.225 50.49 45.495 ;
     RECT  2.16 45.765 50.49 46.035 ;
     RECT  2.16 46.305 50.49 46.575 ;
     RECT  2.16 46.845 50.49 47.115 ;
     RECT  2.16 47.385 50.49 47.655 ;
     RECT  2.16 47.925 50.49 48.195 ;
     RECT  2.16 48.465 50.49 48.735 ;
     RECT  2.16 49.005 50.49 49.275 ;
     RECT  2.16 49.545 50.49 49.815 ;
     RECT  2.16 50.085 50.49 50.355 ;
     RECT  2.16 50.625 50.49 50.895 ;
     RECT  2.16 51.165 50.49 51.435 ;
     RECT  2.16 51.705 50.49 51.975 ;
     RECT  2.16 52.245 50.49 52.515 ;
     RECT  2.16 52.785 50.49 53.055 ;
     RECT  2.16 53.325 50.49 53.595 ;
     RECT  2.16 53.865 50.49 54.135 ;
     RECT  2.16 54.405 50.49 54.675 ;
     RECT  2.16 54.945 50.49 55.215 ;
     RECT  2.16 55.485 50.49 55.755 ;
     RECT  2.16 56.025 50.49 56.295 ;
     RECT  2.16 56.565 50.49 56.835 ;
     RECT  2.16 57.105 50.49 57.375 ;
     RECT  2.16 57.645 50.49 57.915 ;
     RECT  2.16 58.185 50.49 58.455 ;
     RECT  2.16 58.725 50.49 58.995 ;
     RECT  2.16 59.265 50.49 59.535 ;
     RECT  2.16 59.805 50.49 60.075 ;
     RECT  2.16 60.345 50.49 60.615 ;
     RECT  2.16 60.885 50.49 61.155 ;
     RECT  2.16 61.425 50.49 61.695 ;
     RECT  2.16 61.965 50.49 62.235 ;
     RECT  2.16 62.505 50.49 62.775 ;
     RECT  2.16 63.045 50.49 63.315 ;
     RECT  2.16 63.585 50.49 63.855 ;
     RECT  2.16 64.125 50.49 64.395 ;
     RECT  2.16 64.665 50.49 64.935 ;
     RECT  2.16 65.205 50.49 65.475 ;
     RECT  2.16 65.745 50.49 66.015 ;
     RECT  2.16 66.285 50.49 66.555 ;
     RECT  2.16 66.825 50.49 67.095 ;
     RECT  2.16 67.365 50.49 67.635 ;
     RECT  2.16 67.905 50.49 68.175 ;
     RECT  2.16 68.445 50.49 68.715 ;
     RECT  2.16 68.985 50.49 69.255 ;
     RECT  2.16 69.525 50.49 69.795 ;
     RECT  2.16 70.065 50.49 70.335 ;
     RECT  2.16 70.605 50.49 70.875 ;
     RECT  2.16 71.145 50.49 71.415 ;
     RECT  2.16 71.685 50.49 71.955 ;
     RECT  2.16 72.225 50.49 72.495 ;
     RECT  2.16 72.765 50.49 73.035 ;
     RECT  2.16 73.305 50.49 73.575 ;
     RECT  2.16 73.845 50.49 74.115 ;
     RECT  2.16 74.385 50.49 74.655 ;
     RECT  2.16 74.925 50.49 75.195 ;
     RECT  2.16 75.465 50.49 75.735 ;
     RECT  2.16 76.005 50.49 76.275 ;
     RECT  2.16 76.545 50.49 76.815 ;
     RECT  2.16 77.085 50.49 77.355 ;
     RECT  2.16 77.625 50.49 77.895 ;
     RECT  2.16 78.165 50.49 78.435 ;
     RECT  2.16 78.705 50.49 78.975 ;
     RECT  2.16 79.245 50.49 79.515 ;
     RECT  2.16 79.785 50.49 80.055 ;
     RECT  2.16 80.325 50.49 80.595 ;
     RECT  2.16 80.865 50.49 81.135 ;
     RECT  2.16 81.405 50.49 81.675 ;
     RECT  2.16 81.945 50.49 82.215 ;
     RECT  2.16 82.485 50.49 82.755 ;
     RECT  2.16 83.025 50.49 83.295 ;
     RECT  2.16 83.565 50.49 83.835 ;
     RECT  2.16 84.105 50.49 84.375 ;
     RECT  2.16 84.645 50.49 84.915 ;
     RECT  2.16 85.185 50.49 85.455 ;
     RECT  2.16 85.725 50.49 85.995 ;
     RECT  2.16 86.265 50.49 86.535 ;
     RECT  2.16 86.805 50.49 87.075 ;
     RECT  2.16 87.345 50.49 87.615 ;
     RECT  2.16 87.885 50.49 88.155 ;
     RECT  2.16 88.425 50.49 88.695 ;
     RECT  2.16 88.965 50.49 89.235 ;
     RECT  2.16 89.505 50.49 89.775 ;
     RECT  2.16 90.045 50.49 90.315 ;
     RECT  2.16 90.585 50.49 90.855 ;
     RECT  2.16 91.125 50.49 91.395 ;
     RECT  2.16 91.665 50.49 91.935 ;
     RECT  2.16 92.205 50.49 92.475 ;
     RECT  2.16 92.745 50.49 93.015 ;
     RECT  2.16 93.285 50.49 93.555 ;
     RECT  2.16 93.825 50.49 94.095 ;
     RECT  2.16 94.365 50.49 94.635 ;
     RECT  2.16 94.905 50.49 95.175 ;
     RECT  2.16 95.445 50.49 95.715 ;
     RECT  2.16 95.985 50.49 96.255 ;
     RECT  2.16 96.525 50.49 96.795 ;
     RECT  2.16 97.065 50.49 97.335 ;
     RECT  2.16 97.605 50.49 97.875 ;
     RECT  2.16 98.145 50.49 98.415 ;
     RECT  2.16 98.685 50.49 98.955 ;
     RECT  2.16 99.225 50.49 99.495 ;
     RECT  2.16 99.765 50.49 100.035 ;
     RECT  2.16 100.305 50.49 100.575 ;
     RECT  2.16 100.845 50.49 101.115 ;
    LAYER RVTP ;
     RECT  2.16 2.295 50.49 2.565 ;
     RECT  2.16 2.835 50.49 3.105 ;
     RECT  2.16 3.375 50.49 3.645 ;
     RECT  2.16 3.915 50.49 4.185 ;
     RECT  2.16 4.455 50.49 4.725 ;
     RECT  2.16 4.995 50.49 5.265 ;
     RECT  2.16 5.535 50.49 5.805 ;
     RECT  2.16 6.075 50.49 6.345 ;
     RECT  2.16 6.615 50.49 6.885 ;
     RECT  2.16 7.155 50.49 7.425 ;
     RECT  2.16 7.695 50.49 7.965 ;
     RECT  2.16 8.235 50.49 8.505 ;
     RECT  2.16 8.775 50.49 9.045 ;
     RECT  2.16 9.315 50.49 9.585 ;
     RECT  2.16 9.855 50.49 10.125 ;
     RECT  2.16 10.395 50.49 10.665 ;
     RECT  2.16 10.935 50.49 11.205 ;
     RECT  2.16 11.475 50.49 11.745 ;
     RECT  2.16 12.015 50.49 12.285 ;
     RECT  2.16 12.555 50.49 12.825 ;
     RECT  2.16 13.095 50.49 13.365 ;
     RECT  2.16 13.635 50.49 13.905 ;
     RECT  2.16 14.175 50.49 14.445 ;
     RECT  2.16 14.715 50.49 14.985 ;
     RECT  2.16 15.255 50.49 15.525 ;
     RECT  2.16 15.795 50.49 16.065 ;
     RECT  2.16 16.335 50.49 16.605 ;
     RECT  2.16 16.875 50.49 17.145 ;
     RECT  2.16 17.415 50.49 17.685 ;
     RECT  2.16 17.955 50.49 18.225 ;
     RECT  2.16 18.495 50.49 18.765 ;
     RECT  2.16 19.035 50.49 19.305 ;
     RECT  2.16 19.575 50.49 19.845 ;
     RECT  2.16 20.115 50.49 20.385 ;
     RECT  2.16 20.655 50.49 20.925 ;
     RECT  2.16 21.195 50.49 21.465 ;
     RECT  2.16 21.735 50.49 22.005 ;
     RECT  2.16 22.275 50.49 22.545 ;
     RECT  2.16 22.815 50.49 23.085 ;
     RECT  2.16 23.355 50.49 23.625 ;
     RECT  2.16 23.895 50.49 24.165 ;
     RECT  2.16 24.435 50.49 24.705 ;
     RECT  2.16 24.975 50.49 25.245 ;
     RECT  2.16 25.515 50.49 25.785 ;
     RECT  2.16 26.055 50.49 26.325 ;
     RECT  2.16 26.595 50.49 26.865 ;
     RECT  2.16 27.135 50.49 27.405 ;
     RECT  2.16 27.675 50.49 27.945 ;
     RECT  2.16 28.215 50.49 28.485 ;
     RECT  2.16 28.755 50.49 29.025 ;
     RECT  2.16 29.295 50.49 29.565 ;
     RECT  2.16 29.835 50.49 30.105 ;
     RECT  2.16 30.375 50.49 30.645 ;
     RECT  2.16 30.915 50.49 31.185 ;
     RECT  2.16 31.455 50.49 31.725 ;
     RECT  2.16 31.995 50.49 32.265 ;
     RECT  2.16 32.535 50.49 32.805 ;
     RECT  2.16 33.075 50.49 33.345 ;
     RECT  2.16 33.615 50.49 33.885 ;
     RECT  2.16 34.155 50.49 34.425 ;
     RECT  2.16 34.695 50.49 34.965 ;
     RECT  2.16 35.235 50.49 35.505 ;
     RECT  2.16 35.775 50.49 36.045 ;
     RECT  2.16 36.315 50.49 36.585 ;
     RECT  2.16 36.855 50.49 37.125 ;
     RECT  2.16 37.395 50.49 37.665 ;
     RECT  2.16 37.935 50.49 38.205 ;
     RECT  2.16 38.475 50.49 38.745 ;
     RECT  2.16 39.015 50.49 39.285 ;
     RECT  2.16 39.555 50.49 39.825 ;
     RECT  2.16 40.095 50.49 40.365 ;
     RECT  2.16 40.635 50.49 40.905 ;
     RECT  2.16 41.175 50.49 41.445 ;
     RECT  2.16 41.715 50.49 41.985 ;
     RECT  2.16 42.255 50.49 42.525 ;
     RECT  2.16 42.795 50.49 43.065 ;
     RECT  2.16 43.335 50.49 43.605 ;
     RECT  2.16 43.875 50.49 44.145 ;
     RECT  2.16 44.415 50.49 44.685 ;
     RECT  2.16 44.955 50.49 45.225 ;
     RECT  2.16 45.495 50.49 45.765 ;
     RECT  2.16 46.035 50.49 46.305 ;
     RECT  2.16 46.575 50.49 46.845 ;
     RECT  2.16 47.115 50.49 47.385 ;
     RECT  2.16 47.655 50.49 47.925 ;
     RECT  2.16 48.195 50.49 48.465 ;
     RECT  2.16 48.735 50.49 49.005 ;
     RECT  2.16 49.275 50.49 49.545 ;
     RECT  2.16 49.815 50.49 50.085 ;
     RECT  2.16 50.355 50.49 50.625 ;
     RECT  2.16 50.895 50.49 51.165 ;
     RECT  2.16 51.435 50.49 51.705 ;
     RECT  2.16 51.975 50.49 52.245 ;
     RECT  2.16 52.515 50.49 52.785 ;
     RECT  2.16 53.055 50.49 53.325 ;
     RECT  2.16 53.595 50.49 53.865 ;
     RECT  2.16 54.135 50.49 54.405 ;
     RECT  2.16 54.675 50.49 54.945 ;
     RECT  2.16 55.215 50.49 55.485 ;
     RECT  2.16 55.755 50.49 56.025 ;
     RECT  2.16 56.295 50.49 56.565 ;
     RECT  2.16 56.835 50.49 57.105 ;
     RECT  2.16 57.375 50.49 57.645 ;
     RECT  2.16 57.915 50.49 58.185 ;
     RECT  2.16 58.455 50.49 58.725 ;
     RECT  2.16 58.995 50.49 59.265 ;
     RECT  2.16 59.535 50.49 59.805 ;
     RECT  2.16 60.075 50.49 60.345 ;
     RECT  2.16 60.615 50.49 60.885 ;
     RECT  2.16 61.155 50.49 61.425 ;
     RECT  2.16 61.695 50.49 61.965 ;
     RECT  2.16 62.235 50.49 62.505 ;
     RECT  2.16 62.775 50.49 63.045 ;
     RECT  2.16 63.315 50.49 63.585 ;
     RECT  2.16 63.855 50.49 64.125 ;
     RECT  2.16 64.395 50.49 64.665 ;
     RECT  2.16 64.935 50.49 65.205 ;
     RECT  2.16 65.475 50.49 65.745 ;
     RECT  2.16 66.015 50.49 66.285 ;
     RECT  2.16 66.555 50.49 66.825 ;
     RECT  2.16 67.095 50.49 67.365 ;
     RECT  2.16 67.635 50.49 67.905 ;
     RECT  2.16 68.175 50.49 68.445 ;
     RECT  2.16 68.715 50.49 68.985 ;
     RECT  2.16 69.255 50.49 69.525 ;
     RECT  2.16 69.795 50.49 70.065 ;
     RECT  2.16 70.335 50.49 70.605 ;
     RECT  2.16 70.875 50.49 71.145 ;
     RECT  2.16 71.415 50.49 71.685 ;
     RECT  2.16 71.955 50.49 72.225 ;
     RECT  2.16 72.495 50.49 72.765 ;
     RECT  2.16 73.035 50.49 73.305 ;
     RECT  2.16 73.575 50.49 73.845 ;
     RECT  2.16 74.115 50.49 74.385 ;
     RECT  2.16 74.655 50.49 74.925 ;
     RECT  2.16 75.195 50.49 75.465 ;
     RECT  2.16 75.735 50.49 76.005 ;
     RECT  2.16 76.275 50.49 76.545 ;
     RECT  2.16 76.815 50.49 77.085 ;
     RECT  2.16 77.355 50.49 77.625 ;
     RECT  2.16 77.895 50.49 78.165 ;
     RECT  2.16 78.435 50.49 78.705 ;
     RECT  2.16 78.975 50.49 79.245 ;
     RECT  2.16 79.515 50.49 79.785 ;
     RECT  2.16 80.055 50.49 80.325 ;
     RECT  2.16 80.595 50.49 80.865 ;
     RECT  2.16 81.135 50.49 81.405 ;
     RECT  2.16 81.675 50.49 81.945 ;
     RECT  2.16 82.215 50.49 82.485 ;
     RECT  2.16 82.755 50.49 83.025 ;
     RECT  2.16 83.295 50.49 83.565 ;
     RECT  2.16 83.835 50.49 84.105 ;
     RECT  2.16 84.375 50.49 84.645 ;
     RECT  2.16 84.915 50.49 85.185 ;
     RECT  2.16 85.455 50.49 85.725 ;
     RECT  2.16 85.995 50.49 86.265 ;
     RECT  2.16 86.535 50.49 86.805 ;
     RECT  2.16 87.075 50.49 87.345 ;
     RECT  2.16 87.615 50.49 87.885 ;
     RECT  2.16 88.155 50.49 88.425 ;
     RECT  2.16 88.695 50.49 88.965 ;
     RECT  2.16 89.235 50.49 89.505 ;
     RECT  2.16 89.775 50.49 90.045 ;
     RECT  2.16 90.315 50.49 90.585 ;
     RECT  2.16 90.855 50.49 91.125 ;
     RECT  2.16 91.395 50.49 91.665 ;
     RECT  2.16 91.935 50.49 92.205 ;
     RECT  2.16 92.475 50.49 92.745 ;
     RECT  2.16 93.015 50.49 93.285 ;
     RECT  2.16 93.555 50.49 93.825 ;
     RECT  2.16 94.095 50.49 94.365 ;
     RECT  2.16 94.635 50.49 94.905 ;
     RECT  2.16 95.175 50.49 95.445 ;
     RECT  2.16 95.715 50.49 95.985 ;
     RECT  2.16 96.255 50.49 96.525 ;
     RECT  2.16 96.795 50.49 97.065 ;
     RECT  2.16 97.335 50.49 97.605 ;
     RECT  2.16 97.875 50.49 98.145 ;
     RECT  2.16 98.415 50.49 98.685 ;
     RECT  2.16 98.955 50.49 99.225 ;
     RECT  2.16 99.495 50.49 99.765 ;
     RECT  2.16 100.035 50.49 100.305 ;
     RECT  2.16 100.575 50.49 100.845 ;
     RECT  2.16 101.115 50.49 101.25 ;
    LAYER M1 ;
     RECT  2.16 2.151 50.49 101.259 ;
    LAYER M2 ;
     RECT  0.103 30.186 0.139 30.204 ;
     RECT  0.103 40.986 0.139 41.004 ;
     RECT  0.103 48.906 0.139 49.464 ;
     RECT  0.103 57.546 0.139 59.526 ;
     RECT  0.103 28.386 0.175 28.944 ;
     RECT  0.103 31.806 0.175 31.824 ;
     RECT  0.103 32.976 0.175 32.994 ;
     RECT  0.103 46.548 0.175 47.142 ;
     RECT  0.103 34.056 0.203 34.074 ;
     RECT  0.103 34.821 0.203 35.028 ;
     RECT  0.103 37.026 0.203 37.728 ;
     RECT  0.139 40.914 0.203 41.004 ;
     RECT  0.103 44.388 0.203 45.594 ;
     RECT  0.139 48.636 0.203 49.464 ;
     RECT  0.103 52.416 0.203 53.514 ;
     RECT  0.103 56.106 0.203 56.322 ;
     RECT  0.139 57.276 0.203 59.526 ;
     RECT  0.103 61.974 0.203 62.379 ;
     RECT  0.103 73.242 0.203 73.26 ;
     RECT  0.103 77.13 0.203 77.148 ;
     RECT  0.175 43.542 0.211 43.56 ;
     RECT  0.203 44.388 0.211 44.442 ;
     RECT  0.203 45.198 0.239 45.594 ;
     RECT  0.203 48.636 0.239 48.654 ;
     RECT  0.139 55.188 0.239 55.206 ;
     RECT  0.203 59.508 0.239 59.526 ;
     RECT  0.103 60.318 0.239 60.336 ;
     RECT  0.139 27.036 0.247 27.054 ;
     RECT  0.175 28.386 0.247 29.214 ;
     RECT  0.211 43.542 0.275 44.442 ;
     RECT  0.103 50.904 0.347 51.192 ;
     RECT  0.203 62.361 0.347 62.379 ;
     RECT  0.103 70.884 0.347 70.902 ;
     RECT  0.103 39.222 0.383 39.744 ;
     RECT  0.247 26.766 0.463 27.054 ;
     RECT  0.247 28.116 0.463 29.214 ;
     RECT  0.175 31.806 0.463 32.994 ;
     RECT  0.139 30.186 0.499 30.564 ;
     RECT  0.463 31.428 0.499 32.994 ;
     RECT  0.383 39.726 0.499 39.744 ;
     RECT  0.203 40.914 0.499 40.932 ;
     RECT  0.103 68.922 0.499 68.94 ;
     RECT  0.499 30.186 0.535 32.994 ;
     RECT  0.239 45.576 0.535 45.594 ;
     RECT  0.175 46.431 0.535 47.142 ;
     RECT  0.499 68.382 0.535 68.94 ;
     RECT  0.103 75.546 0.535 75.564 ;
     RECT  0.203 37.026 0.671 37.656 ;
     RECT  0.203 49.446 1.111 49.464 ;
     RECT  0.347 51.174 1.147 51.192 ;
     RECT  0.103 74.556 1.147 74.574 ;
     RECT  0.535 75.546 1.147 75.726 ;
     RECT  1.147 51.174 1.175 51.264 ;
     RECT  1.175 51.246 1.183 51.264 ;
     RECT  0.203 52.416 1.183 52.434 ;
     RECT  0.203 53.226 1.183 53.514 ;
     RECT  0.499 39.726 1.211 40.932 ;
     RECT  1.183 53.226 1.283 53.856 ;
     RECT  1.183 51.246 1.391 52.434 ;
     RECT  1.399 25.956 1.435 25.974 ;
     RECT  0.463 26.766 1.435 29.214 ;
     RECT  1.651 98.658 1.687 98.676 ;
     RECT  1.651 9.594 1.759 9.612 ;
     RECT  1.723 8.784 1.831 8.802 ;
     RECT  1.759 9.594 1.831 9.954 ;
     RECT  1.255 7.236 1.975 7.254 ;
     RECT  1.687 98.658 2.011 98.982 ;
     RECT  1.111 48.978 2.047 49.464 ;
     RECT  2.011 98.586 2.047 99.414 ;
     RECT  1.687 100.242 2.047 100.26 ;
     RECT  2.047 98.586 2.083 100.26 ;
     RECT  2.119 3.186 2.155 3.204 ;
     RECT  2.155 2.466 2.16 3.204 ;
     RECT  1.975 7.236 2.16 7.794 ;
     RECT  1.831 8.784 2.16 9.954 ;
     RECT  2.083 12.834 2.16 12.852 ;
     RECT  1.435 25.956 2.16 29.214 ;
     RECT  0.535 30.186 2.16 33.534 ;
     RECT  0.671 37.026 2.16 37.584 ;
     RECT  1.211 39.726 2.16 40.824 ;
     RECT  0.103 42.066 2.16 42.714 ;
     RECT  0.275 43.776 2.16 44.442 ;
     RECT  0.535 45.576 2.16 47.142 ;
     RECT  2.047 48.636 2.16 49.464 ;
     RECT  1.391 51.246 2.16 51.264 ;
     RECT  1.391 52.416 2.16 52.434 ;
     RECT  1.283 53.226 2.16 53.514 ;
     RECT  0.203 56.304 2.16 56.322 ;
     RECT  0.203 57.276 2.16 57.564 ;
     RECT  0.203 58.626 2.16 58.644 ;
     RECT  0.535 65.52 2.16 65.538 ;
     RECT  0.535 66.456 2.16 66.474 ;
     RECT  0.535 68.148 2.16 68.94 ;
     RECT  0.103 71.766 2.16 71.784 ;
     RECT  1.147 74.556 2.16 75.726 ;
     RECT  2.119 97.002 2.16 97.02 ;
     RECT  2.083 98.586 2.16 101.214 ;
     RECT  11.479 1.152 11.579 1.17 ;
     RECT  16.015 1.152 16.187 1.17 ;
     RECT  16.195 1.224 16.295 1.242 ;
     RECT  2.16 2.151 19.507 101.259 ;
     RECT  19.507 2.106 20.291 101.259 ;
     RECT  34.483 1.152 34.583 1.17 ;
     RECT  20.291 2.151 42.763 101.259 ;
     RECT  42.763 2.106 43.151 101.259 ;
     RECT  43.151 2.151 50.49 101.259 ;
     RECT  50.49 8.316 50.495 8.532 ;
     RECT  50.49 9.486 50.531 9.504 ;
     RECT  50.49 96.768 50.567 99.054 ;
     RECT  50.567 96.768 50.675 98.946 ;
     RECT  50.49 4.734 50.747 4.824 ;
     RECT  50.49 95.49 50.747 95.814 ;
     RECT  50.495 8.514 50.783 8.532 ;
     RECT  50.49 11.826 50.819 14.094 ;
     RECT  50.819 11.826 50.855 12.384 ;
     RECT  50.819 13.338 50.891 14.094 ;
     RECT  50.675 96.768 50.891 98.748 ;
     RECT  50.49 15.156 50.927 15.894 ;
     RECT  50.855 11.826 50.963 11.844 ;
     RECT  50.927 15.876 50.999 15.894 ;
     RECT  50.891 13.716 51.107 14.094 ;
     RECT  51.107 13.716 51.215 14.004 ;
     RECT  50.891 96.768 51.215 98.676 ;
     RECT  50.747 95.796 51.323 95.814 ;
     RECT  51.215 98.658 51.323 98.676 ;
     RECT  50.49 3.15 51.359 3.744 ;
     RECT  50.49 93.528 51.359 94.428 ;
     RECT  51.215 96.768 51.359 97.326 ;
     RECT  51.359 3.15 51.395 3.168 ;
     RECT  51.359 93.528 51.395 93.546 ;
     RECT  50.747 4.806 51.431 4.824 ;
     RECT  51.359 94.41 51.431 94.428 ;
     RECT  51.359 96.768 51.431 96.786 ;
     RECT  51.215 13.716 51.467 13.734 ;
     RECT  50.49 100.08 51.899 100.098 ;
    LAYER M3 ;
     RECT  46.98 0.043 46.998 0.091 ;
     RECT  51.444 0.043 51.462 0.091 ;
     RECT  31.86 0.091 31.878 0.139 ;
     RECT  48.276 0.091 49.014 0.139 ;
     RECT  50.04 0.091 50.058 0.139 ;
     RECT  5.544 0.091 6.246 0.221 ;
     RECT  13.536 0.091 14.238 0.221 ;
     RECT  24.66 0.091 26.01 0.221 ;
     RECT  35.496 0.091 36.162 0.221 ;
     RECT  48.168 0.139 50.058 0.221 ;
     RECT  3.06 0.091 3.078 0.235 ;
     RECT  3.852 0.091 3.87 0.235 ;
     RECT  15.768 0.091 16.218 0.235 ;
     RECT  37.26 0.091 37.278 0.235 ;
     RECT  38.448 0.091 38.466 0.235 ;
     RECT  30.96 0.091 30.978 0.317 ;
     RECT  29.88 0.091 29.898 0.365 ;
     RECT  37.26 0.235 38.466 0.413 ;
     RECT  4.644 0.091 4.662 0.475 ;
     RECT  5.868 0.221 6.246 0.523 ;
     RECT  7.02 0.091 7.038 0.523 ;
     RECT  8.136 0.091 8.154 0.523 ;
     RECT  10.62 0.091 11.754 0.523 ;
     RECT  15.768 0.235 16.614 0.523 ;
     RECT  43.884 0.091 44.118 0.523 ;
     RECT  46.188 0.091 47.07 0.523 ;
     RECT  49.716 0.221 50.058 0.523 ;
     RECT  50.796 0.091 51.462 0.523 ;
     RECT  3.06 0.235 3.87 0.557 ;
     RECT  5.868 0.523 8.154 0.571 ;
     RECT  14.904 0.523 16.614 0.571 ;
     RECT  19.584 0.091 20.178 0.571 ;
     RECT  21.024 0.091 21.582 0.571 ;
     RECT  26.856 0.235 26.874 0.571 ;
     RECT  36.144 0.221 36.162 0.571 ;
     RECT  40.932 0.091 41.346 0.571 ;
     RECT  42.228 0.523 42.426 0.571 ;
     RECT  43.416 0.523 44.226 0.571 ;
     RECT  19.584 0.571 21.582 0.701 ;
     RECT  19.584 0.701 19.602 1.099 ;
     RECT  28.728 0.091 28.746 1.099 ;
     RECT  48.168 0.221 48.978 1.099 ;
     RECT  49.716 0.523 51.462 1.099 ;
     RECT  3.06 0.557 3.798 1.147 ;
     RECT  5.868 0.571 8.334 1.147 ;
     RECT  14.904 0.571 17.298 1.147 ;
     RECT  18.18 0.091 18.198 1.147 ;
     RECT  20.34 0.701 21.582 1.147 ;
     RECT  23.256 0.091 23.274 1.147 ;
     RECT  24.66 0.221 25.902 1.147 ;
     RECT  26.676 0.571 26.874 1.147 ;
     RECT  31.752 0.139 31.878 1.147 ;
     RECT  34.488 1.099 34.506 1.147 ;
     RECT  34.488 1.147 34.578 1.175 ;
     RECT  12.888 0.523 12.906 1.195 ;
     RECT  46.188 0.523 47.322 1.627 ;
     RECT  48.168 1.099 51.462 1.627 ;
     RECT  10.62 0.523 12.078 1.675 ;
     RECT  12.888 1.195 13.374 1.675 ;
     RECT  14.544 1.147 17.298 1.675 ;
     RECT  18.072 1.147 18.198 1.675 ;
     RECT  30.636 1.147 30.654 1.675 ;
     RECT  31.752 1.147 32.706 1.675 ;
     RECT  33.516 1.099 33.534 1.675 ;
     RECT  2.556 1.147 3.798 1.723 ;
     RECT  4.644 0.475 4.914 1.723 ;
     RECT  5.868 1.147 8.37 1.723 ;
     RECT  10.62 1.675 13.77 1.723 ;
     RECT  14.544 1.675 18.198 1.723 ;
     RECT  19.44 1.099 19.602 1.723 ;
     RECT  20.34 1.147 22.194 1.723 ;
     RECT  23.148 1.147 23.778 1.723 ;
     RECT  24.552 1.147 26.874 1.723 ;
     RECT  27.684 0.571 27.702 1.723 ;
     RECT  28.728 1.099 29.178 1.723 ;
     RECT  30.276 1.675 30.654 1.723 ;
     RECT  31.536 1.675 33.534 1.723 ;
     RECT  36.144 0.571 36.414 1.723 ;
     RECT  38.448 0.413 38.466 1.723 ;
     RECT  40.356 0.571 44.226 1.723 ;
     RECT  46.188 1.627 51.462 1.723 ;
     RECT  34.56 1.175 34.578 1.771 ;
     RECT  35.46 1.723 36.45 1.771 ;
     RECT  2.556 1.723 8.37 1.915 ;
     RECT  2.376 1.915 8.37 2.011 ;
     RECT  10.116 1.723 18.198 2.011 ;
     RECT  19.152 1.723 22.338 2.011 ;
     RECT  23.148 1.723 29.178 2.143 ;
     RECT  30.06 1.723 33.534 2.143 ;
     RECT  2.088 2.011 8.37 2.191 ;
     RECT  10.116 2.011 22.338 2.191 ;
     RECT  23.148 2.143 33.534 2.191 ;
     RECT  34.56 1.771 36.45 2.191 ;
     RECT  37.26 0.413 37.674 2.191 ;
     RECT  38.448 1.723 44.37 2.191 ;
     RECT  45.216 1.723 51.462 2.191 ;
     RECT  2.088 2.191 8.514 2.227 ;
     RECT  9.684 2.191 33.534 2.227 ;
     RECT  34.56 2.191 51.462 2.251 ;
     RECT  2.088 2.227 33.606 2.263 ;
     RECT  34.416 2.251 51.462 2.263 ;
     RECT  2.088 2.263 51.462 3.979 ;
     RECT  1.98 3.979 51.462 5.707 ;
     RECT  1.26 5.707 51.462 7.259 ;
     RECT  1.656 7.259 51.462 9.617 ;
     RECT  1.764 9.617 51.462 9.959 ;
     RECT  2.088 9.959 51.462 12.479 ;
     RECT  16.632 12.479 27.666 12.515 ;
     RECT  16.632 12.515 22.086 12.551 ;
     RECT  29.124 12.479 51.462 12.551 ;
     RECT  16.632 12.551 20.934 12.749 ;
     RECT  29.124 12.551 36.162 12.749 ;
     RECT  37.008 12.551 51.462 12.785 ;
     RECT  30.456 12.749 36.09 12.821 ;
     RECT  2.088 12.479 15.894 12.857 ;
     RECT  17.1 12.749 20.934 12.893 ;
     RECT  2.16 12.857 15.894 12.929 ;
     RECT  17.46 12.893 20.934 12.929 ;
     RECT  30.456 12.821 31.842 12.929 ;
     RECT  2.16 12.929 10.17 13.019 ;
     RECT  10.944 12.929 15.894 13.019 ;
     RECT  17.46 12.929 19.818 13.019 ;
     RECT  22.86 12.515 27.666 13.019 ;
     RECT  32.616 12.821 36.09 13.019 ;
     RECT  2.16 13.019 8.874 13.289 ;
     RECT  37.08 12.785 51.462 13.739 ;
     RECT  2.16 13.289 5.814 13.829 ;
     RECT  37.08 13.739 51.426 13.829 ;
     RECT  2.16 13.829 4.806 14.009 ;
     RECT  37.08 13.829 44.262 14.099 ;
     RECT  45 13.829 51.426 14.171 ;
     RECT  45.615 14.171 51.426 14.369 ;
     RECT  46.728 14.369 51.426 16.331 ;
     RECT  46.728 16.331 49.77 16.529 ;
     RECT  2.16 14.009 4.77 24.511 ;
     RECT  5.796 13.829 5.814 24.511 ;
     RECT  2.16 24.511 5.814 25.591 ;
     RECT  6.84 13.289 8.874 25.591 ;
     RECT  1.404 25.951 1.422 26.401 ;
     RECT  2.16 25.591 8.874 26.401 ;
     RECT  0.252 26.761 0.27 26.827 ;
     RECT  1.404 26.401 8.874 26.827 ;
     RECT  0.108 26.827 0.27 27.197 ;
     RECT  0.144 27.197 0.27 27.679 ;
     RECT  1.152 26.827 8.874 27.679 ;
     RECT  0.144 27.679 8.874 27.707 ;
     RECT  1.404 27.707 8.874 27.715 ;
     RECT  0.144 27.707 0.558 28.109 ;
     RECT  0.144 28.109 0.522 28.381 ;
     RECT  1.404 27.715 8.91 28.561 ;
     RECT  1.404 28.561 9.018 28.687 ;
     RECT  1.404 28.687 9.09 28.921 ;
     RECT  1.404 28.921 9.126 29.029 ;
     RECT  9.9 13.019 10.17 29.029 ;
     RECT  0.108 28.381 0.522 29.309 ;
     RECT  1.404 29.029 10.17 29.501 ;
     RECT  1.44 29.501 10.17 30.173 ;
     RECT  0.18 29.309 0.522 30.181 ;
     RECT  0.108 30.181 0.522 30.365 ;
     RECT  19.692 13.019 19.818 30.541 ;
     RECT  19.692 30.541 19.854 30.605 ;
     RECT  17.46 13.019 18.897 30.667 ;
     RECT  19.692 30.605 19.818 30.667 ;
     RECT  17.46 30.667 19.818 30.713 ;
     RECT  0.144 30.365 0.522 30.721 ;
     RECT  2.088 30.173 10.17 30.919 ;
     RECT  0.144 30.721 0.558 31.435 ;
     RECT  2.088 30.919 10.206 31.459 ;
     RECT  10.944 13.019 14.778 31.459 ;
     RECT  0.144 31.435 0.666 31.801 ;
     RECT  0.108 31.801 0.666 31.901 ;
     RECT  0.108 31.901 0.558 31.997 ;
     RECT  0.108 31.997 0.486 32.809 ;
     RECT  0.108 32.809 0.558 33.773 ;
     RECT  0.108 33.773 0.198 35.033 ;
     RECT  0.108 35.033 0.162 35.069 ;
     RECT  0.144 35.069 0.162 35.213 ;
     RECT  0.108 37.021 0.126 37.339 ;
     RECT  0.108 37.339 0.198 37.561 ;
     RECT  0.108 37.561 0.558 37.624 ;
     RECT  0.108 37.624 0.594 37.633 ;
     RECT  0.108 37.633 0.666 37.709 ;
     RECT  0.108 37.709 0.558 37.757 ;
     RECT  0.108 37.757 0.198 37.997 ;
     RECT  0.108 37.997 0.126 38.045 ;
     RECT  2.088 31.459 14.778 38.155 ;
     RECT  1.98 38.155 14.778 38.333 ;
     RECT  0.144 38.779 0.162 39.115 ;
     RECT  0.144 39.115 0.342 39.208 ;
     RECT  0.108 39.208 0.342 39.217 ;
     RECT  2.088 38.333 14.778 39.217 ;
     RECT  15.696 13.019 15.894 39.217 ;
     RECT  1.152 39.067 1.278 39.341 ;
     RECT  0.108 39.217 0.378 39.991 ;
     RECT  0.108 39.991 0.558 40.109 ;
     RECT  0.144 40.109 0.558 40.603 ;
     RECT  0.144 40.603 1.17 40.637 ;
     RECT  1.152 40.637 1.17 40.801 ;
     RECT  1.152 40.801 1.206 40.937 ;
     RECT  1.152 40.937 1.17 40.973 ;
     RECT  0.144 40.637 0.198 40.981 ;
     RECT  0.108 40.981 0.198 41.009 ;
     RECT  0.108 41.009 0.162 41.032 ;
     RECT  2.088 39.217 15.894 41.143 ;
     RECT  2.088 41.143 15.93 41.521 ;
     RECT  2.088 41.521 16.146 41.611 ;
     RECT  2.088 41.611 16.29 41.791 ;
     RECT  0.144 41.032 0.162 41.899 ;
     RECT  2.088 41.791 16.722 42.025 ;
     RECT  17.46 30.713 18.897 42.025 ;
     RECT  0.144 41.899 0.342 42.061 ;
     RECT  0.108 42.061 0.342 42.413 ;
     RECT  0.108 42.413 0.198 42.509 ;
     RECT  20.7 12.929 20.934 42.763 ;
     RECT  21.708 12.551 22.086 42.763 ;
     RECT  0.108 42.509 0.162 42.893 ;
     RECT  0.144 42.893 0.162 43.229 ;
     RECT  19.692 30.713 19.818 43.339 ;
     RECT  2.088 42.025 18.897 43.609 ;
     RECT  19.62 43.339 19.818 43.609 ;
     RECT  2.088 43.609 19.818 43.681 ;
     RECT  20.7 42.763 22.086 43.681 ;
     RECT  0.18 43.483 0.342 43.963 ;
     RECT  0.144 43.963 0.342 44.347 ;
     RECT  0.108 44.347 0.342 45.197 ;
     RECT  0.108 45.197 0.234 45.677 ;
     RECT  0.144 45.677 0.234 45.931 ;
     RECT  2.088 43.681 22.086 46.075 ;
     RECT  22.86 13.019 26.514 46.075 ;
     RECT  0.144 45.931 0.558 46.205 ;
     RECT  0.144 46.205 0.342 46.54 ;
     RECT  0.108 46.54 0.342 47.011 ;
     RECT  0.108 47.011 0.522 47.119 ;
     RECT  0.108 47.119 0.558 47.147 ;
     RECT  0.144 47.147 0.558 47.371 ;
     RECT  0.144 47.371 0.666 47.501 ;
     RECT  0.144 47.501 0.522 47.693 ;
     RECT  0.144 47.693 0.342 47.885 ;
     RECT  0.18 47.885 0.342 48.173 ;
     RECT  2.088 46.075 26.514 48.427 ;
     RECT  0.18 48.173 0.234 48.619 ;
     RECT  2.052 48.427 26.514 48.659 ;
     RECT  0.144 48.619 0.234 48.892 ;
     RECT  0.108 48.892 0.234 49.003 ;
     RECT  1.116 48.973 1.134 49.085 ;
     RECT  0.108 49.003 0.27 49.277 ;
     RECT  0.108 49.277 0.162 49.469 ;
     RECT  1.152 49.291 1.17 49.517 ;
     RECT  0.108 49.469 0.126 49.661 ;
     RECT  2.088 48.659 26.514 49.771 ;
     RECT  1.98 49.771 26.514 50.251 ;
     RECT  1.368 50.251 26.514 50.381 ;
     RECT  0.324 50.731 0.342 50.827 ;
     RECT  2.088 50.381 26.514 51.241 ;
     RECT  27.252 13.019 27.666 51.241 ;
     RECT  1.152 51.169 1.17 51.269 ;
     RECT  0.108 50.827 0.342 51.341 ;
     RECT  0.144 51.341 0.342 51.677 ;
     RECT  2.088 51.241 27.666 51.931 ;
     RECT  1.188 51.931 27.666 51.98 ;
     RECT  1.26 51.98 27.666 52.253 ;
     RECT  1.44 52.253 27.666 52.349 ;
     RECT  0.144 51.677 0.234 52.411 ;
     RECT  2.088 52.349 27.666 52.411 ;
     RECT  0.108 52.411 0.234 52.445 ;
     RECT  2.088 52.411 27.846 53.131 ;
     RECT  0.108 52.445 0.198 53.221 ;
     RECT  2.088 53.131 28.134 53.543 ;
     RECT  29.124 12.749 29.697 53.543 ;
     RECT  0.108 53.221 0.558 53.645 ;
     RECT  0.216 53.645 0.558 53.741 ;
     RECT  1.188 53.803 1.206 53.833 ;
     RECT  1.188 53.833 1.278 53.861 ;
     RECT  1.26 53.861 1.278 53.885 ;
     RECT  0.216 53.741 0.342 54.125 ;
     RECT  0.216 54.125 0.234 54.365 ;
     RECT  2.088 53.543 29.697 54.667 ;
     RECT  30.456 12.929 30.726 54.667 ;
     RECT  0.144 54.859 0.162 55.147 ;
     RECT  0.144 55.147 0.234 55.211 ;
     RECT  1.152 54.859 1.17 55.387 ;
     RECT  1.152 55.387 1.278 55.517 ;
     RECT  2.088 54.667 30.726 56.029 ;
     RECT  0.144 55.211 0.162 56.092 ;
     RECT  1.152 55.517 1.17 56.093 ;
     RECT  2.088 56.029 30.762 56.191 ;
     RECT  2.088 56.191 30.798 56.347 ;
     RECT  31.644 12.929 31.842 56.347 ;
     RECT  0.108 56.092 0.198 56.525 ;
     RECT  0.216 56.683 0.342 56.813 ;
     RECT  0.216 56.813 0.234 57.005 ;
     RECT  2.088 56.347 31.842 57.307 ;
     RECT  32.616 13.019 32.886 57.307 ;
     RECT  0.144 57.271 0.198 57.541 ;
     RECT  2.088 57.307 32.886 58.555 ;
     RECT  33.624 13.019 36.09 58.555 ;
     RECT  0.108 57.541 0.198 59.371 ;
     RECT  0.108 59.371 0.342 59.531 ;
     RECT  0.144 59.531 0.342 60.283 ;
     RECT  0.108 60.283 0.342 60.317 ;
     RECT  0.108 60.317 0.234 60.341 ;
     RECT  0.144 60.341 0.234 60.365 ;
     RECT  2.088 58.555 36.09 61.099 ;
     RECT  0.144 60.365 0.162 61.243 ;
     RECT  0.144 61.243 0.234 61.969 ;
     RECT  2.088 61.099 36.27 61.969 ;
     RECT  37.08 14.099 44.19 61.969 ;
     RECT  0.108 61.969 0.234 62.155 ;
     RECT  0.108 62.155 0.342 62.384 ;
     RECT  0.144 62.384 0.342 62.477 ;
     RECT  0.144 62.477 0.234 63.005 ;
     RECT  0.144 63.005 0.162 64.027 ;
     RECT  0.144 64.027 0.234 64.109 ;
     RECT  0.216 64.109 0.234 64.267 ;
     RECT  0.216 64.267 0.342 64.589 ;
     RECT  0.324 64.589 0.342 64.973 ;
     RECT  0.54 65.515 0.558 65.597 ;
     RECT  2.088 61.969 44.19 66.427 ;
     RECT  1.98 66.427 44.19 66.605 ;
     RECT  0.54 66.451 0.558 66.845 ;
     RECT  0.144 66.859 0.342 67.373 ;
     RECT  0.144 67.373 0.162 67.709 ;
     RECT  0.504 68.143 0.558 68.477 ;
     RECT  0.504 68.477 0.522 68.573 ;
     RECT  0.108 68.917 0.126 69.053 ;
     RECT  0.324 70.699 0.342 70.795 ;
     RECT  0.108 70.795 0.342 70.907 ;
     RECT  0.18 70.907 0.342 70.925 ;
     RECT  0.18 70.925 0.27 71.117 ;
     RECT  0.108 71.761 0.126 71.837 ;
     RECT  0.144 72.763 0.162 73.228 ;
     RECT  0.108 73.228 0.198 73.421 ;
     RECT  0.216 73.675 0.342 73.805 ;
     RECT  1.26 73.771 1.278 73.867 ;
     RECT  1.152 73.867 1.278 73.901 ;
     RECT  1.152 73.901 1.17 73.997 ;
     RECT  0.216 73.805 0.234 74.045 ;
     RECT  0.108 74.551 0.126 74.717 ;
     RECT  1.152 75.271 1.17 75.569 ;
     RECT  0.108 75.541 0.126 75.703 ;
     RECT  0.108 75.703 0.558 75.917 ;
     RECT  0.108 75.917 0.342 76.493 ;
     RECT  1.152 76.747 1.17 76.877 ;
     RECT  0.108 76.493 0.234 77.153 ;
     RECT  0.144 77.153 0.234 77.357 ;
     RECT  0.216 77.357 0.234 77.405 ;
     RECT  46.728 16.529 49.59 78.241 ;
     RECT  50.724 16.331 51.426 78.241 ;
     RECT  45.615 14.369 45.954 78.331 ;
     RECT  45.504 78.331 45.954 78.601 ;
     RECT  45.468 78.601 45.954 78.979 ;
     RECT  2.088 66.605 44.19 79.015 ;
     RECT  45.324 78.979 45.954 79.015 ;
     RECT  2.088 79.015 45.954 81.751 ;
     RECT  46.728 78.241 51.426 81.751 ;
     RECT  2.088 81.751 51.426 94.433 ;
     RECT  2.088 94.433 51.318 95.513 ;
     RECT  51.3 95.513 51.318 95.819 ;
     RECT  51.408 96.763 51.426 96.835 ;
     RECT  2.088 95.513 50.382 96.907 ;
     RECT  2.052 96.907 50.382 96.961 ;
     RECT  2.052 96.961 50.562 97.033 ;
     RECT  51.3 96.835 51.426 97.033 ;
     RECT  2.052 97.033 51.426 98.581 ;
     RECT  2.016 98.581 51.426 98.653 ;
     RECT  1.656 98.653 51.426 99.869 ;
     RECT  1.692 99.869 51.426 100.075 ;
     RECT  1.692 100.075 51.894 100.301 ;
     RECT  2.088 100.301 51.894 100.925 ;
     RECT  2.088 100.925 51.21 101.039 ;
     RECT  4.464 101.039 6.282 101.069 ;
     RECT  4.464 101.069 5.238 101.111 ;
     RECT  7.056 101.039 10.206 101.111 ;
     RECT  10.944 101.039 14.562 101.111 ;
     RECT  27.684 101.039 31.986 101.111 ;
     RECT  32.94 101.039 51.21 101.111 ;
     RECT  4.464 101.111 4.482 101.117 ;
     RECT  2.088 101.039 3.726 101.219 ;
     RECT  5.22 101.111 5.238 101.219 ;
     RECT  5.976 101.069 6.282 101.219 ;
     RECT  7.488 101.111 10.206 101.219 ;
     RECT  15.3 101.039 26.946 101.219 ;
     RECT  27.684 101.111 29.862 101.219 ;
     RECT  30.708 101.111 31.986 101.219 ;
     RECT  45.324 101.111 51.21 101.219 ;
     RECT  15.3 101.219 26.838 101.261 ;
     RECT  7.488 101.219 8.097 101.267 ;
     RECT  9.612 101.219 10.206 101.357 ;
     RECT  15.336 101.261 26.838 101.357 ;
     RECT  30.708 101.219 31.914 101.357 ;
     RECT  33.012 101.111 44.442 101.357 ;
     RECT  9.648 101.357 10.206 101.405 ;
     RECT  10.944 101.111 14.31 101.405 ;
     RECT  15.372 101.357 26.838 101.405 ;
     RECT  27.684 101.219 29.754 101.405 ;
     RECT  30.744 101.357 31.914 101.405 ;
     RECT  33.048 101.357 44.442 101.405 ;
     RECT  45.324 101.219 48.042 101.405 ;
     RECT  2.304 101.219 3.726 101.453 ;
     RECT  7.488 101.267 7.506 101.453 ;
     RECT  9.648 101.405 9.882 101.453 ;
     RECT  10.944 101.405 10.962 101.453 ;
     RECT  11.916 101.405 14.202 101.453 ;
     RECT  15.372 101.405 18.09 101.453 ;
     RECT  19.26 101.405 23.922 101.453 ;
     RECT  24.66 101.405 25.146 101.453 ;
     RECT  26.424 101.405 26.838 101.453 ;
     RECT  27.9 101.405 27.918 101.453 ;
     RECT  28.656 101.405 28.674 101.453 ;
     RECT  29.556 101.405 29.574 101.453 ;
     RECT  30.744 101.405 30.762 101.453 ;
     RECT  31.896 101.405 31.914 101.453 ;
     RECT  33.048 101.405 33.426 101.453 ;
     RECT  34.776 101.405 36.486 101.453 ;
     RECT  37.44 101.405 38.718 101.453 ;
     RECT  40.032 101.405 43.326 101.453 ;
     RECT  44.424 101.405 44.442 101.453 ;
     RECT  45.576 101.405 48.042 101.453 ;
     RECT  34.776 101.453 34.794 101.501 ;
     RECT  40.752 101.453 41.562 101.501 ;
     RECT  46.116 101.453 46.818 101.501 ;
     RECT  12.924 101.453 13.626 101.549 ;
     RECT  2.556 101.453 3.114 102.077 ;
     RECT  12.924 101.549 12.942 102.077 ;
     RECT  17.064 101.453 17.622 102.077 ;
     RECT  48.96 101.219 51.21 102.077 ;
     RECT  46.116 101.501 46.134 102.605 ;
     RECT  48.96 102.077 49.41 102.653 ;
     RECT  50.436 102.077 51.21 102.701 ;
     RECT  17.064 102.077 17.082 103.147 ;
     RECT  17.064 103.147 17.19 103.195 ;
     RECT  47.7 103.195 47.718 103.291 ;
     RECT  17.064 103.195 17.298 103.325 ;
     RECT  46.656 103.147 46.674 103.325 ;
     RECT  22.284 103.291 22.59 103.339 ;
     RECT  47.628 103.291 47.718 103.339 ;
     RECT  17.064 103.325 17.19 103.373 ;
     RECT  35.856 101.453 35.91 103.387 ;
     RECT  39.996 103.195 40.014 103.387 ;
     RECT  40.752 101.501 40.77 103.387 ;
     RECT  47.52 103.339 47.718 103.387 ;
     RECT  48.96 102.653 49.05 103.387 ;
     RECT  47.52 103.387 49.05 103.421 ;
     RECT  26.604 103.387 26.622 103.435 ;
     RECT  38.448 103.387 38.466 103.435 ;
     RECT  47.52 103.421 48.258 103.435 ;
     RECT  49.032 103.421 49.05 103.435 ;
     RECT  17.172 103.373 17.19 103.469 ;
     RECT  22.284 103.339 22.77 103.469 ;
     RECT  35.856 103.387 36.306 103.469 ;
     RECT  46.836 103.435 48.258 103.469 ;
     RECT  22.752 103.469 22.77 103.517 ;
     RECT  26.604 103.435 26.73 103.517 ;
     RECT  39.42 103.387 40.77 103.517 ;
     RECT  47.7 103.469 48.258 103.517 ;
     RECT  2.34 103.339 2.358 103.565 ;
     RECT  3.096 102.077 3.114 103.565 ;
     RECT  9.108 103.435 9.126 103.565 ;
     RECT  10.476 103.435 10.494 103.565 ;
     RECT  14.652 103.435 14.67 103.565 ;
     RECT  21.528 101.453 21.546 103.565 ;
     RECT  24.912 101.453 24.93 103.565 ;
     RECT  26.712 103.517 26.73 103.565 ;
     RECT  27.756 103.387 27.774 103.565 ;
     RECT  29.916 103.435 29.934 103.565 ;
     RECT  32.472 103.435 32.49 103.565 ;
     RECT  35.892 103.469 36.306 103.565 ;
     RECT  38.268 103.435 38.574 103.565 ;
     RECT  40.068 103.517 40.77 103.565 ;
     RECT  41.544 101.501 41.562 103.565 ;
     RECT  43.164 103.435 43.182 103.565 ;
     RECT  44.604 103.435 44.622 103.565 ;
     RECT  46.836 103.469 46.854 103.565 ;
     RECT  47.7 103.517 47.718 103.565 ;
     RECT  49.032 103.435 49.77 103.565 ;
     RECT  50.508 102.701 51.21 103.565 ;
    LAYER M4 ;
     RECT  0.06 26.976 0.097 77.4 ;
     RECT  0.097 26.832 0.245 77.4 ;
     RECT  0.277 99.744 0.469 99.768 ;
     RECT  0.469 99.744 0.661 99.864 ;
     RECT  0.245 26.832 1.181 77.352 ;
     RECT  0.949 6 1.205 6.024 ;
     RECT  1.205 5.712 1.289 6.024 ;
     RECT  0.757 10.32 1.429 10.344 ;
     RECT  1.045 11.472 1.429 11.496 ;
     RECT  0.661 99.216 1.429 99.864 ;
     RECT  0.949 100.896 1.429 100.92 ;
     RECT  1.333 8.544 1.525 8.568 ;
     RECT  1.429 99.216 1.525 100.92 ;
     RECT  1.141 7.44 1.601 7.464 ;
     RECT  1.289 6 1.717 6.024 ;
     RECT  1.525 98.736 1.813 100.92 ;
     RECT  0.853 2.88 2.077 2.904 ;
     RECT  1.429 10.32 2.149 11.496 ;
     RECT  2.077 2.016 2.197 2.904 ;
     RECT  1.925 3.984 2.197 4.008 ;
     RECT  1.717 6 2.197 6.312 ;
     RECT  1.601 7.44 2.197 7.512 ;
     RECT  1.861 13.104 2.245 13.128 ;
     RECT  2.197 6 2.252 7.512 ;
     RECT  1.525 8.544 2.252 8.616 ;
     RECT  2.149 10.272 2.252 11.496 ;
     RECT  2.197 2.016 2.293 4.008 ;
     RECT  1.181 26.976 2.293 77.352 ;
     RECT  1.813 98.64 2.293 100.92 ;
     RECT  1.189 102.048 2.293 102.072 ;
     RECT  2.285 103.536 2.293 103.56 ;
     RECT  2.293 103.44 2.329 103.56 ;
     RECT  2.293 1.968 2.348 4.008 ;
     RECT  2.341 0.336 2.389 0.36 ;
     RECT  2.348 1.92 2.408 4.008 ;
     RECT  2.252 6 2.408 8.616 ;
     RECT  2.252 10.176 2.408 11.496 ;
     RECT  2.245 13.104 2.408 13.176 ;
     RECT  2.293 26.832 2.408 77.352 ;
     RECT  2.041 96.912 2.408 96.936 ;
     RECT  2.293 98.64 2.408 102.072 ;
     RECT  2.389 0.24 2.437 0.36 ;
     RECT  2.408 1.92 2.437 102.072 ;
     RECT  2.437 0.24 2.585 102.072 ;
     RECT  2.585 1.728 2.627 101.448 ;
     RECT  2.329 103.344 2.629 103.56 ;
     RECT  2.627 1.728 2.704 101.262 ;
     RECT  2.704 26.736 2.729 74.424 ;
     RECT  2.704 10.704 2.765 11.448 ;
     RECT  2.704 13.104 2.765 13.128 ;
     RECT  2.765 10.704 2.819 10.728 ;
     RECT  2.629 103.296 2.819 103.56 ;
     RECT  2.729 26.736 2.837 74.136 ;
     RECT  2.819 103.392 2.867 103.56 ;
     RECT  2.837 26.736 2.873 64.968 ;
     RECT  2.704 98.064 2.873 101.262 ;
     RECT  2.585 0.24 3.005 0.456 ;
     RECT  2.704 1.728 3.089 7.464 ;
     RECT  2.873 99.216 3.089 101.262 ;
     RECT  2.867 103.488 3.125 103.56 ;
     RECT  3.089 1.728 3.203 6.888 ;
     RECT  2.704 75.984 3.341 77.352 ;
     RECT  3.089 99.216 3.341 99.72 ;
     RECT  3.203 4.56 3.539 6.888 ;
     RECT  3.539 4.56 3.557 5.256 ;
     RECT  3.089 100.896 3.653 101.262 ;
     RECT  3.125 103.488 3.683 103.512 ;
     RECT  3.653 100.896 3.737 101.448 ;
     RECT  3.005 0.096 3.769 0.456 ;
     RECT  3.769 0.096 3.881 0.552 ;
     RECT  2.837 66.528 3.949 67.848 ;
     RECT  2.837 68.88 3.953 74.136 ;
     RECT  3.539 6.288 4.025 6.888 ;
     RECT  2.873 26.736 4.129 64.776 ;
     RECT  3.341 75.984 4.133 77.16 ;
     RECT  3.341 99.504 4.237 99.72 ;
     RECT  3.737 100.896 4.237 101.112 ;
     RECT  4.025 6.72 4.301 6.888 ;
     RECT  4.069 7.968 4.301 7.992 ;
     RECT  3.949 66.48 4.309 67.848 ;
     RECT  3.953 68.88 4.309 71.112 ;
     RECT  3.781 9.696 4.373 9.72 ;
     RECT  3.973 10.848 4.373 10.872 ;
     RECT  4.129 26.016 4.385 64.776 ;
     RECT  3.953 72.768 4.453 74.136 ;
     RECT  4.373 9.696 4.457 10.872 ;
     RECT  4.237 99.504 4.493 101.112 ;
     RECT  4.301 6.72 4.549 7.992 ;
     RECT  4.549 6.72 4.565 8.568 ;
     RECT  4.493 99.504 4.595 101.064 ;
     RECT  4.385 26.736 4.597 64.776 ;
     RECT  3.203 1.728 4.645 3.432 ;
     RECT  3.557 5.088 4.645 5.256 ;
     RECT  4.597 26.736 4.745 65.016 ;
     RECT  4.745 26.784 4.789 65.016 ;
     RECT  3.881 0.096 4.885 0.216 ;
     RECT  4.453 72.768 4.885 74.76 ;
     RECT  4.645 1.728 4.921 5.256 ;
     RECT  4.133 76.08 4.921 77.16 ;
     RECT  4.645 103.488 4.933 103.512 ;
     RECT  4.813 96.912 4.961 96.936 ;
     RECT  4.933 103.392 5.027 103.512 ;
     RECT  4.565 8.544 5.105 8.568 ;
     RECT  5.027 103.392 5.123 103.416 ;
     RECT  4.921 76.08 5.125 77.592 ;
     RECT  2.873 98.064 5.125 98.088 ;
     RECT  4.595 99.504 5.125 99.72 ;
     RECT  5.125 98.064 5.212 99.72 ;
     RECT  5.125 75.936 5.213 77.592 ;
     RECT  4.457 10.848 5.249 10.872 ;
     RECT  5.212 98.064 5.411 98.088 ;
     RECT  4.921 1.728 5.413 5.736 ;
     RECT  4.565 6.72 5.413 7.464 ;
     RECT  5.213 76.224 5.461 77.592 ;
     RECT  4.885 72.768 5.465 74.856 ;
     RECT  5.413 1.728 5.501 7.464 ;
     RECT  4.309 66.48 5.501 71.112 ;
     RECT  4.213 12 5.557 12.024 ;
     RECT  5.501 66.48 5.573 67.848 ;
     RECT  5.501 68.88 5.609 71.112 ;
     RECT  5.557 12 5.645 12.552 ;
     RECT  5.465 72.768 5.645 74.472 ;
     RECT  5.645 12.528 5.681 12.552 ;
     RECT  4.595 100.896 5.681 101.064 ;
     RECT  5.645 74.112 5.717 74.472 ;
     RECT  4.885 0.096 5.749 0.504 ;
     RECT  5.501 1.728 5.749 6.888 ;
     RECT  5.212 99.552 5.749 99.72 ;
     RECT  4.789 26.784 5.9 65.4 ;
     RECT  5.573 66.48 5.9 67.512 ;
     RECT  5.717 74.448 5.933 74.472 ;
     RECT  5.9 26.784 6.005 67.512 ;
     RECT  5.645 72.768 6.037 73.032 ;
     RECT  5.681 100.896 6.041 101.016 ;
     RECT  5.749 99.552 6.085 99.768 ;
     RECT  6.041 100.896 6.085 100.968 ;
     RECT  5.461 76.224 6.221 77.928 ;
     RECT  6.085 99.552 6.221 100.968 ;
     RECT  6.005 26.784 6.325 64.776 ;
     RECT  6.005 66.192 6.365 67.512 ;
     RECT  6.421 10.848 6.617 10.872 ;
     RECT  6.649 12 6.733 12.024 ;
     RECT  5.749 0.096 6.797 6.888 ;
     RECT  6.037 72.288 6.865 73.032 ;
     RECT  6.221 99.552 6.901 100.92 ;
     RECT  6.797 0.096 7.049 1.128 ;
     RECT  7.049 0.144 7.091 1.128 ;
     RECT  6.901 99.504 7.285 100.92 ;
     RECT  7.141 9.168 7.429 9.192 ;
     RECT  6.325 26.448 7.477 64.776 ;
     RECT  7.285 99.456 7.477 100.92 ;
     RECT  7.477 99.456 7.561 101.448 ;
     RECT  7.477 96.96 7.585 96.984 ;
     RECT  7.525 103.44 7.621 103.464 ;
     RECT  7.561 99.456 7.669 101.262 ;
     RECT  7.621 103.44 7.669 103.512 ;
     RECT  6.797 2.208 7.808 6.888 ;
     RECT  7.429 9.12 7.808 9.192 ;
     RECT  7.477 26.448 7.808 64.968 ;
     RECT  6.365 66.192 7.808 67.272 ;
     RECT  5.609 69.648 7.808 71.112 ;
     RECT  6.865 72.288 7.808 73.512 ;
     RECT  7.261 74.64 7.808 74.664 ;
     RECT  6.221 76.224 7.808 77.4 ;
     RECT  7.429 79.536 7.808 79.56 ;
     RECT  5.365 86.208 7.808 86.232 ;
     RECT  7.585 96.912 7.808 96.984 ;
     RECT  7.669 99.168 7.808 101.262 ;
     RECT  7.808 2.148 7.909 101.262 ;
     RECT  7.669 103.392 7.955 103.512 ;
     RECT  7.091 0.144 8.101 0.6 ;
     RECT  7.909 1.728 8.101 101.262 ;
     RECT  8.101 0.144 8.104 101.262 ;
     RECT  8.104 0.144 8.125 7.992 ;
     RECT  8.125 0.096 8.237 7.992 ;
     RECT  8.237 0.096 8.243 1.176 ;
     RECT  8.104 81.696 8.243 82.68 ;
     RECT  8.104 30.096 8.345 75.048 ;
     RECT  8.243 0.144 8.381 1.176 ;
     RECT  8.243 82.272 8.417 82.68 ;
     RECT  8.237 2.304 8.425 7.992 ;
     RECT  8.381 0.144 8.435 0.312 ;
     RECT  8.345 30.432 8.453 75.048 ;
     RECT  8.425 7.968 8.597 7.992 ;
     RECT  8.425 2.304 8.819 6.936 ;
     RECT  8.104 76.176 8.849 78.36 ;
     RECT  7.955 103.44 8.869 103.512 ;
     RECT  8.104 79.536 8.913 80.328 ;
     RECT  8.435 0.144 8.963 0.168 ;
     RECT  8.453 30.576 9.065 75.048 ;
     RECT  8.417 82.272 9.137 82.296 ;
     RECT  8.869 103.44 9.158 103.56 ;
     RECT  9.065 66.096 9.169 75.048 ;
     RECT  9.169 66.096 9.203 75.096 ;
     RECT  9.158 103.44 9.253 103.512 ;
     RECT  9.203 66.432 9.277 75.096 ;
     RECT  8.913 80.304 9.277 80.328 ;
     RECT  9.065 30.576 9.317 65.016 ;
     RECT  9.253 103.392 9.347 103.512 ;
     RECT  8.104 99.168 9.349 101.064 ;
     RECT  9.317 33.888 9.425 65.016 ;
     RECT  9.347 103.392 9.443 103.416 ;
     RECT  9.317 30.576 9.461 32.856 ;
     RECT  8.819 2.304 9.529 3.576 ;
     RECT  9.277 66.432 9.565 75.192 ;
     RECT  8.849 76.176 9.565 78.168 ;
     RECT  8.819 4.56 9.569 6.936 ;
     RECT  9.461 32.208 9.569 32.856 ;
     RECT  9.241 9.696 9.641 9.72 ;
     RECT  9.461 30.576 9.641 31.176 ;
     RECT  9.529 2.256 9.673 3.576 ;
     RECT  9.425 33.936 9.677 65.016 ;
     RECT  9.349 99.168 9.779 101.448 ;
     RECT  9.733 0.192 9.781 0.216 ;
     RECT  9.685 9.072 9.827 9.192 ;
     RECT  9.673 2.208 9.877 3.576 ;
     RECT  9.779 101.376 9.893 101.448 ;
     RECT  9.877 1.728 9.925 3.576 ;
     RECT  9.569 4.56 9.925 6.888 ;
     RECT  9.569 32.832 10.001 32.856 ;
     RECT  9.565 66.432 10.069 78.168 ;
     RECT  9.677 34.176 10.115 65.016 ;
     RECT  9.925 1.728 10.145 6.888 ;
     RECT  10.145 2.256 10.153 6.888 ;
     RECT  9.277 80.304 10.177 80.904 ;
     RECT  10.177 80.304 10.213 81 ;
     RECT  8.104 86.064 10.217 86.232 ;
     RECT  10.213 80.304 10.309 81.72 ;
     RECT  10.069 66.432 10.361 78.648 ;
     RECT  10.153 3.408 10.397 6.888 ;
     RECT  10.309 80.16 10.397 81.72 ;
     RECT  10.261 103.248 10.421 103.272 ;
     RECT  9.779 99.168 10.477 100.344 ;
     RECT  10.421 103.248 10.505 103.56 ;
     RECT  10.357 12 10.597 12.024 ;
     RECT  9.781 0.192 10.609 0.408 ;
     RECT  10.115 34.176 10.649 64.152 ;
     RECT  10.505 103.248 10.691 103.512 ;
     RECT  10.597 12 10.721 12.552 ;
     RECT  10.397 80.304 10.721 81.72 ;
     RECT  10.477 99.168 10.748 99.768 ;
     RECT  10.609 0.096 10.753 0.408 ;
     RECT  10.361 71.376 10.753 78.648 ;
     RECT  10.649 45.36 10.757 64.152 ;
     RECT  10.721 80.304 10.793 81.144 ;
     RECT  10.757 45.36 10.829 63 ;
     RECT  10.757 64.128 10.829 64.152 ;
     RECT  10.748 99.024 10.835 99.768 ;
     RECT  9.827 9.12 10.865 9.192 ;
     RECT  9.893 101.376 10.933 101.4 ;
     RECT  10.793 80.304 10.937 81 ;
     RECT  10.753 0.096 10.979 0.552 ;
     RECT  10.691 103.344 11.123 103.512 ;
     RECT  10.153 2.256 11.124 2.424 ;
     RECT  10.397 3.408 11.124 6.312 ;
     RECT  11.113 96.912 11.225 96.936 ;
     RECT  11.124 2.256 11.228 6.312 ;
     RECT  10.649 34.176 11.297 44.232 ;
     RECT  10.829 45.456 11.297 63 ;
     RECT  11.228 1.68 11.315 6.312 ;
     RECT  11.123 103.44 11.315 103.512 ;
     RECT  10.835 99.168 11.341 99.768 ;
     RECT  10.885 83.808 11.365 83.832 ;
     RECT  11.341 99.552 11.411 99.768 ;
     RECT  11.315 103.488 11.411 103.512 ;
     RECT  10.753 71.376 11.437 79.32 ;
     RECT  10.937 80.304 11.437 80.904 ;
     RECT  11.365 83.232 11.437 83.832 ;
     RECT  11.297 45.456 11.441 62.328 ;
     RECT  11.411 99.696 11.513 99.768 ;
     RECT  11.513 99.744 11.555 99.768 ;
     RECT  11.441 56.208 11.621 62.328 ;
     RECT  10.933 101.376 11.656 101.448 ;
     RECT  10.865 9.12 11.657 9.144 ;
     RECT  11.297 34.752 11.729 44.232 ;
     RECT  10.721 12 11.749 12.024 ;
     RECT  11.656 101.328 11.749 101.448 ;
     RECT  11.729 37.056 11.765 44.232 ;
     RECT  11.729 34.752 11.795 35.832 ;
     RECT  11.749 100.896 11.797 101.448 ;
     RECT  11.315 2.256 11.804 6.312 ;
     RECT  10.361 66.432 11.837 70.344 ;
     RECT  11.621 56.208 11.873 59.064 ;
     RECT  11.437 82.32 11.893 83.832 ;
     RECT  11.837 66.672 11.941 70.344 ;
     RECT  11.437 71.376 11.941 80.904 ;
     RECT  11.765 37.056 11.945 44.088 ;
     RECT  10.217 86.208 11.945 86.232 ;
     RECT  11.941 66.672 11.977 80.904 ;
     RECT  11.893 82.32 11.98 84.408 ;
     RECT  10.979 0.096 11.987 0.216 ;
     RECT  11.804 2.256 11.987 6.84 ;
     RECT  11.795 35.184 12.017 35.832 ;
     RECT  11.441 45.456 12.089 55.224 ;
     RECT  11.873 56.208 12.125 58.776 ;
     RECT  12.017 35.184 12.161 35.208 ;
     RECT  11.987 2.256 12.325 5.688 ;
     RECT  11.977 66.672 12.325 81 ;
     RECT  11.98 82.32 12.325 84.072 ;
     RECT  12.325 1.728 12.448 5.688 ;
     RECT  11.797 100.08 12.661 101.448 ;
     RECT  12.581 9.696 12.668 9.72 ;
     RECT  12.661 99.744 12.913 101.448 ;
     RECT  11.987 6.816 12.949 6.84 ;
     RECT  12.448 1.68 12.997 5.688 ;
     RECT  12.949 6.768 12.997 6.84 ;
     RECT  12.325 66.672 13.045 84.072 ;
     RECT  12.049 0.528 13.093 0.552 ;
     RECT  12.997 1.68 13.093 6.84 ;
     RECT  11.893 7.968 13.093 7.992 ;
     RECT  12.668 9.072 13.093 9.72 ;
     RECT  12.913 99.744 13.093 102.072 ;
     RECT  13.093 99.168 13.139 102.072 ;
     RECT  13.093 0.528 13.208 6.84 ;
     RECT  13.093 7.968 13.208 9.72 ;
     RECT  11.749 11.424 13.208 12.024 ;
     RECT  9.641 30.576 13.208 30.6 ;
     RECT  11.945 37.056 13.208 41.448 ;
     RECT  11.945 42.432 13.208 44.088 ;
     RECT  12.089 45.744 13.208 55.224 ;
     RECT  12.125 56.208 13.208 57.432 ;
     RECT  12.125 58.512 13.208 58.776 ;
     RECT  11.621 60.528 13.208 62.328 ;
     RECT  13.045 66.528 13.208 84.072 ;
     RECT  12.733 96.912 13.208 96.936 ;
     RECT  13.139 99.168 13.208 101.544 ;
     RECT  13.285 103.296 13.381 103.32 ;
     RECT  13.208 0.528 13.429 101.544 ;
     RECT  13.381 103.296 13.429 103.416 ;
     RECT  13.429 0.336 13.484 101.544 ;
     RECT  13.484 0.096 13.504 101.544 ;
     RECT  13.429 103.296 13.619 103.512 ;
     RECT  13.504 99.264 13.637 101.544 ;
     RECT  13.504 0.096 13.667 8.76 ;
     RECT  13.637 99.264 13.667 101.448 ;
     RECT  13.667 0.096 13.673 8.616 ;
     RECT  13.504 38.736 13.745 44.088 ;
     RECT  13.673 0.096 13.781 8.52 ;
     RECT  13.781 6.864 13.811 8.52 ;
     RECT  13.781 0.096 13.859 5.832 ;
     RECT  13.745 38.784 13.897 44.088 ;
     RECT  13.504 67.104 13.925 81.144 ;
     RECT  13.925 67.104 13.961 69.768 ;
     RECT  13.504 10.8 14.003 10.872 ;
     RECT  13.961 67.104 14.141 69.528 ;
     RECT  14.141 67.104 14.147 68.184 ;
     RECT  14.147 67.44 14.213 68.184 ;
     RECT  13.504 84.912 14.213 84.936 ;
     RECT  14.141 69.168 14.321 69.528 ;
     RECT  14.003 10.848 14.393 10.872 ;
     RECT  14.321 69.216 14.501 69.48 ;
     RECT  13.897 39.072 14.531 44.088 ;
     RECT  14.531 39.936 14.537 44.088 ;
     RECT  13.619 103.344 14.579 103.512 ;
     RECT  13.925 70.848 14.588 81.144 ;
     RECT  13.504 82.176 14.588 82.488 ;
     RECT  14.579 103.44 14.626 103.512 ;
     RECT  14.588 70.848 14.675 82.488 ;
     RECT  14.626 103.44 14.771 103.56 ;
     RECT  13.667 99.504 14.773 101.448 ;
     RECT  14.771 103.44 14.819 103.464 ;
     RECT  13.859 2.832 14.857 5.832 ;
     RECT  13.811 6.864 14.857 7.992 ;
     RECT  14.773 99.456 14.86 101.448 ;
     RECT  14.675 70.848 14.963 80.904 ;
     RECT  14.857 2.832 15.077 7.992 ;
     RECT  14.86 99.504 15.113 101.448 ;
     RECT  15.137 9.696 15.221 9.72 ;
     RECT  15.077 6.72 15.257 7.992 ;
     RECT  15.257 6.72 15.365 7.176 ;
     RECT  15.077 2.832 15.445 5.736 ;
     RECT  13.859 0.096 15.469 1.752 ;
     RECT  15.445 2.736 15.469 5.736 ;
     RECT  15.469 0.096 15.617 5.736 ;
     RECT  14.537 40.08 15.635 44.088 ;
     RECT  14.675 82.272 15.721 82.488 ;
     RECT  15.635 40.416 15.731 44.088 ;
     RECT  15.731 40.896 15.744 44.088 ;
     RECT  15.744 41.232 15.779 44.088 ;
     RECT  15.113 99.552 15.797 101.448 ;
     RECT  14.963 70.848 15.973 80.856 ;
     RECT  14.213 68.16 15.977 68.184 ;
     RECT  15.721 82.176 16.021 82.488 ;
     RECT  15.617 1.728 16.069 5.736 ;
     RECT  15.365 6.72 16.069 6.888 ;
     RECT  16.021 103.488 16.069 103.512 ;
     RECT  15.797 99.552 16.124 99.768 ;
     RECT  16.069 103.392 16.165 103.512 ;
     RECT  16.021 82.176 16.193 82.776 ;
     RECT  15.617 0.096 16.229 0.264 ;
     RECT  16.189 96.912 16.301 96.936 ;
     RECT  16.124 99.504 16.405 99.768 ;
     RECT  15.779 41.616 16.499 44.088 ;
     RECT  16.069 1.728 16.517 6.888 ;
     RECT  15.973 70.848 16.517 81.144 ;
     RECT  16.405 99.168 16.517 99.768 ;
     RECT  16.517 70.848 16.553 80.328 ;
     RECT  16.501 12 16.661 12.024 ;
     RECT  14.501 69.456 16.693 69.48 ;
     RECT  16.517 2.928 16.697 6.888 ;
     RECT  16.553 70.848 16.697 80.28 ;
     RECT  16.499 41.952 16.733 44.088 ;
     RECT  16.517 99.504 16.733 99.768 ;
     RECT  16.193 82.176 16.739 82.728 ;
     RECT  16.733 42.048 16.805 44.088 ;
     RECT  16.733 99.552 16.837 99.768 ;
     RECT  15.797 100.896 16.837 101.448 ;
     RECT  16.693 68.976 16.877 69.48 ;
     RECT  16.739 82.56 16.877 82.728 ;
     RECT  16.805 42.24 16.931 44.088 ;
     RECT  16.877 82.608 16.931 82.728 ;
     RECT  16.801 93.744 16.933 93.768 ;
     RECT  16.931 82.608 16.979 82.68 ;
     RECT  16.979 82.656 16.985 82.68 ;
     RECT  16.933 93.504 17.021 93.768 ;
     RECT  16.165 103.296 17.077 103.512 ;
     RECT  16.837 99.552 17.093 101.448 ;
     RECT  16.229 0.144 17.125 0.264 ;
     RECT  16.697 70.848 17.129 79.464 ;
     RECT  17.077 103.248 17.132 103.512 ;
     RECT  17.132 103.152 17.221 103.512 ;
     RECT  16.931 42.576 17.411 44.088 ;
     RECT  17.221 103.056 17.459 103.512 ;
     RECT  17.411 42.72 17.485 44.088 ;
     RECT  16.517 1.728 17.521 1.752 ;
     RECT  16.697 2.928 17.521 6.792 ;
     RECT  17.485 42.72 17.525 44.424 ;
     RECT  17.525 42.72 17.561 42.792 ;
     RECT  17.093 99.6 17.593 101.448 ;
     RECT  16.877 69.024 17.597 69.48 ;
     RECT  17.459 103.296 17.603 103.512 ;
     RECT  17.125 0.144 17.651 0.6 ;
     RECT  17.593 99.6 17.699 102.072 ;
     RECT  17.521 1.728 17.765 6.792 ;
     RECT  17.765 1.728 17.809 7.464 ;
     RECT  17.809 1.68 17.893 7.464 ;
     RECT  17.893 1.152 17.996 7.464 ;
     RECT  17.996 1.152 18.101 7.992 ;
     RECT  17.651 0.144 18.125 0.168 ;
     RECT  18.125 0.096 18.209 0.168 ;
     RECT  17.525 43.776 18.229 44.424 ;
     RECT  18.236 10.608 18.277 10.632 ;
     RECT  17.699 99.6 18.277 101.448 ;
     RECT  18.277 99.504 18.325 101.448 ;
     RECT  18.205 87.072 18.349 87.096 ;
     RECT  18.229 43.776 18.373 44.472 ;
     RECT  18.373 43.776 18.529 44.52 ;
     RECT  13.504 45.744 18.529 55.224 ;
     RECT  18.101 1.728 18.608 7.992 ;
     RECT  18.277 10.608 18.608 10.728 ;
     RECT  13.504 30.576 18.608 30.6 ;
     RECT  17.561 42.72 18.608 42.744 ;
     RECT  18.529 43.776 18.608 55.224 ;
     RECT  13.504 56.208 18.608 57.432 ;
     RECT  13.504 58.512 18.608 58.776 ;
     RECT  13.504 60.528 18.608 62.328 ;
     RECT  17.597 69.024 18.608 69.144 ;
     RECT  17.129 70.848 18.608 79.032 ;
     RECT  17.989 84.96 18.608 84.984 ;
     RECT  18.349 87.024 18.608 87.096 ;
     RECT  18.565 88.752 18.608 88.776 ;
     RECT  16.213 91.968 18.608 91.992 ;
     RECT  17.021 93.744 18.608 93.768 ;
     RECT  18.325 98.976 18.608 101.448 ;
     RECT  17.603 103.44 18.803 103.512 ;
     RECT  18.209 0.144 18.901 0.168 ;
     RECT  18.608 1.728 18.904 101.448 ;
     RECT  18.904 98.976 18.965 101.448 ;
     RECT  18.904 70.848 19.001 78.36 ;
     RECT  19.001 72.144 19.109 78.36 ;
     RECT  18.803 103.488 19.139 103.512 ;
     RECT  19.109 75.12 19.181 78.36 ;
     RECT  19.109 72.144 19.217 73.896 ;
     RECT  18.904 8.544 19.253 8.568 ;
     RECT  19.181 75.168 19.283 78.36 ;
     RECT  18.901 0.144 19.285 0.6 ;
     RECT  19.283 76.368 19.297 78.36 ;
     RECT  19.283 75.168 19.324 75.192 ;
     RECT  19.217 73.584 19.361 73.896 ;
     RECT  18.904 10.272 19.397 10.296 ;
     RECT  19.297 76.512 19.397 78.36 ;
     RECT  18.965 99.168 19.42 101.448 ;
     RECT  19.285 0.096 19.429 0.6 ;
     RECT  18.904 1.728 19.429 6.936 ;
     RECT  19.429 0.096 19.433 6.936 ;
     RECT  19.397 76.512 19.469 77.352 ;
     RECT  18.904 43.344 19.523 55.224 ;
     RECT  19.469 77.328 19.541 77.352 ;
     RECT  19.433 0.096 19.619 5.112 ;
     RECT  18.904 84.96 19.619 84.984 ;
     RECT  19.523 43.344 19.657 43.944 ;
     RECT  19.657 43.344 19.693 43.368 ;
     RECT  19.619 1.728 19.829 5.112 ;
     RECT  18.904 30.576 19.865 30.696 ;
     RECT  19.829 1.728 19.901 3.432 ;
     RECT  18.904 80.928 19.901 80.952 ;
     RECT  19.964 8.496 20.051 8.52 ;
     RECT  18.904 12 20.233 12.024 ;
     RECT  19.433 6.24 20.293 6.936 ;
     RECT  20.293 6.24 20.357 7.464 ;
     RECT  20.357 6.24 20.441 7.992 ;
     RECT  19.523 45.168 20.531 55.224 ;
     RECT  19.969 86.544 20.549 86.568 ;
     RECT  20.573 9.12 20.657 9.144 ;
     RECT  19.619 0.096 20.773 0.696 ;
     RECT  19.829 4.8 20.773 5.112 ;
     RECT  18.904 69.024 20.797 69.048 ;
     RECT  19.901 2.208 20.837 3.432 ;
     RECT  20.837 2.256 20.869 3.432 ;
     RECT  20.773 4.8 20.869 5.16 ;
     RECT  20.869 2.256 20.909 5.16 ;
     RECT  19.42 99.504 20.933 101.448 ;
     RECT  20.531 45.6 20.963 55.224 ;
     RECT  20.833 10.8 21.017 10.824 ;
     RECT  20.909 2.256 21.061 2.904 ;
     RECT  20.773 0.096 21.089 1.176 ;
     RECT  20.909 3.936 21.161 5.16 ;
     RECT  21.061 2.736 21.233 2.904 ;
     RECT  21.161 4.992 21.493 5.16 ;
     RECT  20.441 6.24 21.493 7.464 ;
     RECT  20.797 69.024 21.517 69.192 ;
     RECT  20.963 45.936 21.539 55.224 ;
     RECT  21.473 103.536 21.557 103.56 ;
     RECT  21.089 0.096 21.593 0.12 ;
     RECT  21.493 4.992 21.601 7.464 ;
     RECT  20.933 99.168 21.601 101.448 ;
     RECT  21.161 3.936 21.635 4.008 ;
     RECT  21.601 99.504 21.635 101.448 ;
     RECT  21.601 6.288 21.637 7.464 ;
     RECT  21.601 4.992 21.701 5.16 ;
     RECT  21.517 68.4 21.779 69.192 ;
     RECT  21.635 99.552 21.817 101.448 ;
     RECT  18.904 91.968 21.949 91.992 ;
     RECT  21.985 10.8 22.133 10.824 ;
     RECT  21.635 3.984 22.268 4.008 ;
     RECT  21.701 4.992 22.268 5.016 ;
     RECT  22.229 103.44 22.268 103.464 ;
     RECT  21.949 91.968 22.277 92.136 ;
     RECT  21.089 1.152 22.309 1.176 ;
     RECT  22.268 3.984 22.355 5.016 ;
     RECT  22.309 1.152 22.451 1.752 ;
     RECT  22.117 9.12 22.493 9.144 ;
     RECT  21.539 46.224 22.529 55.224 ;
     RECT  21.637 6.288 22.573 7.512 ;
     RECT  21.233 2.736 22.597 2.856 ;
     RECT  21.817 99.552 22.633 100.344 ;
     RECT  22.529 47.04 22.637 55.224 ;
     RECT  22.597 2.256 22.681 2.856 ;
     RECT  22.355 4.992 22.741 5.016 ;
     RECT  22.268 103.296 22.741 103.464 ;
     RECT  22.681 2.784 22.777 2.856 ;
     RECT  22.573 6.864 22.781 7.512 ;
     RECT  22.741 103.296 22.787 103.512 ;
     RECT  21.779 69.168 22.813 69.192 ;
     RECT  22.451 1.152 22.837 1.176 ;
     RECT  22.637 47.904 22.997 55.224 ;
     RECT  22.997 47.952 23.027 55.224 ;
     RECT  22.837 0.576 23.029 1.176 ;
     RECT  18.904 97.104 23.029 97.128 ;
     RECT  22.741 4.992 23.077 5.16 ;
     RECT  22.633 99.504 23.14 100.344 ;
     RECT  21.817 101.328 23.14 101.448 ;
     RECT  22.787 103.488 23.171 103.512 ;
     RECT  22.813 69.024 23.281 69.192 ;
     RECT  23.077 4.992 23.317 5.832 ;
     RECT  23.029 0.096 23.318 1.176 ;
     RECT  23.318 0.144 23.507 1.176 ;
     RECT  23.14 99.504 23.653 101.448 ;
     RECT  23.507 0.288 23.713 1.176 ;
     RECT  22.777 2.784 23.713 3.768 ;
     RECT  22.781 6.864 23.756 7.464 ;
     RECT  23.413 10.32 23.821 10.344 ;
     RECT  23.317 4.944 23.929 5.832 ;
     RECT  23.756 6.816 23.929 7.464 ;
     RECT  23.713 0.288 24.008 3.768 ;
     RECT  23.929 4.944 24.008 7.464 ;
     RECT  23.821 9.36 24.008 10.344 ;
     RECT  23.461 11.424 24.008 11.448 ;
     RECT  19.865 30.672 24.008 30.696 ;
     RECT  23.027 48.384 24.008 55.224 ;
     RECT  18.904 56.208 24.008 57.432 ;
     RECT  18.904 58.512 24.008 58.776 ;
     RECT  18.904 60.528 24.008 62.328 ;
     RECT  23.281 69.024 24.008 69.528 ;
     RECT  19.001 70.848 24.008 70.872 ;
     RECT  19.217 72.144 24.008 72.168 ;
     RECT  19.361 73.824 24.008 73.896 ;
     RECT  19.397 78.336 24.008 78.36 ;
     RECT  22.849 82.128 24.008 82.152 ;
     RECT  22.277 92.112 24.008 92.136 ;
     RECT  18.904 93.744 24.008 93.768 ;
     RECT  23.029 97.056 24.008 97.128 ;
     RECT  23.653 99.168 24.008 101.448 ;
     RECT  24.037 103.248 24.133 103.272 ;
     RECT  24.133 103.152 24.229 103.272 ;
     RECT  24.229 103.152 24.277 103.368 ;
     RECT  24.008 0.288 24.304 101.448 ;
     RECT  24.277 103.152 24.325 103.464 ;
     RECT  24.304 8.16 24.445 12.024 ;
     RECT  24.445 8.16 24.467 8.28 ;
     RECT  24.304 0.288 24.469 6.888 ;
     RECT  24.325 103.152 24.515 103.56 ;
     RECT  24.469 0.192 24.563 6.888 ;
     RECT  24.563 0.192 24.581 6.6 ;
     RECT  24.581 0.192 24.649 0.216 ;
     RECT  24.304 48.72 24.659 55.224 ;
     RECT  24.467 8.256 24.725 8.28 ;
     RECT  24.304 91.968 24.725 91.992 ;
     RECT  24.581 1.728 24.755 6.6 ;
     RECT  24.659 48.72 24.755 48.744 ;
     RECT  24.445 9.36 24.803 12.024 ;
     RECT  24.304 69.024 24.803 69.048 ;
     RECT  24.659 50.112 24.869 55.224 ;
     RECT  24.304 96.912 24.869 97.272 ;
     RECT  24.755 1.728 24.899 6.312 ;
     RECT  24.899 1.728 24.941 4.296 ;
     RECT  24.515 103.536 24.941 103.56 ;
     RECT  24.304 30.24 24.947 30.696 ;
     RECT  24.899 5.28 25.085 6.312 ;
     RECT  24.803 10.272 25.121 12.024 ;
     RECT  24.304 93.744 25.187 94.68 ;
     RECT  24.304 99.36 25.187 101.448 ;
     RECT  25.121 10.656 25.193 12.024 ;
     RECT  24.947 30.24 25.265 30.264 ;
     RECT  25.187 99.36 25.285 99.816 ;
     RECT  24.869 50.352 25.337 55.224 ;
     RECT  25.285 99.168 25.477 99.816 ;
     RECT  25.193 10.656 25.517 11.448 ;
     RECT  25.187 93.744 25.553 94.392 ;
     RECT  25.517 10.8 25.589 11.448 ;
     RECT  25.553 93.744 25.589 93.768 ;
     RECT  25.477 98.592 25.625 99.816 ;
     RECT  24.941 1.728 25.661 3.96 ;
     RECT  25.661 2.208 25.811 3.96 ;
     RECT  24.649 0.096 25.813 0.216 ;
     RECT  25.813 0.096 25.829 0.264 ;
     RECT  25.429 9.12 25.877 9.144 ;
     RECT  25.829 0.096 26.044 0.36 ;
     RECT  25.811 2.256 26.053 3.96 ;
     RECT  25.085 5.28 26.053 5.736 ;
     RECT  25.625 98.64 26.165 99.816 ;
     RECT  26.165 99.168 26.189 99.816 ;
     RECT  25.187 100.896 26.189 101.448 ;
     RECT  26.053 2.256 26.201 5.736 ;
     RECT  25.337 51.12 26.243 55.224 ;
     RECT  26.044 0.144 26.245 0.36 ;
     RECT  26.201 5.232 26.269 5.736 ;
     RECT  26.189 99.168 26.273 101.448 ;
     RECT  25.909 7.44 26.341 7.464 ;
     RECT  26.201 2.256 26.353 3.96 ;
     RECT  25.589 11.424 26.413 11.448 ;
     RECT  26.245 0.144 26.489 1.176 ;
     RECT  26.245 103.488 26.533 103.512 ;
     RECT  26.533 103.392 26.657 103.512 ;
     RECT  25.381 91.2 26.675 91.224 ;
     RECT  26.413 11.424 26.813 11.928 ;
     RECT  26.813 11.904 26.845 11.928 ;
     RECT  26.341 7.44 26.849 8.04 ;
     RECT  26.845 11.904 26.921 12.552 ;
     RECT  26.921 12.528 26.929 12.552 ;
     RECT  24.304 78.336 27.013 78.36 ;
     RECT  26.849 7.44 27.029 7.464 ;
     RECT  26.657 103.392 27.061 103.56 ;
     RECT  27.061 103.344 27.157 103.56 ;
     RECT  26.269 5.232 27.169 5.784 ;
     RECT  27.157 6.864 27.169 6.888 ;
     RECT  26.353 2.592 27.205 3.96 ;
     RECT  27.169 5.232 27.205 6.888 ;
     RECT  26.273 99.168 27.251 99.768 ;
     RECT  27.157 103.248 27.299 103.56 ;
     RECT  26.243 51.12 27.308 52.728 ;
     RECT  27.308 51.12 27.347 52.776 ;
     RECT  27.205 2.592 27.349 6.888 ;
     RECT  27.347 52.416 27.349 52.776 ;
     RECT  26.243 53.76 27.349 55.224 ;
     RECT  27.349 1.728 27.461 6.888 ;
     RECT  27.013 77.52 27.605 78.36 ;
     RECT  27.251 99.456 27.673 99.768 ;
     RECT  26.489 0.144 27.713 0.6 ;
     RECT  27.299 103.296 27.779 103.56 ;
     RECT  27.779 103.392 27.785 103.56 ;
     RECT  27.349 52.416 27.821 55.224 ;
     RECT  27.785 103.392 27.827 103.512 ;
     RECT  27.673 99.456 27.829 99.816 ;
     RECT  26.273 100.896 27.829 101.448 ;
     RECT  27.821 52.416 27.857 52.44 ;
     RECT  27.829 99.456 27.929 101.448 ;
     RECT  27.925 10.848 27.973 10.872 ;
     RECT  28.061 8.544 28.145 8.568 ;
     RECT  27.973 10.848 28.211 11.448 ;
     RECT  28.211 11.424 28.253 11.448 ;
     RECT  27.929 99.456 28.453 99.816 ;
     RECT  27.821 53.568 28.501 55.224 ;
     RECT  24.304 56.208 28.501 57.432 ;
     RECT  27.713 0.144 28.673 0.216 ;
     RECT  28.453 99.168 28.753 99.816 ;
     RECT  28.673 0.096 28.757 0.216 ;
     RECT  27.461 1.728 28.933 6.312 ;
     RECT  28.757 0.144 29.125 0.216 ;
     RECT  29.125 0.144 29.132 0.312 ;
     RECT  28.933 1.728 29.132 7.032 ;
     RECT  29.132 0.144 29.219 7.032 ;
     RECT  28.753 98.64 29.221 99.816 ;
     RECT  27.929 100.896 29.221 101.448 ;
     RECT  27.827 103.488 29.269 103.512 ;
     RECT  29.219 1.728 29.408 7.032 ;
     RECT  29.084 8.496 29.408 8.52 ;
     RECT  27.347 51.12 29.408 51.144 ;
     RECT  28.501 53.568 29.408 57.432 ;
     RECT  24.304 58.512 29.408 58.776 ;
     RECT  24.304 60.528 29.408 62.328 ;
     RECT  29.365 64.992 29.408 65.016 ;
     RECT  24.304 70.848 29.408 70.872 ;
     RECT  24.304 73.824 29.408 73.896 ;
     RECT  27.605 78.336 29.408 78.36 ;
     RECT  28.261 92.352 29.408 92.376 ;
     RECT  24.869 97.104 29.408 97.272 ;
     RECT  29.221 98.64 29.408 101.448 ;
     RECT  29.408 1.728 29.704 101.448 ;
     RECT  29.704 6.864 29.729 6.936 ;
     RECT  29.704 54.672 29.837 57.432 ;
     RECT  29.837 55.44 29.843 57.432 ;
     RECT  29.269 103.392 29.861 103.512 ;
     RECT  29.219 0.144 29.869 0.408 ;
     RECT  29.861 103.392 29.891 103.56 ;
     RECT  29.843 55.824 29.909 57.432 ;
     RECT  29.704 64.992 29.939 65.016 ;
     RECT  29.891 103.44 29.945 103.56 ;
     RECT  29.869 0.096 29.953 0.408 ;
     RECT  29.704 9.12 29.953 9.144 ;
     RECT  29.945 103.44 29.987 103.512 ;
     RECT  29.729 6.864 30.161 6.888 ;
     RECT  29.704 7.968 30.197 7.992 ;
     RECT  29.704 1.728 30.265 5.736 ;
     RECT  29.953 0.144 30.277 0.408 ;
     RECT  30.265 1.68 30.277 5.736 ;
     RECT  29.909 55.872 30.457 57.432 ;
     RECT  29.987 103.488 30.515 103.512 ;
     RECT  29.704 10.272 30.521 10.872 ;
     RECT  30.277 0.144 30.629 5.736 ;
     RECT  30.629 0.144 30.665 3.432 ;
     RECT  30.457 56.352 30.709 57.432 ;
     RECT  29.704 58.512 30.709 58.776 ;
     RECT  30.709 56.352 30.769 58.776 ;
     RECT  29.704 78.336 30.769 78.36 ;
     RECT  30.769 78.336 30.809 78.456 ;
     RECT  30.521 10.848 30.851 10.872 ;
     RECT  30.629 4.512 30.853 5.736 ;
     RECT  30.665 0.144 30.899 0.504 ;
     RECT  30.899 0.144 30.949 0.312 ;
     RECT  30.949 0.096 30.989 0.312 ;
     RECT  29.704 99.552 30.997 101.448 ;
     RECT  29.704 12 31.033 12.024 ;
     RECT  30.989 0.096 31.043 0.216 ;
     RECT  29.704 92.352 31.043 92.376 ;
     RECT  30.997 98.64 31.189 101.448 ;
     RECT  30.769 56.352 31.205 58.92 ;
     RECT  31.189 98.64 31.235 101.688 ;
     RECT  31.235 99.168 31.321 101.688 ;
     RECT  29.704 73.824 31.349 73.896 ;
     RECT  31.321 99.552 31.379 101.688 ;
     RECT  31.237 8.544 31.493 8.568 ;
     RECT  30.665 1.68 31.669 3.432 ;
     RECT  30.853 4.512 31.669 6.312 ;
     RECT  31.669 1.68 31.673 6.312 ;
     RECT  31.673 1.68 31.817 3.96 ;
     RECT  31.043 0.096 31.889 0.168 ;
     RECT  31.141 11.424 32.005 11.448 ;
     RECT  31.205 57.312 32.149 58.92 ;
     RECT  29.704 60.528 32.149 62.328 ;
     RECT  32.149 57.312 32.177 62.328 ;
     RECT  31.957 103.488 32.245 103.512 ;
     RECT  32.177 57.36 32.249 62.328 ;
     RECT  31.673 5.136 32.341 6.312 ;
     RECT  31.841 7.44 32.341 7.464 ;
     RECT  32.245 103.296 32.341 103.512 ;
     RECT  32.341 103.296 32.387 103.56 ;
     RECT  31.379 99.552 32.427 101.448 ;
     RECT  32.341 5.136 32.429 7.464 ;
     RECT  32.249 57.36 32.429 59.256 ;
     RECT  32.387 103.44 32.534 103.56 ;
     RECT  32.389 9.12 32.537 9.144 ;
     RECT  31.889 0.144 32.581 0.168 ;
     RECT  32.149 1.152 32.581 1.176 ;
     RECT  32.209 67.248 32.675 67.272 ;
     RECT  32.429 7.44 32.677 7.464 ;
     RECT  32.534 103.488 32.723 103.512 ;
     RECT  32.429 57.408 32.789 59.256 ;
     RECT  32.677 7.44 32.819 7.56 ;
     RECT  32.789 58.272 32.819 59.256 ;
     RECT  31.129 68.4 32.819 68.424 ;
     RECT  31.817 2.256 32.821 3.576 ;
     RECT  32.427 99.504 32.857 101.448 ;
     RECT  32.429 5.136 32.86 6.36 ;
     RECT  32.819 58.368 32.867 59.256 ;
     RECT  32.581 0.144 32.917 1.176 ;
     RECT  32.821 2.256 32.917 3.864 ;
     RECT  32.857 98.688 32.969 101.448 ;
     RECT  32.917 0.144 33.011 3.864 ;
     RECT  33.011 0.24 33.013 3.864 ;
     RECT  32.86 5.088 33.013 6.36 ;
     RECT  33.013 0.24 33.059 6.36 ;
     RECT  33.109 9.696 33.173 9.72 ;
     RECT  33.173 9.696 33.257 10.296 ;
     RECT  33.059 1.104 33.293 6.36 ;
     RECT  32.867 58.512 33.299 59.256 ;
     RECT  33.293 1.104 33.347 6.312 ;
     RECT  31.349 73.824 33.437 73.848 ;
     RECT  33.397 12.528 33.481 12.552 ;
     RECT  33.299 58.896 33.541 59.256 ;
     RECT  32.249 60.432 33.541 62.328 ;
     RECT  33.541 58.896 33.683 62.328 ;
     RECT  32.969 99.168 33.724 101.448 ;
     RECT  33.257 9.696 33.781 9.72 ;
     RECT  33.683 59.232 33.797 62.328 ;
     RECT  33.797 59.808 33.833 62.328 ;
     RECT  33.347 2.304 34.364 6.312 ;
     RECT  33.347 1.104 34.547 1.128 ;
     RECT  33.833 59.856 34.765 62.328 ;
     RECT  33.724 99.408 34.765 101.448 ;
     RECT  34.364 2.256 34.808 6.312 ;
     RECT  34.549 7.392 34.808 7.416 ;
     RECT  33.781 9.12 34.808 9.72 ;
     RECT  33.589 11.424 34.808 11.448 ;
     RECT  29.704 51.12 34.808 51.144 ;
     RECT  34.765 59.856 34.808 62.472 ;
     RECT  29.704 70.848 34.808 70.872 ;
     RECT  33.469 73.536 34.808 73.56 ;
     RECT  30.809 78.432 34.808 78.456 ;
     RECT  34.549 92.976 34.808 93 ;
     RECT  29.704 97.104 34.808 97.272 ;
     RECT  34.765 99.408 34.808 101.496 ;
     RECT  34.808 2.148 34.885 101.496 ;
     RECT  34.885 1.728 35.027 101.496 ;
     RECT  35.027 1.728 35.104 101.448 ;
     RECT  34.405 103.344 35.173 103.512 ;
     RECT  35.104 10.704 35.309 10.728 ;
     RECT  35.173 103.344 35.315 103.56 ;
     RECT  34.549 0.144 35.441 0.6 ;
     RECT  35.104 12 35.459 12.024 ;
     RECT  35.104 7.872 35.561 7.992 ;
     RECT  35.561 7.872 35.603 7.896 ;
     RECT  35.104 1.728 35.705 6.312 ;
     RECT  35.104 99.168 35.705 99.864 ;
     RECT  35.104 60.288 35.747 62.664 ;
     RECT  35.705 1.728 35.795 5.784 ;
     RECT  35.104 92.976 35.891 93 ;
     RECT  35.441 0.096 36.173 0.6 ;
     RECT  35.795 1.728 36.188 5.64 ;
     RECT  36.188 1.68 36.275 5.64 ;
     RECT  35.104 97.104 36.277 97.272 ;
     RECT  35.747 61.104 36.281 62.664 ;
     RECT  35.104 70.848 36.317 70.872 ;
     RECT  36.281 61.632 36.323 62.664 ;
     RECT  35.315 103.392 36.361 103.56 ;
     RECT  36.173 0.576 36.425 0.6 ;
     RECT  36.323 62.016 36.493 62.664 ;
     RECT  36.493 62.016 36.497 62.76 ;
     RECT  36.277 96.912 36.707 97.272 ;
     RECT  36.361 103.392 36.755 103.512 ;
     RECT  36.275 1.728 36.757 5.64 ;
     RECT  35.705 99.168 36.805 99.816 ;
     RECT  35.104 100.896 36.805 101.448 ;
     RECT  36.497 62.208 36.817 62.76 ;
     RECT  36.781 11.424 36.865 11.448 ;
     RECT  36.565 9.12 36.901 9.144 ;
     RECT  36.817 62.208 36.947 63.288 ;
     RECT  36.757 1.728 37.009 5.832 ;
     RECT  36.805 99.168 37.033 101.448 ;
     RECT  36.755 103.392 37.043 103.416 ;
     RECT  36.947 62.448 37.061 63.288 ;
     RECT  37.061 62.448 37.091 63.432 ;
     RECT  36.901 8.544 37.181 9.144 ;
     RECT  36.707 97.104 37.213 97.272 ;
     RECT  37.033 98.736 37.213 101.448 ;
     RECT  37.009 1.728 37.237 4.536 ;
     RECT  37.009 5.712 37.252 5.832 ;
     RECT  37.237 1.68 37.334 4.536 ;
     RECT  37.252 5.712 37.429 6.792 ;
     RECT  37.141 0.096 37.601 0.12 ;
     RECT  37.091 62.64 37.619 63.432 ;
     RECT  37.601 0.096 37.669 0.312 ;
     RECT  37.669 0.096 37.757 0.408 ;
     RECT  37.717 63.84 37.781 63.864 ;
     RECT  37.757 0.096 37.801 0.264 ;
     RECT  37.429 5.712 37.859 6.888 ;
     RECT  37.285 9.696 37.865 9.72 ;
     RECT  37.669 12 37.865 12.024 ;
     RECT  37.859 5.712 37.901 5.736 ;
     RECT  37.781 63.84 37.933 63.912 ;
     RECT  37.619 62.64 37.937 62.664 ;
     RECT  37.334 1.728 38.005 4.536 ;
     RECT  37.909 103.2 38.005 103.224 ;
     RECT  38.005 103.2 38.053 103.32 ;
     RECT  38.053 103.2 38.099 103.56 ;
     RECT  37.933 63.84 38.153 64.392 ;
     RECT  38.153 63.936 38.185 64.392 ;
     RECT  38.185 63.936 38.189 64.68 ;
     RECT  38.099 103.296 38.195 103.56 ;
     RECT  38.005 1.728 38.243 5.688 ;
     RECT  37.859 6.864 38.297 6.888 ;
     RECT  37.181 8.544 38.341 8.568 ;
     RECT  38.243 4.368 38.449 5.688 ;
     RECT  37.801 0.096 38.477 0.168 ;
     RECT  38.341 8.544 38.549 9.144 ;
     RECT  38.195 103.392 38.62 103.56 ;
     RECT  38.243 1.728 38.675 3.384 ;
     RECT  38.189 64.368 38.689 64.68 ;
     RECT  37.357 67.248 38.761 67.272 ;
     RECT  38.689 64.368 38.801 64.968 ;
     RECT  38.477 0.144 38.915 0.168 ;
     RECT  38.801 64.368 38.915 64.392 ;
     RECT  38.861 12 38.945 12.024 ;
     RECT  38.761 67.248 39.011 67.32 ;
     RECT  38.449 4.368 39.205 5.256 ;
     RECT  37.213 97.104 39.265 101.448 ;
     RECT  39.265 96.96 39.637 101.448 ;
     RECT  39.205 3.936 39.661 5.256 ;
     RECT  39.301 6.288 39.661 6.312 ;
     RECT  38.675 1.728 39.664 2.904 ;
     RECT  39.664 1.728 39.925 2.952 ;
     RECT  39.661 3.936 39.925 6.312 ;
     RECT  38.62 103.392 39.973 103.512 ;
     RECT  39.973 103.248 39.985 103.512 ;
     RECT  39.925 1.728 40.021 6.36 ;
     RECT  39.985 103.2 40.057 103.512 ;
     RECT  40.057 103.2 40.115 103.56 ;
     RECT  40.021 1.728 40.208 6.456 ;
     RECT  39.157 7.44 40.208 7.464 ;
     RECT  38.549 9.12 40.208 9.144 ;
     RECT  35.104 51.12 40.208 51.144 ;
     RECT  39.011 67.296 40.208 67.32 ;
     RECT  35.104 78.336 40.208 78.36 ;
     RECT  39.049 92.352 40.208 92.376 ;
     RECT  39.637 96.384 40.208 101.448 ;
     RECT  40.115 103.248 40.307 103.56 ;
     RECT  40.165 0.576 40.357 0.6 ;
     RECT  40.208 1.728 40.504 101.448 ;
     RECT  40.504 100.704 40.681 101.448 ;
     RECT  40.504 1.728 40.825 6.888 ;
     RECT  40.825 5.712 40.889 6.888 ;
     RECT  40.681 100.896 41.027 101.448 ;
     RECT  41.027 100.944 41.057 101.448 ;
     RECT  40.504 10.848 41.069 10.872 ;
     RECT  41.057 100.944 41.174 101.496 ;
     RECT  40.357 0.096 41.237 0.6 ;
     RECT  40.825 1.728 41.237 4.152 ;
     RECT  41.237 0.096 41.321 4.152 ;
     RECT  41.321 0.096 41.357 0.6 ;
     RECT  40.307 103.488 41.365 103.56 ;
     RECT  41.321 1.728 41.473 4.152 ;
     RECT  41.365 102.912 41.507 103.56 ;
     RECT  40.504 96.912 41.509 99.72 ;
     RECT  41.507 103.536 41.573 103.56 ;
     RECT  40.889 6.864 41.605 6.888 ;
     RECT  41.509 96.912 41.701 99.768 ;
     RECT  40.504 7.968 41.717 7.992 ;
     RECT  41.605 6.864 41.941 6.984 ;
     RECT  41.174 100.944 42.092 101.448 ;
     RECT  40.889 5.712 42.133 5.832 ;
     RECT  41.941 6.864 42.133 7.56 ;
     RECT  41.701 96.912 42.173 99.816 ;
     RECT  42.092 100.896 42.173 101.448 ;
     RECT  42.173 96.912 42.181 101.448 ;
     RECT  42.133 5.616 42.257 7.56 ;
     RECT  42.181 96.384 42.257 101.448 ;
     RECT  41.473 3.936 42.289 4.152 ;
     RECT  42.257 5.616 42.289 6.984 ;
     RECT  42.289 3.936 42.365 6.984 ;
     RECT  42.365 3.936 42.419 5.64 ;
     RECT  42.257 96.384 42.48 99.768 ;
     RECT  42.365 6.72 42.545 6.984 ;
     RECT  41.473 1.728 42.793 2.856 ;
     RECT  42.419 3.936 42.793 5.16 ;
     RECT  42.029 9.12 42.941 9.144 ;
     RECT  42.793 93.84 43.085 93.864 ;
     RECT  43.045 103.488 43.109 103.512 ;
     RECT  43.109 103.488 43.148 103.56 ;
     RECT  43.148 103.44 43.193 103.56 ;
     RECT  43.193 103.44 43.235 103.512 ;
     RECT  41.357 0.528 43.285 0.6 ;
     RECT  43.235 103.488 43.331 103.512 ;
     RECT  42.545 6.72 43.409 6.888 ;
     RECT  42.793 1.728 43.517 5.16 ;
     RECT  43.517 3.168 43.58 5.16 ;
     RECT  42.48 96.912 43.585 99.768 ;
     RECT  42.257 100.896 43.585 101.448 ;
     RECT  43.285 0.288 43.621 0.6 ;
     RECT  43.58 3.168 43.667 5.4 ;
     RECT  43.621 0.096 43.676 0.6 ;
     RECT  43.517 1.728 43.676 1.848 ;
     RECT  43.585 96.912 43.729 101.448 ;
     RECT  43.676 0.096 43.763 1.848 ;
     RECT  43.729 95.904 43.837 101.448 ;
     RECT  43.837 95.664 43.907 101.448 ;
     RECT  43.409 6.864 43.985 6.888 ;
     RECT  43.285 12.768 44.045 12.792 ;
     RECT  43.907 95.664 44.089 99.768 ;
     RECT  44.045 12 44.129 12.792 ;
     RECT  43.763 0.096 44.173 0.552 ;
     RECT  43.669 10.848 44.201 10.872 ;
     RECT  44.173 0.144 44.243 0.552 ;
     RECT  44.089 95.28 44.341 99.768 ;
     RECT  44.129 12.528 44.387 12.792 ;
     RECT  43.763 1.728 44.485 1.848 ;
     RECT  43.667 3.168 44.485 5.16 ;
     RECT  44.293 8.544 44.489 8.568 ;
     RECT  44.485 1.728 44.531 5.16 ;
     RECT  44.485 103.296 44.533 103.32 ;
     RECT  44.533 103.296 44.549 103.464 ;
     RECT  44.449 11.424 44.579 11.448 ;
     RECT  44.387 12.768 44.581 12.792 ;
     RECT  44.549 103.296 44.627 103.56 ;
     RECT  44.627 103.392 44.641 103.56 ;
     RECT  44.641 103.392 44.867 103.416 ;
     RECT  44.693 5.664 44.869 5.688 ;
     RECT  44.869 5.664 45.061 5.736 ;
     RECT  44.677 6.72 45.061 6.84 ;
     RECT  45.061 5.664 45.157 6.84 ;
     RECT  44.341 95.184 45.241 99.768 ;
     RECT  43.907 100.896 45.241 101.448 ;
     RECT  45.241 95.184 45.421 101.448 ;
     RECT  44.531 1.728 45.529 4.536 ;
     RECT  45.157 5.664 45.529 7.464 ;
     RECT  45.529 1.728 45.608 7.464 ;
     RECT  45.277 10.608 45.608 10.728 ;
     RECT  44.581 12.768 45.608 13.128 ;
     RECT  40.504 51.12 45.608 51.144 ;
     RECT  40.504 78.336 45.608 78.36 ;
     RECT  45.421 94.848 45.608 101.448 ;
     RECT  45.608 1.728 45.635 101.448 ;
     RECT  45.635 2.148 45.712 101.448 ;
     RECT  45.685 103.488 45.877 103.512 ;
     RECT  45.712 2.208 45.904 101.448 ;
     RECT  45.904 2.208 46.019 7.512 ;
     RECT  45.877 103.44 46.061 103.512 ;
     RECT  46.019 7.392 46.067 7.512 ;
     RECT  45.904 8.544 46.073 9.528 ;
     RECT  44.243 0.144 46.133 0.312 ;
     RECT  46.061 102.576 46.145 103.512 ;
     RECT  46.019 2.208 46.163 6.408 ;
     RECT  46.067 7.44 46.181 7.512 ;
     RECT  46.133 0.096 46.316 0.312 ;
     RECT  45.904 92.544 46.505 98.136 ;
     RECT  46.145 103.008 46.691 103.512 ;
     RECT  46.691 103.152 46.739 103.512 ;
     RECT  45.904 101.424 46.756 101.448 ;
     RECT  46.181 7.44 46.793 7.464 ;
     RECT  46.073 8.544 46.793 8.616 ;
     RECT  46.739 103.2 46.796 103.512 ;
     RECT  46.316 0.096 46.825 1.128 ;
     RECT  46.163 2.208 46.825 6.168 ;
     RECT  45.904 99.456 46.885 100.344 ;
     RECT  46.793 8.592 46.909 8.616 ;
     RECT  46.756 101.424 46.933 101.496 ;
     RECT  46.825 0.096 46.969 6.168 ;
     RECT  46.505 92.544 46.973 98.088 ;
     RECT  46.933 101.328 47.027 101.496 ;
     RECT  46.973 92.544 47.037 97.992 ;
     RECT  47.027 101.424 47.171 101.496 ;
     RECT  47.037 92.544 47.185 97.56 ;
     RECT  46.885 99.168 47.188 100.344 ;
     RECT  46.969 0.048 47.221 6.168 ;
     RECT  47.185 92.112 47.297 97.56 ;
     RECT  47.297 92.112 47.477 97.368 ;
     RECT  47.221 0.048 47.555 6.84 ;
     RECT  47.653 13.68 47.765 13.704 ;
     RECT  47.555 1.632 47.773 6.84 ;
     RECT  46.796 103.2 47.773 103.56 ;
     RECT  47.773 103.2 47.795 103.512 ;
     RECT  47.555 0.048 47.987 0.552 ;
     RECT  47.188 99.12 47.989 100.344 ;
     RECT  47.171 101.424 47.989 101.448 ;
     RECT  47.989 99.12 48.188 101.448 ;
     RECT  47.477 92.112 48.193 97.272 ;
     RECT  47.773 2.208 48.197 6.84 ;
     RECT  48.197 6.72 48.268 6.84 ;
     RECT  48.188 99.072 48.373 101.448 ;
     RECT  48.373 98.592 48.409 101.448 ;
     RECT  48.373 14.256 48.467 14.28 ;
     RECT  48.409 98.496 48.553 101.448 ;
     RECT  48.229 13.104 48.589 13.128 ;
     RECT  48.193 91.536 48.613 97.272 ;
     RECT  48.553 98.256 48.613 101.448 ;
     RECT  47.833 7.968 48.803 7.992 ;
     RECT  47.987 0.048 48.949 0.216 ;
     RECT  47.795 103.296 48.994 103.512 ;
     RECT  48.613 91.536 48.995 101.448 ;
     RECT  48.995 91.536 49.277 96.264 ;
     RECT  48.268 6.72 49.309 6.792 ;
     RECT  48.197 2.208 49.381 5.736 ;
     RECT  49.309 6.72 49.381 7.272 ;
     RECT  48.994 103.296 49.381 103.56 ;
     RECT  49.237 10.272 49.385 10.296 ;
     RECT  49.277 91.536 49.427 96.12 ;
     RECT  49.381 2.208 49.475 7.272 ;
     RECT  49.475 2.208 49.477 5.208 ;
     RECT  49.427 91.536 49.529 93 ;
     RECT  49.475 6.24 49.565 7.272 ;
     RECT  49.427 94.032 49.565 96.12 ;
     RECT  49.565 94.032 49.601 94.104 ;
     RECT  49.477 1.728 49.619 5.208 ;
     RECT  49.565 95.76 49.619 96.12 ;
     RECT  48.229 90.048 49.667 90.072 ;
     RECT  48.949 0.048 49.669 0.552 ;
     RECT  49.619 1.728 49.669 4.536 ;
     RECT  48.995 97.392 49.741 101.448 ;
     RECT  49.381 102.624 49.741 103.56 ;
     RECT  49.741 97.392 49.781 103.56 ;
     RECT  49.565 6.816 49.811 7.272 ;
     RECT  49.781 97.68 49.811 103.56 ;
     RECT  49.811 97.68 49.859 100.92 ;
     RECT  49.669 0.048 49.907 4.536 ;
     RECT  49.601 94.08 49.997 94.104 ;
     RECT  49.957 15.984 50.041 16.008 ;
     RECT  48.365 9.12 50.069 9.144 ;
     RECT  49.859 98.4 50.092 100.92 ;
     RECT  45.904 78.336 50.141 78.36 ;
     RECT  49.619 95.76 50.177 95.784 ;
     RECT  49.907 1.728 50.195 4.536 ;
     RECT  49.529 92.64 50.195 92.664 ;
     RECT  49.811 6.864 50.243 7.272 ;
     RECT  49.529 91.536 50.243 91.56 ;
     RECT  50.092 98.64 50.291 100.92 ;
     RECT  48.517 14.304 50.317 14.328 ;
     RECT  48.589 12.528 50.339 13.128 ;
     RECT  50.195 4.512 50.387 4.536 ;
     RECT  50.317 14.256 50.387 14.328 ;
     RECT  50.339 12.528 50.435 12.552 ;
     RECT  50.387 14.256 50.531 14.28 ;
     RECT  50.195 1.728 50.723 3.432 ;
     RECT  49.811 102.048 50.819 103.56 ;
     RECT  50.723 1.728 50.861 2.376 ;
     RECT  50.291 98.736 50.915 100.92 ;
     RECT  50.861 2.352 50.969 2.376 ;
     RECT  50.723 3.408 51.005 3.432 ;
     RECT  50.243 6.864 51.011 6.888 ;
     RECT  50.819 102.048 51.011 102.072 ;
     RECT  50.819 103.536 51.221 103.56 ;
     RECT  49.907 0.048 51.299 0.552 ;
     RECT  51.299 0.048 51.473 0.072 ;
     RECT  51.289 96.912 51.491 96.936 ;
     RECT  50.915 98.736 51.587 99.192 ;
     RECT  50.915 100.32 51.683 100.92 ;
     RECT  51.587 98.736 51.779 98.76 ;
     RECT  51.683 100.368 51.875 100.92 ;
     RECT  45.904 51.12 52.115 51.144 ;
     RECT  51.875 100.896 52.403 100.92 ;
    LAYER M5 ;
     RECT  0.768 0.016 51.288 0.563 ;
     RECT  0.768 0.563 51 6.899 ;
     RECT  0.768 6.899 50.52 10.355 ;
     RECT  1.056 10.355 50.52 11.507 ;
     RECT  1.872 11.507 50.52 13.139 ;
     RECT  2.256 13.139 50.52 13.187 ;
     RECT  2.304 13.187 50.52 14.291 ;
     RECT  2.304 14.291 50.376 14.339 ;
     RECT  2.304 14.339 50.232 29.075 ;
     RECT  2.4 29.075 50.232 30.707 ;
     RECT  0.288 30.757 0.312 30.899 ;
     RECT  5.664 30.707 50.232 31.043 ;
     RECT  5.712 31.043 50.232 31.331 ;
     RECT  2.4 30.707 4.68 32.195 ;
     RECT  5.76 31.331 50.232 36.421 ;
     RECT  5.184 36.421 50.232 36.757 ;
     RECT  5.136 36.757 50.232 36.899 ;
     RECT  5.232 36.899 50.232 36.947 ;
     RECT  2.4 32.195 3.864 38.485 ;
     RECT  2.4 38.485 4.68 38.627 ;
     RECT  2.4 38.627 4.296 39.589 ;
     RECT  2.4 39.589 4.392 39.779 ;
     RECT  2.4 39.779 3.864 41.509 ;
     RECT  5.76 36.947 50.232 42.851 ;
     RECT  5.76 42.851 16.44 43.379 ;
     RECT  2.4 41.509 3.96 43.813 ;
     RECT  17.424 42.851 50.232 44.531 ;
     RECT  2.4 43.813 4.536 45.155 ;
     RECT  5.76 43.379 16.392 45.349 ;
     RECT  5.04 45.349 16.392 45.491 ;
     RECT  5.712 45.491 16.392 45.731 ;
     RECT  5.76 45.731 16.392 46.837 ;
     RECT  0.192 46.885 0.216 47.171 ;
     RECT  5.04 46.837 16.392 47.267 ;
     RECT  2.4 45.155 3.96 47.891 ;
     RECT  0.144 48.133 0.168 48.323 ;
     RECT  18.6 44.531 50.232 48.371 ;
     RECT  5.76 47.267 16.392 48.565 ;
     RECT  5.136 48.565 16.392 48.997 ;
     RECT  1.248 48.997 1.272 49.331 ;
     RECT  4.992 48.997 16.392 49.331 ;
     RECT  1.248 50.341 1.272 50.389 ;
     RECT  1.152 50.389 1.272 50.579 ;
     RECT  5.76 49.331 16.392 51.061 ;
     RECT  0.192 50.917 0.216 51.107 ;
     RECT  2.4 47.891 3.864 51.157 ;
     RECT  2.4 51.157 3.96 51.299 ;
     RECT  0.144 51.637 0.168 51.827 ;
     RECT  5.136 51.061 16.392 52.067 ;
     RECT  2.4 51.299 3.864 52.405 ;
     RECT  21.648 48.371 50.232 52.547 ;
     RECT  2.4 52.405 4.584 53.557 ;
     RECT  5.76 52.067 16.392 53.557 ;
     RECT  21.648 52.547 25.992 53.557 ;
     RECT  27.024 52.547 50.232 53.557 ;
     RECT  21.648 53.557 50.232 53.795 ;
     RECT  1.152 53.749 1.176 53.891 ;
     RECT  0.144 53.845 0.168 54.131 ;
     RECT  0.144 56.533 0.168 56.819 ;
     RECT  27.024 53.795 50.232 58.691 ;
     RECT  2.4 53.557 16.392 59.267 ;
     RECT  32.16 58.691 50.232 59.843 ;
     RECT  33.024 59.843 50.232 60.467 ;
     RECT  2.4 59.267 4.632 60.661 ;
     RECT  5.76 59.267 16.392 60.661 ;
     RECT  2.4 60.661 16.392 60.947 ;
     RECT  33.264 60.467 50.232 60.995 ;
     RECT  34.32 60.995 50.232 61.571 ;
     RECT  0.144 62.197 0.168 62.483 ;
     RECT  2.4 60.947 4.632 62.533 ;
     RECT  5.76 60.947 16.392 62.533 ;
     RECT  2.4 62.533 16.392 62.675 ;
     RECT  0.144 63.877 0.168 64.979 ;
     RECT  2.4 62.675 4.632 64.981 ;
     RECT  5.76 62.675 16.392 64.981 ;
     RECT  33.264 60.995 33.336 67.237 ;
     RECT  0.144 67.333 0.168 67.619 ;
     RECT  27.024 58.691 30.744 68.389 ;
     RECT  2.4 64.981 16.392 68.963 ;
     RECT  2.4 68.963 4.584 69.683 ;
     RECT  5.76 68.963 16.392 71.317 ;
     RECT  17.424 44.531 17.448 71.317 ;
     RECT  18.6 48.371 20.616 71.317 ;
     RECT  18.48 71.317 20.616 71.843 ;
     RECT  5.76 71.317 17.448 72.901 ;
     RECT  18.6 71.843 20.616 72.901 ;
     RECT  32.64 67.237 33.336 73.525 ;
     RECT  34.8 61.571 50.232 73.525 ;
     RECT  0.144 73.621 0.168 73.811 ;
     RECT  5.76 72.901 20.616 75.925 ;
     RECT  2.4 69.683 3.864 76.021 ;
     RECT  5.136 75.925 20.616 76.115 ;
     RECT  2.4 76.021 4.008 76.259 ;
     RECT  5.664 76.115 20.616 77.555 ;
     RECT  27.024 68.389 31.56 77.555 ;
     RECT  5.76 77.555 20.616 78.179 ;
     RECT  5.76 78.179 17.448 86.197 ;
     RECT  21.648 53.795 25.992 91.189 ;
     RECT  32.64 73.525 50.232 91.571 ;
     RECT  5.376 86.197 17.448 92.003 ;
     RECT  27.648 77.555 31.56 92.387 ;
     RECT  32.64 91.571 50.184 92.675 ;
     RECT  32.64 92.675 49.608 94.069 ;
     RECT  52.08 51.109 52.104 96.901 ;
     RECT  32.64 94.069 49.752 97.669 ;
     RECT  5.376 92.003 15.768 98.053 ;
     RECT  32.64 97.669 49.848 98.099 ;
     RECT  43.872 98.099 49.848 98.389 ;
     RECT  2.4 76.259 3.864 98.629 ;
     RECT  43.872 98.389 50.04 98.629 ;
     RECT  1.824 98.629 3.864 98.725 ;
     RECT  16.848 92.003 17.448 98.965 ;
     RECT  18.6 78.179 20.616 98.965 ;
     RECT  5.136 98.053 15.768 99.157 ;
     RECT  16.848 98.965 20.616 99.157 ;
     RECT  21.648 91.189 26.664 99.157 ;
     RECT  27.648 92.387 27.672 99.157 ;
     RECT  28.8 92.387 31.56 99.157 ;
     RECT  32.64 98.099 42.792 99.157 ;
     RECT  43.872 98.629 50.28 99.157 ;
     RECT  1.536 98.725 3.864 99.205 ;
     RECT  5.136 99.157 31.56 99.493 ;
     RECT  32.64 99.157 50.28 99.493 ;
     RECT  5.136 99.493 50.28 99.541 ;
     RECT  0.672 99.205 3.864 99.637 ;
     RECT  4.848 99.541 50.28 99.637 ;
     RECT  0.672 99.637 50.28 99.733 ;
     RECT  51.456 96.901 52.104 99.733 ;
     RECT  0.288 99.733 52.104 100.885 ;
     RECT  0.288 100.885 52.392 103.632 ;
     RECT  4.68 30.707 5.664 31.043 ;
     RECT  4.68 31.043 5.712 31.331 ;
     RECT  4.68 31.331 5.76 32.195 ;
     RECT  3.864 36.421 5.184 36.757 ;
     RECT  3.864 36.757 5.136 36.899 ;
     RECT  3.864 36.899 5.232 36.947 ;
     RECT  4.68 38.485 5.76 38.627 ;
     RECT  4.296 38.627 5.76 39.589 ;
     RECT  4.392 39.589 5.76 39.779 ;
     RECT  16.44 42.851 17.424 43.379 ;
     RECT  16.392 43.379 17.424 71.317 ;
     RECT  4.536 43.813 5.76 45.155 ;
     RECT  17.448 44.531 18.6 71.317 ;
     RECT  3.96 45.155 5.76 45.349 ;
     RECT  3.96 45.349 5.04 45.491 ;
     RECT  3.96 45.491 5.712 45.731 ;
     RECT  3.96 45.731 5.76 46.837 ;
     RECT  3.96 46.837 5.04 47.267 ;
     RECT  3.96 47.267 5.76 47.891 ;
     RECT  3.864 47.891 5.76 48.565 ;
     RECT  20.616 48.371 21.648 99.157 ;
     RECT  3.864 48.565 5.136 48.997 ;
     RECT  1.272 48.997 2.4 49.331 ;
     RECT  3.864 48.997 4.992 49.331 ;
     RECT  1.248 49.331 2.4 50.341 ;
     RECT  1.272 50.341 2.4 50.579 ;
     RECT  3.864 51.061 5.136 51.157 ;
     RECT  3.96 51.157 5.136 51.299 ;
     RECT  3.864 51.299 5.136 52.067 ;
     RECT  3.864 52.067 5.76 52.405 ;
     RECT  4.584 52.405 5.76 53.557 ;
     RECT  25.992 52.547 27.024 53.557 ;
     RECT  1.176 53.749 2.4 53.891 ;
     RECT  25.992 53.795 27.024 77.555 ;
     RECT  0.168 53.845 1.152 53.891 ;
     RECT  30.744 58.691 32.16 59.843 ;
     RECT  4.632 59.267 5.76 60.661 ;
     RECT  4.632 60.947 5.76 62.533 ;
     RECT  33.336 60.995 34.32 61.571 ;
     RECT  33.336 61.571 34.8 73.525 ;
     RECT  0.144 62.483 0.168 63.877 ;
     RECT  4.632 62.675 5.76 64.981 ;
     RECT  31.56 68.389 32.64 99.493 ;
     RECT  4.584 68.963 5.76 69.683 ;
     RECT  17.448 71.317 18.48 71.843 ;
     RECT  17.448 71.843 18.6 72.901 ;
     RECT  3.864 75.925 5.136 76.021 ;
     RECT  4.008 76.021 5.136 76.115 ;
     RECT  17.448 78.179 18.6 98.965 ;
     RECT  3.864 86.197 5.376 98.053 ;
     RECT  26.664 91.189 27.648 99.157 ;
     RECT  15.768 92.003 16.848 99.157 ;
     RECT  27.672 92.387 28.8 99.157 ;
     RECT  49.608 92.675 49.752 94.069 ;
     RECT  3.864 98.053 5.136 99.541 ;
     RECT  42.792 98.099 43.872 99.157 ;
     RECT  50.04 98.389 51.456 98.629 ;
     RECT  50.28 98.629 51.456 99.733 ;
     RECT  3.864 99.541 4.848 99.637 ;
  END
END qfd_xcst_s_m5
END LIBRARY
